<?xml version="1.0" encoding="utf-8" standalone="no"?>
<device schemaVersion="1.1">
  <name>STM32F103x6</name>
  <version>1.0</version>
  <description>STM32F103C4T6,STM32F103C6T6,STM32F103C6U6,STM32F103R4H6,STM32F103R4T6,STM32F103R6H6,STM32F103R6T6,STM32F103T4U6,STM32F103T6U6</description>
  <addressUnitBits>8</addressUnitBits>
  <width>32</width>
  <size>0x20</size>
  <resetValue>0</resetValue>
  <resetMask>0xFFFFFFFF</resetMask>
  <peripherals>
    <peripheral>
      <name>OB</name>
      <baseAddress>0x1ffff800</baseAddress>
      <register>
        <name>RDP</name>
        <addressOffset>0x0</addressOffset>
        <size>0x10</size>
      </register>
      <register>
        <name>USER</name>
        <addressOffset>0x2</addressOffset>
        <size>0x10</size>
      </register>
      <register>
        <name>Data0</name>
        <addressOffset>0x4</addressOffset>
        <size>0x10</size>
      </register>
      <register>
        <name>Data1</name>
        <addressOffset>0x6</addressOffset>
        <size>0x10</size>
      </register>
      <register>
        <name>WRP0</name>
        <addressOffset>0x8</addressOffset>
        <size>0x10</size>
      </register>
      <register>
        <name>WRP1</name>
        <addressOffset>0xa</addressOffset>
        <size>0x10</size>
      </register>
      <register>
        <name>WRP2</name>
        <addressOffset>0xc</addressOffset>
        <size>0x10</size>
      </register>
      <register>
        <name>WRP3</name>
        <addressOffset>0xe</addressOffset>
        <size>0x10</size>
      </register>
    </peripheral>
    <peripheral>
      <name>TIM2</name>
      <baseAddress>0x40000000</baseAddress>
      <register>
        <name>CR1</name>
        <addressOffset>0x0</addressOffset>
        <size>0x20</size>
        <fields>
          <field>
            <name>CEN</name>
            <bitOffset>0</bitOffset>
            <bitWidth>1</bitWidth>
          </field>
          <field>
            <name>UDIS</name>
            <bitOffset>1</bitOffset>
            <bitWidth>1</bitWidth>
          </field>
          <field>
            <name>URS</name>
            <bitOffset>2</bitOffset>
            <bitWidth>1</bitWidth>
          </field>
          <field>
            <name>OPM</name>
            <bitOffset>3</bitOffset>
            <bitWidth>1</bitWidth>
          </field>
          <field>
            <name>DIR</name>
            <bitOffset>4</bitOffset>
            <bitWidth>1</bitWidth>
          </field>
          <field>
            <name>CMS</name>
            <bitOffset>5</bitOffset>
            <bitWidth>2</bitWidth>
          </field>
          <field>
            <name>ARPE</name>
            <bitOffset>7</bitOffset>
            <bitWidth>1</bitWidth>
          </field>
          <field>
            <name>CKD</name>
            <bitOffset>8</bitOffset>
            <bitWidth>2</bitWidth>
          </field>
        </fields>
      </register>
      <register>
        <name>CR2</name>
        <addressOffset>0x4</addressOffset>
        <size>0x20</size>
        <fields>
          <field>
            <name>CCPC</name>
            <bitOffset>0</bitOffset>
            <bitWidth>1</bitWidth>
          </field>
          <field>
            <name>CCUS</name>
            <bitOffset>2</bitOffset>
            <bitWidth>1</bitWidth>
          </field>
          <field>
            <name>CCDS</name>
            <bitOffset>3</bitOffset>
            <bitWidth>1</bitWidth>
          </field>
          <field>
            <name>MMS</name>
            <bitOffset>4</bitOffset>
            <bitWidth>3</bitWidth>
          </field>
          <field>
            <name>TI1S</name>
            <bitOffset>7</bitOffset>
            <bitWidth>1</bitWidth>
          </field>
          <field>
            <name>OIS1</name>
            <bitOffset>8</bitOffset>
            <bitWidth>1</bitWidth>
          </field>
          <field>
            <name>OIS1N</name>
            <bitOffset>9</bitOffset>
            <bitWidth>1</bitWidth>
          </field>
          <field>
            <name>OIS2</name>
            <bitOffset>10</bitOffset>
            <bitWidth>1</bitWidth>
          </field>
          <field>
            <name>OIS2N</name>
            <bitOffset>11</bitOffset>
            <bitWidth>1</bitWidth>
          </field>
          <field>
            <name>OIS3</name>
            <bitOffset>12</bitOffset>
            <bitWidth>1</bitWidth>
          </field>
          <field>
            <name>OIS3N</name>
            <bitOffset>13</bitOffset>
            <bitWidth>1</bitWidth>
          </field>
          <field>
            <name>OIS4</name>
            <bitOffset>14</bitOffset>
            <bitWidth>1</bitWidth>
          </field>
        </fields>
      </register>
      <register>
        <name>SMCR</name>
        <addressOffset>0x8</addressOffset>
        <size>0x20</size>
        <fields>
          <field>
            <name>SMS</name>
            <bitOffset>0</bitOffset>
            <bitWidth>3</bitWidth>
          </field>
          <field>
            <name>TS</name>
            <bitOffset>4</bitOffset>
            <bitWidth>3</bitWidth>
          </field>
          <field>
            <name>MSM</name>
            <bitOffset>7</bitOffset>
            <bitWidth>1</bitWidth>
          </field>
          <field>
            <name>ETF</name>
            <bitOffset>8</bitOffset>
            <bitWidth>4</bitWidth>
          </field>
          <field>
            <name>ETPS</name>
            <bitOffset>12</bitOffset>
            <bitWidth>2</bitWidth>
          </field>
          <field>
            <name>ECE</name>
            <bitOffset>14</bitOffset>
            <bitWidth>1</bitWidth>
          </field>
          <field>
            <name>ETP</name>
            <bitOffset>15</bitOffset>
            <bitWidth>1</bitWidth>
          </field>
        </fields>
      </register>
      <register>
        <name>DIER</name>
        <addressOffset>0xc</addressOffset>
        <size>0x20</size>
        <fields>
          <field>
            <name>UIE</name>
            <bitOffset>0</bitOffset>
            <bitWidth>1</bitWidth>
          </field>
          <field>
            <name>CC1IE</name>
            <bitOffset>1</bitOffset>
            <bitWidth>1</bitWidth>
          </field>
          <field>
            <name>CC2IE</name>
            <bitOffset>2</bitOffset>
            <bitWidth>1</bitWidth>
          </field>
          <field>
            <name>CC3IE</name>
            <bitOffset>3</bitOffset>
            <bitWidth>1</bitWidth>
          </field>
          <field>
            <name>CC4IE</name>
            <bitOffset>4</bitOffset>
            <bitWidth>1</bitWidth>
          </field>
          <field>
            <name>COMIE</name>
            <bitOffset>5</bitOffset>
            <bitWidth>1</bitWidth>
          </field>
          <field>
            <name>TIE</name>
            <bitOffset>6</bitOffset>
            <bitWidth>1</bitWidth>
          </field>
          <field>
            <name>BIE</name>
            <bitOffset>7</bitOffset>
            <bitWidth>1</bitWidth>
          </field>
          <field>
            <name>UDE</name>
            <bitOffset>8</bitOffset>
            <bitWidth>1</bitWidth>
          </field>
          <field>
            <name>CC1DE</name>
            <bitOffset>9</bitOffset>
            <bitWidth>1</bitWidth>
          </field>
          <field>
            <name>CC2DE</name>
            <bitOffset>10</bitOffset>
            <bitWidth>1</bitWidth>
          </field>
          <field>
            <name>CC3DE</name>
            <bitOffset>11</bitOffset>
            <bitWidth>1</bitWidth>
          </field>
          <field>
            <name>CC4DE</name>
            <bitOffset>12</bitOffset>
            <bitWidth>1</bitWidth>
          </field>
          <field>
            <name>COMDE</name>
            <bitOffset>13</bitOffset>
            <bitWidth>1</bitWidth>
          </field>
          <field>
            <name>TDE</name>
            <bitOffset>14</bitOffset>
            <bitWidth>1</bitWidth>
          </field>
        </fields>
      </register>
      <register>
        <name>SR</name>
        <addressOffset>0x10</addressOffset>
        <size>0x20</size>
        <fields>
          <field>
            <name>UIF</name>
            <bitOffset>0</bitOffset>
            <bitWidth>1</bitWidth>
          </field>
          <field>
            <name>CC1IF</name>
            <bitOffset>1</bitOffset>
            <bitWidth>1</bitWidth>
          </field>
          <field>
            <name>CC2IF</name>
            <bitOffset>2</bitOffset>
            <bitWidth>1</bitWidth>
          </field>
          <field>
            <name>CC3IF</name>
            <bitOffset>3</bitOffset>
            <bitWidth>1</bitWidth>
          </field>
          <field>
            <name>CC4IF</name>
            <bitOffset>4</bitOffset>
            <bitWidth>1</bitWidth>
          </field>
          <field>
            <name>COMIF</name>
            <bitOffset>5</bitOffset>
            <bitWidth>1</bitWidth>
          </field>
          <field>
            <name>TIF</name>
            <bitOffset>6</bitOffset>
            <bitWidth>1</bitWidth>
          </field>
          <field>
            <name>BIF</name>
            <bitOffset>7</bitOffset>
            <bitWidth>1</bitWidth>
          </field>
          <field>
            <name>CC1OF</name>
            <bitOffset>9</bitOffset>
            <bitWidth>1</bitWidth>
          </field>
          <field>
            <name>CC2OF</name>
            <bitOffset>10</bitOffset>
            <bitWidth>1</bitWidth>
          </field>
          <field>
            <name>CC3OF</name>
            <bitOffset>11</bitOffset>
            <bitWidth>1</bitWidth>
          </field>
          <field>
            <name>CC4OF</name>
            <bitOffset>12</bitOffset>
            <bitWidth>1</bitWidth>
          </field>
        </fields>
      </register>
      <register>
        <name>EGR</name>
        <addressOffset>0x14</addressOffset>
        <size>0x20</size>
        <fields>
          <field>
            <name>UG</name>
            <bitOffset>0</bitOffset>
            <bitWidth>1</bitWidth>
          </field>
          <field>
            <name>CC1G</name>
            <bitOffset>1</bitOffset>
            <bitWidth>1</bitWidth>
          </field>
          <field>
            <name>CC2G</name>
            <bitOffset>2</bitOffset>
            <bitWidth>1</bitWidth>
          </field>
          <field>
            <name>CC3G</name>
            <bitOffset>3</bitOffset>
            <bitWidth>1</bitWidth>
          </field>
          <field>
            <name>CC4G</name>
            <bitOffset>4</bitOffset>
            <bitWidth>1</bitWidth>
          </field>
          <field>
            <name>COMG</name>
            <bitOffset>5</bitOffset>
            <bitWidth>1</bitWidth>
          </field>
          <field>
            <name>TG</name>
            <bitOffset>6</bitOffset>
            <bitWidth>1</bitWidth>
          </field>
          <field>
            <name>BG</name>
            <bitOffset>7</bitOffset>
            <bitWidth>1</bitWidth>
          </field>
        </fields>
      </register>
      <register>
        <name>CCMR1</name>
        <addressOffset>0x18</addressOffset>
        <size>0x20</size>
        <fields>
          <field>
            <name>CC1S</name>
            <bitOffset>0</bitOffset>
            <bitWidth>2</bitWidth>
          </field>
          <field>
            <name>OC1FE</name>
            <bitOffset>2</bitOffset>
            <bitWidth>1</bitWidth>
          </field>
          <field>
            <name>OC1PE</name>
            <bitOffset>3</bitOffset>
            <bitWidth>1</bitWidth>
          </field>
          <field>
            <name>OC1M</name>
            <bitOffset>4</bitOffset>
            <bitWidth>3</bitWidth>
          </field>
          <field>
            <name>OC1CE</name>
            <bitOffset>7</bitOffset>
            <bitWidth>1</bitWidth>
          </field>
          <field>
            <name>CC2S</name>
            <bitOffset>8</bitOffset>
            <bitWidth>2</bitWidth>
          </field>
          <field>
            <name>OC2FE</name>
            <bitOffset>10</bitOffset>
            <bitWidth>1</bitWidth>
          </field>
          <field>
            <name>OC2PE</name>
            <bitOffset>11</bitOffset>
            <bitWidth>1</bitWidth>
          </field>
          <field>
            <name>OC2M</name>
            <bitOffset>12</bitOffset>
            <bitWidth>3</bitWidth>
          </field>
          <field>
            <name>OC2CE</name>
            <bitOffset>15</bitOffset>
            <bitWidth>1</bitWidth>
          </field>
        </fields>
      </register>
      <register>
        <name>CCMR2</name>
        <addressOffset>0x1c</addressOffset>
        <size>0x20</size>
        <fields>
          <field>
            <name>CC3S</name>
            <bitOffset>0</bitOffset>
            <bitWidth>2</bitWidth>
          </field>
          <field>
            <name>OC3FE</name>
            <bitOffset>2</bitOffset>
            <bitWidth>1</bitWidth>
          </field>
          <field>
            <name>OC3PE</name>
            <bitOffset>3</bitOffset>
            <bitWidth>1</bitWidth>
          </field>
          <field>
            <name>OC3M</name>
            <bitOffset>4</bitOffset>
            <bitWidth>3</bitWidth>
          </field>
          <field>
            <name>OC3CE</name>
            <bitOffset>7</bitOffset>
            <bitWidth>1</bitWidth>
          </field>
          <field>
            <name>CC4S</name>
            <bitOffset>8</bitOffset>
            <bitWidth>2</bitWidth>
          </field>
          <field>
            <name>OC4FE</name>
            <bitOffset>10</bitOffset>
            <bitWidth>1</bitWidth>
          </field>
          <field>
            <name>OC4PE</name>
            <bitOffset>11</bitOffset>
            <bitWidth>1</bitWidth>
          </field>
          <field>
            <name>OC4M</name>
            <bitOffset>12</bitOffset>
            <bitWidth>3</bitWidth>
          </field>
          <field>
            <name>OC4CE</name>
            <bitOffset>15</bitOffset>
            <bitWidth>1</bitWidth>
          </field>
        </fields>
      </register>
      <register>
        <name>CCER</name>
        <addressOffset>0x20</addressOffset>
        <size>0x20</size>
        <fields>
          <field>
            <name>CC1E</name>
            <bitOffset>0</bitOffset>
            <bitWidth>1</bitWidth>
          </field>
          <field>
            <name>CC1P</name>
            <bitOffset>1</bitOffset>
            <bitWidth>1</bitWidth>
          </field>
          <field>
            <name>CC1NE</name>
            <bitOffset>2</bitOffset>
            <bitWidth>1</bitWidth>
          </field>
          <field>
            <name>CC1NP</name>
            <bitOffset>3</bitOffset>
            <bitWidth>1</bitWidth>
          </field>
          <field>
            <name>CC2E</name>
            <bitOffset>4</bitOffset>
            <bitWidth>1</bitWidth>
          </field>
          <field>
            <name>CC2P</name>
            <bitOffset>5</bitOffset>
            <bitWidth>1</bitWidth>
          </field>
          <field>
            <name>CC2NE</name>
            <bitOffset>6</bitOffset>
            <bitWidth>1</bitWidth>
          </field>
          <field>
            <name>CC2NP</name>
            <bitOffset>7</bitOffset>
            <bitWidth>1</bitWidth>
          </field>
          <field>
            <name>CC3E</name>
            <bitOffset>8</bitOffset>
            <bitWidth>1</bitWidth>
          </field>
          <field>
            <name>CC3P</name>
            <bitOffset>9</bitOffset>
            <bitWidth>1</bitWidth>
          </field>
          <field>
            <name>CC3NE</name>
            <bitOffset>10</bitOffset>
            <bitWidth>1</bitWidth>
          </field>
          <field>
            <name>CC3NP</name>
            <bitOffset>11</bitOffset>
            <bitWidth>1</bitWidth>
          </field>
          <field>
            <name>CC4E</name>
            <bitOffset>12</bitOffset>
            <bitWidth>1</bitWidth>
          </field>
          <field>
            <name>CC4P</name>
            <bitOffset>13</bitOffset>
            <bitWidth>1</bitWidth>
          </field>
        </fields>
      </register>
      <register>
        <name>CNT</name>
        <addressOffset>0x24</addressOffset>
        <size>0x20</size>
        <fields>
          <field>
            <name>CNT</name>
            <bitOffset>0</bitOffset>
            <bitWidth>32</bitWidth>
          </field>
        </fields>
      </register>
      <register>
        <name>PSC</name>
        <addressOffset>0x28</addressOffset>
        <size>0x20</size>
        <fields>
          <field>
            <name>PSC</name>
            <bitOffset>0</bitOffset>
            <bitWidth>16</bitWidth>
          </field>
        </fields>
      </register>
      <register>
        <name>ARR</name>
        <addressOffset>0x2c</addressOffset>
        <size>0x20</size>
        <fields>
          <field>
            <name>ARR</name>
            <bitOffset>0</bitOffset>
            <bitWidth>32</bitWidth>
          </field>
        </fields>
      </register>
      <register>
        <name>RCR</name>
        <addressOffset>0x30</addressOffset>
        <size>0x20</size>
        <fields>
          <field>
            <name>REP</name>
            <bitOffset>0</bitOffset>
            <bitWidth>8</bitWidth>
          </field>
        </fields>
      </register>
      <register>
        <name>CCR1</name>
        <addressOffset>0x34</addressOffset>
        <size>0x20</size>
        <fields>
          <field>
            <name>CCR1</name>
            <bitOffset>0</bitOffset>
            <bitWidth>16</bitWidth>
          </field>
        </fields>
      </register>
      <register>
        <name>CCR2</name>
        <addressOffset>0x38</addressOffset>
        <size>0x20</size>
        <fields>
          <field>
            <name>CCR2</name>
            <bitOffset>0</bitOffset>
            <bitWidth>16</bitWidth>
          </field>
        </fields>
      </register>
      <register>
        <name>CCR3</name>
        <addressOffset>0x3c</addressOffset>
        <size>0x20</size>
        <fields>
          <field>
            <name>CCR3</name>
            <bitOffset>0</bitOffset>
            <bitWidth>16</bitWidth>
          </field>
        </fields>
      </register>
      <register>
        <name>CCR4</name>
        <addressOffset>0x40</addressOffset>
        <size>0x20</size>
        <fields>
          <field>
            <name>CCR4</name>
            <bitOffset>0</bitOffset>
            <bitWidth>16</bitWidth>
          </field>
        </fields>
      </register>
      <register>
        <name>BDTR</name>
        <addressOffset>0x44</addressOffset>
        <size>0x20</size>
        <fields>
          <field>
            <name>DTG</name>
            <bitOffset>0</bitOffset>
            <bitWidth>8</bitWidth>
          </field>
          <field>
            <name>LOCK</name>
            <bitOffset>8</bitOffset>
            <bitWidth>2</bitWidth>
          </field>
          <field>
            <name>OSSI</name>
            <bitOffset>10</bitOffset>
            <bitWidth>1</bitWidth>
          </field>
          <field>
            <name>OSSR</name>
            <bitOffset>11</bitOffset>
            <bitWidth>1</bitWidth>
          </field>
          <field>
            <name>BKE</name>
            <bitOffset>12</bitOffset>
            <bitWidth>1</bitWidth>
          </field>
          <field>
            <name>BKP</name>
            <bitOffset>13</bitOffset>
            <bitWidth>1</bitWidth>
          </field>
          <field>
            <name>AOE</name>
            <bitOffset>14</bitOffset>
            <bitWidth>1</bitWidth>
          </field>
          <field>
            <name>MOE</name>
            <bitOffset>15</bitOffset>
            <bitWidth>1</bitWidth>
          </field>
        </fields>
      </register>
      <register>
        <name>DCR</name>
        <addressOffset>0x48</addressOffset>
        <size>0x20</size>
        <fields>
          <field>
            <name>DBA</name>
            <bitOffset>0</bitOffset>
            <bitWidth>5</bitWidth>
          </field>
          <field>
            <name>DBL</name>
            <bitOffset>8</bitOffset>
            <bitWidth>5</bitWidth>
          </field>
        </fields>
      </register>
      <register>
        <name>DMAR</name>
        <addressOffset>0x4c</addressOffset>
        <size>0x20</size>
        <fields>
          <field>
            <name>DMAB</name>
            <bitOffset>0</bitOffset>
            <bitWidth>16</bitWidth>
          </field>
        </fields>
      </register>
      <register>
        <name>OR</name>
        <addressOffset>0x50</addressOffset>
        <size>0x20</size>
      </register>
    </peripheral>
    <peripheral>
      <name>TIM3</name>
      <baseAddress>0x40000400</baseAddress>
      <register>
        <name>CR1</name>
        <addressOffset>0x0</addressOffset>
        <size>0x20</size>
        <fields>
          <field>
            <name>CEN</name>
            <bitOffset>0</bitOffset>
            <bitWidth>1</bitWidth>
          </field>
          <field>
            <name>UDIS</name>
            <bitOffset>1</bitOffset>
            <bitWidth>1</bitWidth>
          </field>
          <field>
            <name>URS</name>
            <bitOffset>2</bitOffset>
            <bitWidth>1</bitWidth>
          </field>
          <field>
            <name>OPM</name>
            <bitOffset>3</bitOffset>
            <bitWidth>1</bitWidth>
          </field>
          <field>
            <name>DIR</name>
            <bitOffset>4</bitOffset>
            <bitWidth>1</bitWidth>
          </field>
          <field>
            <name>CMS</name>
            <bitOffset>5</bitOffset>
            <bitWidth>2</bitWidth>
          </field>
          <field>
            <name>ARPE</name>
            <bitOffset>7</bitOffset>
            <bitWidth>1</bitWidth>
          </field>
          <field>
            <name>CKD</name>
            <bitOffset>8</bitOffset>
            <bitWidth>2</bitWidth>
          </field>
        </fields>
      </register>
      <register>
        <name>CR2</name>
        <addressOffset>0x4</addressOffset>
        <size>0x20</size>
        <fields>
          <field>
            <name>CCPC</name>
            <bitOffset>0</bitOffset>
            <bitWidth>1</bitWidth>
          </field>
          <field>
            <name>CCUS</name>
            <bitOffset>2</bitOffset>
            <bitWidth>1</bitWidth>
          </field>
          <field>
            <name>CCDS</name>
            <bitOffset>3</bitOffset>
            <bitWidth>1</bitWidth>
          </field>
          <field>
            <name>MMS</name>
            <bitOffset>4</bitOffset>
            <bitWidth>3</bitWidth>
          </field>
          <field>
            <name>TI1S</name>
            <bitOffset>7</bitOffset>
            <bitWidth>1</bitWidth>
          </field>
          <field>
            <name>OIS1</name>
            <bitOffset>8</bitOffset>
            <bitWidth>1</bitWidth>
          </field>
          <field>
            <name>OIS1N</name>
            <bitOffset>9</bitOffset>
            <bitWidth>1</bitWidth>
          </field>
          <field>
            <name>OIS2</name>
            <bitOffset>10</bitOffset>
            <bitWidth>1</bitWidth>
          </field>
          <field>
            <name>OIS2N</name>
            <bitOffset>11</bitOffset>
            <bitWidth>1</bitWidth>
          </field>
          <field>
            <name>OIS3</name>
            <bitOffset>12</bitOffset>
            <bitWidth>1</bitWidth>
          </field>
          <field>
            <name>OIS3N</name>
            <bitOffset>13</bitOffset>
            <bitWidth>1</bitWidth>
          </field>
          <field>
            <name>OIS4</name>
            <bitOffset>14</bitOffset>
            <bitWidth>1</bitWidth>
          </field>
        </fields>
      </register>
      <register>
        <name>SMCR</name>
        <addressOffset>0x8</addressOffset>
        <size>0x20</size>
        <fields>
          <field>
            <name>SMS</name>
            <bitOffset>0</bitOffset>
            <bitWidth>3</bitWidth>
          </field>
          <field>
            <name>TS</name>
            <bitOffset>4</bitOffset>
            <bitWidth>3</bitWidth>
          </field>
          <field>
            <name>MSM</name>
            <bitOffset>7</bitOffset>
            <bitWidth>1</bitWidth>
          </field>
          <field>
            <name>ETF</name>
            <bitOffset>8</bitOffset>
            <bitWidth>4</bitWidth>
          </field>
          <field>
            <name>ETPS</name>
            <bitOffset>12</bitOffset>
            <bitWidth>2</bitWidth>
          </field>
          <field>
            <name>ECE</name>
            <bitOffset>14</bitOffset>
            <bitWidth>1</bitWidth>
          </field>
          <field>
            <name>ETP</name>
            <bitOffset>15</bitOffset>
            <bitWidth>1</bitWidth>
          </field>
        </fields>
      </register>
      <register>
        <name>DIER</name>
        <addressOffset>0xc</addressOffset>
        <size>0x20</size>
        <fields>
          <field>
            <name>UIE</name>
            <bitOffset>0</bitOffset>
            <bitWidth>1</bitWidth>
          </field>
          <field>
            <name>CC1IE</name>
            <bitOffset>1</bitOffset>
            <bitWidth>1</bitWidth>
          </field>
          <field>
            <name>CC2IE</name>
            <bitOffset>2</bitOffset>
            <bitWidth>1</bitWidth>
          </field>
          <field>
            <name>CC3IE</name>
            <bitOffset>3</bitOffset>
            <bitWidth>1</bitWidth>
          </field>
          <field>
            <name>CC4IE</name>
            <bitOffset>4</bitOffset>
            <bitWidth>1</bitWidth>
          </field>
          <field>
            <name>COMIE</name>
            <bitOffset>5</bitOffset>
            <bitWidth>1</bitWidth>
          </field>
          <field>
            <name>TIE</name>
            <bitOffset>6</bitOffset>
            <bitWidth>1</bitWidth>
          </field>
          <field>
            <name>BIE</name>
            <bitOffset>7</bitOffset>
            <bitWidth>1</bitWidth>
          </field>
          <field>
            <name>UDE</name>
            <bitOffset>8</bitOffset>
            <bitWidth>1</bitWidth>
          </field>
          <field>
            <name>CC1DE</name>
            <bitOffset>9</bitOffset>
            <bitWidth>1</bitWidth>
          </field>
          <field>
            <name>CC2DE</name>
            <bitOffset>10</bitOffset>
            <bitWidth>1</bitWidth>
          </field>
          <field>
            <name>CC3DE</name>
            <bitOffset>11</bitOffset>
            <bitWidth>1</bitWidth>
          </field>
          <field>
            <name>CC4DE</name>
            <bitOffset>12</bitOffset>
            <bitWidth>1</bitWidth>
          </field>
          <field>
            <name>COMDE</name>
            <bitOffset>13</bitOffset>
            <bitWidth>1</bitWidth>
          </field>
          <field>
            <name>TDE</name>
            <bitOffset>14</bitOffset>
            <bitWidth>1</bitWidth>
          </field>
        </fields>
      </register>
      <register>
        <name>SR</name>
        <addressOffset>0x10</addressOffset>
        <size>0x20</size>
        <fields>
          <field>
            <name>UIF</name>
            <bitOffset>0</bitOffset>
            <bitWidth>1</bitWidth>
          </field>
          <field>
            <name>CC1IF</name>
            <bitOffset>1</bitOffset>
            <bitWidth>1</bitWidth>
          </field>
          <field>
            <name>CC2IF</name>
            <bitOffset>2</bitOffset>
            <bitWidth>1</bitWidth>
          </field>
          <field>
            <name>CC3IF</name>
            <bitOffset>3</bitOffset>
            <bitWidth>1</bitWidth>
          </field>
          <field>
            <name>CC4IF</name>
            <bitOffset>4</bitOffset>
            <bitWidth>1</bitWidth>
          </field>
          <field>
            <name>COMIF</name>
            <bitOffset>5</bitOffset>
            <bitWidth>1</bitWidth>
          </field>
          <field>
            <name>TIF</name>
            <bitOffset>6</bitOffset>
            <bitWidth>1</bitWidth>
          </field>
          <field>
            <name>BIF</name>
            <bitOffset>7</bitOffset>
            <bitWidth>1</bitWidth>
          </field>
          <field>
            <name>CC1OF</name>
            <bitOffset>9</bitOffset>
            <bitWidth>1</bitWidth>
          </field>
          <field>
            <name>CC2OF</name>
            <bitOffset>10</bitOffset>
            <bitWidth>1</bitWidth>
          </field>
          <field>
            <name>CC3OF</name>
            <bitOffset>11</bitOffset>
            <bitWidth>1</bitWidth>
          </field>
          <field>
            <name>CC4OF</name>
            <bitOffset>12</bitOffset>
            <bitWidth>1</bitWidth>
          </field>
        </fields>
      </register>
      <register>
        <name>EGR</name>
        <addressOffset>0x14</addressOffset>
        <size>0x20</size>
        <fields>
          <field>
            <name>UG</name>
            <bitOffset>0</bitOffset>
            <bitWidth>1</bitWidth>
          </field>
          <field>
            <name>CC1G</name>
            <bitOffset>1</bitOffset>
            <bitWidth>1</bitWidth>
          </field>
          <field>
            <name>CC2G</name>
            <bitOffset>2</bitOffset>
            <bitWidth>1</bitWidth>
          </field>
          <field>
            <name>CC3G</name>
            <bitOffset>3</bitOffset>
            <bitWidth>1</bitWidth>
          </field>
          <field>
            <name>CC4G</name>
            <bitOffset>4</bitOffset>
            <bitWidth>1</bitWidth>
          </field>
          <field>
            <name>COMG</name>
            <bitOffset>5</bitOffset>
            <bitWidth>1</bitWidth>
          </field>
          <field>
            <name>TG</name>
            <bitOffset>6</bitOffset>
            <bitWidth>1</bitWidth>
          </field>
          <field>
            <name>BG</name>
            <bitOffset>7</bitOffset>
            <bitWidth>1</bitWidth>
          </field>
        </fields>
      </register>
      <register>
        <name>CCMR1</name>
        <addressOffset>0x18</addressOffset>
        <size>0x20</size>
        <fields>
          <field>
            <name>CC1S</name>
            <bitOffset>0</bitOffset>
            <bitWidth>2</bitWidth>
          </field>
          <field>
            <name>OC1FE</name>
            <bitOffset>2</bitOffset>
            <bitWidth>1</bitWidth>
          </field>
          <field>
            <name>OC1PE</name>
            <bitOffset>3</bitOffset>
            <bitWidth>1</bitWidth>
          </field>
          <field>
            <name>OC1M</name>
            <bitOffset>4</bitOffset>
            <bitWidth>3</bitWidth>
          </field>
          <field>
            <name>OC1CE</name>
            <bitOffset>7</bitOffset>
            <bitWidth>1</bitWidth>
          </field>
          <field>
            <name>CC2S</name>
            <bitOffset>8</bitOffset>
            <bitWidth>2</bitWidth>
          </field>
          <field>
            <name>OC2FE</name>
            <bitOffset>10</bitOffset>
            <bitWidth>1</bitWidth>
          </field>
          <field>
            <name>OC2PE</name>
            <bitOffset>11</bitOffset>
            <bitWidth>1</bitWidth>
          </field>
          <field>
            <name>OC2M</name>
            <bitOffset>12</bitOffset>
            <bitWidth>3</bitWidth>
          </field>
          <field>
            <name>OC2CE</name>
            <bitOffset>15</bitOffset>
            <bitWidth>1</bitWidth>
          </field>
        </fields>
      </register>
      <register>
        <name>CCMR2</name>
        <addressOffset>0x1c</addressOffset>
        <size>0x20</size>
        <fields>
          <field>
            <name>CC3S</name>
            <bitOffset>0</bitOffset>
            <bitWidth>2</bitWidth>
          </field>
          <field>
            <name>OC3FE</name>
            <bitOffset>2</bitOffset>
            <bitWidth>1</bitWidth>
          </field>
          <field>
            <name>OC3PE</name>
            <bitOffset>3</bitOffset>
            <bitWidth>1</bitWidth>
          </field>
          <field>
            <name>OC3M</name>
            <bitOffset>4</bitOffset>
            <bitWidth>3</bitWidth>
          </field>
          <field>
            <name>OC3CE</name>
            <bitOffset>7</bitOffset>
            <bitWidth>1</bitWidth>
          </field>
          <field>
            <name>CC4S</name>
            <bitOffset>8</bitOffset>
            <bitWidth>2</bitWidth>
          </field>
          <field>
            <name>OC4FE</name>
            <bitOffset>10</bitOffset>
            <bitWidth>1</bitWidth>
          </field>
          <field>
            <name>OC4PE</name>
            <bitOffset>11</bitOffset>
            <bitWidth>1</bitWidth>
          </field>
          <field>
            <name>OC4M</name>
            <bitOffset>12</bitOffset>
            <bitWidth>3</bitWidth>
          </field>
          <field>
            <name>OC4CE</name>
            <bitOffset>15</bitOffset>
            <bitWidth>1</bitWidth>
          </field>
        </fields>
      </register>
      <register>
        <name>CCER</name>
        <addressOffset>0x20</addressOffset>
        <size>0x20</size>
        <fields>
          <field>
            <name>CC1E</name>
            <bitOffset>0</bitOffset>
            <bitWidth>1</bitWidth>
          </field>
          <field>
            <name>CC1P</name>
            <bitOffset>1</bitOffset>
            <bitWidth>1</bitWidth>
          </field>
          <field>
            <name>CC1NE</name>
            <bitOffset>2</bitOffset>
            <bitWidth>1</bitWidth>
          </field>
          <field>
            <name>CC1NP</name>
            <bitOffset>3</bitOffset>
            <bitWidth>1</bitWidth>
          </field>
          <field>
            <name>CC2E</name>
            <bitOffset>4</bitOffset>
            <bitWidth>1</bitWidth>
          </field>
          <field>
            <name>CC2P</name>
            <bitOffset>5</bitOffset>
            <bitWidth>1</bitWidth>
          </field>
          <field>
            <name>CC2NE</name>
            <bitOffset>6</bitOffset>
            <bitWidth>1</bitWidth>
          </field>
          <field>
            <name>CC2NP</name>
            <bitOffset>7</bitOffset>
            <bitWidth>1</bitWidth>
          </field>
          <field>
            <name>CC3E</name>
            <bitOffset>8</bitOffset>
            <bitWidth>1</bitWidth>
          </field>
          <field>
            <name>CC3P</name>
            <bitOffset>9</bitOffset>
            <bitWidth>1</bitWidth>
          </field>
          <field>
            <name>CC3NE</name>
            <bitOffset>10</bitOffset>
            <bitWidth>1</bitWidth>
          </field>
          <field>
            <name>CC3NP</name>
            <bitOffset>11</bitOffset>
            <bitWidth>1</bitWidth>
          </field>
          <field>
            <name>CC4E</name>
            <bitOffset>12</bitOffset>
            <bitWidth>1</bitWidth>
          </field>
          <field>
            <name>CC4P</name>
            <bitOffset>13</bitOffset>
            <bitWidth>1</bitWidth>
          </field>
        </fields>
      </register>
      <register>
        <name>CNT</name>
        <addressOffset>0x24</addressOffset>
        <size>0x20</size>
        <fields>
          <field>
            <name>CNT</name>
            <bitOffset>0</bitOffset>
            <bitWidth>32</bitWidth>
          </field>
        </fields>
      </register>
      <register>
        <name>PSC</name>
        <addressOffset>0x28</addressOffset>
        <size>0x20</size>
        <fields>
          <field>
            <name>PSC</name>
            <bitOffset>0</bitOffset>
            <bitWidth>16</bitWidth>
          </field>
        </fields>
      </register>
      <register>
        <name>ARR</name>
        <addressOffset>0x2c</addressOffset>
        <size>0x20</size>
        <fields>
          <field>
            <name>ARR</name>
            <bitOffset>0</bitOffset>
            <bitWidth>32</bitWidth>
          </field>
        </fields>
      </register>
      <register>
        <name>RCR</name>
        <addressOffset>0x30</addressOffset>
        <size>0x20</size>
        <fields>
          <field>
            <name>REP</name>
            <bitOffset>0</bitOffset>
            <bitWidth>8</bitWidth>
          </field>
        </fields>
      </register>
      <register>
        <name>CCR1</name>
        <addressOffset>0x34</addressOffset>
        <size>0x20</size>
        <fields>
          <field>
            <name>CCR1</name>
            <bitOffset>0</bitOffset>
            <bitWidth>16</bitWidth>
          </field>
        </fields>
      </register>
      <register>
        <name>CCR2</name>
        <addressOffset>0x38</addressOffset>
        <size>0x20</size>
        <fields>
          <field>
            <name>CCR2</name>
            <bitOffset>0</bitOffset>
            <bitWidth>16</bitWidth>
          </field>
        </fields>
      </register>
      <register>
        <name>CCR3</name>
        <addressOffset>0x3c</addressOffset>
        <size>0x20</size>
        <fields>
          <field>
            <name>CCR3</name>
            <bitOffset>0</bitOffset>
            <bitWidth>16</bitWidth>
          </field>
        </fields>
      </register>
      <register>
        <name>CCR4</name>
        <addressOffset>0x40</addressOffset>
        <size>0x20</size>
        <fields>
          <field>
            <name>CCR4</name>
            <bitOffset>0</bitOffset>
            <bitWidth>16</bitWidth>
          </field>
        </fields>
      </register>
      <register>
        <name>BDTR</name>
        <addressOffset>0x44</addressOffset>
        <size>0x20</size>
        <fields>
          <field>
            <name>DTG</name>
            <bitOffset>0</bitOffset>
            <bitWidth>8</bitWidth>
          </field>
          <field>
            <name>LOCK</name>
            <bitOffset>8</bitOffset>
            <bitWidth>2</bitWidth>
          </field>
          <field>
            <name>OSSI</name>
            <bitOffset>10</bitOffset>
            <bitWidth>1</bitWidth>
          </field>
          <field>
            <name>OSSR</name>
            <bitOffset>11</bitOffset>
            <bitWidth>1</bitWidth>
          </field>
          <field>
            <name>BKE</name>
            <bitOffset>12</bitOffset>
            <bitWidth>1</bitWidth>
          </field>
          <field>
            <name>BKP</name>
            <bitOffset>13</bitOffset>
            <bitWidth>1</bitWidth>
          </field>
          <field>
            <name>AOE</name>
            <bitOffset>14</bitOffset>
            <bitWidth>1</bitWidth>
          </field>
          <field>
            <name>MOE</name>
            <bitOffset>15</bitOffset>
            <bitWidth>1</bitWidth>
          </field>
        </fields>
      </register>
      <register>
        <name>DCR</name>
        <addressOffset>0x48</addressOffset>
        <size>0x20</size>
        <fields>
          <field>
            <name>DBA</name>
            <bitOffset>0</bitOffset>
            <bitWidth>5</bitWidth>
          </field>
          <field>
            <name>DBL</name>
            <bitOffset>8</bitOffset>
            <bitWidth>5</bitWidth>
          </field>
        </fields>
      </register>
      <register>
        <name>DMAR</name>
        <addressOffset>0x4c</addressOffset>
        <size>0x20</size>
        <fields>
          <field>
            <name>DMAB</name>
            <bitOffset>0</bitOffset>
            <bitWidth>16</bitWidth>
          </field>
        </fields>
      </register>
      <register>
        <name>OR</name>
        <addressOffset>0x50</addressOffset>
        <size>0x20</size>
      </register>
    </peripheral>
    <peripheral>
      <name>RTC</name>
      <baseAddress>0x40002800</baseAddress>
      <register>
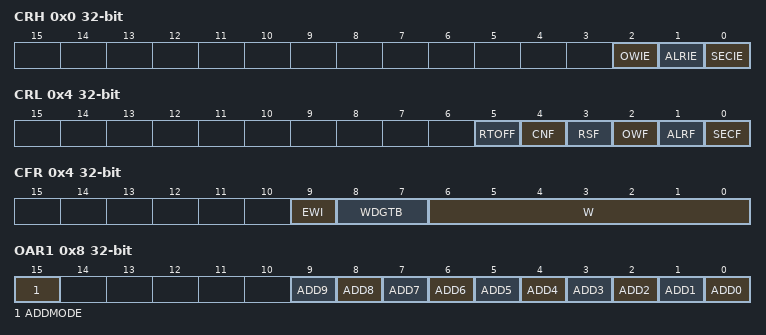
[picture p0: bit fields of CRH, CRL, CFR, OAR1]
        <name>CRH</name>
        <addressOffset>0x0</addressOffset>
        <size>0x20</size>
        <fields>
          <field>
            <name>SECIE</name>
            <bitOffset>0</bitOffset>
            <bitWidth>1</bitWidth>
          </field>
          <field>
            <name>ALRIE</name>
            <bitOffset>1</bitOffset>
            <bitWidth>1</bitWidth>
          </field>
          <field>
            <name>OWIE</name>
            <bitOffset>2</bitOffset>
            <bitWidth>1</bitWidth>
          </field>
        </fields>
      </register>
      <register>
        <name>CRL</name>
        <addressOffset>0x4</addressOffset>
        <size>0x20</size>
        <fields>
          <field>
            <name>SECF</name>
            <bitOffset>0</bitOffset>
            <bitWidth>1</bitWidth>
          </field>
          <field>
            <name>ALRF</name>
            <bitOffset>1</bitOffset>
            <bitWidth>1</bitWidth>
          </field>
          <field>
            <name>OWF</name>
            <bitOffset>2</bitOffset>
            <bitWidth>1</bitWidth>
          </field>
          <field>
            <name>RSF</name>
            <bitOffset>3</bitOffset>
            <bitWidth>1</bitWidth>
          </field>
          <field>
            <name>CNF</name>
            <bitOffset>4</bitOffset>
            <bitWidth>1</bitWidth>
          </field>
          <field>
            <name>RTOFF</name>
            <bitOffset>5</bitOffset>
            <bitWidth>1</bitWidth>
          </field>
        </fields>
      </register>
      <register>
        <name>PRLH</name>
        <addressOffset>0x8</addressOffset>
        <size>0x20</size>
        <fields>
          <field>
            <name>PRL</name>
            <bitOffset>0</bitOffset>
            <bitWidth>4</bitWidth>
          </field>
        </fields>
      </register>
      <register>
        <name>PRLL</name>
        <addressOffset>0xc</addressOffset>
        <size>0x20</size>
        <fields>
          <field>
            <name>PRL</name>
            <bitOffset>0</bitOffset>
            <bitWidth>16</bitWidth>
          </field>
        </fields>
      </register>
      <register>
        <name>DIVH</name>
        <addressOffset>0x10</addressOffset>
        <size>0x20</size>
        <fields>
          <field>
            <name>RTC_DIV</name>
            <bitOffset>0</bitOffset>
            <bitWidth>4</bitWidth>
          </field>
        </fields>
      </register>
      <register>
        <name>DIVL</name>
        <addressOffset>0x14</addressOffset>
        <size>0x20</size>
        <fields>
          <field>
            <name>RTC_DIV</name>
            <bitOffset>0</bitOffset>
            <bitWidth>16</bitWidth>
          </field>
        </fields>
      </register>
      <register>
        <name>CNTH</name>
        <addressOffset>0x18</addressOffset>
        <size>0x20</size>
        <fields>
          <field>
            <name>RTC_CNT</name>
            <bitOffset>0</bitOffset>
            <bitWidth>16</bitWidth>
          </field>
        </fields>
      </register>
      <register>
        <name>CNTL</name>
        <addressOffset>0x1c</addressOffset>
        <size>0x20</size>
        <fields>
          <field>
            <name>RTC_CNT</name>
            <bitOffset>0</bitOffset>
            <bitWidth>16</bitWidth>
          </field>
        </fields>
      </register>
      <register>
        <name>ALRH</name>
        <addressOffset>0x20</addressOffset>
        <size>0x20</size>
        <fields>
          <field>
            <name>RTC_ALR</name>
            <bitOffset>0</bitOffset>
            <bitWidth>16</bitWidth>
          </field>
        </fields>
      </register>
      <register>
        <name>ALRL</name>
        <addressOffset>0x24</addressOffset>
        <size>0x20</size>
        <fields>
          <field>
            <name>RTC_ALR</name>
            <bitOffset>0</bitOffset>
            <bitWidth>16</bitWidth>
          </field>
        </fields>
      </register>
    </peripheral>
    <peripheral>
      <name>WWDG</name>
      <baseAddress>0x40002c00</baseAddress>
      <register>
        <name>CR</name>
        <addressOffset>0x0</addressOffset>
        <size>0x20</size>
        <fields>
          <field>
            <name>T</name>
            <bitOffset>0</bitOffset>
            <bitWidth>7</bitWidth>
          </field>
          <field>
            <name>WDGA</name>
            <bitOffset>7</bitOffset>
            <bitWidth>1</bitWidth>
          </field>
        </fields>
      </register>
      <register>
        <name>CFR</name>
        <addressOffset>0x4</addressOffset>
        <size>0x20</size>
        <fields>
          <field>
            <name>W</name>
            <bitOffset>0</bitOffset>
            <bitWidth>7</bitWidth>
          </field>
          <field>
            <name>WDGTB</name>
            <bitOffset>7</bitOffset>
            <bitWidth>2</bitWidth>
          </field>
          <field>
            <name>EWI</name>
            <bitOffset>9</bitOffset>
            <bitWidth>1</bitWidth>
          </field>
        </fields>
      </register>
      <register>
        <name>SR</name>
        <addressOffset>0x8</addressOffset>
        <size>0x20</size>
        <fields>
          <field>
            <name>EWIF</name>
            <bitOffset>0</bitOffset>
            <bitWidth>1</bitWidth>
          </field>
        </fields>
      </register>
    </peripheral>
    <peripheral>
      <name>IWDG</name>
      <baseAddress>0x40003000</baseAddress>
      <register>
        <name>KR</name>
        <addressOffset>0x0</addressOffset>
        <size>0x20</size>
        <fields>
          <field>
            <name>KEY</name>
            <bitOffset>0</bitOffset>
            <bitWidth>16</bitWidth>
          </field>
        </fields>
      </register>
      <register>
        <name>PR</name>
        <addressOffset>0x4</addressOffset>
        <size>0x20</size>
        <fields>
          <field>
            <name>PR</name>
            <bitOffset>0</bitOffset>
            <bitWidth>3</bitWidth>
          </field>
        </fields>
      </register>
      <register>
        <name>RLR</name>
        <addressOffset>0x8</addressOffset>
        <size>0x20</size>
        <fields>
          <field>
            <name>RL</name>
            <bitOffset>0</bitOffset>
            <bitWidth>12</bitWidth>
          </field>
        </fields>
      </register>
      <register>
        <name>SR</name>
        <addressOffset>0xc</addressOffset>
        <size>0x20</size>
        <fields>
          <field>
            <name>PVU</name>
            <bitOffset>0</bitOffset>
            <bitWidth>1</bitWidth>
          </field>
          <field>
            <name>RVU</name>
            <bitOffset>1</bitOffset>
            <bitWidth>1</bitWidth>
          </field>
        </fields>
      </register>
    </peripheral>
    <peripheral>
      <name>USART2</name>
      <baseAddress>0x40004400</baseAddress>
      <register>
        <name>SR</name>
        <addressOffset>0x0</addressOffset>
        <size>0x20</size>
        <fields>
          <field>
            <name>PE</name>
            <bitOffset>0</bitOffset>
            <bitWidth>1</bitWidth>
          </field>
          <field>
            <name>FE</name>
            <bitOffset>1</bitOffset>
            <bitWidth>1</bitWidth>
          </field>
          <field>
            <name>NE</name>
            <bitOffset>2</bitOffset>
            <bitWidth>1</bitWidth>
          </field>
          <field>
            <name>ORE</name>
            <bitOffset>3</bitOffset>
            <bitWidth>1</bitWidth>
          </field>
          <field>
            <name>IDLE</name>
            <bitOffset>4</bitOffset>
            <bitWidth>1</bitWidth>
          </field>
          <field>
            <name>RXNE</name>
            <bitOffset>5</bitOffset>
            <bitWidth>1</bitWidth>
          </field>
          <field>
            <name>TC</name>
            <bitOffset>6</bitOffset>
            <bitWidth>1</bitWidth>
          </field>
          <field>
            <name>TXE</name>
            <bitOffset>7</bitOffset>
            <bitWidth>1</bitWidth>
          </field>
          <field>
            <name>LBD</name>
            <bitOffset>8</bitOffset>
            <bitWidth>1</bitWidth>
          </field>
          <field>
            <name>CTS</name>
            <bitOffset>9</bitOffset>
            <bitWidth>1</bitWidth>
          </field>
        </fields>
      </register>
      <register>
        <name>DR</name>
        <addressOffset>0x4</addressOffset>
        <size>0x20</size>
        <fields>
          <field>
            <name>DR</name>
            <bitOffset>0</bitOffset>
            <bitWidth>9</bitWidth>
          </field>
        </fields>
      </register>
      <register>
        <name>BRR</name>
        <addressOffset>0x8</addressOffset>
        <size>0x20</size>
        <fields>
          <field>
            <name>DIV_Fraction</name>
            <bitOffset>0</bitOffset>
            <bitWidth>4</bitWidth>
          </field>
          <field>
            <name>DIV_Mantissa</name>
            <bitOffset>4</bitOffset>
            <bitWidth>12</bitWidth>
          </field>
        </fields>
      </register>
      <register>
        <name>CR1</name>
        <addressOffset>0xc</addressOffset>
        <size>0x20</size>
        <fields>
          <field>
            <name>SBK</name>
            <bitOffset>0</bitOffset>
            <bitWidth>1</bitWidth>
          </field>
          <field>
            <name>RWU</name>
            <bitOffset>1</bitOffset>
            <bitWidth>1</bitWidth>
          </field>
          <field>
            <name>RE</name>
            <bitOffset>2</bitOffset>
            <bitWidth>1</bitWidth>
          </field>
          <field>
            <name>TE</name>
            <bitOffset>3</bitOffset>
            <bitWidth>1</bitWidth>
          </field>
          <field>
            <name>IDLEIE</name>
            <bitOffset>4</bitOffset>
            <bitWidth>1</bitWidth>
          </field>
          <field>
            <name>RXNEIE</name>
            <bitOffset>5</bitOffset>
            <bitWidth>1</bitWidth>
          </field>
          <field>
            <name>TCIE</name>
            <bitOffset>6</bitOffset>
            <bitWidth>1</bitWidth>
          </field>
          <field>
            <name>TXEIE</name>
            <bitOffset>7</bitOffset>
            <bitWidth>1</bitWidth>
          </field>
          <field>
            <name>PEIE</name>
            <bitOffset>8</bitOffset>
            <bitWidth>1</bitWidth>
          </field>
          <field>
            <name>PS</name>
            <bitOffset>9</bitOffset>
            <bitWidth>1</bitWidth>
          </field>
          <field>
            <name>PCE</name>
            <bitOffset>10</bitOffset>
            <bitWidth>1</bitWidth>
          </field>
          <field>
            <name>WAKE</name>
            <bitOffset>11</bitOffset>
            <bitWidth>1</bitWidth>
          </field>
          <field>
            <name>M</name>
            <bitOffset>12</bitOffset>
            <bitWidth>1</bitWidth>
          </field>
          <field>
            <name>UE</name>
            <bitOffset>13</bitOffset>
            <bitWidth>1</bitWidth>
          </field>
        </fields>
      </register>
      <register>
        <name>CR2</name>
        <addressOffset>0x10</addressOffset>
        <size>0x20</size>
        <fields>
          <field>
            <name>ADD</name>
            <bitOffset>0</bitOffset>
            <bitWidth>4</bitWidth>
          </field>
          <field>
            <name>LBDL</name>
            <bitOffset>5</bitOffset>
            <bitWidth>1</bitWidth>
          </field>
          <field>
            <name>LBDIE</name>
            <bitOffset>6</bitOffset>
            <bitWidth>1</bitWidth>
          </field>
          <field>
            <name>LBCL</name>
            <bitOffset>8</bitOffset>
            <bitWidth>1</bitWidth>
          </field>
          <field>
            <name>CPHA</name>
            <bitOffset>9</bitOffset>
            <bitWidth>1</bitWidth>
          </field>
          <field>
            <name>CPOL</name>
            <bitOffset>10</bitOffset>
            <bitWidth>1</bitWidth>
          </field>
          <field>
            <name>CLKEN</name>
            <bitOffset>11</bitOffset>
            <bitWidth>1</bitWidth>
          </field>
          <field>
            <name>STOP</name>
            <bitOffset>12</bitOffset>
            <bitWidth>2</bitWidth>
          </field>
          <field>
            <name>LINEN</name>
            <bitOffset>14</bitOffset>
            <bitWidth>1</bitWidth>
          </field>
        </fields>
      </register>
      <register>
        <name>CR3</name>
        <addressOffset>0x14</addressOffset>
        <size>0x20</size>
        <fields>
          <field>
            <name>EIE</name>
            <bitOffset>0</bitOffset>
            <bitWidth>1</bitWidth>
          </field>
          <field>
            <name>IREN</name>
            <bitOffset>1</bitOffset>
            <bitWidth>1</bitWidth>
          </field>
          <field>
            <name>IRLP</name>
            <bitOffset>2</bitOffset>
            <bitWidth>1</bitWidth>
          </field>
          <field>
            <name>HDSEL</name>
            <bitOffset>3</bitOffset>
            <bitWidth>1</bitWidth>
          </field>
          <field>
            <name>NACK</name>
            <bitOffset>4</bitOffset>
            <bitWidth>1</bitWidth>
          </field>
          <field>
            <name>SCEN</name>
            <bitOffset>5</bitOffset>
            <bitWidth>1</bitWidth>
          </field>
          <field>
            <name>DMAR</name>
            <bitOffset>6</bitOffset>
            <bitWidth>1</bitWidth>
          </field>
          <field>
            <name>DMAT</name>
            <bitOffset>7</bitOffset>
            <bitWidth>1</bitWidth>
          </field>
          <field>
            <name>RTSE</name>
            <bitOffset>8</bitOffset>
            <bitWidth>1</bitWidth>
          </field>
          <field>
            <name>CTSE</name>
            <bitOffset>9</bitOffset>
            <bitWidth>1</bitWidth>
          </field>
          <field>
            <name>CTSIE</name>
            <bitOffset>10</bitOffset>
            <bitWidth>1</bitWidth>
          </field>
        </fields>
      </register>
      <register>
        <name>GTPR</name>
        <addressOffset>0x18</addressOffset>
        <size>0x20</size>
        <fields>
          <field>
            <name>PSC</name>
            <bitOffset>0</bitOffset>
            <bitWidth>8</bitWidth>
          </field>
          <field>
            <name>GT</name>
            <bitOffset>8</bitOffset>
            <bitWidth>8</bitWidth>
          </field>
        </fields>
      </register>
    </peripheral>
    <peripheral>
      <name>I2C1</name>
      <baseAddress>0x40005400</baseAddress>
      <register>
        <name>CR1</name>
        <addressOffset>0x0</addressOffset>
        <size>0x20</size>
        <fields>
          <field>
            <name>PE</name>
            <bitOffset>0</bitOffset>
            <bitWidth>1</bitWidth>
          </field>
          <field>
            <name>SMBUS</name>
            <bitOffset>1</bitOffset>
            <bitWidth>1</bitWidth>
          </field>
          <field>
            <name>SMBTYPE</name>
            <bitOffset>3</bitOffset>
            <bitWidth>1</bitWidth>
          </field>
          <field>
            <name>ENARP</name>
            <bitOffset>4</bitOffset>
            <bitWidth>1</bitWidth>
          </field>
          <field>
            <name>ENPEC</name>
            <bitOffset>5</bitOffset>
            <bitWidth>1</bitWidth>
          </field>
          <field>
            <name>ENGC</name>
            <bitOffset>6</bitOffset>
            <bitWidth>1</bitWidth>
          </field>
          <field>
            <name>NOSTRETCH</name>
            <bitOffset>7</bitOffset>
            <bitWidth>1</bitWidth>
          </field>
          <field>
            <name>START</name>
            <bitOffset>8</bitOffset>
            <bitWidth>1</bitWidth>
          </field>
          <field>
            <name>STOP</name>
            <bitOffset>9</bitOffset>
            <bitWidth>1</bitWidth>
          </field>
          <field>
            <name>ACK</name>
            <bitOffset>10</bitOffset>
            <bitWidth>1</bitWidth>
          </field>
          <field>
            <name>POS</name>
            <bitOffset>11</bitOffset>
            <bitWidth>1</bitWidth>
          </field>
          <field>
            <name>PEC</name>
            <bitOffset>12</bitOffset>
            <bitWidth>1</bitWidth>
          </field>
          <field>
            <name>ALERT</name>
            <bitOffset>13</bitOffset>
            <bitWidth>1</bitWidth>
          </field>
          <field>
            <name>SWRST</name>
            <bitOffset>15</bitOffset>
            <bitWidth>1</bitWidth>
          </field>
        </fields>
      </register>
      <register>
        <name>CR2</name>
        <addressOffset>0x4</addressOffset>
        <size>0x20</size>
        <fields>
          <field>
            <name>FREQ</name>
            <bitOffset>0</bitOffset>
            <bitWidth>6</bitWidth>
          </field>
          <field>
            <name>ITERREN</name>
            <bitOffset>8</bitOffset>
            <bitWidth>1</bitWidth>
          </field>
          <field>
            <name>ITEVTEN</name>
            <bitOffset>9</bitOffset>
            <bitWidth>1</bitWidth>
          </field>
          <field>
            <name>ITBUFEN</name>
            <bitOffset>10</bitOffset>
            <bitWidth>1</bitWidth>
          </field>
          <field>
            <name>DMAEN</name>
            <bitOffset>11</bitOffset>
            <bitWidth>1</bitWidth>
          </field>
          <field>
            <name>LAST</name>
            <bitOffset>12</bitOffset>
            <bitWidth>1</bitWidth>
          </field>
        </fields>
      </register>
      <register>
        <name>OAR1</name>
        <addressOffset>0x8</addressOffset>
        <size>0x20</size>
        <fields>
          <field>
            <name>ADD0</name>
            <bitOffset>0</bitOffset>
            <bitWidth>1</bitWidth>
          </field>
          <field>
            <name>ADD1</name>
            <bitOffset>1</bitOffset>
            <bitWidth>1</bitWidth>
          </field>
          <field>
            <name>ADD2</name>
            <bitOffset>2</bitOffset>
            <bitWidth>1</bitWidth>
          </field>
          <field>
            <name>ADD3</name>
            <bitOffset>3</bitOffset>
            <bitWidth>1</bitWidth>
          </field>
          <field>
            <name>ADD4</name>
            <bitOffset>4</bitOffset>
            <bitWidth>1</bitWidth>
          </field>
          <field>
            <name>ADD5</name>
            <bitOffset>5</bitOffset>
            <bitWidth>1</bitWidth>
          </field>
          <field>
            <name>ADD6</name>
            <bitOffset>6</bitOffset>
            <bitWidth>1</bitWidth>
          </field>
          <field>
            <name>ADD7</name>
            <bitOffset>7</bitOffset>
            <bitWidth>1</bitWidth>
          </field>
          <field>
            <name>ADD8</name>
            <bitOffset>8</bitOffset>
            <bitWidth>1</bitWidth>
          </field>
          <field>
            <name>ADD9</name>
            <bitOffset>9</bitOffset>
            <bitWidth>1</bitWidth>
          </field>
          <field>
            <name>ADDMODE</name>
            <bitOffset>15</bitOffset>
            <bitWidth>1</bitWidth>
          </field>
        </fields>
      </register>
      <register>
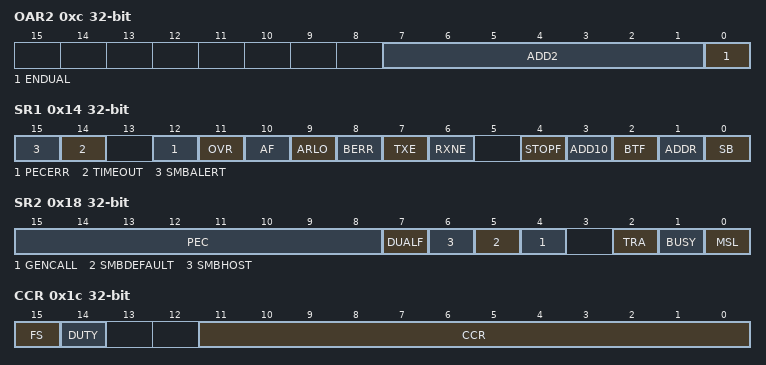
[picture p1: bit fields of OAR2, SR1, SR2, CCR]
        <name>OAR2</name>
        <addressOffset>0xc</addressOffset>
        <size>0x20</size>
        <fields>
          <field>
            <name>ENDUAL</name>
            <bitOffset>0</bitOffset>
            <bitWidth>1</bitWidth>
          </field>
          <field>
            <name>ADD2</name>
            <bitOffset>1</bitOffset>
            <bitWidth>7</bitWidth>
          </field>
        </fields>
      </register>
      <register>
        <name>DR</name>
        <addressOffset>0x10</addressOffset>
        <size>0x20</size>
        <fields>
          <field>
            <name>DR</name>
            <bitOffset>0</bitOffset>
            <bitWidth>8</bitWidth>
          </field>
        </fields>
      </register>
      <register>
        <name>SR1</name>
        <addressOffset>0x14</addressOffset>
        <size>0x20</size>
        <fields>
          <field>
            <name>SB</name>
            <bitOffset>0</bitOffset>
            <bitWidth>1</bitWidth>
          </field>
          <field>
            <name>ADDR</name>
            <bitOffset>1</bitOffset>
            <bitWidth>1</bitWidth>
          </field>
          <field>
            <name>BTF</name>
            <bitOffset>2</bitOffset>
            <bitWidth>1</bitWidth>
          </field>
          <field>
            <name>ADD10</name>
            <bitOffset>3</bitOffset>
            <bitWidth>1</bitWidth>
          </field>
          <field>
            <name>STOPF</name>
            <bitOffset>4</bitOffset>
            <bitWidth>1</bitWidth>
          </field>
          <field>
            <name>RXNE</name>
            <bitOffset>6</bitOffset>
            <bitWidth>1</bitWidth>
          </field>
          <field>
            <name>TXE</name>
            <bitOffset>7</bitOffset>
            <bitWidth>1</bitWidth>
          </field>
          <field>
            <name>BERR</name>
            <bitOffset>8</bitOffset>
            <bitWidth>1</bitWidth>
          </field>
          <field>
            <name>ARLO</name>
            <bitOffset>9</bitOffset>
            <bitWidth>1</bitWidth>
          </field>
          <field>
            <name>AF</name>
            <bitOffset>10</bitOffset>
            <bitWidth>1</bitWidth>
          </field>
          <field>
            <name>OVR</name>
            <bitOffset>11</bitOffset>
            <bitWidth>1</bitWidth>
          </field>
          <field>
            <name>PECERR</name>
            <bitOffset>12</bitOffset>
            <bitWidth>1</bitWidth>
          </field>
          <field>
            <name>TIMEOUT</name>
            <bitOffset>14</bitOffset>
            <bitWidth>1</bitWidth>
          </field>
          <field>
            <name>SMBALERT</name>
            <bitOffset>15</bitOffset>
            <bitWidth>1</bitWidth>
          </field>
        </fields>
      </register>
      <register>
        <name>SR2</name>
        <addressOffset>0x18</addressOffset>
        <size>0x20</size>
        <fields>
          <field>
            <name>MSL</name>
            <bitOffset>0</bitOffset>
            <bitWidth>1</bitWidth>
          </field>
          <field>
            <name>BUSY</name>
            <bitOffset>1</bitOffset>
            <bitWidth>1</bitWidth>
          </field>
          <field>
            <name>TRA</name>
            <bitOffset>2</bitOffset>
            <bitWidth>1</bitWidth>
          </field>
          <field>
            <name>GENCALL</name>
            <bitOffset>4</bitOffset>
            <bitWidth>1</bitWidth>
          </field>
          <field>
            <name>SMBDEFAULT</name>
            <bitOffset>5</bitOffset>
            <bitWidth>1</bitWidth>
          </field>
          <field>
            <name>SMBHOST</name>
            <bitOffset>6</bitOffset>
            <bitWidth>1</bitWidth>
          </field>
          <field>
            <name>DUALF</name>
            <bitOffset>7</bitOffset>
            <bitWidth>1</bitWidth>
          </field>
          <field>
            <name>PEC</name>
            <bitOffset>8</bitOffset>
            <bitWidth>8</bitWidth>
          </field>
        </fields>
      </register>
      <register>
        <name>CCR</name>
        <addressOffset>0x1c</addressOffset>
        <size>0x20</size>
        <fields>
          <field>
            <name>CCR</name>
            <bitOffset>0</bitOffset>
            <bitWidth>12</bitWidth>
          </field>
          <field>
            <name>DUTY</name>
            <bitOffset>14</bitOffset>
            <bitWidth>1</bitWidth>
          </field>
          <field>
            <name>FS</name>
            <bitOffset>15</bitOffset>
            <bitWidth>1</bitWidth>
          </field>
        </fields>
      </register>
      <register>
        <name>TRISE</name>
        <addressOffset>0x20</addressOffset>
        <size>0x20</size>
        <fields>
          <field>
            <name>TRISE</name>
            <bitOffset>0</bitOffset>
            <bitWidth>6</bitWidth>
          </field>
        </fields>
      </register>
    </peripheral>
    <peripheral>
      <name>USB</name>
      <baseAddress>0x40005c00</baseAddress>
      <register>
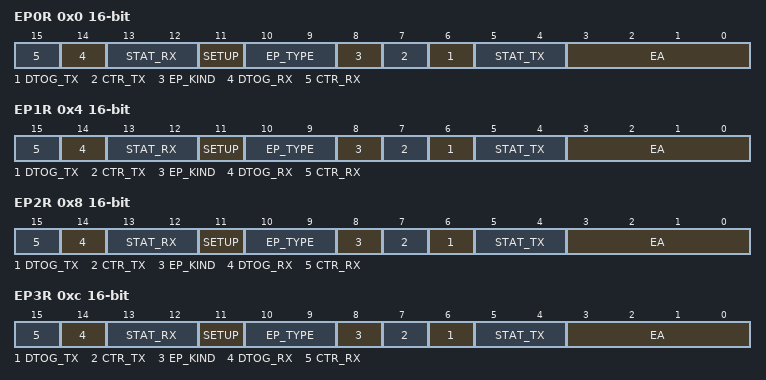
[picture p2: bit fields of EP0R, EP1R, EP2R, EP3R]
        <name>EP0R</name>
        <addressOffset>0x0</addressOffset>
        <size>0x10</size>
        <fields>
          <field>
            <name>EA</name>
            <bitOffset>0</bitOffset>
            <bitWidth>4</bitWidth>
          </field>
          <field>
            <name>STAT_TX</name>
            <bitOffset>4</bitOffset>
            <bitWidth>2</bitWidth>
          </field>
          <field>
            <name>DTOG_TX</name>
            <bitOffset>6</bitOffset>
            <bitWidth>1</bitWidth>
          </field>
          <field>
            <name>CTR_TX</name>
            <bitOffset>7</bitOffset>
            <bitWidth>1</bitWidth>
          </field>
          <field>
            <name>EP_KIND</name>
            <bitOffset>8</bitOffset>
            <bitWidth>1</bitWidth>
          </field>
          <field>
            <name>EP_TYPE</name>
            <bitOffset>9</bitOffset>
            <bitWidth>2</bitWidth>
          </field>
          <field>
            <name>SETUP</name>
            <bitOffset>11</bitOffset>
            <bitWidth>1</bitWidth>
          </field>
          <field>
            <name>STAT_RX</name>
            <bitOffset>12</bitOffset>
            <bitWidth>2</bitWidth>
          </field>
          <field>
            <name>DTOG_RX</name>
            <bitOffset>14</bitOffset>
            <bitWidth>1</bitWidth>
          </field>
          <field>
            <name>CTR_RX</name>
            <bitOffset>15</bitOffset>
            <bitWidth>1</bitWidth>
          </field>
        </fields>
      </register>
      <register>
        <name>EP1R</name>
        <addressOffset>0x4</addressOffset>
        <size>0x10</size>
        <fields>
          <field>
            <name>EA</name>
            <bitOffset>0</bitOffset>
            <bitWidth>4</bitWidth>
          </field>
          <field>
            <name>STAT_TX</name>
            <bitOffset>4</bitOffset>
            <bitWidth>2</bitWidth>
          </field>
          <field>
            <name>DTOG_TX</name>
            <bitOffset>6</bitOffset>
            <bitWidth>1</bitWidth>
          </field>
          <field>
            <name>CTR_TX</name>
            <bitOffset>7</bitOffset>
            <bitWidth>1</bitWidth>
          </field>
          <field>
            <name>EP_KIND</name>
            <bitOffset>8</bitOffset>
            <bitWidth>1</bitWidth>
          </field>
          <field>
            <name>EP_TYPE</name>
            <bitOffset>9</bitOffset>
            <bitWidth>2</bitWidth>
          </field>
          <field>
            <name>SETUP</name>
            <bitOffset>11</bitOffset>
            <bitWidth>1</bitWidth>
          </field>
          <field>
            <name>STAT_RX</name>
            <bitOffset>12</bitOffset>
            <bitWidth>2</bitWidth>
          </field>
          <field>
            <name>DTOG_RX</name>
            <bitOffset>14</bitOffset>
            <bitWidth>1</bitWidth>
          </field>
          <field>
            <name>CTR_RX</name>
            <bitOffset>15</bitOffset>
            <bitWidth>1</bitWidth>
          </field>
        </fields>
      </register>
      <register>
        <name>EP2R</name>
        <addressOffset>0x8</addressOffset>
        <size>0x10</size>
        <fields>
          <field>
            <name>EA</name>
            <bitOffset>0</bitOffset>
            <bitWidth>4</bitWidth>
          </field>
          <field>
            <name>STAT_TX</name>
            <bitOffset>4</bitOffset>
            <bitWidth>2</bitWidth>
          </field>
          <field>
            <name>DTOG_TX</name>
            <bitOffset>6</bitOffset>
            <bitWidth>1</bitWidth>
          </field>
          <field>
            <name>CTR_TX</name>
            <bitOffset>7</bitOffset>
            <bitWidth>1</bitWidth>
          </field>
          <field>
            <name>EP_KIND</name>
            <bitOffset>8</bitOffset>
            <bitWidth>1</bitWidth>
          </field>
          <field>
            <name>EP_TYPE</name>
            <bitOffset>9</bitOffset>
            <bitWidth>2</bitWidth>
          </field>
          <field>
            <name>SETUP</name>
            <bitOffset>11</bitOffset>
            <bitWidth>1</bitWidth>
          </field>
          <field>
            <name>STAT_RX</name>
            <bitOffset>12</bitOffset>
            <bitWidth>2</bitWidth>
          </field>
          <field>
            <name>DTOG_RX</name>
            <bitOffset>14</bitOffset>
            <bitWidth>1</bitWidth>
          </field>
          <field>
            <name>CTR_RX</name>
            <bitOffset>15</bitOffset>
            <bitWidth>1</bitWidth>
          </field>
        </fields>
      </register>
      <register>
        <name>EP3R</name>
        <addressOffset>0xc</addressOffset>
        <size>0x10</size>
        <fields>
          <field>
            <name>EA</name>
            <bitOffset>0</bitOffset>
            <bitWidth>4</bitWidth>
          </field>
          <field>
            <name>STAT_TX</name>
            <bitOffset>4</bitOffset>
            <bitWidth>2</bitWidth>
          </field>
          <field>
            <name>DTOG_TX</name>
            <bitOffset>6</bitOffset>
            <bitWidth>1</bitWidth>
          </field>
          <field>
            <name>CTR_TX</name>
            <bitOffset>7</bitOffset>
            <bitWidth>1</bitWidth>
          </field>
          <field>
            <name>EP_KIND</name>
            <bitOffset>8</bitOffset>
            <bitWidth>1</bitWidth>
          </field>
          <field>
            <name>EP_TYPE</name>
            <bitOffset>9</bitOffset>
            <bitWidth>2</bitWidth>
          </field>
          <field>
            <name>SETUP</name>
            <bitOffset>11</bitOffset>
            <bitWidth>1</bitWidth>
          </field>
          <field>
            <name>STAT_RX</name>
            <bitOffset>12</bitOffset>
            <bitWidth>2</bitWidth>
          </field>
          <field>
            <name>DTOG_RX</name>
            <bitOffset>14</bitOffset>
            <bitWidth>1</bitWidth>
          </field>
          <field>
            <name>CTR_RX</name>
            <bitOffset>15</bitOffset>
            <bitWidth>1</bitWidth>
          </field>
        </fields>
      </register>
      <register>
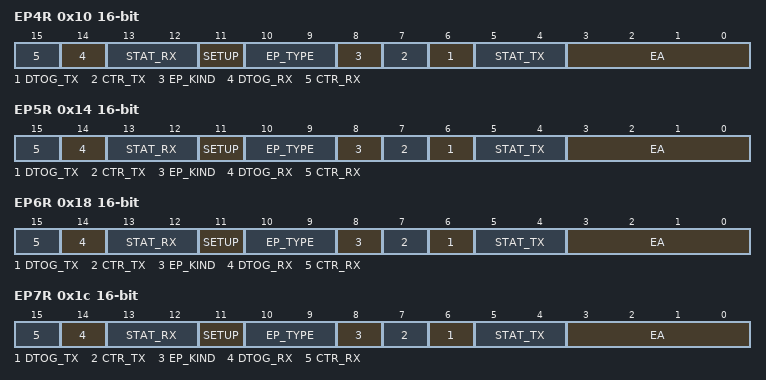
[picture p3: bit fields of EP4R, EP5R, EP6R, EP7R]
        <name>EP4R</name>
        <addressOffset>0x10</addressOffset>
        <size>0x10</size>
        <fields>
          <field>
            <name>EA</name>
            <bitOffset>0</bitOffset>
            <bitWidth>4</bitWidth>
          </field>
          <field>
            <name>STAT_TX</name>
            <bitOffset>4</bitOffset>
            <bitWidth>2</bitWidth>
          </field>
          <field>
            <name>DTOG_TX</name>
            <bitOffset>6</bitOffset>
            <bitWidth>1</bitWidth>
          </field>
          <field>
            <name>CTR_TX</name>
            <bitOffset>7</bitOffset>
            <bitWidth>1</bitWidth>
          </field>
          <field>
            <name>EP_KIND</name>
            <bitOffset>8</bitOffset>
            <bitWidth>1</bitWidth>
          </field>
          <field>
            <name>EP_TYPE</name>
            <bitOffset>9</bitOffset>
            <bitWidth>2</bitWidth>
          </field>
          <field>
            <name>SETUP</name>
            <bitOffset>11</bitOffset>
            <bitWidth>1</bitWidth>
          </field>
          <field>
            <name>STAT_RX</name>
            <bitOffset>12</bitOffset>
            <bitWidth>2</bitWidth>
          </field>
          <field>
            <name>DTOG_RX</name>
            <bitOffset>14</bitOffset>
            <bitWidth>1</bitWidth>
          </field>
          <field>
            <name>CTR_RX</name>
            <bitOffset>15</bitOffset>
            <bitWidth>1</bitWidth>
          </field>
        </fields>
      </register>
      <register>
        <name>EP5R</name>
        <addressOffset>0x14</addressOffset>
        <size>0x10</size>
        <fields>
          <field>
            <name>EA</name>
            <bitOffset>0</bitOffset>
            <bitWidth>4</bitWidth>
          </field>
          <field>
            <name>STAT_TX</name>
            <bitOffset>4</bitOffset>
            <bitWidth>2</bitWidth>
          </field>
          <field>
            <name>DTOG_TX</name>
            <bitOffset>6</bitOffset>
            <bitWidth>1</bitWidth>
          </field>
          <field>
            <name>CTR_TX</name>
            <bitOffset>7</bitOffset>
            <bitWidth>1</bitWidth>
          </field>
          <field>
            <name>EP_KIND</name>
            <bitOffset>8</bitOffset>
            <bitWidth>1</bitWidth>
          </field>
          <field>
            <name>EP_TYPE</name>
            <bitOffset>9</bitOffset>
            <bitWidth>2</bitWidth>
          </field>
          <field>
            <name>SETUP</name>
            <bitOffset>11</bitOffset>
            <bitWidth>1</bitWidth>
          </field>
          <field>
            <name>STAT_RX</name>
            <bitOffset>12</bitOffset>
            <bitWidth>2</bitWidth>
          </field>
          <field>
            <name>DTOG_RX</name>
            <bitOffset>14</bitOffset>
            <bitWidth>1</bitWidth>
          </field>
          <field>
            <name>CTR_RX</name>
            <bitOffset>15</bitOffset>
            <bitWidth>1</bitWidth>
          </field>
        </fields>
      </register>
      <register>
        <name>EP6R</name>
        <addressOffset>0x18</addressOffset>
        <size>0x10</size>
        <fields>
          <field>
            <name>EA</name>
            <bitOffset>0</bitOffset>
            <bitWidth>4</bitWidth>
          </field>
          <field>
            <name>STAT_TX</name>
            <bitOffset>4</bitOffset>
            <bitWidth>2</bitWidth>
          </field>
          <field>
            <name>DTOG_TX</name>
            <bitOffset>6</bitOffset>
            <bitWidth>1</bitWidth>
          </field>
          <field>
            <name>CTR_TX</name>
            <bitOffset>7</bitOffset>
            <bitWidth>1</bitWidth>
          </field>
          <field>
            <name>EP_KIND</name>
            <bitOffset>8</bitOffset>
            <bitWidth>1</bitWidth>
          </field>
          <field>
            <name>EP_TYPE</name>
            <bitOffset>9</bitOffset>
            <bitWidth>2</bitWidth>
          </field>
          <field>
            <name>SETUP</name>
            <bitOffset>11</bitOffset>
            <bitWidth>1</bitWidth>
          </field>
          <field>
            <name>STAT_RX</name>
            <bitOffset>12</bitOffset>
            <bitWidth>2</bitWidth>
          </field>
          <field>
            <name>DTOG_RX</name>
            <bitOffset>14</bitOffset>
            <bitWidth>1</bitWidth>
          </field>
          <field>
            <name>CTR_RX</name>
            <bitOffset>15</bitOffset>
            <bitWidth>1</bitWidth>
          </field>
        </fields>
      </register>
      <register>
        <name>EP7R</name>
        <addressOffset>0x1c</addressOffset>
        <size>0x10</size>
        <fields>
          <field>
            <name>EA</name>
            <bitOffset>0</bitOffset>
            <bitWidth>4</bitWidth>
          </field>
          <field>
            <name>STAT_TX</name>
            <bitOffset>4</bitOffset>
            <bitWidth>2</bitWidth>
          </field>
          <field>
            <name>DTOG_TX</name>
            <bitOffset>6</bitOffset>
            <bitWidth>1</bitWidth>
          </field>
          <field>
            <name>CTR_TX</name>
            <bitOffset>7</bitOffset>
            <bitWidth>1</bitWidth>
          </field>
          <field>
            <name>EP_KIND</name>
            <bitOffset>8</bitOffset>
            <bitWidth>1</bitWidth>
          </field>
          <field>
            <name>EP_TYPE</name>
            <bitOffset>9</bitOffset>
            <bitWidth>2</bitWidth>
          </field>
          <field>
            <name>SETUP</name>
            <bitOffset>11</bitOffset>
            <bitWidth>1</bitWidth>
          </field>
          <field>
            <name>STAT_RX</name>
            <bitOffset>12</bitOffset>
            <bitWidth>2</bitWidth>
          </field>
          <field>
            <name>DTOG_RX</name>
            <bitOffset>14</bitOffset>
            <bitWidth>1</bitWidth>
          </field>
          <field>
            <name>CTR_RX</name>
            <bitOffset>15</bitOffset>
            <bitWidth>1</bitWidth>
          </field>
        </fields>
      </register>
      <register>
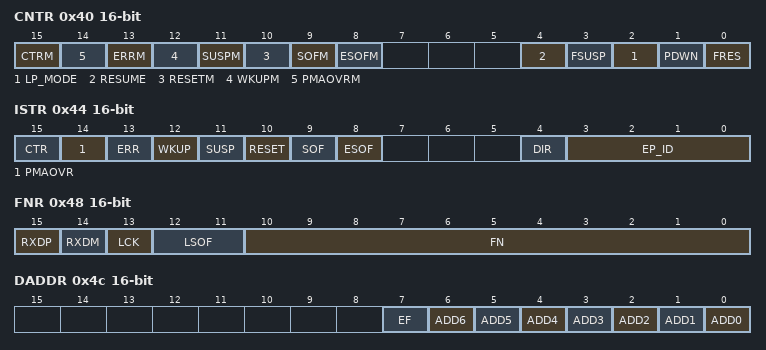
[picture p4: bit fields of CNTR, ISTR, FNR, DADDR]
        <name>CNTR</name>
        <addressOffset>0x40</addressOffset>
        <size>0x10</size>
        <fields>
          <field>
            <name>FRES</name>
            <bitOffset>0</bitOffset>
            <bitWidth>1</bitWidth>
          </field>
          <field>
            <name>PDWN</name>
            <bitOffset>1</bitOffset>
            <bitWidth>1</bitWidth>
          </field>
          <field>
            <name>LP_MODE</name>
            <bitOffset>2</bitOffset>
            <bitWidth>1</bitWidth>
          </field>
          <field>
            <name>FSUSP</name>
            <bitOffset>3</bitOffset>
            <bitWidth>1</bitWidth>
          </field>
          <field>
            <name>RESUME</name>
            <bitOffset>4</bitOffset>
            <bitWidth>1</bitWidth>
          </field>
          <field>
            <name>ESOFM</name>
            <bitOffset>8</bitOffset>
            <bitWidth>1</bitWidth>
          </field>
          <field>
            <name>SOFM</name>
            <bitOffset>9</bitOffset>
            <bitWidth>1</bitWidth>
          </field>
          <field>
            <name>RESETM</name>
            <bitOffset>10</bitOffset>
            <bitWidth>1</bitWidth>
          </field>
          <field>
            <name>SUSPM</name>
            <bitOffset>11</bitOffset>
            <bitWidth>1</bitWidth>
          </field>
          <field>
            <name>WKUPM</name>
            <bitOffset>12</bitOffset>
            <bitWidth>1</bitWidth>
          </field>
          <field>
            <name>ERRM</name>
            <bitOffset>13</bitOffset>
            <bitWidth>1</bitWidth>
          </field>
          <field>
            <name>PMAOVRM</name>
            <bitOffset>14</bitOffset>
            <bitWidth>1</bitWidth>
          </field>
          <field>
            <name>CTRM</name>
            <bitOffset>15</bitOffset>
            <bitWidth>1</bitWidth>
          </field>
        </fields>
      </register>
      <register>
        <name>ISTR</name>
        <addressOffset>0x44</addressOffset>
        <size>0x10</size>
        <fields>
          <field>
            <name>EP_ID</name>
            <bitOffset>0</bitOffset>
            <bitWidth>4</bitWidth>
          </field>
          <field>
            <name>DIR</name>
            <bitOffset>4</bitOffset>
            <bitWidth>1</bitWidth>
          </field>
          <field>
            <name>ESOF</name>
            <bitOffset>8</bitOffset>
            <bitWidth>1</bitWidth>
          </field>
          <field>
            <name>SOF</name>
            <bitOffset>9</bitOffset>
            <bitWidth>1</bitWidth>
          </field>
          <field>
            <name>RESET</name>
            <bitOffset>10</bitOffset>
            <bitWidth>1</bitWidth>
          </field>
          <field>
            <name>SUSP</name>
            <bitOffset>11</bitOffset>
            <bitWidth>1</bitWidth>
          </field>
          <field>
            <name>WKUP</name>
            <bitOffset>12</bitOffset>
            <bitWidth>1</bitWidth>
          </field>
          <field>
            <name>ERR</name>
            <bitOffset>13</bitOffset>
            <bitWidth>1</bitWidth>
          </field>
          <field>
            <name>PMAOVR</name>
            <bitOffset>14</bitOffset>
            <bitWidth>1</bitWidth>
          </field>
          <field>
            <name>CTR</name>
            <bitOffset>15</bitOffset>
            <bitWidth>1</bitWidth>
          </field>
        </fields>
      </register>
      <register>
        <name>FNR</name>
        <addressOffset>0x48</addressOffset>
        <size>0x10</size>
        <fields>
          <field>
            <name>FN</name>
            <bitOffset>0</bitOffset>
            <bitWidth>11</bitWidth>
          </field>
          <field>
            <name>LSOF</name>
            <bitOffset>11</bitOffset>
            <bitWidth>2</bitWidth>
          </field>
          <field>
            <name>LCK</name>
            <bitOffset>13</bitOffset>
            <bitWidth>1</bitWidth>
          </field>
          <field>
            <name>RXDM</name>
            <bitOffset>14</bitOffset>
            <bitWidth>1</bitWidth>
          </field>
          <field>
            <name>RXDP</name>
            <bitOffset>15</bitOffset>
            <bitWidth>1</bitWidth>
          </field>
        </fields>
      </register>
      <register>
        <name>DADDR</name>
        <addressOffset>0x4c</addressOffset>
        <size>0x10</size>
        <fields>
          <field>
            <name>ADD0</name>
            <bitOffset>0</bitOffset>
            <bitWidth>1</bitWidth>
          </field>
          <field>
            <name>ADD1</name>
            <bitOffset>1</bitOffset>
            <bitWidth>1</bitWidth>
          </field>
          <field>
            <name>ADD2</name>
            <bitOffset>2</bitOffset>
            <bitWidth>1</bitWidth>
          </field>
          <field>
            <name>ADD3</name>
            <bitOffset>3</bitOffset>
            <bitWidth>1</bitWidth>
          </field>
          <field>
            <name>ADD4</name>
            <bitOffset>4</bitOffset>
            <bitWidth>1</bitWidth>
          </field>
          <field>
            <name>ADD5</name>
            <bitOffset>5</bitOffset>
            <bitWidth>1</bitWidth>
          </field>
          <field>
            <name>ADD6</name>
            <bitOffset>6</bitOffset>
            <bitWidth>1</bitWidth>
          </field>
          <field>
            <name>EF</name>
            <bitOffset>7</bitOffset>
            <bitWidth>1</bitWidth>
          </field>
        </fields>
      </register>
      <register>
        <name>BTABLE</name>
        <addressOffset>0x50</addressOffset>
        <size>0x10</size>
        <fields>
          <field>
            <name>BTABLE</name>
            <bitOffset>3</bitOffset>
            <bitWidth>13</bitWidth>
          </field>
        </fields>
      </register>
    </peripheral>
    <peripheral>
      <name>CAN1</name>
      <baseAddress>0x40006400</baseAddress>
      <register>
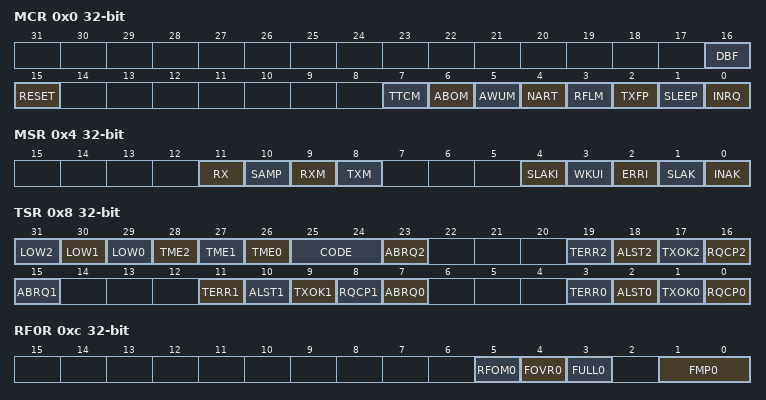
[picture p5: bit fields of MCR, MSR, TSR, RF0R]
        <name>MCR</name>
        <addressOffset>0x0</addressOffset>
        <size>0x20</size>
        <fields>
          <field>
            <name>INRQ</name>
            <bitOffset>0</bitOffset>
            <bitWidth>1</bitWidth>
          </field>
          <field>
            <name>SLEEP</name>
            <bitOffset>1</bitOffset>
            <bitWidth>1</bitWidth>
          </field>
          <field>
            <name>TXFP</name>
            <bitOffset>2</bitOffset>
            <bitWidth>1</bitWidth>
          </field>
          <field>
            <name>RFLM</name>
            <bitOffset>3</bitOffset>
            <bitWidth>1</bitWidth>
          </field>
          <field>
            <name>NART</name>
            <bitOffset>4</bitOffset>
            <bitWidth>1</bitWidth>
          </field>
          <field>
            <name>AWUM</name>
            <bitOffset>5</bitOffset>
            <bitWidth>1</bitWidth>
          </field>
          <field>
            <name>ABOM</name>
            <bitOffset>6</bitOffset>
            <bitWidth>1</bitWidth>
          </field>
          <field>
            <name>TTCM</name>
            <bitOffset>7</bitOffset>
            <bitWidth>1</bitWidth>
          </field>
          <field>
            <name>RESET</name>
            <bitOffset>15</bitOffset>
            <bitWidth>1</bitWidth>
          </field>
          <field>
            <name>DBF</name>
            <bitOffset>16</bitOffset>
            <bitWidth>1</bitWidth>
          </field>
        </fields>
      </register>
      <register>
        <name>MSR</name>
        <addressOffset>0x4</addressOffset>
        <size>0x20</size>
        <fields>
          <field>
            <name>INAK</name>
            <bitOffset>0</bitOffset>
            <bitWidth>1</bitWidth>
          </field>
          <field>
            <name>SLAK</name>
            <bitOffset>1</bitOffset>
            <bitWidth>1</bitWidth>
          </field>
          <field>
            <name>ERRI</name>
            <bitOffset>2</bitOffset>
            <bitWidth>1</bitWidth>
          </field>
          <field>
            <name>WKUI</name>
            <bitOffset>3</bitOffset>
            <bitWidth>1</bitWidth>
          </field>
          <field>
            <name>SLAKI</name>
            <bitOffset>4</bitOffset>
            <bitWidth>1</bitWidth>
          </field>
          <field>
            <name>TXM</name>
            <bitOffset>8</bitOffset>
            <bitWidth>1</bitWidth>
          </field>
          <field>
            <name>RXM</name>
            <bitOffset>9</bitOffset>
            <bitWidth>1</bitWidth>
          </field>
          <field>
            <name>SAMP</name>
            <bitOffset>10</bitOffset>
            <bitWidth>1</bitWidth>
          </field>
          <field>
            <name>RX</name>
            <bitOffset>11</bitOffset>
            <bitWidth>1</bitWidth>
          </field>
        </fields>
      </register>
      <register>
        <name>TSR</name>
        <addressOffset>0x8</addressOffset>
        <size>0x20</size>
        <fields>
          <field>
            <name>RQCP0</name>
            <bitOffset>0</bitOffset>
            <bitWidth>1</bitWidth>
          </field>
          <field>
            <name>TXOK0</name>
            <bitOffset>1</bitOffset>
            <bitWidth>1</bitWidth>
          </field>
          <field>
            <name>ALST0</name>
            <bitOffset>2</bitOffset>
            <bitWidth>1</bitWidth>
          </field>
          <field>
            <name>TERR0</name>
            <bitOffset>3</bitOffset>
            <bitWidth>1</bitWidth>
          </field>
          <field>
            <name>ABRQ0</name>
            <bitOffset>7</bitOffset>
            <bitWidth>1</bitWidth>
          </field>
          <field>
            <name>RQCP1</name>
            <bitOffset>8</bitOffset>
            <bitWidth>1</bitWidth>
          </field>
          <field>
            <name>TXOK1</name>
            <bitOffset>9</bitOffset>
            <bitWidth>1</bitWidth>
          </field>
          <field>
            <name>ALST1</name>
            <bitOffset>10</bitOffset>
            <bitWidth>1</bitWidth>
          </field>
          <field>
            <name>TERR1</name>
            <bitOffset>11</bitOffset>
            <bitWidth>1</bitWidth>
          </field>
          <field>
            <name>ABRQ1</name>
            <bitOffset>15</bitOffset>
            <bitWidth>1</bitWidth>
          </field>
          <field>
            <name>RQCP2</name>
            <bitOffset>16</bitOffset>
            <bitWidth>1</bitWidth>
          </field>
          <field>
            <name>TXOK2</name>
            <bitOffset>17</bitOffset>
            <bitWidth>1</bitWidth>
          </field>
          <field>
            <name>ALST2</name>
            <bitOffset>18</bitOffset>
            <bitWidth>1</bitWidth>
          </field>
          <field>
            <name>TERR2</name>
            <bitOffset>19</bitOffset>
            <bitWidth>1</bitWidth>
          </field>
          <field>
            <name>ABRQ2</name>
            <bitOffset>23</bitOffset>
            <bitWidth>1</bitWidth>
          </field>
          <field>
            <name>CODE</name>
            <bitOffset>24</bitOffset>
            <bitWidth>2</bitWidth>
          </field>
          <field>
            <name>TME0</name>
            <bitOffset>26</bitOffset>
            <bitWidth>1</bitWidth>
          </field>
          <field>
            <name>TME1</name>
            <bitOffset>27</bitOffset>
            <bitWidth>1</bitWidth>
          </field>
          <field>
            <name>TME2</name>
            <bitOffset>28</bitOffset>
            <bitWidth>1</bitWidth>
          </field>
          <field>
            <name>LOW0</name>
            <bitOffset>29</bitOffset>
            <bitWidth>1</bitWidth>
          </field>
          <field>
            <name>LOW1</name>
            <bitOffset>30</bitOffset>
            <bitWidth>1</bitWidth>
          </field>
          <field>
            <name>LOW2</name>
            <bitOffset>31</bitOffset>
            <bitWidth>1</bitWidth>
          </field>
        </fields>
      </register>
      <register>
        <name>RF0R</name>
        <addressOffset>0xc</addressOffset>
        <size>0x20</size>
        <fields>
          <field>
            <name>FMP0</name>
            <bitOffset>0</bitOffset>
            <bitWidth>2</bitWidth>
          </field>
          <field>
            <name>FULL0</name>
            <bitOffset>3</bitOffset>
            <bitWidth>1</bitWidth>
          </field>
          <field>
            <name>FOVR0</name>
            <bitOffset>4</bitOffset>
            <bitWidth>1</bitWidth>
          </field>
          <field>
            <name>RFOM0</name>
            <bitOffset>5</bitOffset>
            <bitWidth>1</bitWidth>
          </field>
        </fields>
      </register>
      <register>
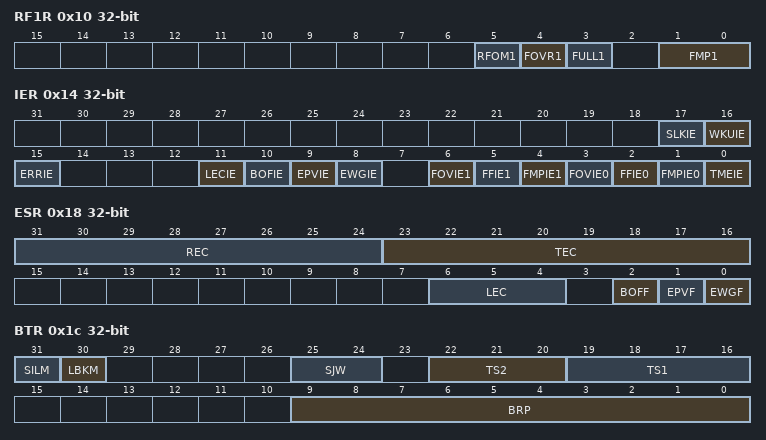
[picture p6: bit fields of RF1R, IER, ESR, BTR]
        <name>RF1R</name>
        <addressOffset>0x10</addressOffset>
        <size>0x20</size>
        <fields>
          <field>
            <name>FMP1</name>
            <bitOffset>0</bitOffset>
            <bitWidth>2</bitWidth>
          </field>
          <field>
            <name>FULL1</name>
            <bitOffset>3</bitOffset>
            <bitWidth>1</bitWidth>
          </field>
          <field>
            <name>FOVR1</name>
            <bitOffset>4</bitOffset>
            <bitWidth>1</bitWidth>
          </field>
          <field>
            <name>RFOM1</name>
            <bitOffset>5</bitOffset>
            <bitWidth>1</bitWidth>
          </field>
        </fields>
      </register>
      <register>
        <name>IER</name>
        <addressOffset>0x14</addressOffset>
        <size>0x20</size>
        <fields>
          <field>
            <name>TMEIE</name>
            <bitOffset>0</bitOffset>
            <bitWidth>1</bitWidth>
          </field>
          <field>
            <name>FMPIE0</name>
            <bitOffset>1</bitOffset>
            <bitWidth>1</bitWidth>
          </field>
          <field>
            <name>FFIE0</name>
            <bitOffset>2</bitOffset>
            <bitWidth>1</bitWidth>
          </field>
          <field>
            <name>FOVIE0</name>
            <bitOffset>3</bitOffset>
            <bitWidth>1</bitWidth>
          </field>
          <field>
            <name>FMPIE1</name>
            <bitOffset>4</bitOffset>
            <bitWidth>1</bitWidth>
          </field>
          <field>
            <name>FFIE1</name>
            <bitOffset>5</bitOffset>
            <bitWidth>1</bitWidth>
          </field>
          <field>
            <name>FOVIE1</name>
            <bitOffset>6</bitOffset>
            <bitWidth>1</bitWidth>
          </field>
          <field>
            <name>EWGIE</name>
            <bitOffset>8</bitOffset>
            <bitWidth>1</bitWidth>
          </field>
          <field>
            <name>EPVIE</name>
            <bitOffset>9</bitOffset>
            <bitWidth>1</bitWidth>
          </field>
          <field>
            <name>BOFIE</name>
            <bitOffset>10</bitOffset>
            <bitWidth>1</bitWidth>
          </field>
          <field>
            <name>LECIE</name>
            <bitOffset>11</bitOffset>
            <bitWidth>1</bitWidth>
          </field>
          <field>
            <name>ERRIE</name>
            <bitOffset>15</bitOffset>
            <bitWidth>1</bitWidth>
          </field>
          <field>
            <name>WKUIE</name>
            <bitOffset>16</bitOffset>
            <bitWidth>1</bitWidth>
          </field>
          <field>
            <name>SLKIE</name>
            <bitOffset>17</bitOffset>
            <bitWidth>1</bitWidth>
          </field>
        </fields>
      </register>
      <register>
        <name>ESR</name>
        <addressOffset>0x18</addressOffset>
        <size>0x20</size>
        <fields>
          <field>
            <name>EWGF</name>
            <bitOffset>0</bitOffset>
            <bitWidth>1</bitWidth>
          </field>
          <field>
            <name>EPVF</name>
            <bitOffset>1</bitOffset>
            <bitWidth>1</bitWidth>
          </field>
          <field>
            <name>BOFF</name>
            <bitOffset>2</bitOffset>
            <bitWidth>1</bitWidth>
          </field>
          <field>
            <name>LEC</name>
            <bitOffset>4</bitOffset>
            <bitWidth>3</bitWidth>
          </field>
          <field>
            <name>TEC</name>
            <bitOffset>16</bitOffset>
            <bitWidth>8</bitWidth>
          </field>
          <field>
            <name>REC</name>
            <bitOffset>24</bitOffset>
            <bitWidth>8</bitWidth>
          </field>
        </fields>
      </register>
      <register>
        <name>BTR</name>
        <addressOffset>0x1c</addressOffset>
        <size>0x20</size>
        <fields>
          <field>
            <name>BRP</name>
            <bitOffset>0</bitOffset>
            <bitWidth>10</bitWidth>
          </field>
          <field>
            <name>TS1</name>
            <bitOffset>16</bitOffset>
            <bitWidth>4</bitWidth>
          </field>
          <field>
            <name>TS2</name>
            <bitOffset>20</bitOffset>
            <bitWidth>3</bitWidth>
          </field>
          <field>
            <name>SJW</name>
            <bitOffset>24</bitOffset>
            <bitWidth>2</bitWidth>
          </field>
          <field>
            <name>LBKM</name>
            <bitOffset>30</bitOffset>
            <bitWidth>1</bitWidth>
          </field>
          <field>
            <name>SILM</name>
            <bitOffset>31</bitOffset>
            <bitWidth>1</bitWidth>
          </field>
        </fields>
      </register>
      <register>
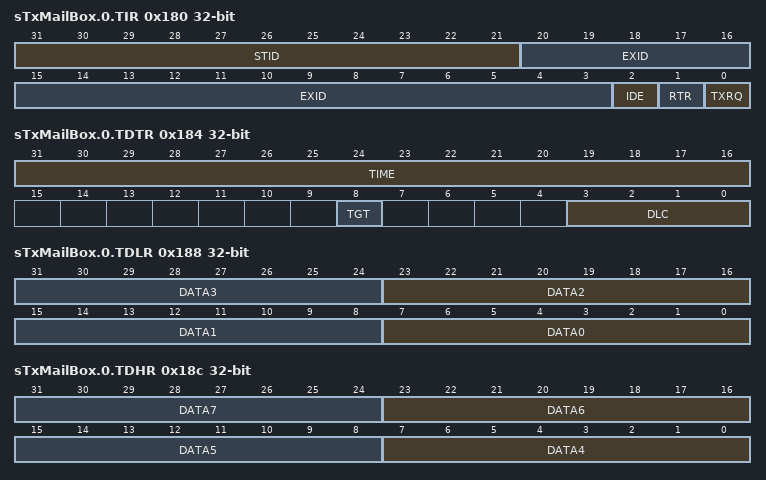
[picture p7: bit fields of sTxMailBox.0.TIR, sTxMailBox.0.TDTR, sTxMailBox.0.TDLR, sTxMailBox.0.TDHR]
        <name>sTxMailBox.0.TIR</name>
        <addressOffset>0x180</addressOffset>
        <size>0x20</size>
        <fields>
          <field>
            <name>TXRQ</name>
            <bitOffset>0</bitOffset>
            <bitWidth>1</bitWidth>
          </field>
          <field>
            <name>RTR</name>
            <bitOffset>1</bitOffset>
            <bitWidth>1</bitWidth>
          </field>
          <field>
            <name>IDE</name>
            <bitOffset>2</bitOffset>
            <bitWidth>1</bitWidth>
          </field>
          <field>
            <name>EXID</name>
            <bitOffset>3</bitOffset>
            <bitWidth>18</bitWidth>
          </field>
          <field>
            <name>STID</name>
            <bitOffset>21</bitOffset>
            <bitWidth>11</bitWidth>
          </field>
        </fields>
      </register>
      <register>
        <name>sTxMailBox.0.TDTR</name>
        <addressOffset>0x184</addressOffset>
        <size>0x20</size>
        <fields>
          <field>
            <name>DLC</name>
            <bitOffset>0</bitOffset>
            <bitWidth>4</bitWidth>
          </field>
          <field>
            <name>TGT</name>
            <bitOffset>8</bitOffset>
            <bitWidth>1</bitWidth>
          </field>
          <field>
            <name>TIME</name>
            <bitOffset>16</bitOffset>
            <bitWidth>16</bitWidth>
          </field>
        </fields>
      </register>
      <register>
        <name>sTxMailBox.0.TDLR</name>
        <addressOffset>0x188</addressOffset>
        <size>0x20</size>
        <fields>
          <field>
            <name>DATA0</name>
            <bitOffset>0</bitOffset>
            <bitWidth>8</bitWidth>
          </field>
          <field>
            <name>DATA1</name>
            <bitOffset>8</bitOffset>
            <bitWidth>8</bitWidth>
          </field>
          <field>
            <name>DATA2</name>
            <bitOffset>16</bitOffset>
            <bitWidth>8</bitWidth>
          </field>
          <field>
            <name>DATA3</name>
            <bitOffset>24</bitOffset>
            <bitWidth>8</bitWidth>
          </field>
        </fields>
      </register>
      <register>
        <name>sTxMailBox.0.TDHR</name>
        <addressOffset>0x18c</addressOffset>
        <size>0x20</size>
        <fields>
          <field>
            <name>DATA4</name>
            <bitOffset>0</bitOffset>
            <bitWidth>8</bitWidth>
          </field>
          <field>
            <name>DATA5</name>
            <bitOffset>8</bitOffset>
            <bitWidth>8</bitWidth>
          </field>
          <field>
            <name>DATA6</name>
            <bitOffset>16</bitOffset>
            <bitWidth>8</bitWidth>
          </field>
          <field>
            <name>DATA7</name>
            <bitOffset>24</bitOffset>
            <bitWidth>8</bitWidth>
          </field>
        </fields>
      </register>
      <register>
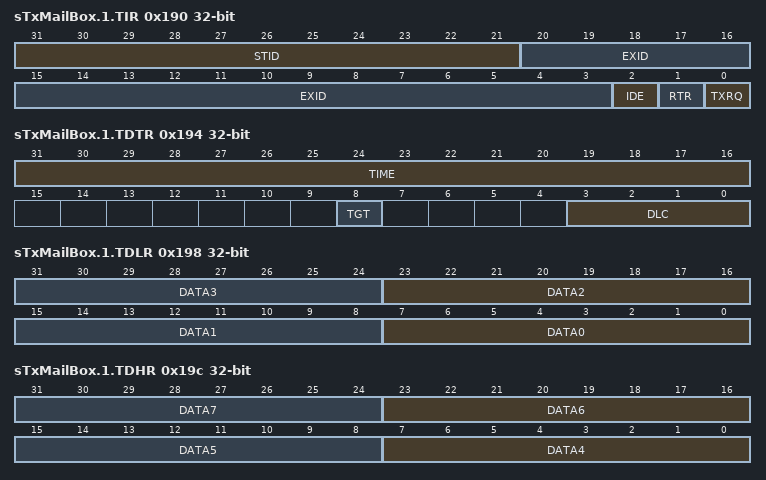
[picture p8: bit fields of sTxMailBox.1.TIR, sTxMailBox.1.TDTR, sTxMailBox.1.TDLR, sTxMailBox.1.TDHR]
        <name>sTxMailBox.1.TIR</name>
        <addressOffset>0x190</addressOffset>
        <size>0x20</size>
        <fields>
          <field>
            <name>TXRQ</name>
            <bitOffset>0</bitOffset>
            <bitWidth>1</bitWidth>
          </field>
          <field>
            <name>RTR</name>
            <bitOffset>1</bitOffset>
            <bitWidth>1</bitWidth>
          </field>
          <field>
            <name>IDE</name>
            <bitOffset>2</bitOffset>
            <bitWidth>1</bitWidth>
          </field>
          <field>
            <name>EXID</name>
            <bitOffset>3</bitOffset>
            <bitWidth>18</bitWidth>
          </field>
          <field>
            <name>STID</name>
            <bitOffset>21</bitOffset>
            <bitWidth>11</bitWidth>
          </field>
        </fields>
      </register>
      <register>
        <name>sTxMailBox.1.TDTR</name>
        <addressOffset>0x194</addressOffset>
        <size>0x20</size>
        <fields>
          <field>
            <name>DLC</name>
            <bitOffset>0</bitOffset>
            <bitWidth>4</bitWidth>
          </field>
          <field>
            <name>TGT</name>
            <bitOffset>8</bitOffset>
            <bitWidth>1</bitWidth>
          </field>
          <field>
            <name>TIME</name>
            <bitOffset>16</bitOffset>
            <bitWidth>16</bitWidth>
          </field>
        </fields>
      </register>
      <register>
        <name>sTxMailBox.1.TDLR</name>
        <addressOffset>0x198</addressOffset>
        <size>0x20</size>
        <fields>
          <field>
            <name>DATA0</name>
            <bitOffset>0</bitOffset>
            <bitWidth>8</bitWidth>
          </field>
          <field>
            <name>DATA1</name>
            <bitOffset>8</bitOffset>
            <bitWidth>8</bitWidth>
          </field>
          <field>
            <name>DATA2</name>
            <bitOffset>16</bitOffset>
            <bitWidth>8</bitWidth>
          </field>
          <field>
            <name>DATA3</name>
            <bitOffset>24</bitOffset>
            <bitWidth>8</bitWidth>
          </field>
        </fields>
      </register>
      <register>
        <name>sTxMailBox.1.TDHR</name>
        <addressOffset>0x19c</addressOffset>
        <size>0x20</size>
        <fields>
          <field>
            <name>DATA4</name>
            <bitOffset>0</bitOffset>
            <bitWidth>8</bitWidth>
          </field>
          <field>
            <name>DATA5</name>
            <bitOffset>8</bitOffset>
            <bitWidth>8</bitWidth>
          </field>
          <field>
            <name>DATA6</name>
            <bitOffset>16</bitOffset>
            <bitWidth>8</bitWidth>
          </field>
          <field>
            <name>DATA7</name>
            <bitOffset>24</bitOffset>
            <bitWidth>8</bitWidth>
          </field>
        </fields>
      </register>
      <register>
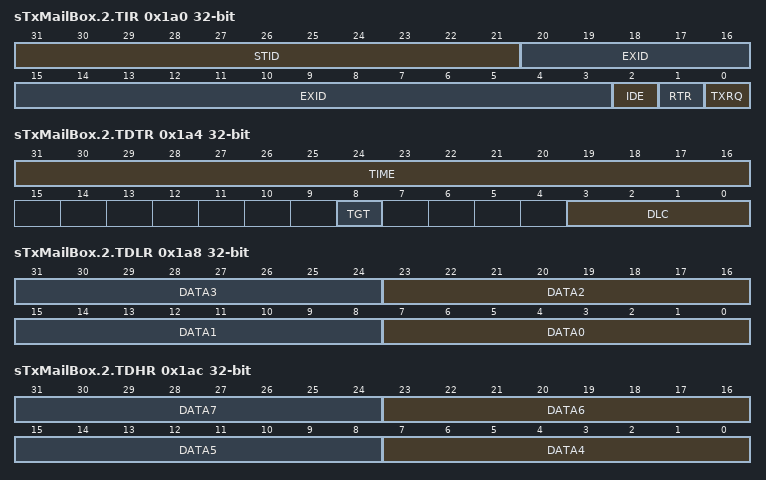
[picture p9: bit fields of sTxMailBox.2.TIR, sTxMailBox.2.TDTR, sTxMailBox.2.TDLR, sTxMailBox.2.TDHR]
        <name>sTxMailBox.2.TIR</name>
        <addressOffset>0x1a0</addressOffset>
        <size>0x20</size>
        <fields>
          <field>
            <name>TXRQ</name>
            <bitOffset>0</bitOffset>
            <bitWidth>1</bitWidth>
          </field>
          <field>
            <name>RTR</name>
            <bitOffset>1</bitOffset>
            <bitWidth>1</bitWidth>
          </field>
          <field>
            <name>IDE</name>
            <bitOffset>2</bitOffset>
            <bitWidth>1</bitWidth>
          </field>
          <field>
            <name>EXID</name>
            <bitOffset>3</bitOffset>
            <bitWidth>18</bitWidth>
          </field>
          <field>
            <name>STID</name>
            <bitOffset>21</bitOffset>
            <bitWidth>11</bitWidth>
          </field>
        </fields>
      </register>
      <register>
        <name>sTxMailBox.2.TDTR</name>
        <addressOffset>0x1a4</addressOffset>
        <size>0x20</size>
        <fields>
          <field>
            <name>DLC</name>
            <bitOffset>0</bitOffset>
            <bitWidth>4</bitWidth>
          </field>
          <field>
            <name>TGT</name>
            <bitOffset>8</bitOffset>
            <bitWidth>1</bitWidth>
          </field>
          <field>
            <name>TIME</name>
            <bitOffset>16</bitOffset>
            <bitWidth>16</bitWidth>
          </field>
        </fields>
      </register>
      <register>
        <name>sTxMailBox.2.TDLR</name>
        <addressOffset>0x1a8</addressOffset>
        <size>0x20</size>
        <fields>
          <field>
            <name>DATA0</name>
            <bitOffset>0</bitOffset>
            <bitWidth>8</bitWidth>
          </field>
          <field>
            <name>DATA1</name>
            <bitOffset>8</bitOffset>
            <bitWidth>8</bitWidth>
          </field>
          <field>
            <name>DATA2</name>
            <bitOffset>16</bitOffset>
            <bitWidth>8</bitWidth>
          </field>
          <field>
            <name>DATA3</name>
            <bitOffset>24</bitOffset>
            <bitWidth>8</bitWidth>
          </field>
        </fields>
      </register>
      <register>
        <name>sTxMailBox.2.TDHR</name>
        <addressOffset>0x1ac</addressOffset>
        <size>0x20</size>
        <fields>
          <field>
            <name>DATA4</name>
            <bitOffset>0</bitOffset>
            <bitWidth>8</bitWidth>
          </field>
          <field>
            <name>DATA5</name>
            <bitOffset>8</bitOffset>
            <bitWidth>8</bitWidth>
          </field>
          <field>
            <name>DATA6</name>
            <bitOffset>16</bitOffset>
            <bitWidth>8</bitWidth>
          </field>
          <field>
            <name>DATA7</name>
            <bitOffset>24</bitOffset>
            <bitWidth>8</bitWidth>
          </field>
        </fields>
      </register>
      <register>
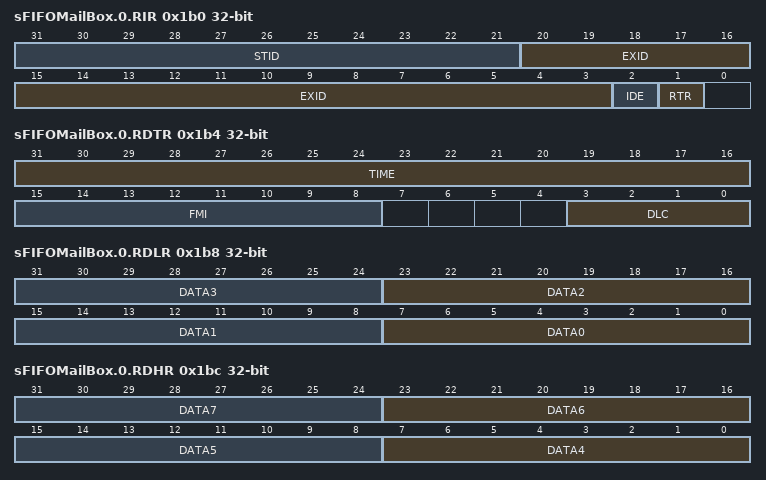
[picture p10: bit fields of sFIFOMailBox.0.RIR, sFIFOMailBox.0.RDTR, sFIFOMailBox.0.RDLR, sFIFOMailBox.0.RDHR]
        <name>sFIFOMailBox.0.RIR</name>
        <addressOffset>0x1b0</addressOffset>
        <size>0x20</size>
        <fields>
          <field>
            <name>RTR</name>
            <bitOffset>1</bitOffset>
            <bitWidth>1</bitWidth>
          </field>
          <field>
            <name>IDE</name>
            <bitOffset>2</bitOffset>
            <bitWidth>1</bitWidth>
          </field>
          <field>
            <name>EXID</name>
            <bitOffset>3</bitOffset>
            <bitWidth>18</bitWidth>
          </field>
          <field>
            <name>STID</name>
            <bitOffset>21</bitOffset>
            <bitWidth>11</bitWidth>
          </field>
        </fields>
      </register>
      <register>
        <name>sFIFOMailBox.0.RDTR</name>
        <addressOffset>0x1b4</addressOffset>
        <size>0x20</size>
        <fields>
          <field>
            <name>DLC</name>
            <bitOffset>0</bitOffset>
            <bitWidth>4</bitWidth>
          </field>
          <field>
            <name>FMI</name>
            <bitOffset>8</bitOffset>
            <bitWidth>8</bitWidth>
          </field>
          <field>
            <name>TIME</name>
            <bitOffset>16</bitOffset>
            <bitWidth>16</bitWidth>
          </field>
        </fields>
      </register>
      <register>
        <name>sFIFOMailBox.0.RDLR</name>
        <addressOffset>0x1b8</addressOffset>
        <size>0x20</size>
        <fields>
          <field>
            <name>DATA0</name>
            <bitOffset>0</bitOffset>
            <bitWidth>8</bitWidth>
          </field>
          <field>
            <name>DATA1</name>
            <bitOffset>8</bitOffset>
            <bitWidth>8</bitWidth>
          </field>
          <field>
            <name>DATA2</name>
            <bitOffset>16</bitOffset>
            <bitWidth>8</bitWidth>
          </field>
          <field>
            <name>DATA3</name>
            <bitOffset>24</bitOffset>
            <bitWidth>8</bitWidth>
          </field>
        </fields>
      </register>
      <register>
        <name>sFIFOMailBox.0.RDHR</name>
        <addressOffset>0x1bc</addressOffset>
        <size>0x20</size>
        <fields>
          <field>
            <name>DATA4</name>
            <bitOffset>0</bitOffset>
            <bitWidth>8</bitWidth>
          </field>
          <field>
            <name>DATA5</name>
            <bitOffset>8</bitOffset>
            <bitWidth>8</bitWidth>
          </field>
          <field>
            <name>DATA6</name>
            <bitOffset>16</bitOffset>
            <bitWidth>8</bitWidth>
          </field>
          <field>
            <name>DATA7</name>
            <bitOffset>24</bitOffset>
            <bitWidth>8</bitWidth>
          </field>
        </fields>
      </register>
      <register>
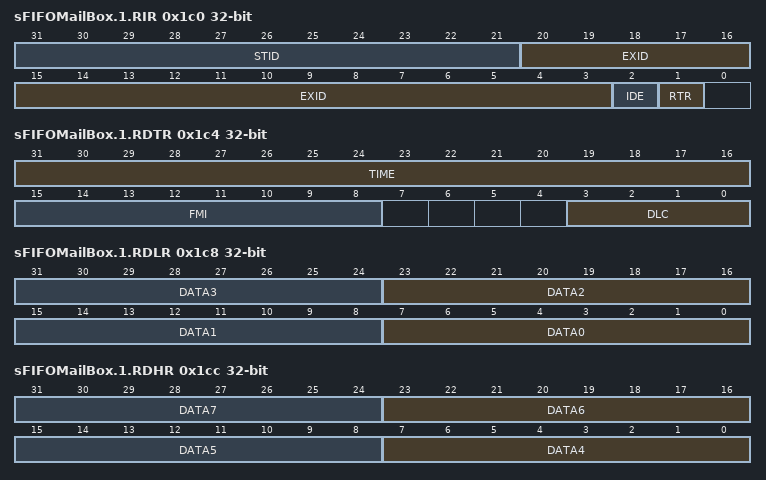
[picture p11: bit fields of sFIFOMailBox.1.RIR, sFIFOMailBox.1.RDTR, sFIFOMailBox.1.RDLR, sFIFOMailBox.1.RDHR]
        <name>sFIFOMailBox.1.RIR</name>
        <addressOffset>0x1c0</addressOffset>
        <size>0x20</size>
        <fields>
          <field>
            <name>RTR</name>
            <bitOffset>1</bitOffset>
            <bitWidth>1</bitWidth>
          </field>
          <field>
            <name>IDE</name>
            <bitOffset>2</bitOffset>
            <bitWidth>1</bitWidth>
          </field>
          <field>
            <name>EXID</name>
            <bitOffset>3</bitOffset>
            <bitWidth>18</bitWidth>
          </field>
          <field>
            <name>STID</name>
            <bitOffset>21</bitOffset>
            <bitWidth>11</bitWidth>
          </field>
        </fields>
      </register>
      <register>
        <name>sFIFOMailBox.1.RDTR</name>
        <addressOffset>0x1c4</addressOffset>
        <size>0x20</size>
        <fields>
          <field>
            <name>DLC</name>
            <bitOffset>0</bitOffset>
            <bitWidth>4</bitWidth>
          </field>
          <field>
            <name>FMI</name>
            <bitOffset>8</bitOffset>
            <bitWidth>8</bitWidth>
          </field>
          <field>
            <name>TIME</name>
            <bitOffset>16</bitOffset>
            <bitWidth>16</bitWidth>
          </field>
        </fields>
      </register>
      <register>
        <name>sFIFOMailBox.1.RDLR</name>
        <addressOffset>0x1c8</addressOffset>
        <size>0x20</size>
        <fields>
          <field>
            <name>DATA0</name>
            <bitOffset>0</bitOffset>
            <bitWidth>8</bitWidth>
          </field>
          <field>
            <name>DATA1</name>
            <bitOffset>8</bitOffset>
            <bitWidth>8</bitWidth>
          </field>
          <field>
            <name>DATA2</name>
            <bitOffset>16</bitOffset>
            <bitWidth>8</bitWidth>
          </field>
          <field>
            <name>DATA3</name>
            <bitOffset>24</bitOffset>
            <bitWidth>8</bitWidth>
          </field>
        </fields>
      </register>
      <register>
        <name>sFIFOMailBox.1.RDHR</name>
        <addressOffset>0x1cc</addressOffset>
        <size>0x20</size>
        <fields>
          <field>
            <name>DATA4</name>
            <bitOffset>0</bitOffset>
            <bitWidth>8</bitWidth>
          </field>
          <field>
            <name>DATA5</name>
            <bitOffset>8</bitOffset>
            <bitWidth>8</bitWidth>
          </field>
          <field>
            <name>DATA6</name>
            <bitOffset>16</bitOffset>
            <bitWidth>8</bitWidth>
          </field>
          <field>
            <name>DATA7</name>
            <bitOffset>24</bitOffset>
            <bitWidth>8</bitWidth>
          </field>
        </fields>
      </register>
      <register>
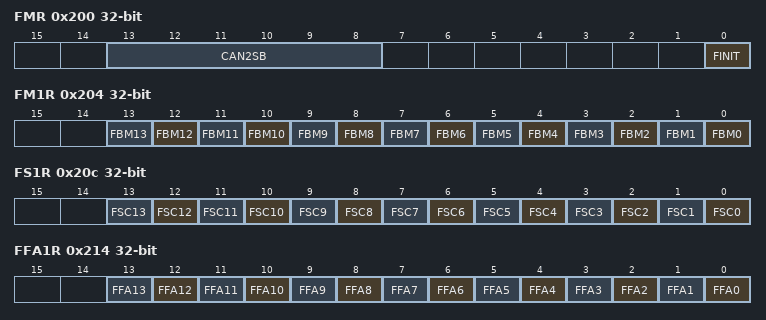
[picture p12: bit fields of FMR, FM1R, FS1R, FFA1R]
        <name>FMR</name>
        <addressOffset>0x200</addressOffset>
        <size>0x20</size>
        <fields>
          <field>
            <name>FINIT</name>
            <bitOffset>0</bitOffset>
            <bitWidth>1</bitWidth>
          </field>
          <field>
            <name>CAN2SB</name>
            <bitOffset>8</bitOffset>
            <bitWidth>6</bitWidth>
          </field>
        </fields>
      </register>
      <register>
        <name>FM1R</name>
        <addressOffset>0x204</addressOffset>
        <size>0x20</size>
        <fields>
          <field>
            <name>FBM0</name>
            <bitOffset>0</bitOffset>
            <bitWidth>1</bitWidth>
          </field>
          <field>
            <name>FBM1</name>
            <bitOffset>1</bitOffset>
            <bitWidth>1</bitWidth>
          </field>
          <field>
            <name>FBM2</name>
            <bitOffset>2</bitOffset>
            <bitWidth>1</bitWidth>
          </field>
          <field>
            <name>FBM3</name>
            <bitOffset>3</bitOffset>
            <bitWidth>1</bitWidth>
          </field>
          <field>
            <name>FBM4</name>
            <bitOffset>4</bitOffset>
            <bitWidth>1</bitWidth>
          </field>
          <field>
            <name>FBM5</name>
            <bitOffset>5</bitOffset>
            <bitWidth>1</bitWidth>
          </field>
          <field>
            <name>FBM6</name>
            <bitOffset>6</bitOffset>
            <bitWidth>1</bitWidth>
          </field>
          <field>
            <name>FBM7</name>
            <bitOffset>7</bitOffset>
            <bitWidth>1</bitWidth>
          </field>
          <field>
            <name>FBM8</name>
            <bitOffset>8</bitOffset>
            <bitWidth>1</bitWidth>
          </field>
          <field>
            <name>FBM9</name>
            <bitOffset>9</bitOffset>
            <bitWidth>1</bitWidth>
          </field>
          <field>
            <name>FBM10</name>
            <bitOffset>10</bitOffset>
            <bitWidth>1</bitWidth>
          </field>
          <field>
            <name>FBM11</name>
            <bitOffset>11</bitOffset>
            <bitWidth>1</bitWidth>
          </field>
          <field>
            <name>FBM12</name>
            <bitOffset>12</bitOffset>
            <bitWidth>1</bitWidth>
          </field>
          <field>
            <name>FBM13</name>
            <bitOffset>13</bitOffset>
            <bitWidth>1</bitWidth>
          </field>
        </fields>
      </register>
      <register>
        <name>FS1R</name>
        <addressOffset>0x20c</addressOffset>
        <size>0x20</size>
        <fields>
          <field>
            <name>FSC0</name>
            <bitOffset>0</bitOffset>
            <bitWidth>1</bitWidth>
          </field>
          <field>
            <name>FSC1</name>
            <bitOffset>1</bitOffset>
            <bitWidth>1</bitWidth>
          </field>
          <field>
            <name>FSC2</name>
            <bitOffset>2</bitOffset>
            <bitWidth>1</bitWidth>
          </field>
          <field>
            <name>FSC3</name>
            <bitOffset>3</bitOffset>
            <bitWidth>1</bitWidth>
          </field>
          <field>
            <name>FSC4</name>
            <bitOffset>4</bitOffset>
            <bitWidth>1</bitWidth>
          </field>
          <field>
            <name>FSC5</name>
            <bitOffset>5</bitOffset>
            <bitWidth>1</bitWidth>
          </field>
          <field>
            <name>FSC6</name>
            <bitOffset>6</bitOffset>
            <bitWidth>1</bitWidth>
          </field>
          <field>
            <name>FSC7</name>
            <bitOffset>7</bitOffset>
            <bitWidth>1</bitWidth>
          </field>
          <field>
            <name>FSC8</name>
            <bitOffset>8</bitOffset>
            <bitWidth>1</bitWidth>
          </field>
          <field>
            <name>FSC9</name>
            <bitOffset>9</bitOffset>
            <bitWidth>1</bitWidth>
          </field>
          <field>
            <name>FSC10</name>
            <bitOffset>10</bitOffset>
            <bitWidth>1</bitWidth>
          </field>
          <field>
            <name>FSC11</name>
            <bitOffset>11</bitOffset>
            <bitWidth>1</bitWidth>
          </field>
          <field>
            <name>FSC12</name>
            <bitOffset>12</bitOffset>
            <bitWidth>1</bitWidth>
          </field>
          <field>
            <name>FSC13</name>
            <bitOffset>13</bitOffset>
            <bitWidth>1</bitWidth>
          </field>
        </fields>
      </register>
      <register>
        <name>FFA1R</name>
        <addressOffset>0x214</addressOffset>
        <size>0x20</size>
        <fields>
          <field>
            <name>FFA0</name>
            <bitOffset>0</bitOffset>
            <bitWidth>1</bitWidth>
          </field>
          <field>
            <name>FFA1</name>
            <bitOffset>1</bitOffset>
            <bitWidth>1</bitWidth>
          </field>
          <field>
            <name>FFA2</name>
            <bitOffset>2</bitOffset>
            <bitWidth>1</bitWidth>
          </field>
          <field>
            <name>FFA3</name>
            <bitOffset>3</bitOffset>
            <bitWidth>1</bitWidth>
          </field>
          <field>
            <name>FFA4</name>
            <bitOffset>4</bitOffset>
            <bitWidth>1</bitWidth>
          </field>
          <field>
            <name>FFA5</name>
            <bitOffset>5</bitOffset>
            <bitWidth>1</bitWidth>
          </field>
          <field>
            <name>FFA6</name>
            <bitOffset>6</bitOffset>
            <bitWidth>1</bitWidth>
          </field>
          <field>
            <name>FFA7</name>
            <bitOffset>7</bitOffset>
            <bitWidth>1</bitWidth>
          </field>
          <field>
            <name>FFA8</name>
            <bitOffset>8</bitOffset>
            <bitWidth>1</bitWidth>
          </field>
          <field>
            <name>FFA9</name>
            <bitOffset>9</bitOffset>
            <bitWidth>1</bitWidth>
          </field>
          <field>
            <name>FFA10</name>
            <bitOffset>10</bitOffset>
            <bitWidth>1</bitWidth>
          </field>
          <field>
            <name>FFA11</name>
            <bitOffset>11</bitOffset>
            <bitWidth>1</bitWidth>
          </field>
          <field>
            <name>FFA12</name>
            <bitOffset>12</bitOffset>
            <bitWidth>1</bitWidth>
          </field>
          <field>
            <name>FFA13</name>
            <bitOffset>13</bitOffset>
            <bitWidth>1</bitWidth>
          </field>
        </fields>
      </register>
      <register>
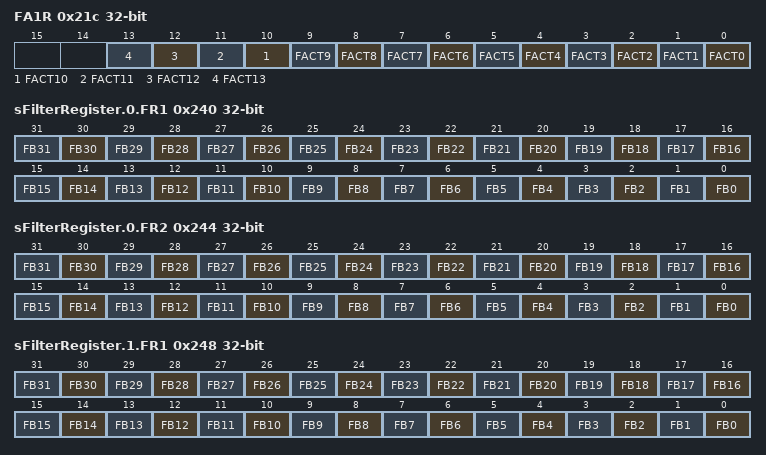
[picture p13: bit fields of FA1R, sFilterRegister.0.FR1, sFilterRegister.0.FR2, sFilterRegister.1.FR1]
        <name>FA1R</name>
        <addressOffset>0x21c</addressOffset>
        <size>0x20</size>
        <fields>
          <field>
            <name>FACT0</name>
            <bitOffset>0</bitOffset>
            <bitWidth>1</bitWidth>
          </field>
          <field>
            <name>FACT1</name>
            <bitOffset>1</bitOffset>
            <bitWidth>1</bitWidth>
          </field>
          <field>
            <name>FACT2</name>
            <bitOffset>2</bitOffset>
            <bitWidth>1</bitWidth>
          </field>
          <field>
            <name>FACT3</name>
            <bitOffset>3</bitOffset>
            <bitWidth>1</bitWidth>
          </field>
          <field>
            <name>FACT4</name>
            <bitOffset>4</bitOffset>
            <bitWidth>1</bitWidth>
          </field>
          <field>
            <name>FACT5</name>
            <bitOffset>5</bitOffset>
            <bitWidth>1</bitWidth>
          </field>
          <field>
            <name>FACT6</name>
            <bitOffset>6</bitOffset>
            <bitWidth>1</bitWidth>
          </field>
          <field>
            <name>FACT7</name>
            <bitOffset>7</bitOffset>
            <bitWidth>1</bitWidth>
          </field>
          <field>
            <name>FACT8</name>
            <bitOffset>8</bitOffset>
            <bitWidth>1</bitWidth>
          </field>
          <field>
            <name>FACT9</name>
            <bitOffset>9</bitOffset>
            <bitWidth>1</bitWidth>
          </field>
          <field>
            <name>FACT10</name>
            <bitOffset>10</bitOffset>
            <bitWidth>1</bitWidth>
          </field>
          <field>
            <name>FACT11</name>
            <bitOffset>11</bitOffset>
            <bitWidth>1</bitWidth>
          </field>
          <field>
            <name>FACT12</name>
            <bitOffset>12</bitOffset>
            <bitWidth>1</bitWidth>
          </field>
          <field>
            <name>FACT13</name>
            <bitOffset>13</bitOffset>
            <bitWidth>1</bitWidth>
          </field>
        </fields>
      </register>
      <register>
        <name>sFilterRegister.0.FR1</name>
        <addressOffset>0x240</addressOffset>
        <size>0x20</size>
        <fields>
          <field>
            <name>FB0</name>
            <bitOffset>0</bitOffset>
            <bitWidth>1</bitWidth>
          </field>
          <field>
            <name>FB1</name>
            <bitOffset>1</bitOffset>
            <bitWidth>1</bitWidth>
          </field>
          <field>
            <name>FB2</name>
            <bitOffset>2</bitOffset>
            <bitWidth>1</bitWidth>
          </field>
          <field>
            <name>FB3</name>
            <bitOffset>3</bitOffset>
            <bitWidth>1</bitWidth>
          </field>
          <field>
            <name>FB4</name>
            <bitOffset>4</bitOffset>
            <bitWidth>1</bitWidth>
          </field>
          <field>
            <name>FB5</name>
            <bitOffset>5</bitOffset>
            <bitWidth>1</bitWidth>
          </field>
          <field>
            <name>FB6</name>
            <bitOffset>6</bitOffset>
            <bitWidth>1</bitWidth>
          </field>
          <field>
            <name>FB7</name>
            <bitOffset>7</bitOffset>
            <bitWidth>1</bitWidth>
          </field>
          <field>
            <name>FB8</name>
            <bitOffset>8</bitOffset>
            <bitWidth>1</bitWidth>
          </field>
          <field>
            <name>FB9</name>
            <bitOffset>9</bitOffset>
            <bitWidth>1</bitWidth>
          </field>
          <field>
            <name>FB10</name>
            <bitOffset>10</bitOffset>
            <bitWidth>1</bitWidth>
          </field>
          <field>
            <name>FB11</name>
            <bitOffset>11</bitOffset>
            <bitWidth>1</bitWidth>
          </field>
          <field>
            <name>FB12</name>
            <bitOffset>12</bitOffset>
            <bitWidth>1</bitWidth>
          </field>
          <field>
            <name>FB13</name>
            <bitOffset>13</bitOffset>
            <bitWidth>1</bitWidth>
          </field>
          <field>
            <name>FB14</name>
            <bitOffset>14</bitOffset>
            <bitWidth>1</bitWidth>
          </field>
          <field>
            <name>FB15</name>
            <bitOffset>15</bitOffset>
            <bitWidth>1</bitWidth>
          </field>
          <field>
            <name>FB16</name>
            <bitOffset>16</bitOffset>
            <bitWidth>1</bitWidth>
          </field>
          <field>
            <name>FB17</name>
            <bitOffset>17</bitOffset>
            <bitWidth>1</bitWidth>
          </field>
          <field>
            <name>FB18</name>
            <bitOffset>18</bitOffset>
            <bitWidth>1</bitWidth>
          </field>
          <field>
            <name>FB19</name>
            <bitOffset>19</bitOffset>
            <bitWidth>1</bitWidth>
          </field>
          <field>
            <name>FB20</name>
            <bitOffset>20</bitOffset>
            <bitWidth>1</bitWidth>
          </field>
          <field>
            <name>FB21</name>
            <bitOffset>21</bitOffset>
            <bitWidth>1</bitWidth>
          </field>
          <field>
            <name>FB22</name>
            <bitOffset>22</bitOffset>
            <bitWidth>1</bitWidth>
          </field>
          <field>
            <name>FB23</name>
            <bitOffset>23</bitOffset>
            <bitWidth>1</bitWidth>
          </field>
          <field>
            <name>FB24</name>
            <bitOffset>24</bitOffset>
            <bitWidth>1</bitWidth>
          </field>
          <field>
            <name>FB25</name>
            <bitOffset>25</bitOffset>
            <bitWidth>1</bitWidth>
          </field>
          <field>
            <name>FB26</name>
            <bitOffset>26</bitOffset>
            <bitWidth>1</bitWidth>
          </field>
          <field>
            <name>FB27</name>
            <bitOffset>27</bitOffset>
            <bitWidth>1</bitWidth>
          </field>
          <field>
            <name>FB28</name>
            <bitOffset>28</bitOffset>
            <bitWidth>1</bitWidth>
          </field>
          <field>
            <name>FB29</name>
            <bitOffset>29</bitOffset>
            <bitWidth>1</bitWidth>
          </field>
          <field>
            <name>FB30</name>
            <bitOffset>30</bitOffset>
            <bitWidth>1</bitWidth>
          </field>
          <field>
            <name>FB31</name>
            <bitOffset>31</bitOffset>
            <bitWidth>1</bitWidth>
          </field>
        </fields>
      </register>
      <register>
        <name>sFilterRegister.0.FR2</name>
        <addressOffset>0x244</addressOffset>
        <size>0x20</size>
        <fields>
          <field>
            <name>FB0</name>
            <bitOffset>0</bitOffset>
            <bitWidth>1</bitWidth>
          </field>
          <field>
            <name>FB1</name>
            <bitOffset>1</bitOffset>
            <bitWidth>1</bitWidth>
          </field>
          <field>
            <name>FB2</name>
            <bitOffset>2</bitOffset>
            <bitWidth>1</bitWidth>
          </field>
          <field>
            <name>FB3</name>
            <bitOffset>3</bitOffset>
            <bitWidth>1</bitWidth>
          </field>
          <field>
            <name>FB4</name>
            <bitOffset>4</bitOffset>
            <bitWidth>1</bitWidth>
          </field>
          <field>
            <name>FB5</name>
            <bitOffset>5</bitOffset>
            <bitWidth>1</bitWidth>
          </field>
          <field>
            <name>FB6</name>
            <bitOffset>6</bitOffset>
            <bitWidth>1</bitWidth>
          </field>
          <field>
            <name>FB7</name>
            <bitOffset>7</bitOffset>
            <bitWidth>1</bitWidth>
          </field>
          <field>
            <name>FB8</name>
            <bitOffset>8</bitOffset>
            <bitWidth>1</bitWidth>
          </field>
          <field>
            <name>FB9</name>
            <bitOffset>9</bitOffset>
            <bitWidth>1</bitWidth>
          </field>
          <field>
            <name>FB10</name>
            <bitOffset>10</bitOffset>
            <bitWidth>1</bitWidth>
          </field>
          <field>
            <name>FB11</name>
            <bitOffset>11</bitOffset>
            <bitWidth>1</bitWidth>
          </field>
          <field>
            <name>FB12</name>
            <bitOffset>12</bitOffset>
            <bitWidth>1</bitWidth>
          </field>
          <field>
            <name>FB13</name>
            <bitOffset>13</bitOffset>
            <bitWidth>1</bitWidth>
          </field>
          <field>
            <name>FB14</name>
            <bitOffset>14</bitOffset>
            <bitWidth>1</bitWidth>
          </field>
          <field>
            <name>FB15</name>
            <bitOffset>15</bitOffset>
            <bitWidth>1</bitWidth>
          </field>
          <field>
            <name>FB16</name>
            <bitOffset>16</bitOffset>
            <bitWidth>1</bitWidth>
          </field>
          <field>
            <name>FB17</name>
            <bitOffset>17</bitOffset>
            <bitWidth>1</bitWidth>
          </field>
          <field>
            <name>FB18</name>
            <bitOffset>18</bitOffset>
            <bitWidth>1</bitWidth>
          </field>
          <field>
            <name>FB19</name>
            <bitOffset>19</bitOffset>
            <bitWidth>1</bitWidth>
          </field>
          <field>
            <name>FB20</name>
            <bitOffset>20</bitOffset>
            <bitWidth>1</bitWidth>
          </field>
          <field>
            <name>FB21</name>
            <bitOffset>21</bitOffset>
            <bitWidth>1</bitWidth>
          </field>
          <field>
            <name>FB22</name>
            <bitOffset>22</bitOffset>
            <bitWidth>1</bitWidth>
          </field>
          <field>
            <name>FB23</name>
            <bitOffset>23</bitOffset>
            <bitWidth>1</bitWidth>
          </field>
          <field>
            <name>FB24</name>
            <bitOffset>24</bitOffset>
            <bitWidth>1</bitWidth>
          </field>
          <field>
            <name>FB25</name>
            <bitOffset>25</bitOffset>
            <bitWidth>1</bitWidth>
          </field>
          <field>
            <name>FB26</name>
            <bitOffset>26</bitOffset>
            <bitWidth>1</bitWidth>
          </field>
          <field>
            <name>FB27</name>
            <bitOffset>27</bitOffset>
            <bitWidth>1</bitWidth>
          </field>
          <field>
            <name>FB28</name>
            <bitOffset>28</bitOffset>
            <bitWidth>1</bitWidth>
          </field>
          <field>
            <name>FB29</name>
            <bitOffset>29</bitOffset>
            <bitWidth>1</bitWidth>
          </field>
          <field>
            <name>FB30</name>
            <bitOffset>30</bitOffset>
            <bitWidth>1</bitWidth>
          </field>
          <field>
            <name>FB31</name>
            <bitOffset>31</bitOffset>
            <bitWidth>1</bitWidth>
          </field>
        </fields>
      </register>
      <register>
        <name>sFilterRegister.1.FR1</name>
        <addressOffset>0x248</addressOffset>
        <size>0x20</size>
        <fields>
          <field>
            <name>FB0</name>
            <bitOffset>0</bitOffset>
            <bitWidth>1</bitWidth>
          </field>
          <field>
            <name>FB1</name>
            <bitOffset>1</bitOffset>
            <bitWidth>1</bitWidth>
          </field>
          <field>
            <name>FB2</name>
            <bitOffset>2</bitOffset>
            <bitWidth>1</bitWidth>
          </field>
          <field>
            <name>FB3</name>
            <bitOffset>3</bitOffset>
            <bitWidth>1</bitWidth>
          </field>
          <field>
            <name>FB4</name>
            <bitOffset>4</bitOffset>
            <bitWidth>1</bitWidth>
          </field>
          <field>
            <name>FB5</name>
            <bitOffset>5</bitOffset>
            <bitWidth>1</bitWidth>
          </field>
          <field>
            <name>FB6</name>
            <bitOffset>6</bitOffset>
            <bitWidth>1</bitWidth>
          </field>
          <field>
            <name>FB7</name>
            <bitOffset>7</bitOffset>
            <bitWidth>1</bitWidth>
          </field>
          <field>
            <name>FB8</name>
            <bitOffset>8</bitOffset>
            <bitWidth>1</bitWidth>
          </field>
          <field>
            <name>FB9</name>
            <bitOffset>9</bitOffset>
            <bitWidth>1</bitWidth>
          </field>
          <field>
            <name>FB10</name>
            <bitOffset>10</bitOffset>
            <bitWidth>1</bitWidth>
          </field>
          <field>
            <name>FB11</name>
            <bitOffset>11</bitOffset>
            <bitWidth>1</bitWidth>
          </field>
          <field>
            <name>FB12</name>
            <bitOffset>12</bitOffset>
            <bitWidth>1</bitWidth>
          </field>
          <field>
            <name>FB13</name>
            <bitOffset>13</bitOffset>
            <bitWidth>1</bitWidth>
          </field>
          <field>
            <name>FB14</name>
            <bitOffset>14</bitOffset>
            <bitWidth>1</bitWidth>
          </field>
          <field>
            <name>FB15</name>
            <bitOffset>15</bitOffset>
            <bitWidth>1</bitWidth>
          </field>
          <field>
            <name>FB16</name>
            <bitOffset>16</bitOffset>
            <bitWidth>1</bitWidth>
          </field>
          <field>
            <name>FB17</name>
            <bitOffset>17</bitOffset>
            <bitWidth>1</bitWidth>
          </field>
          <field>
            <name>FB18</name>
            <bitOffset>18</bitOffset>
            <bitWidth>1</bitWidth>
          </field>
          <field>
            <name>FB19</name>
            <bitOffset>19</bitOffset>
            <bitWidth>1</bitWidth>
          </field>
          <field>
            <name>FB20</name>
            <bitOffset>20</bitOffset>
            <bitWidth>1</bitWidth>
          </field>
          <field>
            <name>FB21</name>
            <bitOffset>21</bitOffset>
            <bitWidth>1</bitWidth>
          </field>
          <field>
            <name>FB22</name>
            <bitOffset>22</bitOffset>
            <bitWidth>1</bitWidth>
          </field>
          <field>
            <name>FB23</name>
            <bitOffset>23</bitOffset>
            <bitWidth>1</bitWidth>
          </field>
          <field>
            <name>FB24</name>
            <bitOffset>24</bitOffset>
            <bitWidth>1</bitWidth>
          </field>
          <field>
            <name>FB25</name>
            <bitOffset>25</bitOffset>
            <bitWidth>1</bitWidth>
          </field>
          <field>
            <name>FB26</name>
            <bitOffset>26</bitOffset>
            <bitWidth>1</bitWidth>
          </field>
          <field>
            <name>FB27</name>
            <bitOffset>27</bitOffset>
            <bitWidth>1</bitWidth>
          </field>
          <field>
            <name>FB28</name>
            <bitOffset>28</bitOffset>
            <bitWidth>1</bitWidth>
          </field>
          <field>
            <name>FB29</name>
            <bitOffset>29</bitOffset>
            <bitWidth>1</bitWidth>
          </field>
          <field>
            <name>FB30</name>
            <bitOffset>30</bitOffset>
            <bitWidth>1</bitWidth>
          </field>
          <field>
            <name>FB31</name>
            <bitOffset>31</bitOffset>
            <bitWidth>1</bitWidth>
          </field>
        </fields>
      </register>
      <register>
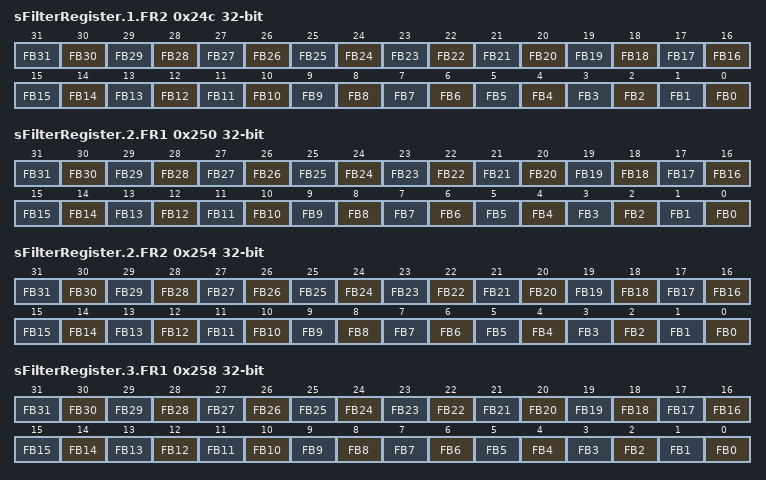
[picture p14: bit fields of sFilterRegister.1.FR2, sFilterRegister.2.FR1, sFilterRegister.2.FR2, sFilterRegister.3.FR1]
        <name>sFilterRegister.1.FR2</name>
        <addressOffset>0x24c</addressOffset>
        <size>0x20</size>
        <fields>
          <field>
            <name>FB0</name>
            <bitOffset>0</bitOffset>
            <bitWidth>1</bitWidth>
          </field>
          <field>
            <name>FB1</name>
            <bitOffset>1</bitOffset>
            <bitWidth>1</bitWidth>
          </field>
          <field>
            <name>FB2</name>
            <bitOffset>2</bitOffset>
            <bitWidth>1</bitWidth>
          </field>
          <field>
            <name>FB3</name>
            <bitOffset>3</bitOffset>
            <bitWidth>1</bitWidth>
          </field>
          <field>
            <name>FB4</name>
            <bitOffset>4</bitOffset>
            <bitWidth>1</bitWidth>
          </field>
          <field>
            <name>FB5</name>
            <bitOffset>5</bitOffset>
            <bitWidth>1</bitWidth>
          </field>
          <field>
            <name>FB6</name>
            <bitOffset>6</bitOffset>
            <bitWidth>1</bitWidth>
          </field>
          <field>
            <name>FB7</name>
            <bitOffset>7</bitOffset>
            <bitWidth>1</bitWidth>
          </field>
          <field>
            <name>FB8</name>
            <bitOffset>8</bitOffset>
            <bitWidth>1</bitWidth>
          </field>
          <field>
            <name>FB9</name>
            <bitOffset>9</bitOffset>
            <bitWidth>1</bitWidth>
          </field>
          <field>
            <name>FB10</name>
            <bitOffset>10</bitOffset>
            <bitWidth>1</bitWidth>
          </field>
          <field>
            <name>FB11</name>
            <bitOffset>11</bitOffset>
            <bitWidth>1</bitWidth>
          </field>
          <field>
            <name>FB12</name>
            <bitOffset>12</bitOffset>
            <bitWidth>1</bitWidth>
          </field>
          <field>
            <name>FB13</name>
            <bitOffset>13</bitOffset>
            <bitWidth>1</bitWidth>
          </field>
          <field>
            <name>FB14</name>
            <bitOffset>14</bitOffset>
            <bitWidth>1</bitWidth>
          </field>
          <field>
            <name>FB15</name>
            <bitOffset>15</bitOffset>
            <bitWidth>1</bitWidth>
          </field>
          <field>
            <name>FB16</name>
            <bitOffset>16</bitOffset>
            <bitWidth>1</bitWidth>
          </field>
          <field>
            <name>FB17</name>
            <bitOffset>17</bitOffset>
            <bitWidth>1</bitWidth>
          </field>
          <field>
            <name>FB18</name>
            <bitOffset>18</bitOffset>
            <bitWidth>1</bitWidth>
          </field>
          <field>
            <name>FB19</name>
            <bitOffset>19</bitOffset>
            <bitWidth>1</bitWidth>
          </field>
          <field>
            <name>FB20</name>
            <bitOffset>20</bitOffset>
            <bitWidth>1</bitWidth>
          </field>
          <field>
            <name>FB21</name>
            <bitOffset>21</bitOffset>
            <bitWidth>1</bitWidth>
          </field>
          <field>
            <name>FB22</name>
            <bitOffset>22</bitOffset>
            <bitWidth>1</bitWidth>
          </field>
          <field>
            <name>FB23</name>
            <bitOffset>23</bitOffset>
            <bitWidth>1</bitWidth>
          </field>
          <field>
            <name>FB24</name>
            <bitOffset>24</bitOffset>
            <bitWidth>1</bitWidth>
          </field>
          <field>
            <name>FB25</name>
            <bitOffset>25</bitOffset>
            <bitWidth>1</bitWidth>
          </field>
          <field>
            <name>FB26</name>
            <bitOffset>26</bitOffset>
            <bitWidth>1</bitWidth>
          </field>
          <field>
            <name>FB27</name>
            <bitOffset>27</bitOffset>
            <bitWidth>1</bitWidth>
          </field>
          <field>
            <name>FB28</name>
            <bitOffset>28</bitOffset>
            <bitWidth>1</bitWidth>
          </field>
          <field>
            <name>FB29</name>
            <bitOffset>29</bitOffset>
            <bitWidth>1</bitWidth>
          </field>
          <field>
            <name>FB30</name>
            <bitOffset>30</bitOffset>
            <bitWidth>1</bitWidth>
          </field>
          <field>
            <name>FB31</name>
            <bitOffset>31</bitOffset>
            <bitWidth>1</bitWidth>
          </field>
        </fields>
      </register>
      <register>
        <name>sFilterRegister.2.FR1</name>
        <addressOffset>0x250</addressOffset>
        <size>0x20</size>
        <fields>
          <field>
            <name>FB0</name>
            <bitOffset>0</bitOffset>
            <bitWidth>1</bitWidth>
          </field>
          <field>
            <name>FB1</name>
            <bitOffset>1</bitOffset>
            <bitWidth>1</bitWidth>
          </field>
          <field>
            <name>FB2</name>
            <bitOffset>2</bitOffset>
            <bitWidth>1</bitWidth>
          </field>
          <field>
            <name>FB3</name>
            <bitOffset>3</bitOffset>
            <bitWidth>1</bitWidth>
          </field>
          <field>
            <name>FB4</name>
            <bitOffset>4</bitOffset>
            <bitWidth>1</bitWidth>
          </field>
          <field>
            <name>FB5</name>
            <bitOffset>5</bitOffset>
            <bitWidth>1</bitWidth>
          </field>
          <field>
            <name>FB6</name>
            <bitOffset>6</bitOffset>
            <bitWidth>1</bitWidth>
          </field>
          <field>
            <name>FB7</name>
            <bitOffset>7</bitOffset>
            <bitWidth>1</bitWidth>
          </field>
          <field>
            <name>FB8</name>
            <bitOffset>8</bitOffset>
            <bitWidth>1</bitWidth>
          </field>
          <field>
            <name>FB9</name>
            <bitOffset>9</bitOffset>
            <bitWidth>1</bitWidth>
          </field>
          <field>
            <name>FB10</name>
            <bitOffset>10</bitOffset>
            <bitWidth>1</bitWidth>
          </field>
          <field>
            <name>FB11</name>
            <bitOffset>11</bitOffset>
            <bitWidth>1</bitWidth>
          </field>
          <field>
            <name>FB12</name>
            <bitOffset>12</bitOffset>
            <bitWidth>1</bitWidth>
          </field>
          <field>
            <name>FB13</name>
            <bitOffset>13</bitOffset>
            <bitWidth>1</bitWidth>
          </field>
          <field>
            <name>FB14</name>
            <bitOffset>14</bitOffset>
            <bitWidth>1</bitWidth>
          </field>
          <field>
            <name>FB15</name>
            <bitOffset>15</bitOffset>
            <bitWidth>1</bitWidth>
          </field>
          <field>
            <name>FB16</name>
            <bitOffset>16</bitOffset>
            <bitWidth>1</bitWidth>
          </field>
          <field>
            <name>FB17</name>
            <bitOffset>17</bitOffset>
            <bitWidth>1</bitWidth>
          </field>
          <field>
            <name>FB18</name>
            <bitOffset>18</bitOffset>
            <bitWidth>1</bitWidth>
          </field>
          <field>
            <name>FB19</name>
            <bitOffset>19</bitOffset>
            <bitWidth>1</bitWidth>
          </field>
          <field>
            <name>FB20</name>
            <bitOffset>20</bitOffset>
            <bitWidth>1</bitWidth>
          </field>
          <field>
            <name>FB21</name>
            <bitOffset>21</bitOffset>
            <bitWidth>1</bitWidth>
          </field>
          <field>
            <name>FB22</name>
            <bitOffset>22</bitOffset>
            <bitWidth>1</bitWidth>
          </field>
          <field>
            <name>FB23</name>
            <bitOffset>23</bitOffset>
            <bitWidth>1</bitWidth>
          </field>
          <field>
            <name>FB24</name>
            <bitOffset>24</bitOffset>
            <bitWidth>1</bitWidth>
          </field>
          <field>
            <name>FB25</name>
            <bitOffset>25</bitOffset>
            <bitWidth>1</bitWidth>
          </field>
          <field>
            <name>FB26</name>
            <bitOffset>26</bitOffset>
            <bitWidth>1</bitWidth>
          </field>
          <field>
            <name>FB27</name>
            <bitOffset>27</bitOffset>
            <bitWidth>1</bitWidth>
          </field>
          <field>
            <name>FB28</name>
            <bitOffset>28</bitOffset>
            <bitWidth>1</bitWidth>
          </field>
          <field>
            <name>FB29</name>
            <bitOffset>29</bitOffset>
            <bitWidth>1</bitWidth>
          </field>
          <field>
            <name>FB30</name>
            <bitOffset>30</bitOffset>
            <bitWidth>1</bitWidth>
          </field>
          <field>
            <name>FB31</name>
            <bitOffset>31</bitOffset>
            <bitWidth>1</bitWidth>
          </field>
        </fields>
      </register>
      <register>
        <name>sFilterRegister.2.FR2</name>
        <addressOffset>0x254</addressOffset>
        <size>0x20</size>
        <fields>
          <field>
            <name>FB0</name>
            <bitOffset>0</bitOffset>
            <bitWidth>1</bitWidth>
          </field>
          <field>
            <name>FB1</name>
            <bitOffset>1</bitOffset>
            <bitWidth>1</bitWidth>
          </field>
          <field>
            <name>FB2</name>
            <bitOffset>2</bitOffset>
            <bitWidth>1</bitWidth>
          </field>
          <field>
            <name>FB3</name>
            <bitOffset>3</bitOffset>
            <bitWidth>1</bitWidth>
          </field>
          <field>
            <name>FB4</name>
            <bitOffset>4</bitOffset>
            <bitWidth>1</bitWidth>
          </field>
          <field>
            <name>FB5</name>
            <bitOffset>5</bitOffset>
            <bitWidth>1</bitWidth>
          </field>
          <field>
            <name>FB6</name>
            <bitOffset>6</bitOffset>
            <bitWidth>1</bitWidth>
          </field>
          <field>
            <name>FB7</name>
            <bitOffset>7</bitOffset>
            <bitWidth>1</bitWidth>
          </field>
          <field>
            <name>FB8</name>
            <bitOffset>8</bitOffset>
            <bitWidth>1</bitWidth>
          </field>
          <field>
            <name>FB9</name>
            <bitOffset>9</bitOffset>
            <bitWidth>1</bitWidth>
          </field>
          <field>
            <name>FB10</name>
            <bitOffset>10</bitOffset>
            <bitWidth>1</bitWidth>
          </field>
          <field>
            <name>FB11</name>
            <bitOffset>11</bitOffset>
            <bitWidth>1</bitWidth>
          </field>
          <field>
            <name>FB12</name>
            <bitOffset>12</bitOffset>
            <bitWidth>1</bitWidth>
          </field>
          <field>
            <name>FB13</name>
            <bitOffset>13</bitOffset>
            <bitWidth>1</bitWidth>
          </field>
          <field>
            <name>FB14</name>
            <bitOffset>14</bitOffset>
            <bitWidth>1</bitWidth>
          </field>
          <field>
            <name>FB15</name>
            <bitOffset>15</bitOffset>
            <bitWidth>1</bitWidth>
          </field>
          <field>
            <name>FB16</name>
            <bitOffset>16</bitOffset>
            <bitWidth>1</bitWidth>
          </field>
          <field>
            <name>FB17</name>
            <bitOffset>17</bitOffset>
            <bitWidth>1</bitWidth>
          </field>
          <field>
            <name>FB18</name>
            <bitOffset>18</bitOffset>
            <bitWidth>1</bitWidth>
          </field>
          <field>
            <name>FB19</name>
            <bitOffset>19</bitOffset>
            <bitWidth>1</bitWidth>
          </field>
          <field>
            <name>FB20</name>
            <bitOffset>20</bitOffset>
            <bitWidth>1</bitWidth>
          </field>
          <field>
            <name>FB21</name>
            <bitOffset>21</bitOffset>
            <bitWidth>1</bitWidth>
          </field>
          <field>
            <name>FB22</name>
            <bitOffset>22</bitOffset>
            <bitWidth>1</bitWidth>
          </field>
          <field>
            <name>FB23</name>
            <bitOffset>23</bitOffset>
            <bitWidth>1</bitWidth>
          </field>
          <field>
            <name>FB24</name>
            <bitOffset>24</bitOffset>
            <bitWidth>1</bitWidth>
          </field>
          <field>
            <name>FB25</name>
            <bitOffset>25</bitOffset>
            <bitWidth>1</bitWidth>
          </field>
          <field>
            <name>FB26</name>
            <bitOffset>26</bitOffset>
            <bitWidth>1</bitWidth>
          </field>
          <field>
            <name>FB27</name>
            <bitOffset>27</bitOffset>
            <bitWidth>1</bitWidth>
          </field>
          <field>
            <name>FB28</name>
            <bitOffset>28</bitOffset>
            <bitWidth>1</bitWidth>
          </field>
          <field>
            <name>FB29</name>
            <bitOffset>29</bitOffset>
            <bitWidth>1</bitWidth>
          </field>
          <field>
            <name>FB30</name>
            <bitOffset>30</bitOffset>
            <bitWidth>1</bitWidth>
          </field>
          <field>
            <name>FB31</name>
            <bitOffset>31</bitOffset>
            <bitWidth>1</bitWidth>
          </field>
        </fields>
      </register>
      <register>
        <name>sFilterRegister.3.FR1</name>
        <addressOffset>0x258</addressOffset>
        <size>0x20</size>
        <fields>
          <field>
            <name>FB0</name>
            <bitOffset>0</bitOffset>
            <bitWidth>1</bitWidth>
          </field>
          <field>
            <name>FB1</name>
            <bitOffset>1</bitOffset>
            <bitWidth>1</bitWidth>
          </field>
          <field>
            <name>FB2</name>
            <bitOffset>2</bitOffset>
            <bitWidth>1</bitWidth>
          </field>
          <field>
            <name>FB3</name>
            <bitOffset>3</bitOffset>
            <bitWidth>1</bitWidth>
          </field>
          <field>
            <name>FB4</name>
            <bitOffset>4</bitOffset>
            <bitWidth>1</bitWidth>
          </field>
          <field>
            <name>FB5</name>
            <bitOffset>5</bitOffset>
            <bitWidth>1</bitWidth>
          </field>
          <field>
            <name>FB6</name>
            <bitOffset>6</bitOffset>
            <bitWidth>1</bitWidth>
          </field>
          <field>
            <name>FB7</name>
            <bitOffset>7</bitOffset>
            <bitWidth>1</bitWidth>
          </field>
          <field>
            <name>FB8</name>
            <bitOffset>8</bitOffset>
            <bitWidth>1</bitWidth>
          </field>
          <field>
            <name>FB9</name>
            <bitOffset>9</bitOffset>
            <bitWidth>1</bitWidth>
          </field>
          <field>
            <name>FB10</name>
            <bitOffset>10</bitOffset>
            <bitWidth>1</bitWidth>
          </field>
          <field>
            <name>FB11</name>
            <bitOffset>11</bitOffset>
            <bitWidth>1</bitWidth>
          </field>
          <field>
            <name>FB12</name>
            <bitOffset>12</bitOffset>
            <bitWidth>1</bitWidth>
          </field>
          <field>
            <name>FB13</name>
            <bitOffset>13</bitOffset>
            <bitWidth>1</bitWidth>
          </field>
          <field>
            <name>FB14</name>
            <bitOffset>14</bitOffset>
            <bitWidth>1</bitWidth>
          </field>
          <field>
            <name>FB15</name>
            <bitOffset>15</bitOffset>
            <bitWidth>1</bitWidth>
          </field>
          <field>
            <name>FB16</name>
            <bitOffset>16</bitOffset>
            <bitWidth>1</bitWidth>
          </field>
          <field>
            <name>FB17</name>
            <bitOffset>17</bitOffset>
            <bitWidth>1</bitWidth>
          </field>
          <field>
            <name>FB18</name>
            <bitOffset>18</bitOffset>
            <bitWidth>1</bitWidth>
          </field>
          <field>
            <name>FB19</name>
            <bitOffset>19</bitOffset>
            <bitWidth>1</bitWidth>
          </field>
          <field>
            <name>FB20</name>
            <bitOffset>20</bitOffset>
            <bitWidth>1</bitWidth>
          </field>
          <field>
            <name>FB21</name>
            <bitOffset>21</bitOffset>
            <bitWidth>1</bitWidth>
          </field>
          <field>
            <name>FB22</name>
            <bitOffset>22</bitOffset>
            <bitWidth>1</bitWidth>
          </field>
          <field>
            <name>FB23</name>
            <bitOffset>23</bitOffset>
            <bitWidth>1</bitWidth>
          </field>
          <field>
            <name>FB24</name>
            <bitOffset>24</bitOffset>
            <bitWidth>1</bitWidth>
          </field>
          <field>
            <name>FB25</name>
            <bitOffset>25</bitOffset>
            <bitWidth>1</bitWidth>
          </field>
          <field>
            <name>FB26</name>
            <bitOffset>26</bitOffset>
            <bitWidth>1</bitWidth>
          </field>
          <field>
            <name>FB27</name>
            <bitOffset>27</bitOffset>
            <bitWidth>1</bitWidth>
          </field>
          <field>
            <name>FB28</name>
            <bitOffset>28</bitOffset>
            <bitWidth>1</bitWidth>
          </field>
          <field>
            <name>FB29</name>
            <bitOffset>29</bitOffset>
            <bitWidth>1</bitWidth>
          </field>
          <field>
            <name>FB30</name>
            <bitOffset>30</bitOffset>
            <bitWidth>1</bitWidth>
          </field>
          <field>
            <name>FB31</name>
            <bitOffset>31</bitOffset>
            <bitWidth>1</bitWidth>
          </field>
        </fields>
      </register>
      <register>
        <name>sFilterRegister.3.FR2</name>
        <addressOffset>0x25c</addressOffset>
        <size>0x20</size>
        <fields>
          <field>
            <name>FB0</name>
            <bitOffset>0</bitOffset>
            <bitWidth>1</bitWidth>
          </field>
          <field>
            <name>FB1</name>
            <bitOffset>1</bitOffset>
            <bitWidth>1</bitWidth>
          </field>
          <field>
            <name>FB2</name>
            <bitOffset>2</bitOffset>
            <bitWidth>1</bitWidth>
          </field>
          <field>
            <name>FB3</name>
            <bitOffset>3</bitOffset>
            <bitWidth>1</bitWidth>
          </field>
          <field>
            <name>FB4</name>
            <bitOffset>4</bitOffset>
            <bitWidth>1</bitWidth>
          </field>
          <field>
            <name>FB5</name>
            <bitOffset>5</bitOffset>
            <bitWidth>1</bitWidth>
          </field>
          <field>
            <name>FB6</name>
            <bitOffset>6</bitOffset>
            <bitWidth>1</bitWidth>
          </field>
          <field>
            <name>FB7</name>
            <bitOffset>7</bitOffset>
            <bitWidth>1</bitWidth>
          </field>
          <field>
            <name>FB8</name>
            <bitOffset>8</bitOffset>
            <bitWidth>1</bitWidth>
          </field>
          <field>
            <name>FB9</name>
            <bitOffset>9</bitOffset>
            <bitWidth>1</bitWidth>
          </field>
          <field>
            <name>FB10</name>
            <bitOffset>10</bitOffset>
            <bitWidth>1</bitWidth>
          </field>
          <field>
            <name>FB11</name>
            <bitOffset>11</bitOffset>
            <bitWidth>1</bitWidth>
          </field>
          <field>
            <name>FB12</name>
            <bitOffset>12</bitOffset>
            <bitWidth>1</bitWidth>
          </field>
          <field>
            <name>FB13</name>
            <bitOffset>13</bitOffset>
            <bitWidth>1</bitWidth>
          </field>
          <field>
            <name>FB14</name>
            <bitOffset>14</bitOffset>
            <bitWidth>1</bitWidth>
          </field>
          <field>
            <name>FB15</name>
            <bitOffset>15</bitOffset>
            <bitWidth>1</bitWidth>
          </field>
          <field>
            <name>FB16</name>
            <bitOffset>16</bitOffset>
            <bitWidth>1</bitWidth>
          </field>
          <field>
            <name>FB17</name>
            <bitOffset>17</bitOffset>
            <bitWidth>1</bitWidth>
          </field>
          <field>
            <name>FB18</name>
            <bitOffset>18</bitOffset>
            <bitWidth>1</bitWidth>
          </field>
          <field>
            <name>FB19</name>
            <bitOffset>19</bitOffset>
            <bitWidth>1</bitWidth>
          </field>
          <field>
            <name>FB20</name>
            <bitOffset>20</bitOffset>
            <bitWidth>1</bitWidth>
          </field>
          <field>
            <name>FB21</name>
            <bitOffset>21</bitOffset>
            <bitWidth>1</bitWidth>
          </field>
          <field>
            <name>FB22</name>
            <bitOffset>22</bitOffset>
            <bitWidth>1</bitWidth>
          </field>
          <field>
            <name>FB23</name>
            <bitOffset>23</bitOffset>
            <bitWidth>1</bitWidth>
          </field>
          <field>
            <name>FB24</name>
            <bitOffset>24</bitOffset>
            <bitWidth>1</bitWidth>
          </field>
          <field>
            <name>FB25</name>
            <bitOffset>25</bitOffset>
            <bitWidth>1</bitWidth>
          </field>
          <field>
            <name>FB26</name>
            <bitOffset>26</bitOffset>
            <bitWidth>1</bitWidth>
          </field>
          <field>
            <name>FB27</name>
            <bitOffset>27</bitOffset>
            <bitWidth>1</bitWidth>
          </field>
          <field>
            <name>FB28</name>
            <bitOffset>28</bitOffset>
            <bitWidth>1</bitWidth>
          </field>
          <field>
            <name>FB29</name>
            <bitOffset>29</bitOffset>
            <bitWidth>1</bitWidth>
          </field>
          <field>
            <name>FB30</name>
            <bitOffset>30</bitOffset>
            <bitWidth>1</bitWidth>
          </field>
          <field>
            <name>FB31</name>
            <bitOffset>31</bitOffset>
            <bitWidth>1</bitWidth>
          </field>
        </fields>
      </register>
      <register>
        <name>sFilterRegister.4.FR1</name>
        <addressOffset>0x260</addressOffset>
        <size>0x20</size>
        <fields>
          <field>
            <name>FB0</name>
            <bitOffset>0</bitOffset>
            <bitWidth>1</bitWidth>
          </field>
          <field>
            <name>FB1</name>
            <bitOffset>1</bitOffset>
            <bitWidth>1</bitWidth>
          </field>
          <field>
            <name>FB2</name>
            <bitOffset>2</bitOffset>
            <bitWidth>1</bitWidth>
          </field>
          <field>
            <name>FB3</name>
            <bitOffset>3</bitOffset>
            <bitWidth>1</bitWidth>
          </field>
          <field>
            <name>FB4</name>
            <bitOffset>4</bitOffset>
            <bitWidth>1</bitWidth>
          </field>
          <field>
            <name>FB5</name>
            <bitOffset>5</bitOffset>
            <bitWidth>1</bitWidth>
          </field>
          <field>
            <name>FB6</name>
            <bitOffset>6</bitOffset>
            <bitWidth>1</bitWidth>
          </field>
          <field>
            <name>FB7</name>
            <bitOffset>7</bitOffset>
            <bitWidth>1</bitWidth>
          </field>
          <field>
            <name>FB8</name>
            <bitOffset>8</bitOffset>
            <bitWidth>1</bitWidth>
          </field>
          <field>
            <name>FB9</name>
            <bitOffset>9</bitOffset>
            <bitWidth>1</bitWidth>
          </field>
          <field>
            <name>FB10</name>
            <bitOffset>10</bitOffset>
            <bitWidth>1</bitWidth>
          </field>
          <field>
            <name>FB11</name>
            <bitOffset>11</bitOffset>
            <bitWidth>1</bitWidth>
          </field>
          <field>
            <name>FB12</name>
            <bitOffset>12</bitOffset>
            <bitWidth>1</bitWidth>
          </field>
          <field>
            <name>FB13</name>
            <bitOffset>13</bitOffset>
            <bitWidth>1</bitWidth>
          </field>
          <field>
            <name>FB14</name>
            <bitOffset>14</bitOffset>
            <bitWidth>1</bitWidth>
          </field>
          <field>
            <name>FB15</name>
            <bitOffset>15</bitOffset>
            <bitWidth>1</bitWidth>
          </field>
          <field>
            <name>FB16</name>
            <bitOffset>16</bitOffset>
            <bitWidth>1</bitWidth>
          </field>
          <field>
            <name>FB17</name>
            <bitOffset>17</bitOffset>
            <bitWidth>1</bitWidth>
          </field>
          <field>
            <name>FB18</name>
            <bitOffset>18</bitOffset>
            <bitWidth>1</bitWidth>
          </field>
          <field>
            <name>FB19</name>
            <bitOffset>19</bitOffset>
            <bitWidth>1</bitWidth>
          </field>
          <field>
            <name>FB20</name>
            <bitOffset>20</bitOffset>
            <bitWidth>1</bitWidth>
          </field>
          <field>
            <name>FB21</name>
            <bitOffset>21</bitOffset>
            <bitWidth>1</bitWidth>
          </field>
          <field>
            <name>FB22</name>
            <bitOffset>22</bitOffset>
            <bitWidth>1</bitWidth>
          </field>
          <field>
            <name>FB23</name>
            <bitOffset>23</bitOffset>
            <bitWidth>1</bitWidth>
          </field>
          <field>
            <name>FB24</name>
            <bitOffset>24</bitOffset>
            <bitWidth>1</bitWidth>
          </field>
          <field>
            <name>FB25</name>
            <bitOffset>25</bitOffset>
            <bitWidth>1</bitWidth>
          </field>
          <field>
            <name>FB26</name>
            <bitOffset>26</bitOffset>
            <bitWidth>1</bitWidth>
          </field>
          <field>
            <name>FB27</name>
            <bitOffset>27</bitOffset>
            <bitWidth>1</bitWidth>
          </field>
          <field>
            <name>FB28</name>
            <bitOffset>28</bitOffset>
            <bitWidth>1</bitWidth>
          </field>
          <field>
            <name>FB29</name>
            <bitOffset>29</bitOffset>
            <bitWidth>1</bitWidth>
          </field>
          <field>
            <name>FB30</name>
            <bitOffset>30</bitOffset>
            <bitWidth>1</bitWidth>
          </field>
          <field>
            <name>FB31</name>
            <bitOffset>31</bitOffset>
            <bitWidth>1</bitWidth>
          </field>
        </fields>
      </register>
      <register>
        <name>sFilterRegister.4.FR2</name>
        <addressOffset>0x264</addressOffset>
        <size>0x20</size>
        <fields>
          <field>
            <name>FB0</name>
            <bitOffset>0</bitOffset>
            <bitWidth>1</bitWidth>
          </field>
          <field>
            <name>FB1</name>
            <bitOffset>1</bitOffset>
            <bitWidth>1</bitWidth>
          </field>
          <field>
            <name>FB2</name>
            <bitOffset>2</bitOffset>
            <bitWidth>1</bitWidth>
          </field>
          <field>
            <name>FB3</name>
            <bitOffset>3</bitOffset>
            <bitWidth>1</bitWidth>
          </field>
          <field>
            <name>FB4</name>
            <bitOffset>4</bitOffset>
            <bitWidth>1</bitWidth>
          </field>
          <field>
            <name>FB5</name>
            <bitOffset>5</bitOffset>
            <bitWidth>1</bitWidth>
          </field>
          <field>
            <name>FB6</name>
            <bitOffset>6</bitOffset>
            <bitWidth>1</bitWidth>
          </field>
          <field>
            <name>FB7</name>
            <bitOffset>7</bitOffset>
            <bitWidth>1</bitWidth>
          </field>
          <field>
            <name>FB8</name>
            <bitOffset>8</bitOffset>
            <bitWidth>1</bitWidth>
          </field>
          <field>
            <name>FB9</name>
            <bitOffset>9</bitOffset>
            <bitWidth>1</bitWidth>
          </field>
          <field>
            <name>FB10</name>
            <bitOffset>10</bitOffset>
            <bitWidth>1</bitWidth>
          </field>
          <field>
            <name>FB11</name>
            <bitOffset>11</bitOffset>
            <bitWidth>1</bitWidth>
          </field>
          <field>
            <name>FB12</name>
            <bitOffset>12</bitOffset>
            <bitWidth>1</bitWidth>
          </field>
          <field>
            <name>FB13</name>
            <bitOffset>13</bitOffset>
            <bitWidth>1</bitWidth>
          </field>
          <field>
            <name>FB14</name>
            <bitOffset>14</bitOffset>
            <bitWidth>1</bitWidth>
          </field>
          <field>
            <name>FB15</name>
            <bitOffset>15</bitOffset>
            <bitWidth>1</bitWidth>
          </field>
          <field>
            <name>FB16</name>
            <bitOffset>16</bitOffset>
            <bitWidth>1</bitWidth>
          </field>
          <field>
            <name>FB17</name>
            <bitOffset>17</bitOffset>
            <bitWidth>1</bitWidth>
          </field>
          <field>
            <name>FB18</name>
            <bitOffset>18</bitOffset>
            <bitWidth>1</bitWidth>
          </field>
          <field>
            <name>FB19</name>
            <bitOffset>19</bitOffset>
            <bitWidth>1</bitWidth>
          </field>
          <field>
            <name>FB20</name>
            <bitOffset>20</bitOffset>
            <bitWidth>1</bitWidth>
          </field>
          <field>
            <name>FB21</name>
            <bitOffset>21</bitOffset>
            <bitWidth>1</bitWidth>
          </field>
          <field>
            <name>FB22</name>
            <bitOffset>22</bitOffset>
            <bitWidth>1</bitWidth>
          </field>
          <field>
            <name>FB23</name>
            <bitOffset>23</bitOffset>
            <bitWidth>1</bitWidth>
          </field>
          <field>
            <name>FB24</name>
            <bitOffset>24</bitOffset>
            <bitWidth>1</bitWidth>
          </field>
          <field>
            <name>FB25</name>
            <bitOffset>25</bitOffset>
            <bitWidth>1</bitWidth>
          </field>
          <field>
            <name>FB26</name>
            <bitOffset>26</bitOffset>
            <bitWidth>1</bitWidth>
          </field>
          <field>
            <name>FB27</name>
            <bitOffset>27</bitOffset>
            <bitWidth>1</bitWidth>
          </field>
          <field>
            <name>FB28</name>
            <bitOffset>28</bitOffset>
            <bitWidth>1</bitWidth>
          </field>
          <field>
            <name>FB29</name>
            <bitOffset>29</bitOffset>
            <bitWidth>1</bitWidth>
          </field>
          <field>
            <name>FB30</name>
            <bitOffset>30</bitOffset>
            <bitWidth>1</bitWidth>
          </field>
          <field>
            <name>FB31</name>
            <bitOffset>31</bitOffset>
            <bitWidth>1</bitWidth>
          </field>
        </fields>
      </register>
      <register>
        <name>sFilterRegister.5.FR1</name>
        <addressOffset>0x268</addressOffset>
        <size>0x20</size>
        <fields>
          <field>
            <name>FB0</name>
            <bitOffset>0</bitOffset>
            <bitWidth>1</bitWidth>
          </field>
          <field>
            <name>FB1</name>
            <bitOffset>1</bitOffset>
            <bitWidth>1</bitWidth>
          </field>
          <field>
            <name>FB2</name>
            <bitOffset>2</bitOffset>
            <bitWidth>1</bitWidth>
          </field>
          <field>
            <name>FB3</name>
            <bitOffset>3</bitOffset>
            <bitWidth>1</bitWidth>
          </field>
          <field>
            <name>FB4</name>
            <bitOffset>4</bitOffset>
            <bitWidth>1</bitWidth>
          </field>
          <field>
            <name>FB5</name>
            <bitOffset>5</bitOffset>
            <bitWidth>1</bitWidth>
          </field>
          <field>
            <name>FB6</name>
            <bitOffset>6</bitOffset>
            <bitWidth>1</bitWidth>
          </field>
          <field>
            <name>FB7</name>
            <bitOffset>7</bitOffset>
            <bitWidth>1</bitWidth>
          </field>
          <field>
            <name>FB8</name>
            <bitOffset>8</bitOffset>
            <bitWidth>1</bitWidth>
          </field>
          <field>
            <name>FB9</name>
            <bitOffset>9</bitOffset>
            <bitWidth>1</bitWidth>
          </field>
          <field>
            <name>FB10</name>
            <bitOffset>10</bitOffset>
            <bitWidth>1</bitWidth>
          </field>
          <field>
            <name>FB11</name>
            <bitOffset>11</bitOffset>
            <bitWidth>1</bitWidth>
          </field>
          <field>
            <name>FB12</name>
            <bitOffset>12</bitOffset>
            <bitWidth>1</bitWidth>
          </field>
          <field>
            <name>FB13</name>
            <bitOffset>13</bitOffset>
            <bitWidth>1</bitWidth>
          </field>
          <field>
            <name>FB14</name>
            <bitOffset>14</bitOffset>
            <bitWidth>1</bitWidth>
          </field>
          <field>
            <name>FB15</name>
            <bitOffset>15</bitOffset>
            <bitWidth>1</bitWidth>
          </field>
          <field>
            <name>FB16</name>
            <bitOffset>16</bitOffset>
            <bitWidth>1</bitWidth>
          </field>
          <field>
            <name>FB17</name>
            <bitOffset>17</bitOffset>
            <bitWidth>1</bitWidth>
          </field>
          <field>
            <name>FB18</name>
            <bitOffset>18</bitOffset>
            <bitWidth>1</bitWidth>
          </field>
          <field>
            <name>FB19</name>
            <bitOffset>19</bitOffset>
            <bitWidth>1</bitWidth>
          </field>
          <field>
            <name>FB20</name>
            <bitOffset>20</bitOffset>
            <bitWidth>1</bitWidth>
          </field>
          <field>
            <name>FB21</name>
            <bitOffset>21</bitOffset>
            <bitWidth>1</bitWidth>
          </field>
          <field>
            <name>FB22</name>
            <bitOffset>22</bitOffset>
            <bitWidth>1</bitWidth>
          </field>
          <field>
            <name>FB23</name>
            <bitOffset>23</bitOffset>
            <bitWidth>1</bitWidth>
          </field>
          <field>
            <name>FB24</name>
            <bitOffset>24</bitOffset>
            <bitWidth>1</bitWidth>
          </field>
          <field>
            <name>FB25</name>
            <bitOffset>25</bitOffset>
            <bitWidth>1</bitWidth>
          </field>
          <field>
            <name>FB26</name>
            <bitOffset>26</bitOffset>
            <bitWidth>1</bitWidth>
          </field>
          <field>
            <name>FB27</name>
            <bitOffset>27</bitOffset>
            <bitWidth>1</bitWidth>
          </field>
          <field>
            <name>FB28</name>
            <bitOffset>28</bitOffset>
            <bitWidth>1</bitWidth>
          </field>
          <field>
            <name>FB29</name>
            <bitOffset>29</bitOffset>
            <bitWidth>1</bitWidth>
          </field>
          <field>
            <name>FB30</name>
            <bitOffset>30</bitOffset>
            <bitWidth>1</bitWidth>
          </field>
          <field>
            <name>FB31</name>
            <bitOffset>31</bitOffset>
            <bitWidth>1</bitWidth>
          </field>
        </fields>
      </register>
      <register>
        <name>sFilterRegister.5.FR2</name>
        <addressOffset>0x26c</addressOffset>
        <size>0x20</size>
        <fields>
          <field>
            <name>FB0</name>
            <bitOffset>0</bitOffset>
            <bitWidth>1</bitWidth>
          </field>
          <field>
            <name>FB1</name>
            <bitOffset>1</bitOffset>
            <bitWidth>1</bitWidth>
          </field>
          <field>
            <name>FB2</name>
            <bitOffset>2</bitOffset>
            <bitWidth>1</bitWidth>
          </field>
          <field>
            <name>FB3</name>
            <bitOffset>3</bitOffset>
            <bitWidth>1</bitWidth>
          </field>
          <field>
            <name>FB4</name>
            <bitOffset>4</bitOffset>
            <bitWidth>1</bitWidth>
          </field>
          <field>
            <name>FB5</name>
            <bitOffset>5</bitOffset>
            <bitWidth>1</bitWidth>
          </field>
          <field>
            <name>FB6</name>
            <bitOffset>6</bitOffset>
            <bitWidth>1</bitWidth>
          </field>
          <field>
            <name>FB7</name>
            <bitOffset>7</bitOffset>
            <bitWidth>1</bitWidth>
          </field>
          <field>
            <name>FB8</name>
            <bitOffset>8</bitOffset>
            <bitWidth>1</bitWidth>
          </field>
          <field>
            <name>FB9</name>
            <bitOffset>9</bitOffset>
            <bitWidth>1</bitWidth>
          </field>
          <field>
            <name>FB10</name>
            <bitOffset>10</bitOffset>
            <bitWidth>1</bitWidth>
          </field>
          <field>
            <name>FB11</name>
            <bitOffset>11</bitOffset>
            <bitWidth>1</bitWidth>
          </field>
          <field>
            <name>FB12</name>
            <bitOffset>12</bitOffset>
            <bitWidth>1</bitWidth>
          </field>
          <field>
            <name>FB13</name>
            <bitOffset>13</bitOffset>
            <bitWidth>1</bitWidth>
          </field>
          <field>
            <name>FB14</name>
            <bitOffset>14</bitOffset>
            <bitWidth>1</bitWidth>
          </field>
          <field>
            <name>FB15</name>
            <bitOffset>15</bitOffset>
            <bitWidth>1</bitWidth>
          </field>
          <field>
            <name>FB16</name>
            <bitOffset>16</bitOffset>
            <bitWidth>1</bitWidth>
          </field>
          <field>
            <name>FB17</name>
            <bitOffset>17</bitOffset>
            <bitWidth>1</bitWidth>
          </field>
          <field>
            <name>FB18</name>
            <bitOffset>18</bitOffset>
            <bitWidth>1</bitWidth>
          </field>
          <field>
            <name>FB19</name>
            <bitOffset>19</bitOffset>
            <bitWidth>1</bitWidth>
          </field>
          <field>
            <name>FB20</name>
            <bitOffset>20</bitOffset>
            <bitWidth>1</bitWidth>
          </field>
          <field>
            <name>FB21</name>
            <bitOffset>21</bitOffset>
            <bitWidth>1</bitWidth>
          </field>
          <field>
            <name>FB22</name>
            <bitOffset>22</bitOffset>
            <bitWidth>1</bitWidth>
          </field>
          <field>
            <name>FB23</name>
            <bitOffset>23</bitOffset>
            <bitWidth>1</bitWidth>
          </field>
          <field>
            <name>FB24</name>
            <bitOffset>24</bitOffset>
            <bitWidth>1</bitWidth>
          </field>
          <field>
            <name>FB25</name>
            <bitOffset>25</bitOffset>
            <bitWidth>1</bitWidth>
          </field>
          <field>
            <name>FB26</name>
            <bitOffset>26</bitOffset>
            <bitWidth>1</bitWidth>
          </field>
          <field>
            <name>FB27</name>
            <bitOffset>27</bitOffset>
            <bitWidth>1</bitWidth>
          </field>
          <field>
            <name>FB28</name>
            <bitOffset>28</bitOffset>
            <bitWidth>1</bitWidth>
          </field>
          <field>
            <name>FB29</name>
            <bitOffset>29</bitOffset>
            <bitWidth>1</bitWidth>
          </field>
          <field>
            <name>FB30</name>
            <bitOffset>30</bitOffset>
            <bitWidth>1</bitWidth>
          </field>
          <field>
            <name>FB31</name>
            <bitOffset>31</bitOffset>
            <bitWidth>1</bitWidth>
          </field>
        </fields>
      </register>
      <register>
        <name>sFilterRegister.6.FR1</name>
        <addressOffset>0x270</addressOffset>
        <size>0x20</size>
        <fields>
          <field>
            <name>FB0</name>
            <bitOffset>0</bitOffset>
            <bitWidth>1</bitWidth>
          </field>
          <field>
            <name>FB1</name>
            <bitOffset>1</bitOffset>
            <bitWidth>1</bitWidth>
          </field>
          <field>
            <name>FB2</name>
            <bitOffset>2</bitOffset>
            <bitWidth>1</bitWidth>
          </field>
          <field>
            <name>FB3</name>
            <bitOffset>3</bitOffset>
            <bitWidth>1</bitWidth>
          </field>
          <field>
            <name>FB4</name>
            <bitOffset>4</bitOffset>
            <bitWidth>1</bitWidth>
          </field>
          <field>
            <name>FB5</name>
            <bitOffset>5</bitOffset>
            <bitWidth>1</bitWidth>
          </field>
          <field>
            <name>FB6</name>
            <bitOffset>6</bitOffset>
            <bitWidth>1</bitWidth>
          </field>
          <field>
            <name>FB7</name>
            <bitOffset>7</bitOffset>
            <bitWidth>1</bitWidth>
          </field>
          <field>
            <name>FB8</name>
            <bitOffset>8</bitOffset>
            <bitWidth>1</bitWidth>
          </field>
          <field>
            <name>FB9</name>
            <bitOffset>9</bitOffset>
            <bitWidth>1</bitWidth>
          </field>
          <field>
            <name>FB10</name>
            <bitOffset>10</bitOffset>
            <bitWidth>1</bitWidth>
          </field>
          <field>
            <name>FB11</name>
            <bitOffset>11</bitOffset>
            <bitWidth>1</bitWidth>
          </field>
          <field>
            <name>FB12</name>
            <bitOffset>12</bitOffset>
            <bitWidth>1</bitWidth>
          </field>
          <field>
            <name>FB13</name>
            <bitOffset>13</bitOffset>
            <bitWidth>1</bitWidth>
          </field>
          <field>
            <name>FB14</name>
            <bitOffset>14</bitOffset>
            <bitWidth>1</bitWidth>
          </field>
          <field>
            <name>FB15</name>
            <bitOffset>15</bitOffset>
            <bitWidth>1</bitWidth>
          </field>
          <field>
            <name>FB16</name>
            <bitOffset>16</bitOffset>
            <bitWidth>1</bitWidth>
          </field>
          <field>
            <name>FB17</name>
            <bitOffset>17</bitOffset>
            <bitWidth>1</bitWidth>
          </field>
          <field>
            <name>FB18</name>
            <bitOffset>18</bitOffset>
            <bitWidth>1</bitWidth>
          </field>
          <field>
            <name>FB19</name>
            <bitOffset>19</bitOffset>
            <bitWidth>1</bitWidth>
          </field>
          <field>
            <name>FB20</name>
            <bitOffset>20</bitOffset>
            <bitWidth>1</bitWidth>
          </field>
          <field>
            <name>FB21</name>
            <bitOffset>21</bitOffset>
            <bitWidth>1</bitWidth>
          </field>
          <field>
            <name>FB22</name>
            <bitOffset>22</bitOffset>
            <bitWidth>1</bitWidth>
          </field>
          <field>
            <name>FB23</name>
            <bitOffset>23</bitOffset>
            <bitWidth>1</bitWidth>
          </field>
          <field>
            <name>FB24</name>
            <bitOffset>24</bitOffset>
            <bitWidth>1</bitWidth>
          </field>
          <field>
            <name>FB25</name>
            <bitOffset>25</bitOffset>
            <bitWidth>1</bitWidth>
          </field>
          <field>
            <name>FB26</name>
            <bitOffset>26</bitOffset>
            <bitWidth>1</bitWidth>
          </field>
          <field>
            <name>FB27</name>
            <bitOffset>27</bitOffset>
            <bitWidth>1</bitWidth>
          </field>
          <field>
            <name>FB28</name>
            <bitOffset>28</bitOffset>
            <bitWidth>1</bitWidth>
          </field>
          <field>
            <name>FB29</name>
            <bitOffset>29</bitOffset>
            <bitWidth>1</bitWidth>
          </field>
          <field>
            <name>FB30</name>
            <bitOffset>30</bitOffset>
            <bitWidth>1</bitWidth>
          </field>
          <field>
            <name>FB31</name>
            <bitOffset>31</bitOffset>
            <bitWidth>1</bitWidth>
          </field>
        </fields>
      </register>
      <register>
        <name>sFilterRegister.6.FR2</name>
        <addressOffset>0x274</addressOffset>
        <size>0x20</size>
        <fields>
          <field>
            <name>FB0</name>
            <bitOffset>0</bitOffset>
            <bitWidth>1</bitWidth>
          </field>
          <field>
            <name>FB1</name>
            <bitOffset>1</bitOffset>
            <bitWidth>1</bitWidth>
          </field>
          <field>
            <name>FB2</name>
            <bitOffset>2</bitOffset>
            <bitWidth>1</bitWidth>
          </field>
          <field>
            <name>FB3</name>
            <bitOffset>3</bitOffset>
            <bitWidth>1</bitWidth>
          </field>
          <field>
            <name>FB4</name>
            <bitOffset>4</bitOffset>
            <bitWidth>1</bitWidth>
          </field>
          <field>
            <name>FB5</name>
            <bitOffset>5</bitOffset>
            <bitWidth>1</bitWidth>
          </field>
          <field>
            <name>FB6</name>
            <bitOffset>6</bitOffset>
            <bitWidth>1</bitWidth>
          </field>
          <field>
            <name>FB7</name>
            <bitOffset>7</bitOffset>
            <bitWidth>1</bitWidth>
          </field>
          <field>
            <name>FB8</name>
            <bitOffset>8</bitOffset>
            <bitWidth>1</bitWidth>
          </field>
          <field>
            <name>FB9</name>
            <bitOffset>9</bitOffset>
            <bitWidth>1</bitWidth>
          </field>
          <field>
            <name>FB10</name>
            <bitOffset>10</bitOffset>
            <bitWidth>1</bitWidth>
          </field>
          <field>
            <name>FB11</name>
            <bitOffset>11</bitOffset>
            <bitWidth>1</bitWidth>
          </field>
          <field>
            <name>FB12</name>
            <bitOffset>12</bitOffset>
            <bitWidth>1</bitWidth>
          </field>
          <field>
            <name>FB13</name>
            <bitOffset>13</bitOffset>
            <bitWidth>1</bitWidth>
          </field>
          <field>
            <name>FB14</name>
            <bitOffset>14</bitOffset>
            <bitWidth>1</bitWidth>
          </field>
          <field>
            <name>FB15</name>
            <bitOffset>15</bitOffset>
            <bitWidth>1</bitWidth>
          </field>
          <field>
            <name>FB16</name>
            <bitOffset>16</bitOffset>
            <bitWidth>1</bitWidth>
          </field>
          <field>
            <name>FB17</name>
            <bitOffset>17</bitOffset>
            <bitWidth>1</bitWidth>
          </field>
          <field>
            <name>FB18</name>
            <bitOffset>18</bitOffset>
            <bitWidth>1</bitWidth>
          </field>
          <field>
            <name>FB19</name>
            <bitOffset>19</bitOffset>
            <bitWidth>1</bitWidth>
          </field>
          <field>
            <name>FB20</name>
            <bitOffset>20</bitOffset>
            <bitWidth>1</bitWidth>
          </field>
          <field>
            <name>FB21</name>
            <bitOffset>21</bitOffset>
            <bitWidth>1</bitWidth>
          </field>
          <field>
            <name>FB22</name>
            <bitOffset>22</bitOffset>
            <bitWidth>1</bitWidth>
          </field>
          <field>
            <name>FB23</name>
            <bitOffset>23</bitOffset>
            <bitWidth>1</bitWidth>
          </field>
          <field>
            <name>FB24</name>
            <bitOffset>24</bitOffset>
            <bitWidth>1</bitWidth>
          </field>
          <field>
            <name>FB25</name>
            <bitOffset>25</bitOffset>
            <bitWidth>1</bitWidth>
          </field>
          <field>
            <name>FB26</name>
            <bitOffset>26</bitOffset>
            <bitWidth>1</bitWidth>
          </field>
          <field>
            <name>FB27</name>
            <bitOffset>27</bitOffset>
            <bitWidth>1</bitWidth>
          </field>
          <field>
            <name>FB28</name>
            <bitOffset>28</bitOffset>
            <bitWidth>1</bitWidth>
          </field>
          <field>
            <name>FB29</name>
            <bitOffset>29</bitOffset>
            <bitWidth>1</bitWidth>
          </field>
          <field>
            <name>FB30</name>
            <bitOffset>30</bitOffset>
            <bitWidth>1</bitWidth>
          </field>
          <field>
            <name>FB31</name>
            <bitOffset>31</bitOffset>
            <bitWidth>1</bitWidth>
          </field>
        </fields>
      </register>
      <register>
        <name>sFilterRegister.7.FR1</name>
        <addressOffset>0x278</addressOffset>
        <size>0x20</size>
        <fields>
          <field>
            <name>FB0</name>
            <bitOffset>0</bitOffset>
            <bitWidth>1</bitWidth>
          </field>
          <field>
            <name>FB1</name>
            <bitOffset>1</bitOffset>
            <bitWidth>1</bitWidth>
          </field>
          <field>
            <name>FB2</name>
            <bitOffset>2</bitOffset>
            <bitWidth>1</bitWidth>
          </field>
          <field>
            <name>FB3</name>
            <bitOffset>3</bitOffset>
            <bitWidth>1</bitWidth>
          </field>
          <field>
            <name>FB4</name>
            <bitOffset>4</bitOffset>
            <bitWidth>1</bitWidth>
          </field>
          <field>
            <name>FB5</name>
            <bitOffset>5</bitOffset>
            <bitWidth>1</bitWidth>
          </field>
          <field>
            <name>FB6</name>
            <bitOffset>6</bitOffset>
            <bitWidth>1</bitWidth>
          </field>
          <field>
            <name>FB7</name>
            <bitOffset>7</bitOffset>
            <bitWidth>1</bitWidth>
          </field>
          <field>
            <name>FB8</name>
            <bitOffset>8</bitOffset>
            <bitWidth>1</bitWidth>
          </field>
          <field>
            <name>FB9</name>
            <bitOffset>9</bitOffset>
            <bitWidth>1</bitWidth>
          </field>
          <field>
            <name>FB10</name>
            <bitOffset>10</bitOffset>
            <bitWidth>1</bitWidth>
          </field>
          <field>
            <name>FB11</name>
            <bitOffset>11</bitOffset>
            <bitWidth>1</bitWidth>
          </field>
          <field>
            <name>FB12</name>
            <bitOffset>12</bitOffset>
            <bitWidth>1</bitWidth>
          </field>
          <field>
            <name>FB13</name>
            <bitOffset>13</bitOffset>
            <bitWidth>1</bitWidth>
          </field>
          <field>
            <name>FB14</name>
            <bitOffset>14</bitOffset>
            <bitWidth>1</bitWidth>
          </field>
          <field>
            <name>FB15</name>
            <bitOffset>15</bitOffset>
            <bitWidth>1</bitWidth>
          </field>
          <field>
            <name>FB16</name>
            <bitOffset>16</bitOffset>
            <bitWidth>1</bitWidth>
          </field>
          <field>
            <name>FB17</name>
            <bitOffset>17</bitOffset>
            <bitWidth>1</bitWidth>
          </field>
          <field>
            <name>FB18</name>
            <bitOffset>18</bitOffset>
            <bitWidth>1</bitWidth>
          </field>
          <field>
            <name>FB19</name>
            <bitOffset>19</bitOffset>
            <bitWidth>1</bitWidth>
          </field>
          <field>
            <name>FB20</name>
            <bitOffset>20</bitOffset>
            <bitWidth>1</bitWidth>
          </field>
          <field>
            <name>FB21</name>
            <bitOffset>21</bitOffset>
            <bitWidth>1</bitWidth>
          </field>
          <field>
            <name>FB22</name>
            <bitOffset>22</bitOffset>
            <bitWidth>1</bitWidth>
          </field>
          <field>
            <name>FB23</name>
            <bitOffset>23</bitOffset>
            <bitWidth>1</bitWidth>
          </field>
          <field>
            <name>FB24</name>
            <bitOffset>24</bitOffset>
            <bitWidth>1</bitWidth>
          </field>
          <field>
            <name>FB25</name>
            <bitOffset>25</bitOffset>
            <bitWidth>1</bitWidth>
          </field>
          <field>
            <name>FB26</name>
            <bitOffset>26</bitOffset>
            <bitWidth>1</bitWidth>
          </field>
          <field>
            <name>FB27</name>
            <bitOffset>27</bitOffset>
            <bitWidth>1</bitWidth>
          </field>
          <field>
            <name>FB28</name>
            <bitOffset>28</bitOffset>
            <bitWidth>1</bitWidth>
          </field>
          <field>
            <name>FB29</name>
            <bitOffset>29</bitOffset>
            <bitWidth>1</bitWidth>
          </field>
          <field>
            <name>FB30</name>
            <bitOffset>30</bitOffset>
            <bitWidth>1</bitWidth>
          </field>
          <field>
            <name>FB31</name>
            <bitOffset>31</bitOffset>
            <bitWidth>1</bitWidth>
          </field>
        </fields>
      </register>
      <register>
        <name>sFilterRegister.7.FR2</name>
        <addressOffset>0x27c</addressOffset>
        <size>0x20</size>
        <fields>
          <field>
            <name>FB0</name>
            <bitOffset>0</bitOffset>
            <bitWidth>1</bitWidth>
          </field>
          <field>
            <name>FB1</name>
            <bitOffset>1</bitOffset>
            <bitWidth>1</bitWidth>
          </field>
          <field>
            <name>FB2</name>
            <bitOffset>2</bitOffset>
            <bitWidth>1</bitWidth>
          </field>
          <field>
            <name>FB3</name>
            <bitOffset>3</bitOffset>
            <bitWidth>1</bitWidth>
          </field>
          <field>
            <name>FB4</name>
            <bitOffset>4</bitOffset>
            <bitWidth>1</bitWidth>
          </field>
          <field>
            <name>FB5</name>
            <bitOffset>5</bitOffset>
            <bitWidth>1</bitWidth>
          </field>
          <field>
            <name>FB6</name>
            <bitOffset>6</bitOffset>
            <bitWidth>1</bitWidth>
          </field>
          <field>
            <name>FB7</name>
            <bitOffset>7</bitOffset>
            <bitWidth>1</bitWidth>
          </field>
          <field>
            <name>FB8</name>
            <bitOffset>8</bitOffset>
            <bitWidth>1</bitWidth>
          </field>
          <field>
            <name>FB9</name>
            <bitOffset>9</bitOffset>
            <bitWidth>1</bitWidth>
          </field>
          <field>
            <name>FB10</name>
            <bitOffset>10</bitOffset>
            <bitWidth>1</bitWidth>
          </field>
          <field>
            <name>FB11</name>
            <bitOffset>11</bitOffset>
            <bitWidth>1</bitWidth>
          </field>
          <field>
            <name>FB12</name>
            <bitOffset>12</bitOffset>
            <bitWidth>1</bitWidth>
          </field>
          <field>
            <name>FB13</name>
            <bitOffset>13</bitOffset>
            <bitWidth>1</bitWidth>
          </field>
          <field>
            <name>FB14</name>
            <bitOffset>14</bitOffset>
            <bitWidth>1</bitWidth>
          </field>
          <field>
            <name>FB15</name>
            <bitOffset>15</bitOffset>
            <bitWidth>1</bitWidth>
          </field>
          <field>
            <name>FB16</name>
            <bitOffset>16</bitOffset>
            <bitWidth>1</bitWidth>
          </field>
          <field>
            <name>FB17</name>
            <bitOffset>17</bitOffset>
            <bitWidth>1</bitWidth>
          </field>
          <field>
            <name>FB18</name>
            <bitOffset>18</bitOffset>
            <bitWidth>1</bitWidth>
          </field>
          <field>
            <name>FB19</name>
            <bitOffset>19</bitOffset>
            <bitWidth>1</bitWidth>
          </field>
          <field>
            <name>FB20</name>
            <bitOffset>20</bitOffset>
            <bitWidth>1</bitWidth>
          </field>
          <field>
            <name>FB21</name>
            <bitOffset>21</bitOffset>
            <bitWidth>1</bitWidth>
          </field>
          <field>
            <name>FB22</name>
            <bitOffset>22</bitOffset>
            <bitWidth>1</bitWidth>
          </field>
          <field>
            <name>FB23</name>
            <bitOffset>23</bitOffset>
            <bitWidth>1</bitWidth>
          </field>
          <field>
            <name>FB24</name>
            <bitOffset>24</bitOffset>
            <bitWidth>1</bitWidth>
          </field>
          <field>
            <name>FB25</name>
            <bitOffset>25</bitOffset>
            <bitWidth>1</bitWidth>
          </field>
          <field>
            <name>FB26</name>
            <bitOffset>26</bitOffset>
            <bitWidth>1</bitWidth>
          </field>
          <field>
            <name>FB27</name>
            <bitOffset>27</bitOffset>
            <bitWidth>1</bitWidth>
          </field>
          <field>
            <name>FB28</name>
            <bitOffset>28</bitOffset>
            <bitWidth>1</bitWidth>
          </field>
          <field>
            <name>FB29</name>
            <bitOffset>29</bitOffset>
            <bitWidth>1</bitWidth>
          </field>
          <field>
            <name>FB30</name>
            <bitOffset>30</bitOffset>
            <bitWidth>1</bitWidth>
          </field>
          <field>
            <name>FB31</name>
            <bitOffset>31</bitOffset>
            <bitWidth>1</bitWidth>
          </field>
        </fields>
      </register>
      <register>
        <name>sFilterRegister.8.FR1</name>
        <addressOffset>0x280</addressOffset>
        <size>0x20</size>
        <fields>
          <field>
            <name>FB0</name>
            <bitOffset>0</bitOffset>
            <bitWidth>1</bitWidth>
          </field>
          <field>
            <name>FB1</name>
            <bitOffset>1</bitOffset>
            <bitWidth>1</bitWidth>
          </field>
          <field>
            <name>FB2</name>
            <bitOffset>2</bitOffset>
            <bitWidth>1</bitWidth>
          </field>
          <field>
            <name>FB3</name>
            <bitOffset>3</bitOffset>
            <bitWidth>1</bitWidth>
          </field>
          <field>
            <name>FB4</name>
            <bitOffset>4</bitOffset>
            <bitWidth>1</bitWidth>
          </field>
          <field>
            <name>FB5</name>
            <bitOffset>5</bitOffset>
            <bitWidth>1</bitWidth>
          </field>
          <field>
            <name>FB6</name>
            <bitOffset>6</bitOffset>
            <bitWidth>1</bitWidth>
          </field>
          <field>
            <name>FB7</name>
            <bitOffset>7</bitOffset>
            <bitWidth>1</bitWidth>
          </field>
          <field>
            <name>FB8</name>
            <bitOffset>8</bitOffset>
            <bitWidth>1</bitWidth>
          </field>
          <field>
            <name>FB9</name>
            <bitOffset>9</bitOffset>
            <bitWidth>1</bitWidth>
          </field>
          <field>
            <name>FB10</name>
            <bitOffset>10</bitOffset>
            <bitWidth>1</bitWidth>
          </field>
          <field>
            <name>FB11</name>
            <bitOffset>11</bitOffset>
            <bitWidth>1</bitWidth>
          </field>
          <field>
            <name>FB12</name>
            <bitOffset>12</bitOffset>
            <bitWidth>1</bitWidth>
          </field>
          <field>
            <name>FB13</name>
            <bitOffset>13</bitOffset>
            <bitWidth>1</bitWidth>
          </field>
          <field>
            <name>FB14</name>
            <bitOffset>14</bitOffset>
            <bitWidth>1</bitWidth>
          </field>
          <field>
            <name>FB15</name>
            <bitOffset>15</bitOffset>
            <bitWidth>1</bitWidth>
          </field>
          <field>
            <name>FB16</name>
            <bitOffset>16</bitOffset>
            <bitWidth>1</bitWidth>
          </field>
          <field>
            <name>FB17</name>
            <bitOffset>17</bitOffset>
            <bitWidth>1</bitWidth>
          </field>
          <field>
            <name>FB18</name>
            <bitOffset>18</bitOffset>
            <bitWidth>1</bitWidth>
          </field>
          <field>
            <name>FB19</name>
            <bitOffset>19</bitOffset>
            <bitWidth>1</bitWidth>
          </field>
          <field>
            <name>FB20</name>
            <bitOffset>20</bitOffset>
            <bitWidth>1</bitWidth>
          </field>
          <field>
            <name>FB21</name>
            <bitOffset>21</bitOffset>
            <bitWidth>1</bitWidth>
          </field>
          <field>
            <name>FB22</name>
            <bitOffset>22</bitOffset>
            <bitWidth>1</bitWidth>
          </field>
          <field>
            <name>FB23</name>
            <bitOffset>23</bitOffset>
            <bitWidth>1</bitWidth>
          </field>
          <field>
            <name>FB24</name>
            <bitOffset>24</bitOffset>
            <bitWidth>1</bitWidth>
          </field>
          <field>
            <name>FB25</name>
            <bitOffset>25</bitOffset>
            <bitWidth>1</bitWidth>
          </field>
          <field>
            <name>FB26</name>
            <bitOffset>26</bitOffset>
            <bitWidth>1</bitWidth>
          </field>
          <field>
            <name>FB27</name>
            <bitOffset>27</bitOffset>
            <bitWidth>1</bitWidth>
          </field>
          <field>
            <name>FB28</name>
            <bitOffset>28</bitOffset>
            <bitWidth>1</bitWidth>
          </field>
          <field>
            <name>FB29</name>
            <bitOffset>29</bitOffset>
            <bitWidth>1</bitWidth>
          </field>
          <field>
            <name>FB30</name>
            <bitOffset>30</bitOffset>
            <bitWidth>1</bitWidth>
          </field>
          <field>
            <name>FB31</name>
            <bitOffset>31</bitOffset>
            <bitWidth>1</bitWidth>
          </field>
        </fields>
      </register>
      <register>
        <name>sFilterRegister.8.FR2</name>
        <addressOffset>0x284</addressOffset>
        <size>0x20</size>
        <fields>
          <field>
            <name>FB0</name>
            <bitOffset>0</bitOffset>
            <bitWidth>1</bitWidth>
          </field>
          <field>
            <name>FB1</name>
            <bitOffset>1</bitOffset>
            <bitWidth>1</bitWidth>
          </field>
          <field>
            <name>FB2</name>
            <bitOffset>2</bitOffset>
            <bitWidth>1</bitWidth>
          </field>
          <field>
            <name>FB3</name>
            <bitOffset>3</bitOffset>
            <bitWidth>1</bitWidth>
          </field>
          <field>
            <name>FB4</name>
            <bitOffset>4</bitOffset>
            <bitWidth>1</bitWidth>
          </field>
          <field>
            <name>FB5</name>
            <bitOffset>5</bitOffset>
            <bitWidth>1</bitWidth>
          </field>
          <field>
            <name>FB6</name>
            <bitOffset>6</bitOffset>
            <bitWidth>1</bitWidth>
          </field>
          <field>
            <name>FB7</name>
            <bitOffset>7</bitOffset>
            <bitWidth>1</bitWidth>
          </field>
          <field>
            <name>FB8</name>
            <bitOffset>8</bitOffset>
            <bitWidth>1</bitWidth>
          </field>
          <field>
            <name>FB9</name>
            <bitOffset>9</bitOffset>
            <bitWidth>1</bitWidth>
          </field>
          <field>
            <name>FB10</name>
            <bitOffset>10</bitOffset>
            <bitWidth>1</bitWidth>
          </field>
          <field>
            <name>FB11</name>
            <bitOffset>11</bitOffset>
            <bitWidth>1</bitWidth>
          </field>
          <field>
            <name>FB12</name>
            <bitOffset>12</bitOffset>
            <bitWidth>1</bitWidth>
          </field>
          <field>
            <name>FB13</name>
            <bitOffset>13</bitOffset>
            <bitWidth>1</bitWidth>
          </field>
          <field>
            <name>FB14</name>
            <bitOffset>14</bitOffset>
            <bitWidth>1</bitWidth>
          </field>
          <field>
            <name>FB15</name>
            <bitOffset>15</bitOffset>
            <bitWidth>1</bitWidth>
          </field>
          <field>
            <name>FB16</name>
            <bitOffset>16</bitOffset>
            <bitWidth>1</bitWidth>
          </field>
          <field>
            <name>FB17</name>
            <bitOffset>17</bitOffset>
            <bitWidth>1</bitWidth>
          </field>
          <field>
            <name>FB18</name>
            <bitOffset>18</bitOffset>
            <bitWidth>1</bitWidth>
          </field>
          <field>
            <name>FB19</name>
            <bitOffset>19</bitOffset>
            <bitWidth>1</bitWidth>
          </field>
          <field>
            <name>FB20</name>
            <bitOffset>20</bitOffset>
            <bitWidth>1</bitWidth>
          </field>
          <field>
            <name>FB21</name>
            <bitOffset>21</bitOffset>
            <bitWidth>1</bitWidth>
          </field>
          <field>
            <name>FB22</name>
            <bitOffset>22</bitOffset>
            <bitWidth>1</bitWidth>
          </field>
          <field>
            <name>FB23</name>
            <bitOffset>23</bitOffset>
            <bitWidth>1</bitWidth>
          </field>
          <field>
            <name>FB24</name>
            <bitOffset>24</bitOffset>
            <bitWidth>1</bitWidth>
          </field>
          <field>
            <name>FB25</name>
            <bitOffset>25</bitOffset>
            <bitWidth>1</bitWidth>
          </field>
          <field>
            <name>FB26</name>
            <bitOffset>26</bitOffset>
            <bitWidth>1</bitWidth>
          </field>
          <field>
            <name>FB27</name>
            <bitOffset>27</bitOffset>
            <bitWidth>1</bitWidth>
          </field>
          <field>
            <name>FB28</name>
            <bitOffset>28</bitOffset>
            <bitWidth>1</bitWidth>
          </field>
          <field>
            <name>FB29</name>
            <bitOffset>29</bitOffset>
            <bitWidth>1</bitWidth>
          </field>
          <field>
            <name>FB30</name>
            <bitOffset>30</bitOffset>
            <bitWidth>1</bitWidth>
          </field>
          <field>
            <name>FB31</name>
            <bitOffset>31</bitOffset>
            <bitWidth>1</bitWidth>
          </field>
        </fields>
      </register>
      <register>
        <name>sFilterRegister.9.FR1</name>
        <addressOffset>0x288</addressOffset>
        <size>0x20</size>
        <fields>
          <field>
            <name>FB0</name>
            <bitOffset>0</bitOffset>
            <bitWidth>1</bitWidth>
          </field>
          <field>
            <name>FB1</name>
            <bitOffset>1</bitOffset>
            <bitWidth>1</bitWidth>
          </field>
          <field>
            <name>FB2</name>
            <bitOffset>2</bitOffset>
            <bitWidth>1</bitWidth>
          </field>
          <field>
            <name>FB3</name>
            <bitOffset>3</bitOffset>
            <bitWidth>1</bitWidth>
          </field>
          <field>
            <name>FB4</name>
            <bitOffset>4</bitOffset>
            <bitWidth>1</bitWidth>
          </field>
          <field>
            <name>FB5</name>
            <bitOffset>5</bitOffset>
            <bitWidth>1</bitWidth>
          </field>
          <field>
            <name>FB6</name>
            <bitOffset>6</bitOffset>
            <bitWidth>1</bitWidth>
          </field>
          <field>
            <name>FB7</name>
            <bitOffset>7</bitOffset>
            <bitWidth>1</bitWidth>
          </field>
          <field>
            <name>FB8</name>
            <bitOffset>8</bitOffset>
            <bitWidth>1</bitWidth>
          </field>
          <field>
            <name>FB9</name>
            <bitOffset>9</bitOffset>
            <bitWidth>1</bitWidth>
          </field>
          <field>
            <name>FB10</name>
            <bitOffset>10</bitOffset>
            <bitWidth>1</bitWidth>
          </field>
          <field>
            <name>FB11</name>
            <bitOffset>11</bitOffset>
            <bitWidth>1</bitWidth>
          </field>
          <field>
            <name>FB12</name>
            <bitOffset>12</bitOffset>
            <bitWidth>1</bitWidth>
          </field>
          <field>
            <name>FB13</name>
            <bitOffset>13</bitOffset>
            <bitWidth>1</bitWidth>
          </field>
          <field>
            <name>FB14</name>
            <bitOffset>14</bitOffset>
            <bitWidth>1</bitWidth>
          </field>
          <field>
            <name>FB15</name>
            <bitOffset>15</bitOffset>
            <bitWidth>1</bitWidth>
          </field>
          <field>
            <name>FB16</name>
            <bitOffset>16</bitOffset>
            <bitWidth>1</bitWidth>
          </field>
          <field>
            <name>FB17</name>
            <bitOffset>17</bitOffset>
            <bitWidth>1</bitWidth>
          </field>
          <field>
            <name>FB18</name>
            <bitOffset>18</bitOffset>
            <bitWidth>1</bitWidth>
          </field>
          <field>
            <name>FB19</name>
            <bitOffset>19</bitOffset>
            <bitWidth>1</bitWidth>
          </field>
          <field>
            <name>FB20</name>
            <bitOffset>20</bitOffset>
            <bitWidth>1</bitWidth>
          </field>
          <field>
            <name>FB21</name>
            <bitOffset>21</bitOffset>
            <bitWidth>1</bitWidth>
          </field>
          <field>
            <name>FB22</name>
            <bitOffset>22</bitOffset>
            <bitWidth>1</bitWidth>
          </field>
          <field>
            <name>FB23</name>
            <bitOffset>23</bitOffset>
            <bitWidth>1</bitWidth>
          </field>
          <field>
            <name>FB24</name>
            <bitOffset>24</bitOffset>
            <bitWidth>1</bitWidth>
          </field>
          <field>
            <name>FB25</name>
            <bitOffset>25</bitOffset>
            <bitWidth>1</bitWidth>
          </field>
          <field>
            <name>FB26</name>
            <bitOffset>26</bitOffset>
            <bitWidth>1</bitWidth>
          </field>
          <field>
            <name>FB27</name>
            <bitOffset>27</bitOffset>
            <bitWidth>1</bitWidth>
          </field>
          <field>
            <name>FB28</name>
            <bitOffset>28</bitOffset>
            <bitWidth>1</bitWidth>
          </field>
          <field>
            <name>FB29</name>
            <bitOffset>29</bitOffset>
            <bitWidth>1</bitWidth>
          </field>
          <field>
            <name>FB30</name>
            <bitOffset>30</bitOffset>
            <bitWidth>1</bitWidth>
          </field>
          <field>
            <name>FB31</name>
            <bitOffset>31</bitOffset>
            <bitWidth>1</bitWidth>
          </field>
        </fields>
      </register>
      <register>
        <name>sFilterRegister.9.FR2</name>
        <addressOffset>0x28c</addressOffset>
        <size>0x20</size>
        <fields>
          <field>
            <name>FB0</name>
            <bitOffset>0</bitOffset>
            <bitWidth>1</bitWidth>
          </field>
          <field>
            <name>FB1</name>
            <bitOffset>1</bitOffset>
            <bitWidth>1</bitWidth>
          </field>
          <field>
            <name>FB2</name>
            <bitOffset>2</bitOffset>
            <bitWidth>1</bitWidth>
          </field>
          <field>
            <name>FB3</name>
            <bitOffset>3</bitOffset>
            <bitWidth>1</bitWidth>
          </field>
          <field>
            <name>FB4</name>
            <bitOffset>4</bitOffset>
            <bitWidth>1</bitWidth>
          </field>
          <field>
            <name>FB5</name>
            <bitOffset>5</bitOffset>
            <bitWidth>1</bitWidth>
          </field>
          <field>
            <name>FB6</name>
            <bitOffset>6</bitOffset>
            <bitWidth>1</bitWidth>
          </field>
          <field>
            <name>FB7</name>
            <bitOffset>7</bitOffset>
            <bitWidth>1</bitWidth>
          </field>
          <field>
            <name>FB8</name>
            <bitOffset>8</bitOffset>
            <bitWidth>1</bitWidth>
          </field>
          <field>
            <name>FB9</name>
            <bitOffset>9</bitOffset>
            <bitWidth>1</bitWidth>
          </field>
          <field>
            <name>FB10</name>
            <bitOffset>10</bitOffset>
            <bitWidth>1</bitWidth>
          </field>
          <field>
            <name>FB11</name>
            <bitOffset>11</bitOffset>
            <bitWidth>1</bitWidth>
          </field>
          <field>
            <name>FB12</name>
            <bitOffset>12</bitOffset>
            <bitWidth>1</bitWidth>
          </field>
          <field>
            <name>FB13</name>
            <bitOffset>13</bitOffset>
            <bitWidth>1</bitWidth>
          </field>
          <field>
            <name>FB14</name>
            <bitOffset>14</bitOffset>
            <bitWidth>1</bitWidth>
          </field>
          <field>
            <name>FB15</name>
            <bitOffset>15</bitOffset>
            <bitWidth>1</bitWidth>
          </field>
          <field>
            <name>FB16</name>
            <bitOffset>16</bitOffset>
            <bitWidth>1</bitWidth>
          </field>
          <field>
            <name>FB17</name>
            <bitOffset>17</bitOffset>
            <bitWidth>1</bitWidth>
          </field>
          <field>
            <name>FB18</name>
            <bitOffset>18</bitOffset>
            <bitWidth>1</bitWidth>
          </field>
          <field>
            <name>FB19</name>
            <bitOffset>19</bitOffset>
            <bitWidth>1</bitWidth>
          </field>
          <field>
            <name>FB20</name>
            <bitOffset>20</bitOffset>
            <bitWidth>1</bitWidth>
          </field>
          <field>
            <name>FB21</name>
            <bitOffset>21</bitOffset>
            <bitWidth>1</bitWidth>
          </field>
          <field>
            <name>FB22</name>
            <bitOffset>22</bitOffset>
            <bitWidth>1</bitWidth>
          </field>
          <field>
            <name>FB23</name>
            <bitOffset>23</bitOffset>
            <bitWidth>1</bitWidth>
          </field>
          <field>
            <name>FB24</name>
            <bitOffset>24</bitOffset>
            <bitWidth>1</bitWidth>
          </field>
          <field>
            <name>FB25</name>
            <bitOffset>25</bitOffset>
            <bitWidth>1</bitWidth>
          </field>
          <field>
            <name>FB26</name>
            <bitOffset>26</bitOffset>
            <bitWidth>1</bitWidth>
          </field>
          <field>
            <name>FB27</name>
            <bitOffset>27</bitOffset>
            <bitWidth>1</bitWidth>
          </field>
          <field>
            <name>FB28</name>
            <bitOffset>28</bitOffset>
            <bitWidth>1</bitWidth>
          </field>
          <field>
            <name>FB29</name>
            <bitOffset>29</bitOffset>
            <bitWidth>1</bitWidth>
          </field>
          <field>
            <name>FB30</name>
            <bitOffset>30</bitOffset>
            <bitWidth>1</bitWidth>
          </field>
          <field>
            <name>FB31</name>
            <bitOffset>31</bitOffset>
            <bitWidth>1</bitWidth>
          </field>
        </fields>
      </register>
      <register>
        <name>sFilterRegister.10.FR1</name>
        <addressOffset>0x290</addressOffset>
        <size>0x20</size>
        <fields>
          <field>
            <name>FB0</name>
            <bitOffset>0</bitOffset>
            <bitWidth>1</bitWidth>
          </field>
          <field>
            <name>FB1</name>
            <bitOffset>1</bitOffset>
            <bitWidth>1</bitWidth>
          </field>
          <field>
            <name>FB2</name>
            <bitOffset>2</bitOffset>
            <bitWidth>1</bitWidth>
          </field>
          <field>
            <name>FB3</name>
            <bitOffset>3</bitOffset>
            <bitWidth>1</bitWidth>
          </field>
          <field>
            <name>FB4</name>
            <bitOffset>4</bitOffset>
            <bitWidth>1</bitWidth>
          </field>
          <field>
            <name>FB5</name>
            <bitOffset>5</bitOffset>
            <bitWidth>1</bitWidth>
          </field>
          <field>
            <name>FB6</name>
            <bitOffset>6</bitOffset>
            <bitWidth>1</bitWidth>
          </field>
          <field>
            <name>FB7</name>
            <bitOffset>7</bitOffset>
            <bitWidth>1</bitWidth>
          </field>
          <field>
            <name>FB8</name>
            <bitOffset>8</bitOffset>
            <bitWidth>1</bitWidth>
          </field>
          <field>
            <name>FB9</name>
            <bitOffset>9</bitOffset>
            <bitWidth>1</bitWidth>
          </field>
          <field>
            <name>FB10</name>
            <bitOffset>10</bitOffset>
            <bitWidth>1</bitWidth>
          </field>
          <field>
            <name>FB11</name>
            <bitOffset>11</bitOffset>
            <bitWidth>1</bitWidth>
          </field>
          <field>
            <name>FB12</name>
            <bitOffset>12</bitOffset>
            <bitWidth>1</bitWidth>
          </field>
          <field>
            <name>FB13</name>
            <bitOffset>13</bitOffset>
            <bitWidth>1</bitWidth>
          </field>
          <field>
            <name>FB14</name>
            <bitOffset>14</bitOffset>
            <bitWidth>1</bitWidth>
          </field>
          <field>
            <name>FB15</name>
            <bitOffset>15</bitOffset>
            <bitWidth>1</bitWidth>
          </field>
          <field>
            <name>FB16</name>
            <bitOffset>16</bitOffset>
            <bitWidth>1</bitWidth>
          </field>
          <field>
            <name>FB17</name>
            <bitOffset>17</bitOffset>
            <bitWidth>1</bitWidth>
          </field>
          <field>
            <name>FB18</name>
            <bitOffset>18</bitOffset>
            <bitWidth>1</bitWidth>
          </field>
          <field>
            <name>FB19</name>
            <bitOffset>19</bitOffset>
            <bitWidth>1</bitWidth>
          </field>
          <field>
            <name>FB20</name>
            <bitOffset>20</bitOffset>
            <bitWidth>1</bitWidth>
          </field>
          <field>
            <name>FB21</name>
            <bitOffset>21</bitOffset>
            <bitWidth>1</bitWidth>
          </field>
          <field>
            <name>FB22</name>
            <bitOffset>22</bitOffset>
            <bitWidth>1</bitWidth>
          </field>
          <field>
            <name>FB23</name>
            <bitOffset>23</bitOffset>
            <bitWidth>1</bitWidth>
          </field>
          <field>
            <name>FB24</name>
            <bitOffset>24</bitOffset>
            <bitWidth>1</bitWidth>
          </field>
          <field>
            <name>FB25</name>
            <bitOffset>25</bitOffset>
            <bitWidth>1</bitWidth>
          </field>
          <field>
            <name>FB26</name>
            <bitOffset>26</bitOffset>
            <bitWidth>1</bitWidth>
          </field>
          <field>
            <name>FB27</name>
            <bitOffset>27</bitOffset>
            <bitWidth>1</bitWidth>
          </field>
          <field>
            <name>FB28</name>
            <bitOffset>28</bitOffset>
            <bitWidth>1</bitWidth>
          </field>
          <field>
            <name>FB29</name>
            <bitOffset>29</bitOffset>
            <bitWidth>1</bitWidth>
          </field>
          <field>
            <name>FB30</name>
            <bitOffset>30</bitOffset>
            <bitWidth>1</bitWidth>
          </field>
          <field>
            <name>FB31</name>
            <bitOffset>31</bitOffset>
            <bitWidth>1</bitWidth>
          </field>
        </fields>
      </register>
      <register>
        <name>sFilterRegister.10.FR2</name>
        <addressOffset>0x294</addressOffset>
        <size>0x20</size>
        <fields>
          <field>
            <name>FB0</name>
            <bitOffset>0</bitOffset>
            <bitWidth>1</bitWidth>
          </field>
          <field>
            <name>FB1</name>
            <bitOffset>1</bitOffset>
            <bitWidth>1</bitWidth>
          </field>
          <field>
            <name>FB2</name>
            <bitOffset>2</bitOffset>
            <bitWidth>1</bitWidth>
          </field>
          <field>
            <name>FB3</name>
            <bitOffset>3</bitOffset>
            <bitWidth>1</bitWidth>
          </field>
          <field>
            <name>FB4</name>
            <bitOffset>4</bitOffset>
            <bitWidth>1</bitWidth>
          </field>
          <field>
            <name>FB5</name>
            <bitOffset>5</bitOffset>
            <bitWidth>1</bitWidth>
          </field>
          <field>
            <name>FB6</name>
            <bitOffset>6</bitOffset>
            <bitWidth>1</bitWidth>
          </field>
          <field>
            <name>FB7</name>
            <bitOffset>7</bitOffset>
            <bitWidth>1</bitWidth>
          </field>
          <field>
            <name>FB8</name>
            <bitOffset>8</bitOffset>
            <bitWidth>1</bitWidth>
          </field>
          <field>
            <name>FB9</name>
            <bitOffset>9</bitOffset>
            <bitWidth>1</bitWidth>
          </field>
          <field>
            <name>FB10</name>
            <bitOffset>10</bitOffset>
            <bitWidth>1</bitWidth>
          </field>
          <field>
            <name>FB11</name>
            <bitOffset>11</bitOffset>
            <bitWidth>1</bitWidth>
          </field>
          <field>
            <name>FB12</name>
            <bitOffset>12</bitOffset>
            <bitWidth>1</bitWidth>
          </field>
          <field>
            <name>FB13</name>
            <bitOffset>13</bitOffset>
            <bitWidth>1</bitWidth>
          </field>
          <field>
            <name>FB14</name>
            <bitOffset>14</bitOffset>
            <bitWidth>1</bitWidth>
          </field>
          <field>
            <name>FB15</name>
            <bitOffset>15</bitOffset>
            <bitWidth>1</bitWidth>
          </field>
          <field>
            <name>FB16</name>
            <bitOffset>16</bitOffset>
            <bitWidth>1</bitWidth>
          </field>
          <field>
            <name>FB17</name>
            <bitOffset>17</bitOffset>
            <bitWidth>1</bitWidth>
          </field>
          <field>
            <name>FB18</name>
            <bitOffset>18</bitOffset>
            <bitWidth>1</bitWidth>
          </field>
          <field>
            <name>FB19</name>
            <bitOffset>19</bitOffset>
            <bitWidth>1</bitWidth>
          </field>
          <field>
            <name>FB20</name>
            <bitOffset>20</bitOffset>
            <bitWidth>1</bitWidth>
          </field>
          <field>
            <name>FB21</name>
            <bitOffset>21</bitOffset>
            <bitWidth>1</bitWidth>
          </field>
          <field>
            <name>FB22</name>
            <bitOffset>22</bitOffset>
            <bitWidth>1</bitWidth>
          </field>
          <field>
            <name>FB23</name>
            <bitOffset>23</bitOffset>
            <bitWidth>1</bitWidth>
          </field>
          <field>
            <name>FB24</name>
            <bitOffset>24</bitOffset>
            <bitWidth>1</bitWidth>
          </field>
          <field>
            <name>FB25</name>
            <bitOffset>25</bitOffset>
            <bitWidth>1</bitWidth>
          </field>
          <field>
            <name>FB26</name>
            <bitOffset>26</bitOffset>
            <bitWidth>1</bitWidth>
          </field>
          <field>
            <name>FB27</name>
            <bitOffset>27</bitOffset>
            <bitWidth>1</bitWidth>
          </field>
          <field>
            <name>FB28</name>
            <bitOffset>28</bitOffset>
            <bitWidth>1</bitWidth>
          </field>
          <field>
            <name>FB29</name>
            <bitOffset>29</bitOffset>
            <bitWidth>1</bitWidth>
          </field>
          <field>
            <name>FB30</name>
            <bitOffset>30</bitOffset>
            <bitWidth>1</bitWidth>
          </field>
          <field>
            <name>FB31</name>
            <bitOffset>31</bitOffset>
            <bitWidth>1</bitWidth>
          </field>
        </fields>
      </register>
      <register>
        <name>sFilterRegister.11.FR1</name>
        <addressOffset>0x298</addressOffset>
        <size>0x20</size>
        <fields>
          <field>
            <name>FB0</name>
            <bitOffset>0</bitOffset>
            <bitWidth>1</bitWidth>
          </field>
          <field>
            <name>FB1</name>
            <bitOffset>1</bitOffset>
            <bitWidth>1</bitWidth>
          </field>
          <field>
            <name>FB2</name>
            <bitOffset>2</bitOffset>
            <bitWidth>1</bitWidth>
          </field>
          <field>
            <name>FB3</name>
            <bitOffset>3</bitOffset>
            <bitWidth>1</bitWidth>
          </field>
          <field>
            <name>FB4</name>
            <bitOffset>4</bitOffset>
            <bitWidth>1</bitWidth>
          </field>
          <field>
            <name>FB5</name>
            <bitOffset>5</bitOffset>
            <bitWidth>1</bitWidth>
          </field>
          <field>
            <name>FB6</name>
            <bitOffset>6</bitOffset>
            <bitWidth>1</bitWidth>
          </field>
          <field>
            <name>FB7</name>
            <bitOffset>7</bitOffset>
            <bitWidth>1</bitWidth>
          </field>
          <field>
            <name>FB8</name>
            <bitOffset>8</bitOffset>
            <bitWidth>1</bitWidth>
          </field>
          <field>
            <name>FB9</name>
            <bitOffset>9</bitOffset>
            <bitWidth>1</bitWidth>
          </field>
          <field>
            <name>FB10</name>
            <bitOffset>10</bitOffset>
            <bitWidth>1</bitWidth>
          </field>
          <field>
            <name>FB11</name>
            <bitOffset>11</bitOffset>
            <bitWidth>1</bitWidth>
          </field>
          <field>
            <name>FB12</name>
            <bitOffset>12</bitOffset>
            <bitWidth>1</bitWidth>
          </field>
          <field>
            <name>FB13</name>
            <bitOffset>13</bitOffset>
            <bitWidth>1</bitWidth>
          </field>
          <field>
            <name>FB14</name>
            <bitOffset>14</bitOffset>
            <bitWidth>1</bitWidth>
          </field>
          <field>
            <name>FB15</name>
            <bitOffset>15</bitOffset>
            <bitWidth>1</bitWidth>
          </field>
          <field>
            <name>FB16</name>
            <bitOffset>16</bitOffset>
            <bitWidth>1</bitWidth>
          </field>
          <field>
            <name>FB17</name>
            <bitOffset>17</bitOffset>
            <bitWidth>1</bitWidth>
          </field>
          <field>
            <name>FB18</name>
            <bitOffset>18</bitOffset>
            <bitWidth>1</bitWidth>
          </field>
          <field>
            <name>FB19</name>
            <bitOffset>19</bitOffset>
            <bitWidth>1</bitWidth>
          </field>
          <field>
            <name>FB20</name>
            <bitOffset>20</bitOffset>
            <bitWidth>1</bitWidth>
          </field>
          <field>
            <name>FB21</name>
            <bitOffset>21</bitOffset>
            <bitWidth>1</bitWidth>
          </field>
          <field>
            <name>FB22</name>
            <bitOffset>22</bitOffset>
            <bitWidth>1</bitWidth>
          </field>
          <field>
            <name>FB23</name>
            <bitOffset>23</bitOffset>
            <bitWidth>1</bitWidth>
          </field>
          <field>
            <name>FB24</name>
            <bitOffset>24</bitOffset>
            <bitWidth>1</bitWidth>
          </field>
          <field>
            <name>FB25</name>
            <bitOffset>25</bitOffset>
            <bitWidth>1</bitWidth>
          </field>
          <field>
            <name>FB26</name>
            <bitOffset>26</bitOffset>
            <bitWidth>1</bitWidth>
          </field>
          <field>
            <name>FB27</name>
            <bitOffset>27</bitOffset>
            <bitWidth>1</bitWidth>
          </field>
          <field>
            <name>FB28</name>
            <bitOffset>28</bitOffset>
            <bitWidth>1</bitWidth>
          </field>
          <field>
            <name>FB29</name>
            <bitOffset>29</bitOffset>
            <bitWidth>1</bitWidth>
          </field>
          <field>
            <name>FB30</name>
            <bitOffset>30</bitOffset>
            <bitWidth>1</bitWidth>
          </field>
          <field>
            <name>FB31</name>
            <bitOffset>31</bitOffset>
            <bitWidth>1</bitWidth>
          </field>
        </fields>
      </register>
      <register>
        <name>sFilterRegister.11.FR2</name>
        <addressOffset>0x29c</addressOffset>
        <size>0x20</size>
        <fields>
          <field>
            <name>FB0</name>
            <bitOffset>0</bitOffset>
            <bitWidth>1</bitWidth>
          </field>
          <field>
            <name>FB1</name>
            <bitOffset>1</bitOffset>
            <bitWidth>1</bitWidth>
          </field>
          <field>
            <name>FB2</name>
            <bitOffset>2</bitOffset>
            <bitWidth>1</bitWidth>
          </field>
          <field>
            <name>FB3</name>
            <bitOffset>3</bitOffset>
            <bitWidth>1</bitWidth>
          </field>
          <field>
            <name>FB4</name>
            <bitOffset>4</bitOffset>
            <bitWidth>1</bitWidth>
          </field>
          <field>
            <name>FB5</name>
            <bitOffset>5</bitOffset>
            <bitWidth>1</bitWidth>
          </field>
          <field>
            <name>FB6</name>
            <bitOffset>6</bitOffset>
            <bitWidth>1</bitWidth>
          </field>
          <field>
            <name>FB7</name>
            <bitOffset>7</bitOffset>
            <bitWidth>1</bitWidth>
          </field>
          <field>
            <name>FB8</name>
            <bitOffset>8</bitOffset>
            <bitWidth>1</bitWidth>
          </field>
          <field>
            <name>FB9</name>
            <bitOffset>9</bitOffset>
            <bitWidth>1</bitWidth>
          </field>
          <field>
            <name>FB10</name>
            <bitOffset>10</bitOffset>
            <bitWidth>1</bitWidth>
          </field>
          <field>
            <name>FB11</name>
            <bitOffset>11</bitOffset>
            <bitWidth>1</bitWidth>
          </field>
          <field>
            <name>FB12</name>
            <bitOffset>12</bitOffset>
            <bitWidth>1</bitWidth>
          </field>
          <field>
            <name>FB13</name>
            <bitOffset>13</bitOffset>
            <bitWidth>1</bitWidth>
          </field>
          <field>
            <name>FB14</name>
            <bitOffset>14</bitOffset>
            <bitWidth>1</bitWidth>
          </field>
          <field>
            <name>FB15</name>
            <bitOffset>15</bitOffset>
            <bitWidth>1</bitWidth>
          </field>
          <field>
            <name>FB16</name>
            <bitOffset>16</bitOffset>
            <bitWidth>1</bitWidth>
          </field>
          <field>
            <name>FB17</name>
            <bitOffset>17</bitOffset>
            <bitWidth>1</bitWidth>
          </field>
          <field>
            <name>FB18</name>
            <bitOffset>18</bitOffset>
            <bitWidth>1</bitWidth>
          </field>
          <field>
            <name>FB19</name>
            <bitOffset>19</bitOffset>
            <bitWidth>1</bitWidth>
          </field>
          <field>
            <name>FB20</name>
            <bitOffset>20</bitOffset>
            <bitWidth>1</bitWidth>
          </field>
          <field>
            <name>FB21</name>
            <bitOffset>21</bitOffset>
            <bitWidth>1</bitWidth>
          </field>
          <field>
            <name>FB22</name>
            <bitOffset>22</bitOffset>
            <bitWidth>1</bitWidth>
          </field>
          <field>
            <name>FB23</name>
            <bitOffset>23</bitOffset>
            <bitWidth>1</bitWidth>
          </field>
          <field>
            <name>FB24</name>
            <bitOffset>24</bitOffset>
            <bitWidth>1</bitWidth>
          </field>
          <field>
            <name>FB25</name>
            <bitOffset>25</bitOffset>
            <bitWidth>1</bitWidth>
          </field>
          <field>
            <name>FB26</name>
            <bitOffset>26</bitOffset>
            <bitWidth>1</bitWidth>
          </field>
          <field>
            <name>FB27</name>
            <bitOffset>27</bitOffset>
            <bitWidth>1</bitWidth>
          </field>
          <field>
            <name>FB28</name>
            <bitOffset>28</bitOffset>
            <bitWidth>1</bitWidth>
          </field>
          <field>
            <name>FB29</name>
            <bitOffset>29</bitOffset>
            <bitWidth>1</bitWidth>
          </field>
          <field>
            <name>FB30</name>
            <bitOffset>30</bitOffset>
            <bitWidth>1</bitWidth>
          </field>
          <field>
            <name>FB31</name>
            <bitOffset>31</bitOffset>
            <bitWidth>1</bitWidth>
          </field>
        </fields>
      </register>
      <register>
        <name>sFilterRegister.12.FR1</name>
        <addressOffset>0x2a0</addressOffset>
        <size>0x20</size>
        <fields>
          <field>
            <name>FB0</name>
            <bitOffset>0</bitOffset>
            <bitWidth>1</bitWidth>
          </field>
          <field>
            <name>FB1</name>
            <bitOffset>1</bitOffset>
            <bitWidth>1</bitWidth>
          </field>
          <field>
            <name>FB2</name>
            <bitOffset>2</bitOffset>
            <bitWidth>1</bitWidth>
          </field>
          <field>
            <name>FB3</name>
            <bitOffset>3</bitOffset>
            <bitWidth>1</bitWidth>
          </field>
          <field>
            <name>FB4</name>
            <bitOffset>4</bitOffset>
            <bitWidth>1</bitWidth>
          </field>
          <field>
            <name>FB5</name>
            <bitOffset>5</bitOffset>
            <bitWidth>1</bitWidth>
          </field>
          <field>
            <name>FB6</name>
            <bitOffset>6</bitOffset>
            <bitWidth>1</bitWidth>
          </field>
          <field>
            <name>FB7</name>
            <bitOffset>7</bitOffset>
            <bitWidth>1</bitWidth>
          </field>
          <field>
            <name>FB8</name>
            <bitOffset>8</bitOffset>
            <bitWidth>1</bitWidth>
          </field>
          <field>
            <name>FB9</name>
            <bitOffset>9</bitOffset>
            <bitWidth>1</bitWidth>
          </field>
          <field>
            <name>FB10</name>
            <bitOffset>10</bitOffset>
            <bitWidth>1</bitWidth>
          </field>
          <field>
            <name>FB11</name>
            <bitOffset>11</bitOffset>
            <bitWidth>1</bitWidth>
          </field>
          <field>
            <name>FB12</name>
            <bitOffset>12</bitOffset>
            <bitWidth>1</bitWidth>
          </field>
          <field>
            <name>FB13</name>
            <bitOffset>13</bitOffset>
            <bitWidth>1</bitWidth>
          </field>
          <field>
            <name>FB14</name>
            <bitOffset>14</bitOffset>
            <bitWidth>1</bitWidth>
          </field>
          <field>
            <name>FB15</name>
            <bitOffset>15</bitOffset>
            <bitWidth>1</bitWidth>
          </field>
          <field>
            <name>FB16</name>
            <bitOffset>16</bitOffset>
            <bitWidth>1</bitWidth>
          </field>
          <field>
            <name>FB17</name>
            <bitOffset>17</bitOffset>
            <bitWidth>1</bitWidth>
          </field>
          <field>
            <name>FB18</name>
            <bitOffset>18</bitOffset>
            <bitWidth>1</bitWidth>
          </field>
          <field>
            <name>FB19</name>
            <bitOffset>19</bitOffset>
            <bitWidth>1</bitWidth>
          </field>
          <field>
            <name>FB20</name>
            <bitOffset>20</bitOffset>
            <bitWidth>1</bitWidth>
          </field>
          <field>
            <name>FB21</name>
            <bitOffset>21</bitOffset>
            <bitWidth>1</bitWidth>
          </field>
          <field>
            <name>FB22</name>
            <bitOffset>22</bitOffset>
            <bitWidth>1</bitWidth>
          </field>
          <field>
            <name>FB23</name>
            <bitOffset>23</bitOffset>
            <bitWidth>1</bitWidth>
          </field>
          <field>
            <name>FB24</name>
            <bitOffset>24</bitOffset>
            <bitWidth>1</bitWidth>
          </field>
          <field>
            <name>FB25</name>
            <bitOffset>25</bitOffset>
            <bitWidth>1</bitWidth>
          </field>
          <field>
            <name>FB26</name>
            <bitOffset>26</bitOffset>
            <bitWidth>1</bitWidth>
          </field>
          <field>
            <name>FB27</name>
            <bitOffset>27</bitOffset>
            <bitWidth>1</bitWidth>
          </field>
          <field>
            <name>FB28</name>
            <bitOffset>28</bitOffset>
            <bitWidth>1</bitWidth>
          </field>
          <field>
            <name>FB29</name>
            <bitOffset>29</bitOffset>
            <bitWidth>1</bitWidth>
          </field>
          <field>
            <name>FB30</name>
            <bitOffset>30</bitOffset>
            <bitWidth>1</bitWidth>
          </field>
          <field>
            <name>FB31</name>
            <bitOffset>31</bitOffset>
            <bitWidth>1</bitWidth>
          </field>
        </fields>
      </register>
      <register>
        <name>sFilterRegister.12.FR2</name>
        <addressOffset>0x2a4</addressOffset>
        <size>0x20</size>
        <fields>
          <field>
            <name>FB0</name>
            <bitOffset>0</bitOffset>
            <bitWidth>1</bitWidth>
          </field>
          <field>
            <name>FB1</name>
            <bitOffset>1</bitOffset>
            <bitWidth>1</bitWidth>
          </field>
          <field>
            <name>FB2</name>
            <bitOffset>2</bitOffset>
            <bitWidth>1</bitWidth>
          </field>
          <field>
            <name>FB3</name>
            <bitOffset>3</bitOffset>
            <bitWidth>1</bitWidth>
          </field>
          <field>
            <name>FB4</name>
            <bitOffset>4</bitOffset>
            <bitWidth>1</bitWidth>
          </field>
          <field>
            <name>FB5</name>
            <bitOffset>5</bitOffset>
            <bitWidth>1</bitWidth>
          </field>
          <field>
            <name>FB6</name>
            <bitOffset>6</bitOffset>
            <bitWidth>1</bitWidth>
          </field>
          <field>
            <name>FB7</name>
            <bitOffset>7</bitOffset>
            <bitWidth>1</bitWidth>
          </field>
          <field>
            <name>FB8</name>
            <bitOffset>8</bitOffset>
            <bitWidth>1</bitWidth>
          </field>
          <field>
            <name>FB9</name>
            <bitOffset>9</bitOffset>
            <bitWidth>1</bitWidth>
          </field>
          <field>
            <name>FB10</name>
            <bitOffset>10</bitOffset>
            <bitWidth>1</bitWidth>
          </field>
          <field>
            <name>FB11</name>
            <bitOffset>11</bitOffset>
            <bitWidth>1</bitWidth>
          </field>
          <field>
            <name>FB12</name>
            <bitOffset>12</bitOffset>
            <bitWidth>1</bitWidth>
          </field>
          <field>
            <name>FB13</name>
            <bitOffset>13</bitOffset>
            <bitWidth>1</bitWidth>
          </field>
          <field>
            <name>FB14</name>
            <bitOffset>14</bitOffset>
            <bitWidth>1</bitWidth>
          </field>
          <field>
            <name>FB15</name>
            <bitOffset>15</bitOffset>
            <bitWidth>1</bitWidth>
          </field>
          <field>
            <name>FB16</name>
            <bitOffset>16</bitOffset>
            <bitWidth>1</bitWidth>
          </field>
          <field>
            <name>FB17</name>
            <bitOffset>17</bitOffset>
            <bitWidth>1</bitWidth>
          </field>
          <field>
            <name>FB18</name>
            <bitOffset>18</bitOffset>
            <bitWidth>1</bitWidth>
          </field>
          <field>
            <name>FB19</name>
            <bitOffset>19</bitOffset>
            <bitWidth>1</bitWidth>
          </field>
          <field>
            <name>FB20</name>
            <bitOffset>20</bitOffset>
            <bitWidth>1</bitWidth>
          </field>
          <field>
            <name>FB21</name>
            <bitOffset>21</bitOffset>
            <bitWidth>1</bitWidth>
          </field>
          <field>
            <name>FB22</name>
            <bitOffset>22</bitOffset>
            <bitWidth>1</bitWidth>
          </field>
          <field>
            <name>FB23</name>
            <bitOffset>23</bitOffset>
            <bitWidth>1</bitWidth>
          </field>
          <field>
            <name>FB24</name>
            <bitOffset>24</bitOffset>
            <bitWidth>1</bitWidth>
          </field>
          <field>
            <name>FB25</name>
            <bitOffset>25</bitOffset>
            <bitWidth>1</bitWidth>
          </field>
          <field>
            <name>FB26</name>
            <bitOffset>26</bitOffset>
            <bitWidth>1</bitWidth>
          </field>
          <field>
            <name>FB27</name>
            <bitOffset>27</bitOffset>
            <bitWidth>1</bitWidth>
          </field>
          <field>
            <name>FB28</name>
            <bitOffset>28</bitOffset>
            <bitWidth>1</bitWidth>
          </field>
          <field>
            <name>FB29</name>
            <bitOffset>29</bitOffset>
            <bitWidth>1</bitWidth>
          </field>
          <field>
            <name>FB30</name>
            <bitOffset>30</bitOffset>
            <bitWidth>1</bitWidth>
          </field>
          <field>
            <name>FB31</name>
            <bitOffset>31</bitOffset>
            <bitWidth>1</bitWidth>
          </field>
        </fields>
      </register>
      <register>
        <name>sFilterRegister.13.FR1</name>
        <addressOffset>0x2a8</addressOffset>
        <size>0x20</size>
        <fields>
          <field>
            <name>FB0</name>
            <bitOffset>0</bitOffset>
            <bitWidth>1</bitWidth>
          </field>
          <field>
            <name>FB1</name>
            <bitOffset>1</bitOffset>
            <bitWidth>1</bitWidth>
          </field>
          <field>
            <name>FB2</name>
            <bitOffset>2</bitOffset>
            <bitWidth>1</bitWidth>
          </field>
          <field>
            <name>FB3</name>
            <bitOffset>3</bitOffset>
            <bitWidth>1</bitWidth>
          </field>
          <field>
            <name>FB4</name>
            <bitOffset>4</bitOffset>
            <bitWidth>1</bitWidth>
          </field>
          <field>
            <name>FB5</name>
            <bitOffset>5</bitOffset>
            <bitWidth>1</bitWidth>
          </field>
          <field>
            <name>FB6</name>
            <bitOffset>6</bitOffset>
            <bitWidth>1</bitWidth>
          </field>
          <field>
            <name>FB7</name>
            <bitOffset>7</bitOffset>
            <bitWidth>1</bitWidth>
          </field>
          <field>
            <name>FB8</name>
            <bitOffset>8</bitOffset>
            <bitWidth>1</bitWidth>
          </field>
          <field>
            <name>FB9</name>
            <bitOffset>9</bitOffset>
            <bitWidth>1</bitWidth>
          </field>
          <field>
            <name>FB10</name>
            <bitOffset>10</bitOffset>
            <bitWidth>1</bitWidth>
          </field>
          <field>
            <name>FB11</name>
            <bitOffset>11</bitOffset>
            <bitWidth>1</bitWidth>
          </field>
          <field>
            <name>FB12</name>
            <bitOffset>12</bitOffset>
            <bitWidth>1</bitWidth>
          </field>
          <field>
            <name>FB13</name>
            <bitOffset>13</bitOffset>
            <bitWidth>1</bitWidth>
          </field>
          <field>
            <name>FB14</name>
            <bitOffset>14</bitOffset>
            <bitWidth>1</bitWidth>
          </field>
          <field>
            <name>FB15</name>
            <bitOffset>15</bitOffset>
            <bitWidth>1</bitWidth>
          </field>
          <field>
            <name>FB16</name>
            <bitOffset>16</bitOffset>
            <bitWidth>1</bitWidth>
          </field>
          <field>
            <name>FB17</name>
            <bitOffset>17</bitOffset>
            <bitWidth>1</bitWidth>
          </field>
          <field>
            <name>FB18</name>
            <bitOffset>18</bitOffset>
            <bitWidth>1</bitWidth>
          </field>
          <field>
            <name>FB19</name>
            <bitOffset>19</bitOffset>
            <bitWidth>1</bitWidth>
          </field>
          <field>
            <name>FB20</name>
            <bitOffset>20</bitOffset>
            <bitWidth>1</bitWidth>
          </field>
          <field>
            <name>FB21</name>
            <bitOffset>21</bitOffset>
            <bitWidth>1</bitWidth>
          </field>
          <field>
            <name>FB22</name>
            <bitOffset>22</bitOffset>
            <bitWidth>1</bitWidth>
          </field>
          <field>
            <name>FB23</name>
            <bitOffset>23</bitOffset>
            <bitWidth>1</bitWidth>
          </field>
          <field>
            <name>FB24</name>
            <bitOffset>24</bitOffset>
            <bitWidth>1</bitWidth>
          </field>
          <field>
            <name>FB25</name>
            <bitOffset>25</bitOffset>
            <bitWidth>1</bitWidth>
          </field>
          <field>
            <name>FB26</name>
            <bitOffset>26</bitOffset>
            <bitWidth>1</bitWidth>
          </field>
          <field>
            <name>FB27</name>
            <bitOffset>27</bitOffset>
            <bitWidth>1</bitWidth>
          </field>
          <field>
            <name>FB28</name>
            <bitOffset>28</bitOffset>
            <bitWidth>1</bitWidth>
          </field>
          <field>
            <name>FB29</name>
            <bitOffset>29</bitOffset>
            <bitWidth>1</bitWidth>
          </field>
          <field>
            <name>FB30</name>
            <bitOffset>30</bitOffset>
            <bitWidth>1</bitWidth>
          </field>
          <field>
            <name>FB31</name>
            <bitOffset>31</bitOffset>
            <bitWidth>1</bitWidth>
          </field>
        </fields>
      </register>
      <register>
        <name>sFilterRegister.13.FR2</name>
        <addressOffset>0x2ac</addressOffset>
        <size>0x20</size>
        <fields>
          <field>
            <name>FB0</name>
            <bitOffset>0</bitOffset>
            <bitWidth>1</bitWidth>
          </field>
          <field>
            <name>FB1</name>
            <bitOffset>1</bitOffset>
            <bitWidth>1</bitWidth>
          </field>
          <field>
            <name>FB2</name>
            <bitOffset>2</bitOffset>
            <bitWidth>1</bitWidth>
          </field>
          <field>
            <name>FB3</name>
            <bitOffset>3</bitOffset>
            <bitWidth>1</bitWidth>
          </field>
          <field>
            <name>FB4</name>
            <bitOffset>4</bitOffset>
            <bitWidth>1</bitWidth>
          </field>
          <field>
            <name>FB5</name>
            <bitOffset>5</bitOffset>
            <bitWidth>1</bitWidth>
          </field>
          <field>
            <name>FB6</name>
            <bitOffset>6</bitOffset>
            <bitWidth>1</bitWidth>
          </field>
          <field>
            <name>FB7</name>
            <bitOffset>7</bitOffset>
            <bitWidth>1</bitWidth>
          </field>
          <field>
            <name>FB8</name>
            <bitOffset>8</bitOffset>
            <bitWidth>1</bitWidth>
          </field>
          <field>
            <name>FB9</name>
            <bitOffset>9</bitOffset>
            <bitWidth>1</bitWidth>
          </field>
          <field>
            <name>FB10</name>
            <bitOffset>10</bitOffset>
            <bitWidth>1</bitWidth>
          </field>
          <field>
            <name>FB11</name>
            <bitOffset>11</bitOffset>
            <bitWidth>1</bitWidth>
          </field>
          <field>
            <name>FB12</name>
            <bitOffset>12</bitOffset>
            <bitWidth>1</bitWidth>
          </field>
          <field>
            <name>FB13</name>
            <bitOffset>13</bitOffset>
            <bitWidth>1</bitWidth>
          </field>
          <field>
            <name>FB14</name>
            <bitOffset>14</bitOffset>
            <bitWidth>1</bitWidth>
          </field>
          <field>
            <name>FB15</name>
            <bitOffset>15</bitOffset>
            <bitWidth>1</bitWidth>
          </field>
          <field>
            <name>FB16</name>
            <bitOffset>16</bitOffset>
            <bitWidth>1</bitWidth>
          </field>
          <field>
            <name>FB17</name>
            <bitOffset>17</bitOffset>
            <bitWidth>1</bitWidth>
          </field>
          <field>
            <name>FB18</name>
            <bitOffset>18</bitOffset>
            <bitWidth>1</bitWidth>
          </field>
          <field>
            <name>FB19</name>
            <bitOffset>19</bitOffset>
            <bitWidth>1</bitWidth>
          </field>
          <field>
            <name>FB20</name>
            <bitOffset>20</bitOffset>
            <bitWidth>1</bitWidth>
          </field>
          <field>
            <name>FB21</name>
            <bitOffset>21</bitOffset>
            <bitWidth>1</bitWidth>
          </field>
          <field>
            <name>FB22</name>
            <bitOffset>22</bitOffset>
            <bitWidth>1</bitWidth>
          </field>
          <field>
            <name>FB23</name>
            <bitOffset>23</bitOffset>
            <bitWidth>1</bitWidth>
          </field>
          <field>
            <name>FB24</name>
            <bitOffset>24</bitOffset>
            <bitWidth>1</bitWidth>
          </field>
          <field>
            <name>FB25</name>
            <bitOffset>25</bitOffset>
            <bitWidth>1</bitWidth>
          </field>
          <field>
            <name>FB26</name>
            <bitOffset>26</bitOffset>
            <bitWidth>1</bitWidth>
          </field>
          <field>
            <name>FB27</name>
            <bitOffset>27</bitOffset>
            <bitWidth>1</bitWidth>
          </field>
          <field>
            <name>FB28</name>
            <bitOffset>28</bitOffset>
            <bitWidth>1</bitWidth>
          </field>
          <field>
            <name>FB29</name>
            <bitOffset>29</bitOffset>
            <bitWidth>1</bitWidth>
          </field>
          <field>
            <name>FB30</name>
            <bitOffset>30</bitOffset>
            <bitWidth>1</bitWidth>
          </field>
          <field>
            <name>FB31</name>
            <bitOffset>31</bitOffset>
            <bitWidth>1</bitWidth>
          </field>
        </fields>
      </register>
    </peripheral>
    <peripheral>
      <name>BKP</name>
      <baseAddress>0x40006c00</baseAddress>
      <register>
        <name>DR1</name>
        <addressOffset>0x4</addressOffset>
        <size>0x20</size>
        <fields>
          <field>
            <name>D</name>
            <bitOffset>0</bitOffset>
            <bitWidth>16</bitWidth>
          </field>
        </fields>
      </register>
      <register>
        <name>DR2</name>
        <addressOffset>0x8</addressOffset>
        <size>0x20</size>
        <fields>
          <field>
            <name>D</name>
            <bitOffset>0</bitOffset>
            <bitWidth>16</bitWidth>
          </field>
        </fields>
      </register>
      <register>
        <name>DR3</name>
        <addressOffset>0xc</addressOffset>
        <size>0x20</size>
        <fields>
          <field>
            <name>D</name>
            <bitOffset>0</bitOffset>
            <bitWidth>16</bitWidth>
          </field>
        </fields>
      </register>
      <register>
        <name>DR4</name>
        <addressOffset>0x10</addressOffset>
        <size>0x20</size>
        <fields>
          <field>
            <name>D</name>
            <bitOffset>0</bitOffset>
            <bitWidth>16</bitWidth>
          </field>
        </fields>
      </register>
      <register>
        <name>DR5</name>
        <addressOffset>0x14</addressOffset>
        <size>0x20</size>
        <fields>
          <field>
            <name>D</name>
            <bitOffset>0</bitOffset>
            <bitWidth>16</bitWidth>
          </field>
        </fields>
      </register>
      <register>
        <name>DR6</name>
        <addressOffset>0x18</addressOffset>
        <size>0x20</size>
        <fields>
          <field>
            <name>D</name>
            <bitOffset>0</bitOffset>
            <bitWidth>16</bitWidth>
          </field>
        </fields>
      </register>
      <register>
        <name>DR7</name>
        <addressOffset>0x1c</addressOffset>
        <size>0x20</size>
        <fields>
          <field>
            <name>D</name>
            <bitOffset>0</bitOffset>
            <bitWidth>16</bitWidth>
          </field>
        </fields>
      </register>
      <register>
        <name>DR8</name>
        <addressOffset>0x20</addressOffset>
        <size>0x20</size>
        <fields>
          <field>
            <name>D</name>
            <bitOffset>0</bitOffset>
            <bitWidth>16</bitWidth>
          </field>
        </fields>
      </register>
      <register>
        <name>DR9</name>
        <addressOffset>0x24</addressOffset>
        <size>0x20</size>
        <fields>
          <field>
            <name>D</name>
            <bitOffset>0</bitOffset>
            <bitWidth>16</bitWidth>
          </field>
        </fields>
      </register>
      <register>
        <name>DR10</name>
        <addressOffset>0x28</addressOffset>
        <size>0x20</size>
        <fields>
          <field>
            <name>D</name>
            <bitOffset>0</bitOffset>
            <bitWidth>16</bitWidth>
          </field>
        </fields>
      </register>
      <register>
        <name>RTCCR</name>
        <addressOffset>0x2c</addressOffset>
        <size>0x20</size>
        <fields>
          <field>
            <name>CAL</name>
            <bitOffset>0</bitOffset>
            <bitWidth>7</bitWidth>
          </field>
          <field>
            <name>CCO</name>
            <bitOffset>7</bitOffset>
            <bitWidth>1</bitWidth>
          </field>
          <field>
            <name>ASOE</name>
            <bitOffset>8</bitOffset>
            <bitWidth>1</bitWidth>
          </field>
          <field>
            <name>ASOS</name>
            <bitOffset>9</bitOffset>
            <bitWidth>1</bitWidth>
          </field>
        </fields>
      </register>
      <register>
        <name>CR</name>
        <addressOffset>0x30</addressOffset>
        <size>0x20</size>
        <fields>
          <field>
            <name>TPE</name>
            <bitOffset>0</bitOffset>
            <bitWidth>1</bitWidth>
          </field>
          <field>
            <name>TPAL</name>
            <bitOffset>1</bitOffset>
            <bitWidth>1</bitWidth>
          </field>
        </fields>
      </register>
      <register>
        <name>CSR</name>
        <addressOffset>0x34</addressOffset>
        <size>0x20</size>
        <fields>
          <field>
            <name>CTE</name>
            <bitOffset>0</bitOffset>
            <bitWidth>1</bitWidth>
          </field>
          <field>
            <name>CTI</name>
            <bitOffset>1</bitOffset>
            <bitWidth>1</bitWidth>
          </field>
          <field>
            <name>TPIE</name>
            <bitOffset>2</bitOffset>
            <bitWidth>1</bitWidth>
          </field>
          <field>
            <name>TEF</name>
            <bitOffset>8</bitOffset>
            <bitWidth>1</bitWidth>
          </field>
          <field>
            <name>TIF</name>
            <bitOffset>9</bitOffset>
            <bitWidth>1</bitWidth>
          </field>
        </fields>
      </register>
    </peripheral>
    <peripheral>
      <name>PWR</name>
      <baseAddress>0x40007000</baseAddress>
      <register>
        <name>CR</name>
        <addressOffset>0x0</addressOffset>
        <size>0x20</size>
        <fields>
          <field>
            <name>LPDS</name>
            <bitOffset>0</bitOffset>
            <bitWidth>1</bitWidth>
          </field>
          <field>
            <name>PDDS</name>
            <bitOffset>1</bitOffset>
            <bitWidth>1</bitWidth>
          </field>
          <field>
            <name>CWUF</name>
            <bitOffset>2</bitOffset>
            <bitWidth>1</bitWidth>
          </field>
          <field>
            <name>CSBF</name>
            <bitOffset>3</bitOffset>
            <bitWidth>1</bitWidth>
          </field>
          <field>
            <name>PVDE</name>
            <bitOffset>4</bitOffset>
            <bitWidth>1</bitWidth>
          </field>
          <field>
            <name>PLS</name>
            <bitOffset>5</bitOffset>
            <bitWidth>3</bitWidth>
          </field>
          <field>
            <name>DBP</name>
            <bitOffset>8</bitOffset>
            <bitWidth>1</bitWidth>
          </field>
        </fields>
      </register>
      <register>
        <name>CSR</name>
        <addressOffset>0x4</addressOffset>
        <size>0x20</size>
        <fields>
          <field>
            <name>WUF</name>
            <bitOffset>0</bitOffset>
            <bitWidth>1</bitWidth>
          </field>
          <field>
            <name>SBF</name>
            <bitOffset>1</bitOffset>
            <bitWidth>1</bitWidth>
          </field>
          <field>
            <name>PVDO</name>
            <bitOffset>2</bitOffset>
            <bitWidth>1</bitWidth>
          </field>
          <field>
            <name>EWUP</name>
            <bitOffset>8</bitOffset>
            <bitWidth>1</bitWidth>
          </field>
        </fields>
      </register>
    </peripheral>
    <peripheral>
      <name>AFIO</name>
      <baseAddress>0x40010000</baseAddress>
      <register>
        <name>EVCR</name>
        <addressOffset>0x0</addressOffset>
        <size>0x20</size>
        <fields>
          <field>
            <name>PIN_PX9</name>
            <bitOffset>0</bitOffset>
            <bitWidth>4</bitWidth>
          </field>
          <field>
            <name>PIN_PX6</name>
            <bitOffset>1</bitOffset>
            <bitWidth>2</bitWidth>
          </field>
          <field>
            <name>PIN_PX4</name>
            <bitOffset>2</bitOffset>
            <bitWidth>1</bitWidth>
          </field>
          <field>
            <name>PIN_PX8</name>
            <bitOffset>3</bitOffset>
            <bitWidth>1</bitWidth>
          </field>
          <field>
            <name>PORT_PD</name>
            <bitOffset>4</bitOffset>
            <bitWidth>2</bitWidth>
          </field>
          <field>
            <name>PORT_PC</name>
            <bitOffset>5</bitOffset>
            <bitWidth>1</bitWidth>
          </field>
          <field>
            <name>PORT_PE</name>
            <bitOffset>6</bitOffset>
            <bitWidth>1</bitWidth>
          </field>
          <field>
            <name>EVOE</name>
            <bitOffset>7</bitOffset>
            <bitWidth>1</bitWidth>
          </field>
        </fields>
      </register>
      <register>
        <name>MAPR</name>
        <addressOffset>0x4</addressOffset>
        <size>0x20</size>
        <fields>
          <field>
            <name>SPI1_REMAP</name>
            <bitOffset>0</bitOffset>
            <bitWidth>1</bitWidth>
          </field>
          <field>
            <name>I2C1_REMAP</name>
            <bitOffset>1</bitOffset>
            <bitWidth>1</bitWidth>
          </field>
          <field>
            <name>USART1_REMAP</name>
            <bitOffset>2</bitOffset>
            <bitWidth>1</bitWidth>
          </field>
          <field>
            <name>USART2_REMAP</name>
            <bitOffset>3</bitOffset>
            <bitWidth>1</bitWidth>
          </field>
          <field>
            <name>TIM1_REMAP_PARTIALREMAP</name>
            <bitOffset>6</bitOffset>
            <bitWidth>1</bitWidth>
          </field>
          <field>
            <name>TIM2_REMAP_PARTIALREMAP1</name>
            <bitOffset>8</bitOffset>
            <bitWidth>1</bitWidth>
          </field>
          <field>
            <name>TIM2_REMAP_PARTIALREMAP2</name>
            <bitOffset>9</bitOffset>
            <bitWidth>1</bitWidth>
          </field>
          <field>
            <name>TIM3_REMAP_FULLREMAP</name>
            <bitOffset>10</bitOffset>
            <bitWidth>2</bitWidth>
          </field>
          <field>
            <name>TIM3_REMAP_PARTIALREMAP</name>
            <bitOffset>11</bitOffset>
            <bitWidth>1</bitWidth>
          </field>
          <field>
            <name>CAN_REMAP_REMAP3</name>
            <bitOffset>13</bitOffset>
            <bitWidth>2</bitWidth>
          </field>
          <field>
            <name>CAN_REMAP_REMAP2</name>
            <bitOffset>14</bitOffset>
            <bitWidth>1</bitWidth>
          </field>
          <field>
            <name>PD01_REMAP</name>
            <bitOffset>15</bitOffset>
            <bitWidth>1</bitWidth>
          </field>
          <field>
            <name>SWJ_CFG_NOJNTRST</name>
            <bitOffset>24</bitOffset>
            <bitWidth>1</bitWidth>
          </field>
          <field>
            <name>SWJ_CFG_JTAGDISABLE</name>
            <bitOffset>25</bitOffset>
            <bitWidth>1</bitWidth>
          </field>
          <field>
            <name>SWJ_CFG_DISABLE</name>
            <bitOffset>26</bitOffset>
            <bitWidth>1</bitWidth>
          </field>
        </fields>
      </register>
      <register>
        <name>EXTICR.0</name>
        <addressOffset>0x8</addressOffset>
        <size>0x20</size>
        <fields>
          <field>
            <name>EXTI0_PF</name>
            <bitOffset>0</bitOffset>
            <bitWidth>3</bitWidth>
          </field>
          <field>
            <name>EXTI0_PG</name>
            <bitOffset>1</bitOffset>
            <bitWidth>2</bitWidth>
          </field>
          <field>
            <name>EXTI0_PE</name>
            <bitOffset>2</bitOffset>
            <bitWidth>1</bitWidth>
          </field>
          <field>
            <name>EXTI1_PF</name>
            <bitOffset>4</bitOffset>
            <bitWidth>3</bitWidth>
          </field>
          <field>
            <name>EXTI1_PG</name>
            <bitOffset>5</bitOffset>
            <bitWidth>2</bitWidth>
          </field>
          <field>
            <name>EXTI1_PE</name>
            <bitOffset>6</bitOffset>
            <bitWidth>1</bitWidth>
          </field>
          <field>
            <name>EXTI2_PF</name>
            <bitOffset>8</bitOffset>
            <bitWidth>3</bitWidth>
          </field>
          <field>
            <name>EXTI2_PG</name>
            <bitOffset>9</bitOffset>
            <bitWidth>2</bitWidth>
          </field>
          <field>
            <name>EXTI2_PE</name>
            <bitOffset>10</bitOffset>
            <bitWidth>1</bitWidth>
          </field>
          <field>
            <name>EXTI3_PF</name>
            <bitOffset>12</bitOffset>
            <bitWidth>3</bitWidth>
          </field>
          <field>
            <name>EXTI3_PG</name>
            <bitOffset>13</bitOffset>
            <bitWidth>2</bitWidth>
          </field>
          <field>
            <name>EXTI3_PE</name>
            <bitOffset>14</bitOffset>
            <bitWidth>1</bitWidth>
          </field>
        </fields>
      </register>
      <register>
        <name>EXTICR.1</name>
        <addressOffset>0xc</addressOffset>
        <size>0x20</size>
        <fields>
          <field>
            <name>EXTI4_PF</name>
            <bitOffset>0</bitOffset>
            <bitWidth>3</bitWidth>
          </field>
          <field>
            <name>EXTI4_PG</name>
            <bitOffset>1</bitOffset>
            <bitWidth>2</bitWidth>
          </field>
          <field>
            <name>EXTI4_PE</name>
            <bitOffset>2</bitOffset>
            <bitWidth>1</bitWidth>
          </field>
          <field>
            <name>EXTI5_PF</name>
            <bitOffset>4</bitOffset>
            <bitWidth>3</bitWidth>
          </field>
          <field>
            <name>EXTI5_PG</name>
            <bitOffset>5</bitOffset>
            <bitWidth>2</bitWidth>
          </field>
          <field>
            <name>EXTI5_PE</name>
            <bitOffset>6</bitOffset>
            <bitWidth>1</bitWidth>
          </field>
          <field>
            <name>EXTI6_PF</name>
            <bitOffset>8</bitOffset>
            <bitWidth>3</bitWidth>
          </field>
          <field>
            <name>EXTI6_PG</name>
            <bitOffset>9</bitOffset>
            <bitWidth>2</bitWidth>
          </field>
          <field>
            <name>EXTI6_PE</name>
            <bitOffset>10</bitOffset>
            <bitWidth>1</bitWidth>
          </field>
          <field>
            <name>EXTI7_PF</name>
            <bitOffset>12</bitOffset>
            <bitWidth>3</bitWidth>
          </field>
          <field>
            <name>EXTI7_PG</name>
            <bitOffset>13</bitOffset>
            <bitWidth>2</bitWidth>
          </field>
          <field>
            <name>EXTI7_PE</name>
            <bitOffset>14</bitOffset>
            <bitWidth>1</bitWidth>
          </field>
        </fields>
      </register>
      <register>
        <name>EXTICR.2</name>
        <addressOffset>0x10</addressOffset>
        <size>0x20</size>
        <fields>
          <field>
            <name>EXTI8_PF</name>
            <bitOffset>0</bitOffset>
            <bitWidth>3</bitWidth>
          </field>
          <field>
            <name>EXTI8_PG</name>
            <bitOffset>1</bitOffset>
            <bitWidth>2</bitWidth>
          </field>
          <field>
            <name>EXTI8_PE</name>
            <bitOffset>2</bitOffset>
            <bitWidth>1</bitWidth>
          </field>
          <field>
            <name>EXTI9_PF</name>
            <bitOffset>4</bitOffset>
            <bitWidth>3</bitWidth>
          </field>
          <field>
            <name>EXTI9_PG</name>
            <bitOffset>5</bitOffset>
            <bitWidth>2</bitWidth>
          </field>
          <field>
            <name>EXTI9_PE</name>
            <bitOffset>6</bitOffset>
            <bitWidth>1</bitWidth>
          </field>
          <field>
            <name>EXTI10_PF</name>
            <bitOffset>8</bitOffset>
            <bitWidth>3</bitWidth>
          </field>
          <field>
            <name>EXTI10_PG</name>
            <bitOffset>9</bitOffset>
            <bitWidth>2</bitWidth>
          </field>
          <field>
            <name>EXTI10_PE</name>
            <bitOffset>10</bitOffset>
            <bitWidth>1</bitWidth>
          </field>
          <field>
            <name>EXTI11_PF</name>
            <bitOffset>12</bitOffset>
            <bitWidth>3</bitWidth>
          </field>
          <field>
            <name>EXTI11_PG</name>
            <bitOffset>13</bitOffset>
            <bitWidth>2</bitWidth>
          </field>
          <field>
            <name>EXTI11_PE</name>
            <bitOffset>14</bitOffset>
            <bitWidth>1</bitWidth>
          </field>
        </fields>
      </register>
      <register>
        <name>EXTICR.3</name>
        <addressOffset>0x14</addressOffset>
        <size>0x20</size>
        <fields>
          <field>
            <name>EXTI12_PF</name>
            <bitOffset>0</bitOffset>
            <bitWidth>3</bitWidth>
          </field>
          <field>
            <name>EXTI12_PG</name>
            <bitOffset>1</bitOffset>
            <bitWidth>2</bitWidth>
          </field>
          <field>
            <name>EXTI12_PE</name>
            <bitOffset>2</bitOffset>
            <bitWidth>1</bitWidth>
          </field>
          <field>
            <name>EXTI13_PF</name>
            <bitOffset>4</bitOffset>
            <bitWidth>3</bitWidth>
          </field>
          <field>
            <name>EXTI13_PG</name>
            <bitOffset>5</bitOffset>
            <bitWidth>2</bitWidth>
          </field>
          <field>
            <name>EXTI13_PE</name>
            <bitOffset>6</bitOffset>
            <bitWidth>1</bitWidth>
          </field>
          <field>
            <name>EXTI14_PF</name>
            <bitOffset>8</bitOffset>
            <bitWidth>3</bitWidth>
          </field>
          <field>
            <name>EXTI14_PG</name>
            <bitOffset>9</bitOffset>
            <bitWidth>2</bitWidth>
          </field>
          <field>
            <name>EXTI14_PE</name>
            <bitOffset>10</bitOffset>
            <bitWidth>1</bitWidth>
          </field>
          <field>
            <name>EXTI15_PF</name>
            <bitOffset>12</bitOffset>
            <bitWidth>3</bitWidth>
          </field>
          <field>
            <name>EXTI15_PG</name>
            <bitOffset>13</bitOffset>
            <bitWidth>2</bitWidth>
          </field>
          <field>
            <name>EXTI15_PE</name>
            <bitOffset>14</bitOffset>
            <bitWidth>1</bitWidth>
          </field>
        </fields>
      </register>
      <register>
        <name>MAPR2</name>
        <addressOffset>0x1c</addressOffset>
        <size>0x20</size>
      </register>
    </peripheral>
    <peripheral>
      <name>EXTI</name>
      <baseAddress>0x40010400</baseAddress>
      <register>
        <name>IMR</name>
        <addressOffset>0x0</addressOffset>
        <size>0x20</size>
        <fields>
          <field>
            <name>MR0</name>
            <bitOffset>0</bitOffset>
            <bitWidth>1</bitWidth>
          </field>
          <field>
            <name>MR1</name>
            <bitOffset>1</bitOffset>
            <bitWidth>1</bitWidth>
          </field>
          <field>
            <name>MR2</name>
            <bitOffset>2</bitOffset>
            <bitWidth>1</bitWidth>
          </field>
          <field>
            <name>MR3</name>
            <bitOffset>3</bitOffset>
            <bitWidth>1</bitWidth>
          </field>
          <field>
            <name>MR4</name>
            <bitOffset>4</bitOffset>
            <bitWidth>1</bitWidth>
          </field>
          <field>
            <name>MR5</name>
            <bitOffset>5</bitOffset>
            <bitWidth>1</bitWidth>
          </field>
          <field>
            <name>MR6</name>
            <bitOffset>6</bitOffset>
            <bitWidth>1</bitWidth>
          </field>
          <field>
            <name>MR7</name>
            <bitOffset>7</bitOffset>
            <bitWidth>1</bitWidth>
          </field>
          <field>
            <name>MR8</name>
            <bitOffset>8</bitOffset>
            <bitWidth>1</bitWidth>
          </field>
          <field>
            <name>MR9</name>
            <bitOffset>9</bitOffset>
            <bitWidth>1</bitWidth>
          </field>
          <field>
            <name>MR10</name>
            <bitOffset>10</bitOffset>
            <bitWidth>1</bitWidth>
          </field>
          <field>
            <name>MR11</name>
            <bitOffset>11</bitOffset>
            <bitWidth>1</bitWidth>
          </field>
          <field>
            <name>MR12</name>
            <bitOffset>12</bitOffset>
            <bitWidth>1</bitWidth>
          </field>
          <field>
            <name>MR13</name>
            <bitOffset>13</bitOffset>
            <bitWidth>1</bitWidth>
          </field>
          <field>
            <name>MR14</name>
            <bitOffset>14</bitOffset>
            <bitWidth>1</bitWidth>
          </field>
          <field>
            <name>MR15</name>
            <bitOffset>15</bitOffset>
            <bitWidth>1</bitWidth>
          </field>
          <field>
            <name>MR16</name>
            <bitOffset>16</bitOffset>
            <bitWidth>1</bitWidth>
          </field>
          <field>
            <name>MR17</name>
            <bitOffset>17</bitOffset>
            <bitWidth>1</bitWidth>
          </field>
          <field>
            <name>MR18</name>
            <bitOffset>18</bitOffset>
            <bitWidth>1</bitWidth>
          </field>
        </fields>
      </register>
      <register>
        <name>EMR</name>
        <addressOffset>0x4</addressOffset>
        <size>0x20</size>
        <fields>
          <field>
            <name>MR0</name>
            <bitOffset>0</bitOffset>
            <bitWidth>1</bitWidth>
          </field>
          <field>
            <name>MR1</name>
            <bitOffset>1</bitOffset>
            <bitWidth>1</bitWidth>
          </field>
          <field>
            <name>MR2</name>
            <bitOffset>2</bitOffset>
            <bitWidth>1</bitWidth>
          </field>
          <field>
            <name>MR3</name>
            <bitOffset>3</bitOffset>
            <bitWidth>1</bitWidth>
          </field>
          <field>
            <name>MR4</name>
            <bitOffset>4</bitOffset>
            <bitWidth>1</bitWidth>
          </field>
          <field>
            <name>MR5</name>
            <bitOffset>5</bitOffset>
            <bitWidth>1</bitWidth>
          </field>
          <field>
            <name>MR6</name>
            <bitOffset>6</bitOffset>
            <bitWidth>1</bitWidth>
          </field>
          <field>
            <name>MR7</name>
            <bitOffset>7</bitOffset>
            <bitWidth>1</bitWidth>
          </field>
          <field>
            <name>MR8</name>
            <bitOffset>8</bitOffset>
            <bitWidth>1</bitWidth>
          </field>
          <field>
            <name>MR9</name>
            <bitOffset>9</bitOffset>
            <bitWidth>1</bitWidth>
          </field>
          <field>
            <name>MR10</name>
            <bitOffset>10</bitOffset>
            <bitWidth>1</bitWidth>
          </field>
          <field>
            <name>MR11</name>
            <bitOffset>11</bitOffset>
            <bitWidth>1</bitWidth>
          </field>
          <field>
            <name>MR12</name>
            <bitOffset>12</bitOffset>
            <bitWidth>1</bitWidth>
          </field>
          <field>
            <name>MR13</name>
            <bitOffset>13</bitOffset>
            <bitWidth>1</bitWidth>
          </field>
          <field>
            <name>MR14</name>
            <bitOffset>14</bitOffset>
            <bitWidth>1</bitWidth>
          </field>
          <field>
            <name>MR15</name>
            <bitOffset>15</bitOffset>
            <bitWidth>1</bitWidth>
          </field>
          <field>
            <name>MR16</name>
            <bitOffset>16</bitOffset>
            <bitWidth>1</bitWidth>
          </field>
          <field>
            <name>MR17</name>
            <bitOffset>17</bitOffset>
            <bitWidth>1</bitWidth>
          </field>
          <field>
            <name>MR18</name>
            <bitOffset>18</bitOffset>
            <bitWidth>1</bitWidth>
          </field>
        </fields>
      </register>
      <register>
        <name>RTSR</name>
        <addressOffset>0x8</addressOffset>
        <size>0x20</size>
        <fields>
          <field>
            <name>TR0</name>
            <bitOffset>0</bitOffset>
            <bitWidth>1</bitWidth>
          </field>
          <field>
            <name>TR1</name>
            <bitOffset>1</bitOffset>
            <bitWidth>1</bitWidth>
          </field>
          <field>
            <name>TR2</name>
            <bitOffset>2</bitOffset>
            <bitWidth>1</bitWidth>
          </field>
          <field>
            <name>TR3</name>
            <bitOffset>3</bitOffset>
            <bitWidth>1</bitWidth>
          </field>
          <field>
            <name>TR4</name>
            <bitOffset>4</bitOffset>
            <bitWidth>1</bitWidth>
          </field>
          <field>
            <name>TR5</name>
            <bitOffset>5</bitOffset>
            <bitWidth>1</bitWidth>
          </field>
          <field>
            <name>TR6</name>
            <bitOffset>6</bitOffset>
            <bitWidth>1</bitWidth>
          </field>
          <field>
            <name>TR7</name>
            <bitOffset>7</bitOffset>
            <bitWidth>1</bitWidth>
          </field>
          <field>
            <name>TR8</name>
            <bitOffset>8</bitOffset>
            <bitWidth>1</bitWidth>
          </field>
          <field>
            <name>TR9</name>
            <bitOffset>9</bitOffset>
            <bitWidth>1</bitWidth>
          </field>
          <field>
            <name>TR10</name>
            <bitOffset>10</bitOffset>
            <bitWidth>1</bitWidth>
          </field>
          <field>
            <name>TR11</name>
            <bitOffset>11</bitOffset>
            <bitWidth>1</bitWidth>
          </field>
          <field>
            <name>TR12</name>
            <bitOffset>12</bitOffset>
            <bitWidth>1</bitWidth>
          </field>
          <field>
            <name>TR13</name>
            <bitOffset>13</bitOffset>
            <bitWidth>1</bitWidth>
          </field>
          <field>
            <name>TR14</name>
            <bitOffset>14</bitOffset>
            <bitWidth>1</bitWidth>
          </field>
          <field>
            <name>TR15</name>
            <bitOffset>15</bitOffset>
            <bitWidth>1</bitWidth>
          </field>
          <field>
            <name>TR16</name>
            <bitOffset>16</bitOffset>
            <bitWidth>1</bitWidth>
          </field>
          <field>
            <name>TR17</name>
            <bitOffset>17</bitOffset>
            <bitWidth>1</bitWidth>
          </field>
          <field>
            <name>TR18</name>
            <bitOffset>18</bitOffset>
            <bitWidth>1</bitWidth>
          </field>
        </fields>
      </register>
      <register>
        <name>FTSR</name>
        <addressOffset>0xc</addressOffset>
        <size>0x20</size>
        <fields>
          <field>
            <name>TR0</name>
            <bitOffset>0</bitOffset>
            <bitWidth>1</bitWidth>
          </field>
          <field>
            <name>TR1</name>
            <bitOffset>1</bitOffset>
            <bitWidth>1</bitWidth>
          </field>
          <field>
            <name>TR2</name>
            <bitOffset>2</bitOffset>
            <bitWidth>1</bitWidth>
          </field>
          <field>
            <name>TR3</name>
            <bitOffset>3</bitOffset>
            <bitWidth>1</bitWidth>
          </field>
          <field>
            <name>TR4</name>
            <bitOffset>4</bitOffset>
            <bitWidth>1</bitWidth>
          </field>
          <field>
            <name>TR5</name>
            <bitOffset>5</bitOffset>
            <bitWidth>1</bitWidth>
          </field>
          <field>
            <name>TR6</name>
            <bitOffset>6</bitOffset>
            <bitWidth>1</bitWidth>
          </field>
          <field>
            <name>TR7</name>
            <bitOffset>7</bitOffset>
            <bitWidth>1</bitWidth>
          </field>
          <field>
            <name>TR8</name>
            <bitOffset>8</bitOffset>
            <bitWidth>1</bitWidth>
          </field>
          <field>
            <name>TR9</name>
            <bitOffset>9</bitOffset>
            <bitWidth>1</bitWidth>
          </field>
          <field>
            <name>TR10</name>
            <bitOffset>10</bitOffset>
            <bitWidth>1</bitWidth>
          </field>
          <field>
            <name>TR11</name>
            <bitOffset>11</bitOffset>
            <bitWidth>1</bitWidth>
          </field>
          <field>
            <name>TR12</name>
            <bitOffset>12</bitOffset>
            <bitWidth>1</bitWidth>
          </field>
          <field>
            <name>TR13</name>
            <bitOffset>13</bitOffset>
            <bitWidth>1</bitWidth>
          </field>
          <field>
            <name>TR14</name>
            <bitOffset>14</bitOffset>
            <bitWidth>1</bitWidth>
          </field>
          <field>
            <name>TR15</name>
            <bitOffset>15</bitOffset>
            <bitWidth>1</bitWidth>
          </field>
          <field>
            <name>TR16</name>
            <bitOffset>16</bitOffset>
            <bitWidth>1</bitWidth>
          </field>
          <field>
            <name>TR17</name>
            <bitOffset>17</bitOffset>
            <bitWidth>1</bitWidth>
          </field>
          <field>
            <name>TR18</name>
            <bitOffset>18</bitOffset>
            <bitWidth>1</bitWidth>
          </field>
        </fields>
      </register>
      <register>
        <name>SWIER</name>
        <addressOffset>0x10</addressOffset>
        <size>0x20</size>
        <fields>
          <field>
            <name>SWIER0</name>
            <bitOffset>0</bitOffset>
            <bitWidth>1</bitWidth>
          </field>
          <field>
            <name>SWIER1</name>
            <bitOffset>1</bitOffset>
            <bitWidth>1</bitWidth>
          </field>
          <field>
            <name>SWIER2</name>
            <bitOffset>2</bitOffset>
            <bitWidth>1</bitWidth>
          </field>
          <field>
            <name>SWIER3</name>
            <bitOffset>3</bitOffset>
            <bitWidth>1</bitWidth>
          </field>
          <field>
            <name>SWIER4</name>
            <bitOffset>4</bitOffset>
            <bitWidth>1</bitWidth>
          </field>
          <field>
            <name>SWIER5</name>
            <bitOffset>5</bitOffset>
            <bitWidth>1</bitWidth>
          </field>
          <field>
            <name>SWIER6</name>
            <bitOffset>6</bitOffset>
            <bitWidth>1</bitWidth>
          </field>
          <field>
            <name>SWIER7</name>
            <bitOffset>7</bitOffset>
            <bitWidth>1</bitWidth>
          </field>
          <field>
            <name>SWIER8</name>
            <bitOffset>8</bitOffset>
            <bitWidth>1</bitWidth>
          </field>
          <field>
            <name>SWIER9</name>
            <bitOffset>9</bitOffset>
            <bitWidth>1</bitWidth>
          </field>
          <field>
            <name>SWIER10</name>
            <bitOffset>10</bitOffset>
            <bitWidth>1</bitWidth>
          </field>
          <field>
            <name>SWIER11</name>
            <bitOffset>11</bitOffset>
            <bitWidth>1</bitWidth>
          </field>
          <field>
            <name>SWIER12</name>
            <bitOffset>12</bitOffset>
            <bitWidth>1</bitWidth>
          </field>
          <field>
            <name>SWIER13</name>
            <bitOffset>13</bitOffset>
            <bitWidth>1</bitWidth>
          </field>
          <field>
            <name>SWIER14</name>
            <bitOffset>14</bitOffset>
            <bitWidth>1</bitWidth>
          </field>
          <field>
            <name>SWIER15</name>
            <bitOffset>15</bitOffset>
            <bitWidth>1</bitWidth>
          </field>
          <field>
            <name>SWIER16</name>
            <bitOffset>16</bitOffset>
            <bitWidth>1</bitWidth>
          </field>
          <field>
            <name>SWIER17</name>
            <bitOffset>17</bitOffset>
            <bitWidth>1</bitWidth>
          </field>
          <field>
            <name>SWIER18</name>
            <bitOffset>18</bitOffset>
            <bitWidth>1</bitWidth>
          </field>
        </fields>
      </register>
      <register>
        <name>PR</name>
        <addressOffset>0x14</addressOffset>
        <size>0x20</size>
        <fields>
          <field>
            <name>PR0</name>
            <bitOffset>0</bitOffset>
            <bitWidth>1</bitWidth>
          </field>
          <field>
            <name>PR1</name>
            <bitOffset>1</bitOffset>
            <bitWidth>1</bitWidth>
          </field>
          <field>
            <name>PR2</name>
            <bitOffset>2</bitOffset>
            <bitWidth>1</bitWidth>
          </field>
          <field>
            <name>PR3</name>
            <bitOffset>3</bitOffset>
            <bitWidth>1</bitWidth>
          </field>
          <field>
            <name>PR4</name>
            <bitOffset>4</bitOffset>
            <bitWidth>1</bitWidth>
          </field>
          <field>
            <name>PR5</name>
            <bitOffset>5</bitOffset>
            <bitWidth>1</bitWidth>
          </field>
          <field>
            <name>PR6</name>
            <bitOffset>6</bitOffset>
            <bitWidth>1</bitWidth>
          </field>
          <field>
            <name>PR7</name>
            <bitOffset>7</bitOffset>
            <bitWidth>1</bitWidth>
          </field>
          <field>
            <name>PR8</name>
            <bitOffset>8</bitOffset>
            <bitWidth>1</bitWidth>
          </field>
          <field>
            <name>PR9</name>
            <bitOffset>9</bitOffset>
            <bitWidth>1</bitWidth>
          </field>
          <field>
            <name>PR10</name>
            <bitOffset>10</bitOffset>
            <bitWidth>1</bitWidth>
          </field>
          <field>
            <name>PR11</name>
            <bitOffset>11</bitOffset>
            <bitWidth>1</bitWidth>
          </field>
          <field>
            <name>PR12</name>
            <bitOffset>12</bitOffset>
            <bitWidth>1</bitWidth>
          </field>
          <field>
            <name>PR13</name>
            <bitOffset>13</bitOffset>
            <bitWidth>1</bitWidth>
          </field>
          <field>
            <name>PR14</name>
            <bitOffset>14</bitOffset>
            <bitWidth>1</bitWidth>
          </field>
          <field>
            <name>PR15</name>
            <bitOffset>15</bitOffset>
            <bitWidth>1</bitWidth>
          </field>
          <field>
            <name>PR16</name>
            <bitOffset>16</bitOffset>
            <bitWidth>1</bitWidth>
          </field>
          <field>
            <name>PR17</name>
            <bitOffset>17</bitOffset>
            <bitWidth>1</bitWidth>
          </field>
          <field>
            <name>PR18</name>
            <bitOffset>18</bitOffset>
            <bitWidth>1</bitWidth>
          </field>
        </fields>
      </register>
    </peripheral>
    <peripheral>
      <name>GPIOA</name>
      <baseAddress>0x40010800</baseAddress>
      <register>
        <name>CRL</name>
        <addressOffset>0x0</addressOffset>
        <size>0x20</size>
        <fields>
          <field>
            <name>MODE0</name>
            <bitOffset>0</bitOffset>
            <bitWidth>2</bitWidth>
          </field>
          <field>
            <name>CNF0</name>
            <bitOffset>2</bitOffset>
            <bitWidth>2</bitWidth>
          </field>
          <field>
            <name>MODE1</name>
            <bitOffset>4</bitOffset>
            <bitWidth>2</bitWidth>
          </field>
          <field>
            <name>CNF1</name>
            <bitOffset>6</bitOffset>
            <bitWidth>2</bitWidth>
          </field>
          <field>
            <name>MODE2</name>
            <bitOffset>8</bitOffset>
            <bitWidth>2</bitWidth>
          </field>
          <field>
            <name>CNF2</name>
            <bitOffset>10</bitOffset>
            <bitWidth>2</bitWidth>
          </field>
          <field>
            <name>MODE3</name>
            <bitOffset>12</bitOffset>
            <bitWidth>2</bitWidth>
          </field>
          <field>
            <name>CNF3</name>
            <bitOffset>14</bitOffset>
            <bitWidth>2</bitWidth>
          </field>
          <field>
            <name>MODE4</name>
            <bitOffset>16</bitOffset>
            <bitWidth>2</bitWidth>
          </field>
          <field>
            <name>CNF4</name>
            <bitOffset>18</bitOffset>
            <bitWidth>2</bitWidth>
          </field>
          <field>
            <name>MODE5</name>
            <bitOffset>20</bitOffset>
            <bitWidth>2</bitWidth>
          </field>
          <field>
            <name>CNF5</name>
            <bitOffset>22</bitOffset>
            <bitWidth>2</bitWidth>
          </field>
          <field>
            <name>MODE6</name>
            <bitOffset>24</bitOffset>
            <bitWidth>2</bitWidth>
          </field>
          <field>
            <name>CNF6</name>
            <bitOffset>26</bitOffset>
            <bitWidth>2</bitWidth>
          </field>
          <field>
            <name>MODE7</name>
            <bitOffset>28</bitOffset>
            <bitWidth>2</bitWidth>
          </field>
          <field>
            <name>CNF7</name>
            <bitOffset>30</bitOffset>
            <bitWidth>2</bitWidth>
          </field>
        </fields>
      </register>
      <register>
        <name>CRH</name>
        <addressOffset>0x4</addressOffset>
        <size>0x20</size>
        <fields>
          <field>
            <name>MODE8</name>
            <bitOffset>0</bitOffset>
            <bitWidth>2</bitWidth>
          </field>
          <field>
            <name>CNF8</name>
            <bitOffset>2</bitOffset>
            <bitWidth>2</bitWidth>
          </field>
          <field>
            <name>MODE9</name>
            <bitOffset>4</bitOffset>
            <bitWidth>2</bitWidth>
          </field>
          <field>
            <name>CNF9</name>
            <bitOffset>6</bitOffset>
            <bitWidth>2</bitWidth>
          </field>
          <field>
            <name>MODE10</name>
            <bitOffset>8</bitOffset>
            <bitWidth>2</bitWidth>
          </field>
          <field>
            <name>CNF10</name>
            <bitOffset>10</bitOffset>
            <bitWidth>2</bitWidth>
          </field>
          <field>
            <name>MODE11</name>
            <bitOffset>12</bitOffset>
            <bitWidth>2</bitWidth>
          </field>
          <field>
            <name>CNF11</name>
            <bitOffset>14</bitOffset>
            <bitWidth>2</bitWidth>
          </field>
          <field>
            <name>MODE12</name>
            <bitOffset>16</bitOffset>
            <bitWidth>2</bitWidth>
          </field>
          <field>
            <name>CNF12</name>
            <bitOffset>18</bitOffset>
            <bitWidth>2</bitWidth>
          </field>
          <field>
            <name>MODE13</name>
            <bitOffset>20</bitOffset>
            <bitWidth>2</bitWidth>
          </field>
          <field>
            <name>CNF13</name>
            <bitOffset>22</bitOffset>
            <bitWidth>2</bitWidth>
          </field>
          <field>
            <name>MODE14</name>
            <bitOffset>24</bitOffset>
            <bitWidth>2</bitWidth>
          </field>
          <field>
            <name>CNF14</name>
            <bitOffset>26</bitOffset>
            <bitWidth>2</bitWidth>
          </field>
          <field>
            <name>MODE15</name>
            <bitOffset>28</bitOffset>
            <bitWidth>2</bitWidth>
          </field>
          <field>
            <name>CNF15</name>
            <bitOffset>30</bitOffset>
            <bitWidth>2</bitWidth>
          </field>
        </fields>
      </register>
      <register>
        <name>IDR</name>
        <addressOffset>0x8</addressOffset>
        <size>0x20</size>
        <fields>
          <field>
            <name>IDR0</name>
            <bitOffset>0</bitOffset>
            <bitWidth>1</bitWidth>
          </field>
          <field>
            <name>IDR1</name>
            <bitOffset>1</bitOffset>
            <bitWidth>1</bitWidth>
          </field>
          <field>
            <name>IDR2</name>
            <bitOffset>2</bitOffset>
            <bitWidth>1</bitWidth>
          </field>
          <field>
            <name>IDR3</name>
            <bitOffset>3</bitOffset>
            <bitWidth>1</bitWidth>
          </field>
          <field>
            <name>IDR4</name>
            <bitOffset>4</bitOffset>
            <bitWidth>1</bitWidth>
          </field>
          <field>
            <name>IDR5</name>
            <bitOffset>5</bitOffset>
            <bitWidth>1</bitWidth>
          </field>
          <field>
            <name>IDR6</name>
            <bitOffset>6</bitOffset>
            <bitWidth>1</bitWidth>
          </field>
          <field>
            <name>IDR7</name>
            <bitOffset>7</bitOffset>
            <bitWidth>1</bitWidth>
          </field>
          <field>
            <name>IDR8</name>
            <bitOffset>8</bitOffset>
            <bitWidth>1</bitWidth>
          </field>
          <field>
            <name>IDR9</name>
            <bitOffset>9</bitOffset>
            <bitWidth>1</bitWidth>
          </field>
          <field>
            <name>IDR10</name>
            <bitOffset>10</bitOffset>
            <bitWidth>1</bitWidth>
          </field>
          <field>
            <name>IDR11</name>
            <bitOffset>11</bitOffset>
            <bitWidth>1</bitWidth>
          </field>
          <field>
            <name>IDR12</name>
            <bitOffset>12</bitOffset>
            <bitWidth>1</bitWidth>
          </field>
          <field>
            <name>IDR13</name>
            <bitOffset>13</bitOffset>
            <bitWidth>1</bitWidth>
          </field>
          <field>
            <name>IDR14</name>
            <bitOffset>14</bitOffset>
            <bitWidth>1</bitWidth>
          </field>
          <field>
            <name>IDR15</name>
            <bitOffset>15</bitOffset>
            <bitWidth>1</bitWidth>
          </field>
        </fields>
      </register>
      <register>
        <name>ODR</name>
        <addressOffset>0xc</addressOffset>
        <size>0x20</size>
        <fields>
          <field>
            <name>ODR0</name>
            <bitOffset>0</bitOffset>
            <bitWidth>1</bitWidth>
          </field>
          <field>
            <name>ODR1</name>
            <bitOffset>1</bitOffset>
            <bitWidth>1</bitWidth>
          </field>
          <field>
            <name>ODR2</name>
            <bitOffset>2</bitOffset>
            <bitWidth>1</bitWidth>
          </field>
          <field>
            <name>ODR3</name>
            <bitOffset>3</bitOffset>
            <bitWidth>1</bitWidth>
          </field>
          <field>
            <name>ODR4</name>
            <bitOffset>4</bitOffset>
            <bitWidth>1</bitWidth>
          </field>
          <field>
            <name>ODR5</name>
            <bitOffset>5</bitOffset>
            <bitWidth>1</bitWidth>
          </field>
          <field>
            <name>ODR6</name>
            <bitOffset>6</bitOffset>
            <bitWidth>1</bitWidth>
          </field>
          <field>
            <name>ODR7</name>
            <bitOffset>7</bitOffset>
            <bitWidth>1</bitWidth>
          </field>
          <field>
            <name>ODR8</name>
            <bitOffset>8</bitOffset>
            <bitWidth>1</bitWidth>
          </field>
          <field>
            <name>ODR9</name>
            <bitOffset>9</bitOffset>
            <bitWidth>1</bitWidth>
          </field>
          <field>
            <name>ODR10</name>
            <bitOffset>10</bitOffset>
            <bitWidth>1</bitWidth>
          </field>
          <field>
            <name>ODR11</name>
            <bitOffset>11</bitOffset>
            <bitWidth>1</bitWidth>
          </field>
          <field>
            <name>ODR12</name>
            <bitOffset>12</bitOffset>
            <bitWidth>1</bitWidth>
          </field>
          <field>
            <name>ODR13</name>
            <bitOffset>13</bitOffset>
            <bitWidth>1</bitWidth>
          </field>
          <field>
            <name>ODR14</name>
            <bitOffset>14</bitOffset>
            <bitWidth>1</bitWidth>
          </field>
          <field>
            <name>ODR15</name>
            <bitOffset>15</bitOffset>
            <bitWidth>1</bitWidth>
          </field>
        </fields>
      </register>
      <register>
        <name>BSRR</name>
        <addressOffset>0x10</addressOffset>
        <size>0x20</size>
        <fields>
          <field>
            <name>BS0</name>
            <bitOffset>0</bitOffset>
            <bitWidth>1</bitWidth>
          </field>
          <field>
            <name>BS1</name>
            <bitOffset>1</bitOffset>
            <bitWidth>1</bitWidth>
          </field>
          <field>
            <name>BS2</name>
            <bitOffset>2</bitOffset>
            <bitWidth>1</bitWidth>
          </field>
          <field>
            <name>BS3</name>
            <bitOffset>3</bitOffset>
            <bitWidth>1</bitWidth>
          </field>
          <field>
            <name>BS4</name>
            <bitOffset>4</bitOffset>
            <bitWidth>1</bitWidth>
          </field>
          <field>
            <name>BS5</name>
            <bitOffset>5</bitOffset>
            <bitWidth>1</bitWidth>
          </field>
          <field>
            <name>BS6</name>
            <bitOffset>6</bitOffset>
            <bitWidth>1</bitWidth>
          </field>
          <field>
            <name>BS7</name>
            <bitOffset>7</bitOffset>
            <bitWidth>1</bitWidth>
          </field>
          <field>
            <name>BS8</name>
            <bitOffset>8</bitOffset>
            <bitWidth>1</bitWidth>
          </field>
          <field>
            <name>BS9</name>
            <bitOffset>9</bitOffset>
            <bitWidth>1</bitWidth>
          </field>
          <field>
            <name>BS10</name>
            <bitOffset>10</bitOffset>
            <bitWidth>1</bitWidth>
          </field>
          <field>
            <name>BS11</name>
            <bitOffset>11</bitOffset>
            <bitWidth>1</bitWidth>
          </field>
          <field>
            <name>BS12</name>
            <bitOffset>12</bitOffset>
            <bitWidth>1</bitWidth>
          </field>
          <field>
            <name>BS13</name>
            <bitOffset>13</bitOffset>
            <bitWidth>1</bitWidth>
          </field>
          <field>
            <name>BS14</name>
            <bitOffset>14</bitOffset>
            <bitWidth>1</bitWidth>
          </field>
          <field>
            <name>BS15</name>
            <bitOffset>15</bitOffset>
            <bitWidth>1</bitWidth>
          </field>
          <field>
            <name>BR0</name>
            <bitOffset>16</bitOffset>
            <bitWidth>1</bitWidth>
          </field>
          <field>
            <name>BR1</name>
            <bitOffset>17</bitOffset>
            <bitWidth>1</bitWidth>
          </field>
          <field>
            <name>BR2</name>
            <bitOffset>18</bitOffset>
            <bitWidth>1</bitWidth>
          </field>
          <field>
            <name>BR3</name>
            <bitOffset>19</bitOffset>
            <bitWidth>1</bitWidth>
          </field>
          <field>
            <name>BR4</name>
            <bitOffset>20</bitOffset>
            <bitWidth>1</bitWidth>
          </field>
          <field>
            <name>BR5</name>
            <bitOffset>21</bitOffset>
            <bitWidth>1</bitWidth>
          </field>
          <field>
            <name>BR6</name>
            <bitOffset>22</bitOffset>
            <bitWidth>1</bitWidth>
          </field>
          <field>
            <name>BR7</name>
            <bitOffset>23</bitOffset>
            <bitWidth>1</bitWidth>
          </field>
          <field>
            <name>BR8</name>
            <bitOffset>24</bitOffset>
            <bitWidth>1</bitWidth>
          </field>
          <field>
            <name>BR9</name>
            <bitOffset>25</bitOffset>
            <bitWidth>1</bitWidth>
          </field>
          <field>
            <name>BR10</name>
            <bitOffset>26</bitOffset>
            <bitWidth>1</bitWidth>
          </field>
          <field>
            <name>BR11</name>
            <bitOffset>27</bitOffset>
            <bitWidth>1</bitWidth>
          </field>
          <field>
            <name>BR12</name>
            <bitOffset>28</bitOffset>
            <bitWidth>1</bitWidth>
          </field>
          <field>
            <name>BR13</name>
            <bitOffset>29</bitOffset>
            <bitWidth>1</bitWidth>
          </field>
          <field>
            <name>BR14</name>
            <bitOffset>30</bitOffset>
            <bitWidth>1</bitWidth>
          </field>
          <field>
            <name>BR15</name>
            <bitOffset>31</bitOffset>
            <bitWidth>1</bitWidth>
          </field>
        </fields>
      </register>
      <register>
        <name>BRR</name>
        <addressOffset>0x14</addressOffset>
        <size>0x20</size>
        <fields>
          <field>
            <name>BR0</name>
            <bitOffset>0</bitOffset>
            <bitWidth>1</bitWidth>
          </field>
          <field>
            <name>BR1</name>
            <bitOffset>1</bitOffset>
            <bitWidth>1</bitWidth>
          </field>
          <field>
            <name>BR2</name>
            <bitOffset>2</bitOffset>
            <bitWidth>1</bitWidth>
          </field>
          <field>
            <name>BR3</name>
            <bitOffset>3</bitOffset>
            <bitWidth>1</bitWidth>
          </field>
          <field>
            <name>BR4</name>
            <bitOffset>4</bitOffset>
            <bitWidth>1</bitWidth>
          </field>
          <field>
            <name>BR5</name>
            <bitOffset>5</bitOffset>
            <bitWidth>1</bitWidth>
          </field>
          <field>
            <name>BR6</name>
            <bitOffset>6</bitOffset>
            <bitWidth>1</bitWidth>
          </field>
          <field>
            <name>BR7</name>
            <bitOffset>7</bitOffset>
            <bitWidth>1</bitWidth>
          </field>
          <field>
            <name>BR8</name>
            <bitOffset>8</bitOffset>
            <bitWidth>1</bitWidth>
          </field>
          <field>
            <name>BR9</name>
            <bitOffset>9</bitOffset>
            <bitWidth>1</bitWidth>
          </field>
          <field>
            <name>BR10</name>
            <bitOffset>10</bitOffset>
            <bitWidth>1</bitWidth>
          </field>
          <field>
            <name>BR11</name>
            <bitOffset>11</bitOffset>
            <bitWidth>1</bitWidth>
          </field>
          <field>
            <name>BR12</name>
            <bitOffset>12</bitOffset>
            <bitWidth>1</bitWidth>
          </field>
          <field>
            <name>BR13</name>
            <bitOffset>13</bitOffset>
            <bitWidth>1</bitWidth>
          </field>
          <field>
            <name>BR14</name>
            <bitOffset>14</bitOffset>
            <bitWidth>1</bitWidth>
          </field>
          <field>
            <name>BR15</name>
            <bitOffset>15</bitOffset>
            <bitWidth>1</bitWidth>
          </field>
        </fields>
      </register>
      <register>
        <name>LCKR</name>
        <addressOffset>0x18</addressOffset>
        <size>0x20</size>
        <fields>
          <field>
            <name>LCK0</name>
            <bitOffset>0</bitOffset>
            <bitWidth>1</bitWidth>
          </field>
          <field>
            <name>LCK1</name>
            <bitOffset>1</bitOffset>
            <bitWidth>1</bitWidth>
          </field>
          <field>
            <name>LCK2</name>
            <bitOffset>2</bitOffset>
            <bitWidth>1</bitWidth>
          </field>
          <field>
            <name>LCK3</name>
            <bitOffset>3</bitOffset>
            <bitWidth>1</bitWidth>
          </field>
          <field>
            <name>LCK4</name>
            <bitOffset>4</bitOffset>
            <bitWidth>1</bitWidth>
          </field>
          <field>
            <name>LCK5</name>
            <bitOffset>5</bitOffset>
            <bitWidth>1</bitWidth>
          </field>
          <field>
            <name>LCK6</name>
            <bitOffset>6</bitOffset>
            <bitWidth>1</bitWidth>
          </field>
          <field>
            <name>LCK7</name>
            <bitOffset>7</bitOffset>
            <bitWidth>1</bitWidth>
          </field>
          <field>
            <name>LCK8</name>
            <bitOffset>8</bitOffset>
            <bitWidth>1</bitWidth>
          </field>
          <field>
            <name>LCK9</name>
            <bitOffset>9</bitOffset>
            <bitWidth>1</bitWidth>
          </field>
          <field>
            <name>LCK10</name>
            <bitOffset>10</bitOffset>
            <bitWidth>1</bitWidth>
          </field>
          <field>
            <name>LCK11</name>
            <bitOffset>11</bitOffset>
            <bitWidth>1</bitWidth>
          </field>
          <field>
            <name>LCK12</name>
            <bitOffset>12</bitOffset>
            <bitWidth>1</bitWidth>
          </field>
          <field>
            <name>LCK13</name>
            <bitOffset>13</bitOffset>
            <bitWidth>1</bitWidth>
          </field>
          <field>
            <name>LCK14</name>
            <bitOffset>14</bitOffset>
            <bitWidth>1</bitWidth>
          </field>
          <field>
            <name>LCK15</name>
            <bitOffset>15</bitOffset>
            <bitWidth>1</bitWidth>
          </field>
          <field>
            <name>LCKK</name>
            <bitOffset>16</bitOffset>
            <bitWidth>1</bitWidth>
          </field>
        </fields>
      </register>
    </peripheral>
    <peripheral>
      <name>GPIOB</name>
      <baseAddress>0x40010c00</baseAddress>
      <register>
        <name>CRL</name>
        <addressOffset>0x0</addressOffset>
        <size>0x20</size>
        <fields>
          <field>
            <name>MODE0</name>
            <bitOffset>0</bitOffset>
            <bitWidth>2</bitWidth>
          </field>
          <field>
            <name>CNF0</name>
            <bitOffset>2</bitOffset>
            <bitWidth>2</bitWidth>
          </field>
          <field>
            <name>MODE1</name>
            <bitOffset>4</bitOffset>
            <bitWidth>2</bitWidth>
          </field>
          <field>
            <name>CNF1</name>
            <bitOffset>6</bitOffset>
            <bitWidth>2</bitWidth>
          </field>
          <field>
            <name>MODE2</name>
            <bitOffset>8</bitOffset>
            <bitWidth>2</bitWidth>
          </field>
          <field>
            <name>CNF2</name>
            <bitOffset>10</bitOffset>
            <bitWidth>2</bitWidth>
          </field>
          <field>
            <name>MODE3</name>
            <bitOffset>12</bitOffset>
            <bitWidth>2</bitWidth>
          </field>
          <field>
            <name>CNF3</name>
            <bitOffset>14</bitOffset>
            <bitWidth>2</bitWidth>
          </field>
          <field>
            <name>MODE4</name>
            <bitOffset>16</bitOffset>
            <bitWidth>2</bitWidth>
          </field>
          <field>
            <name>CNF4</name>
            <bitOffset>18</bitOffset>
            <bitWidth>2</bitWidth>
          </field>
          <field>
            <name>MODE5</name>
            <bitOffset>20</bitOffset>
            <bitWidth>2</bitWidth>
          </field>
          <field>
            <name>CNF5</name>
            <bitOffset>22</bitOffset>
            <bitWidth>2</bitWidth>
          </field>
          <field>
            <name>MODE6</name>
            <bitOffset>24</bitOffset>
            <bitWidth>2</bitWidth>
          </field>
          <field>
            <name>CNF6</name>
            <bitOffset>26</bitOffset>
            <bitWidth>2</bitWidth>
          </field>
          <field>
            <name>MODE7</name>
            <bitOffset>28</bitOffset>
            <bitWidth>2</bitWidth>
          </field>
          <field>
            <name>CNF7</name>
            <bitOffset>30</bitOffset>
            <bitWidth>2</bitWidth>
          </field>
        </fields>
      </register>
      <register>
        <name>CRH</name>
        <addressOffset>0x4</addressOffset>
        <size>0x20</size>
        <fields>
          <field>
            <name>MODE8</name>
            <bitOffset>0</bitOffset>
            <bitWidth>2</bitWidth>
          </field>
          <field>
            <name>CNF8</name>
            <bitOffset>2</bitOffset>
            <bitWidth>2</bitWidth>
          </field>
          <field>
            <name>MODE9</name>
            <bitOffset>4</bitOffset>
            <bitWidth>2</bitWidth>
          </field>
          <field>
            <name>CNF9</name>
            <bitOffset>6</bitOffset>
            <bitWidth>2</bitWidth>
          </field>
          <field>
            <name>MODE10</name>
            <bitOffset>8</bitOffset>
            <bitWidth>2</bitWidth>
          </field>
          <field>
            <name>CNF10</name>
            <bitOffset>10</bitOffset>
            <bitWidth>2</bitWidth>
          </field>
          <field>
            <name>MODE11</name>
            <bitOffset>12</bitOffset>
            <bitWidth>2</bitWidth>
          </field>
          <field>
            <name>CNF11</name>
            <bitOffset>14</bitOffset>
            <bitWidth>2</bitWidth>
          </field>
          <field>
            <name>MODE12</name>
            <bitOffset>16</bitOffset>
            <bitWidth>2</bitWidth>
          </field>
          <field>
            <name>CNF12</name>
            <bitOffset>18</bitOffset>
            <bitWidth>2</bitWidth>
          </field>
          <field>
            <name>MODE13</name>
            <bitOffset>20</bitOffset>
            <bitWidth>2</bitWidth>
          </field>
          <field>
            <name>CNF13</name>
            <bitOffset>22</bitOffset>
            <bitWidth>2</bitWidth>
          </field>
          <field>
            <name>MODE14</name>
            <bitOffset>24</bitOffset>
            <bitWidth>2</bitWidth>
          </field>
          <field>
            <name>CNF14</name>
            <bitOffset>26</bitOffset>
            <bitWidth>2</bitWidth>
          </field>
          <field>
            <name>MODE15</name>
            <bitOffset>28</bitOffset>
            <bitWidth>2</bitWidth>
          </field>
          <field>
            <name>CNF15</name>
            <bitOffset>30</bitOffset>
            <bitWidth>2</bitWidth>
          </field>
        </fields>
      </register>
      <register>
        <name>IDR</name>
        <addressOffset>0x8</addressOffset>
        <size>0x20</size>
        <fields>
          <field>
            <name>IDR0</name>
            <bitOffset>0</bitOffset>
            <bitWidth>1</bitWidth>
          </field>
          <field>
            <name>IDR1</name>
            <bitOffset>1</bitOffset>
            <bitWidth>1</bitWidth>
          </field>
          <field>
            <name>IDR2</name>
            <bitOffset>2</bitOffset>
            <bitWidth>1</bitWidth>
          </field>
          <field>
            <name>IDR3</name>
            <bitOffset>3</bitOffset>
            <bitWidth>1</bitWidth>
          </field>
          <field>
            <name>IDR4</name>
            <bitOffset>4</bitOffset>
            <bitWidth>1</bitWidth>
          </field>
          <field>
            <name>IDR5</name>
            <bitOffset>5</bitOffset>
            <bitWidth>1</bitWidth>
          </field>
          <field>
            <name>IDR6</name>
            <bitOffset>6</bitOffset>
            <bitWidth>1</bitWidth>
          </field>
          <field>
            <name>IDR7</name>
            <bitOffset>7</bitOffset>
            <bitWidth>1</bitWidth>
          </field>
          <field>
            <name>IDR8</name>
            <bitOffset>8</bitOffset>
            <bitWidth>1</bitWidth>
          </field>
          <field>
            <name>IDR9</name>
            <bitOffset>9</bitOffset>
            <bitWidth>1</bitWidth>
          </field>
          <field>
            <name>IDR10</name>
            <bitOffset>10</bitOffset>
            <bitWidth>1</bitWidth>
          </field>
          <field>
            <name>IDR11</name>
            <bitOffset>11</bitOffset>
            <bitWidth>1</bitWidth>
          </field>
          <field>
            <name>IDR12</name>
            <bitOffset>12</bitOffset>
            <bitWidth>1</bitWidth>
          </field>
          <field>
            <name>IDR13</name>
            <bitOffset>13</bitOffset>
            <bitWidth>1</bitWidth>
          </field>
          <field>
            <name>IDR14</name>
            <bitOffset>14</bitOffset>
            <bitWidth>1</bitWidth>
          </field>
          <field>
            <name>IDR15</name>
            <bitOffset>15</bitOffset>
            <bitWidth>1</bitWidth>
          </field>
        </fields>
      </register>
      <register>
        <name>ODR</name>
        <addressOffset>0xc</addressOffset>
        <size>0x20</size>
        <fields>
          <field>
            <name>ODR0</name>
            <bitOffset>0</bitOffset>
            <bitWidth>1</bitWidth>
          </field>
          <field>
            <name>ODR1</name>
            <bitOffset>1</bitOffset>
            <bitWidth>1</bitWidth>
          </field>
          <field>
            <name>ODR2</name>
            <bitOffset>2</bitOffset>
            <bitWidth>1</bitWidth>
          </field>
          <field>
            <name>ODR3</name>
            <bitOffset>3</bitOffset>
            <bitWidth>1</bitWidth>
          </field>
          <field>
            <name>ODR4</name>
            <bitOffset>4</bitOffset>
            <bitWidth>1</bitWidth>
          </field>
          <field>
            <name>ODR5</name>
            <bitOffset>5</bitOffset>
            <bitWidth>1</bitWidth>
          </field>
          <field>
            <name>ODR6</name>
            <bitOffset>6</bitOffset>
            <bitWidth>1</bitWidth>
          </field>
          <field>
            <name>ODR7</name>
            <bitOffset>7</bitOffset>
            <bitWidth>1</bitWidth>
          </field>
          <field>
            <name>ODR8</name>
            <bitOffset>8</bitOffset>
            <bitWidth>1</bitWidth>
          </field>
          <field>
            <name>ODR9</name>
            <bitOffset>9</bitOffset>
            <bitWidth>1</bitWidth>
          </field>
          <field>
            <name>ODR10</name>
            <bitOffset>10</bitOffset>
            <bitWidth>1</bitWidth>
          </field>
          <field>
            <name>ODR11</name>
            <bitOffset>11</bitOffset>
            <bitWidth>1</bitWidth>
          </field>
          <field>
            <name>ODR12</name>
            <bitOffset>12</bitOffset>
            <bitWidth>1</bitWidth>
          </field>
          <field>
            <name>ODR13</name>
            <bitOffset>13</bitOffset>
            <bitWidth>1</bitWidth>
          </field>
          <field>
            <name>ODR14</name>
            <bitOffset>14</bitOffset>
            <bitWidth>1</bitWidth>
          </field>
          <field>
            <name>ODR15</name>
            <bitOffset>15</bitOffset>
            <bitWidth>1</bitWidth>
          </field>
        </fields>
      </register>
      <register>
        <name>BSRR</name>
        <addressOffset>0x10</addressOffset>
        <size>0x20</size>
        <fields>
          <field>
            <name>BS0</name>
            <bitOffset>0</bitOffset>
            <bitWidth>1</bitWidth>
          </field>
          <field>
            <name>BS1</name>
            <bitOffset>1</bitOffset>
            <bitWidth>1</bitWidth>
          </field>
          <field>
            <name>BS2</name>
            <bitOffset>2</bitOffset>
            <bitWidth>1</bitWidth>
          </field>
          <field>
            <name>BS3</name>
            <bitOffset>3</bitOffset>
            <bitWidth>1</bitWidth>
          </field>
          <field>
            <name>BS4</name>
            <bitOffset>4</bitOffset>
            <bitWidth>1</bitWidth>
          </field>
          <field>
            <name>BS5</name>
            <bitOffset>5</bitOffset>
            <bitWidth>1</bitWidth>
          </field>
          <field>
            <name>BS6</name>
            <bitOffset>6</bitOffset>
            <bitWidth>1</bitWidth>
          </field>
          <field>
            <name>BS7</name>
            <bitOffset>7</bitOffset>
            <bitWidth>1</bitWidth>
          </field>
          <field>
            <name>BS8</name>
            <bitOffset>8</bitOffset>
            <bitWidth>1</bitWidth>
          </field>
          <field>
            <name>BS9</name>
            <bitOffset>9</bitOffset>
            <bitWidth>1</bitWidth>
          </field>
          <field>
            <name>BS10</name>
            <bitOffset>10</bitOffset>
            <bitWidth>1</bitWidth>
          </field>
          <field>
            <name>BS11</name>
            <bitOffset>11</bitOffset>
            <bitWidth>1</bitWidth>
          </field>
          <field>
            <name>BS12</name>
            <bitOffset>12</bitOffset>
            <bitWidth>1</bitWidth>
          </field>
          <field>
            <name>BS13</name>
            <bitOffset>13</bitOffset>
            <bitWidth>1</bitWidth>
          </field>
          <field>
            <name>BS14</name>
            <bitOffset>14</bitOffset>
            <bitWidth>1</bitWidth>
          </field>
          <field>
            <name>BS15</name>
            <bitOffset>15</bitOffset>
            <bitWidth>1</bitWidth>
          </field>
          <field>
            <name>BR0</name>
            <bitOffset>16</bitOffset>
            <bitWidth>1</bitWidth>
          </field>
          <field>
            <name>BR1</name>
            <bitOffset>17</bitOffset>
            <bitWidth>1</bitWidth>
          </field>
          <field>
            <name>BR2</name>
            <bitOffset>18</bitOffset>
            <bitWidth>1</bitWidth>
          </field>
          <field>
            <name>BR3</name>
            <bitOffset>19</bitOffset>
            <bitWidth>1</bitWidth>
          </field>
          <field>
            <name>BR4</name>
            <bitOffset>20</bitOffset>
            <bitWidth>1</bitWidth>
          </field>
          <field>
            <name>BR5</name>
            <bitOffset>21</bitOffset>
            <bitWidth>1</bitWidth>
          </field>
          <field>
            <name>BR6</name>
            <bitOffset>22</bitOffset>
            <bitWidth>1</bitWidth>
          </field>
          <field>
            <name>BR7</name>
            <bitOffset>23</bitOffset>
            <bitWidth>1</bitWidth>
          </field>
          <field>
            <name>BR8</name>
            <bitOffset>24</bitOffset>
            <bitWidth>1</bitWidth>
          </field>
          <field>
            <name>BR9</name>
            <bitOffset>25</bitOffset>
            <bitWidth>1</bitWidth>
          </field>
          <field>
            <name>BR10</name>
            <bitOffset>26</bitOffset>
            <bitWidth>1</bitWidth>
          </field>
          <field>
            <name>BR11</name>
            <bitOffset>27</bitOffset>
            <bitWidth>1</bitWidth>
          </field>
          <field>
            <name>BR12</name>
            <bitOffset>28</bitOffset>
            <bitWidth>1</bitWidth>
          </field>
          <field>
            <name>BR13</name>
            <bitOffset>29</bitOffset>
            <bitWidth>1</bitWidth>
          </field>
          <field>
            <name>BR14</name>
            <bitOffset>30</bitOffset>
            <bitWidth>1</bitWidth>
          </field>
          <field>
            <name>BR15</name>
            <bitOffset>31</bitOffset>
            <bitWidth>1</bitWidth>
          </field>
        </fields>
      </register>
      <register>
        <name>BRR</name>
        <addressOffset>0x14</addressOffset>
        <size>0x20</size>
        <fields>
          <field>
            <name>BR0</name>
            <bitOffset>0</bitOffset>
            <bitWidth>1</bitWidth>
          </field>
          <field>
            <name>BR1</name>
            <bitOffset>1</bitOffset>
            <bitWidth>1</bitWidth>
          </field>
          <field>
            <name>BR2</name>
            <bitOffset>2</bitOffset>
            <bitWidth>1</bitWidth>
          </field>
          <field>
            <name>BR3</name>
            <bitOffset>3</bitOffset>
            <bitWidth>1</bitWidth>
          </field>
          <field>
            <name>BR4</name>
            <bitOffset>4</bitOffset>
            <bitWidth>1</bitWidth>
          </field>
          <field>
            <name>BR5</name>
            <bitOffset>5</bitOffset>
            <bitWidth>1</bitWidth>
          </field>
          <field>
            <name>BR6</name>
            <bitOffset>6</bitOffset>
            <bitWidth>1</bitWidth>
          </field>
          <field>
            <name>BR7</name>
            <bitOffset>7</bitOffset>
            <bitWidth>1</bitWidth>
          </field>
          <field>
            <name>BR8</name>
            <bitOffset>8</bitOffset>
            <bitWidth>1</bitWidth>
          </field>
          <field>
            <name>BR9</name>
            <bitOffset>9</bitOffset>
            <bitWidth>1</bitWidth>
          </field>
          <field>
            <name>BR10</name>
            <bitOffset>10</bitOffset>
            <bitWidth>1</bitWidth>
          </field>
          <field>
            <name>BR11</name>
            <bitOffset>11</bitOffset>
            <bitWidth>1</bitWidth>
          </field>
          <field>
            <name>BR12</name>
            <bitOffset>12</bitOffset>
            <bitWidth>1</bitWidth>
          </field>
          <field>
            <name>BR13</name>
            <bitOffset>13</bitOffset>
            <bitWidth>1</bitWidth>
          </field>
          <field>
            <name>BR14</name>
            <bitOffset>14</bitOffset>
            <bitWidth>1</bitWidth>
          </field>
          <field>
            <name>BR15</name>
            <bitOffset>15</bitOffset>
            <bitWidth>1</bitWidth>
          </field>
        </fields>
      </register>
      <register>
        <name>LCKR</name>
        <addressOffset>0x18</addressOffset>
        <size>0x20</size>
        <fields>
          <field>
            <name>LCK0</name>
            <bitOffset>0</bitOffset>
            <bitWidth>1</bitWidth>
          </field>
          <field>
            <name>LCK1</name>
            <bitOffset>1</bitOffset>
            <bitWidth>1</bitWidth>
          </field>
          <field>
            <name>LCK2</name>
            <bitOffset>2</bitOffset>
            <bitWidth>1</bitWidth>
          </field>
          <field>
            <name>LCK3</name>
            <bitOffset>3</bitOffset>
            <bitWidth>1</bitWidth>
          </field>
          <field>
            <name>LCK4</name>
            <bitOffset>4</bitOffset>
            <bitWidth>1</bitWidth>
          </field>
          <field>
            <name>LCK5</name>
            <bitOffset>5</bitOffset>
            <bitWidth>1</bitWidth>
          </field>
          <field>
            <name>LCK6</name>
            <bitOffset>6</bitOffset>
            <bitWidth>1</bitWidth>
          </field>
          <field>
            <name>LCK7</name>
            <bitOffset>7</bitOffset>
            <bitWidth>1</bitWidth>
          </field>
          <field>
            <name>LCK8</name>
            <bitOffset>8</bitOffset>
            <bitWidth>1</bitWidth>
          </field>
          <field>
            <name>LCK9</name>
            <bitOffset>9</bitOffset>
            <bitWidth>1</bitWidth>
          </field>
          <field>
            <name>LCK10</name>
            <bitOffset>10</bitOffset>
            <bitWidth>1</bitWidth>
          </field>
          <field>
            <name>LCK11</name>
            <bitOffset>11</bitOffset>
            <bitWidth>1</bitWidth>
          </field>
          <field>
            <name>LCK12</name>
            <bitOffset>12</bitOffset>
            <bitWidth>1</bitWidth>
          </field>
          <field>
            <name>LCK13</name>
            <bitOffset>13</bitOffset>
            <bitWidth>1</bitWidth>
          </field>
          <field>
            <name>LCK14</name>
            <bitOffset>14</bitOffset>
            <bitWidth>1</bitWidth>
          </field>
          <field>
            <name>LCK15</name>
            <bitOffset>15</bitOffset>
            <bitWidth>1</bitWidth>
          </field>
          <field>
            <name>LCKK</name>
            <bitOffset>16</bitOffset>
            <bitWidth>1</bitWidth>
          </field>
        </fields>
      </register>
    </peripheral>
    <peripheral>
      <name>GPIOC</name>
      <baseAddress>0x40011000</baseAddress>
      <register>
        <name>CRL</name>
        <addressOffset>0x0</addressOffset>
        <size>0x20</size>
        <fields>
          <field>
            <name>MODE0</name>
            <bitOffset>0</bitOffset>
            <bitWidth>2</bitWidth>
          </field>
          <field>
            <name>CNF0</name>
            <bitOffset>2</bitOffset>
            <bitWidth>2</bitWidth>
          </field>
          <field>
            <name>MODE1</name>
            <bitOffset>4</bitOffset>
            <bitWidth>2</bitWidth>
          </field>
          <field>
            <name>CNF1</name>
            <bitOffset>6</bitOffset>
            <bitWidth>2</bitWidth>
          </field>
          <field>
            <name>MODE2</name>
            <bitOffset>8</bitOffset>
            <bitWidth>2</bitWidth>
          </field>
          <field>
            <name>CNF2</name>
            <bitOffset>10</bitOffset>
            <bitWidth>2</bitWidth>
          </field>
          <field>
            <name>MODE3</name>
            <bitOffset>12</bitOffset>
            <bitWidth>2</bitWidth>
          </field>
          <field>
            <name>CNF3</name>
            <bitOffset>14</bitOffset>
            <bitWidth>2</bitWidth>
          </field>
          <field>
            <name>MODE4</name>
            <bitOffset>16</bitOffset>
            <bitWidth>2</bitWidth>
          </field>
          <field>
            <name>CNF4</name>
            <bitOffset>18</bitOffset>
            <bitWidth>2</bitWidth>
          </field>
          <field>
            <name>MODE5</name>
            <bitOffset>20</bitOffset>
            <bitWidth>2</bitWidth>
          </field>
          <field>
            <name>CNF5</name>
            <bitOffset>22</bitOffset>
            <bitWidth>2</bitWidth>
          </field>
          <field>
            <name>MODE6</name>
            <bitOffset>24</bitOffset>
            <bitWidth>2</bitWidth>
          </field>
          <field>
            <name>CNF6</name>
            <bitOffset>26</bitOffset>
            <bitWidth>2</bitWidth>
          </field>
          <field>
            <name>MODE7</name>
            <bitOffset>28</bitOffset>
            <bitWidth>2</bitWidth>
          </field>
          <field>
            <name>CNF7</name>
            <bitOffset>30</bitOffset>
            <bitWidth>2</bitWidth>
          </field>
        </fields>
      </register>
      <register>
        <name>CRH</name>
        <addressOffset>0x4</addressOffset>
        <size>0x20</size>
        <fields>
          <field>
            <name>MODE8</name>
            <bitOffset>0</bitOffset>
            <bitWidth>2</bitWidth>
          </field>
          <field>
            <name>CNF8</name>
            <bitOffset>2</bitOffset>
            <bitWidth>2</bitWidth>
          </field>
          <field>
            <name>MODE9</name>
            <bitOffset>4</bitOffset>
            <bitWidth>2</bitWidth>
          </field>
          <field>
            <name>CNF9</name>
            <bitOffset>6</bitOffset>
            <bitWidth>2</bitWidth>
          </field>
          <field>
            <name>MODE10</name>
            <bitOffset>8</bitOffset>
            <bitWidth>2</bitWidth>
          </field>
          <field>
            <name>CNF10</name>
            <bitOffset>10</bitOffset>
            <bitWidth>2</bitWidth>
          </field>
          <field>
            <name>MODE11</name>
            <bitOffset>12</bitOffset>
            <bitWidth>2</bitWidth>
          </field>
          <field>
            <name>CNF11</name>
            <bitOffset>14</bitOffset>
            <bitWidth>2</bitWidth>
          </field>
          <field>
            <name>MODE12</name>
            <bitOffset>16</bitOffset>
            <bitWidth>2</bitWidth>
          </field>
          <field>
            <name>CNF12</name>
            <bitOffset>18</bitOffset>
            <bitWidth>2</bitWidth>
          </field>
          <field>
            <name>MODE13</name>
            <bitOffset>20</bitOffset>
            <bitWidth>2</bitWidth>
          </field>
          <field>
            <name>CNF13</name>
            <bitOffset>22</bitOffset>
            <bitWidth>2</bitWidth>
          </field>
          <field>
            <name>MODE14</name>
            <bitOffset>24</bitOffset>
            <bitWidth>2</bitWidth>
          </field>
          <field>
            <name>CNF14</name>
            <bitOffset>26</bitOffset>
            <bitWidth>2</bitWidth>
          </field>
          <field>
            <name>MODE15</name>
            <bitOffset>28</bitOffset>
            <bitWidth>2</bitWidth>
          </field>
          <field>
            <name>CNF15</name>
            <bitOffset>30</bitOffset>
            <bitWidth>2</bitWidth>
          </field>
        </fields>
      </register>
      <register>
        <name>IDR</name>
        <addressOffset>0x8</addressOffset>
        <size>0x20</size>
        <fields>
          <field>
            <name>IDR0</name>
            <bitOffset>0</bitOffset>
            <bitWidth>1</bitWidth>
          </field>
          <field>
            <name>IDR1</name>
            <bitOffset>1</bitOffset>
            <bitWidth>1</bitWidth>
          </field>
          <field>
            <name>IDR2</name>
            <bitOffset>2</bitOffset>
            <bitWidth>1</bitWidth>
          </field>
          <field>
            <name>IDR3</name>
            <bitOffset>3</bitOffset>
            <bitWidth>1</bitWidth>
          </field>
          <field>
            <name>IDR4</name>
            <bitOffset>4</bitOffset>
            <bitWidth>1</bitWidth>
          </field>
          <field>
            <name>IDR5</name>
            <bitOffset>5</bitOffset>
            <bitWidth>1</bitWidth>
          </field>
          <field>
            <name>IDR6</name>
            <bitOffset>6</bitOffset>
            <bitWidth>1</bitWidth>
          </field>
          <field>
            <name>IDR7</name>
            <bitOffset>7</bitOffset>
            <bitWidth>1</bitWidth>
          </field>
          <field>
            <name>IDR8</name>
            <bitOffset>8</bitOffset>
            <bitWidth>1</bitWidth>
          </field>
          <field>
            <name>IDR9</name>
            <bitOffset>9</bitOffset>
            <bitWidth>1</bitWidth>
          </field>
          <field>
            <name>IDR10</name>
            <bitOffset>10</bitOffset>
            <bitWidth>1</bitWidth>
          </field>
          <field>
            <name>IDR11</name>
            <bitOffset>11</bitOffset>
            <bitWidth>1</bitWidth>
          </field>
          <field>
            <name>IDR12</name>
            <bitOffset>12</bitOffset>
            <bitWidth>1</bitWidth>
          </field>
          <field>
            <name>IDR13</name>
            <bitOffset>13</bitOffset>
            <bitWidth>1</bitWidth>
          </field>
          <field>
            <name>IDR14</name>
            <bitOffset>14</bitOffset>
            <bitWidth>1</bitWidth>
          </field>
          <field>
            <name>IDR15</name>
            <bitOffset>15</bitOffset>
            <bitWidth>1</bitWidth>
          </field>
        </fields>
      </register>
      <register>
        <name>ODR</name>
        <addressOffset>0xc</addressOffset>
        <size>0x20</size>
        <fields>
          <field>
            <name>ODR0</name>
            <bitOffset>0</bitOffset>
            <bitWidth>1</bitWidth>
          </field>
          <field>
            <name>ODR1</name>
            <bitOffset>1</bitOffset>
            <bitWidth>1</bitWidth>
          </field>
          <field>
            <name>ODR2</name>
            <bitOffset>2</bitOffset>
            <bitWidth>1</bitWidth>
          </field>
          <field>
            <name>ODR3</name>
            <bitOffset>3</bitOffset>
            <bitWidth>1</bitWidth>
          </field>
          <field>
            <name>ODR4</name>
            <bitOffset>4</bitOffset>
            <bitWidth>1</bitWidth>
          </field>
          <field>
            <name>ODR5</name>
            <bitOffset>5</bitOffset>
            <bitWidth>1</bitWidth>
          </field>
          <field>
            <name>ODR6</name>
            <bitOffset>6</bitOffset>
            <bitWidth>1</bitWidth>
          </field>
          <field>
            <name>ODR7</name>
            <bitOffset>7</bitOffset>
            <bitWidth>1</bitWidth>
          </field>
          <field>
            <name>ODR8</name>
            <bitOffset>8</bitOffset>
            <bitWidth>1</bitWidth>
          </field>
          <field>
            <name>ODR9</name>
            <bitOffset>9</bitOffset>
            <bitWidth>1</bitWidth>
          </field>
          <field>
            <name>ODR10</name>
            <bitOffset>10</bitOffset>
            <bitWidth>1</bitWidth>
          </field>
          <field>
            <name>ODR11</name>
            <bitOffset>11</bitOffset>
            <bitWidth>1</bitWidth>
          </field>
          <field>
            <name>ODR12</name>
            <bitOffset>12</bitOffset>
            <bitWidth>1</bitWidth>
          </field>
          <field>
            <name>ODR13</name>
            <bitOffset>13</bitOffset>
            <bitWidth>1</bitWidth>
          </field>
          <field>
            <name>ODR14</name>
            <bitOffset>14</bitOffset>
            <bitWidth>1</bitWidth>
          </field>
          <field>
            <name>ODR15</name>
            <bitOffset>15</bitOffset>
            <bitWidth>1</bitWidth>
          </field>
        </fields>
      </register>
      <register>
        <name>BSRR</name>
        <addressOffset>0x10</addressOffset>
        <size>0x20</size>
        <fields>
          <field>
            <name>BS0</name>
            <bitOffset>0</bitOffset>
            <bitWidth>1</bitWidth>
          </field>
          <field>
            <name>BS1</name>
            <bitOffset>1</bitOffset>
            <bitWidth>1</bitWidth>
          </field>
          <field>
            <name>BS2</name>
            <bitOffset>2</bitOffset>
            <bitWidth>1</bitWidth>
          </field>
          <field>
            <name>BS3</name>
            <bitOffset>3</bitOffset>
            <bitWidth>1</bitWidth>
          </field>
          <field>
            <name>BS4</name>
            <bitOffset>4</bitOffset>
            <bitWidth>1</bitWidth>
          </field>
          <field>
            <name>BS5</name>
            <bitOffset>5</bitOffset>
            <bitWidth>1</bitWidth>
          </field>
          <field>
            <name>BS6</name>
            <bitOffset>6</bitOffset>
            <bitWidth>1</bitWidth>
          </field>
          <field>
            <name>BS7</name>
            <bitOffset>7</bitOffset>
            <bitWidth>1</bitWidth>
          </field>
          <field>
            <name>BS8</name>
            <bitOffset>8</bitOffset>
            <bitWidth>1</bitWidth>
          </field>
          <field>
            <name>BS9</name>
            <bitOffset>9</bitOffset>
            <bitWidth>1</bitWidth>
          </field>
          <field>
            <name>BS10</name>
            <bitOffset>10</bitOffset>
            <bitWidth>1</bitWidth>
          </field>
          <field>
            <name>BS11</name>
            <bitOffset>11</bitOffset>
            <bitWidth>1</bitWidth>
          </field>
          <field>
            <name>BS12</name>
            <bitOffset>12</bitOffset>
            <bitWidth>1</bitWidth>
          </field>
          <field>
            <name>BS13</name>
            <bitOffset>13</bitOffset>
            <bitWidth>1</bitWidth>
          </field>
          <field>
            <name>BS14</name>
            <bitOffset>14</bitOffset>
            <bitWidth>1</bitWidth>
          </field>
          <field>
            <name>BS15</name>
            <bitOffset>15</bitOffset>
            <bitWidth>1</bitWidth>
          </field>
          <field>
            <name>BR0</name>
            <bitOffset>16</bitOffset>
            <bitWidth>1</bitWidth>
          </field>
          <field>
            <name>BR1</name>
            <bitOffset>17</bitOffset>
            <bitWidth>1</bitWidth>
          </field>
          <field>
            <name>BR2</name>
            <bitOffset>18</bitOffset>
            <bitWidth>1</bitWidth>
          </field>
          <field>
            <name>BR3</name>
            <bitOffset>19</bitOffset>
            <bitWidth>1</bitWidth>
          </field>
          <field>
            <name>BR4</name>
            <bitOffset>20</bitOffset>
            <bitWidth>1</bitWidth>
          </field>
          <field>
            <name>BR5</name>
            <bitOffset>21</bitOffset>
            <bitWidth>1</bitWidth>
          </field>
          <field>
            <name>BR6</name>
            <bitOffset>22</bitOffset>
            <bitWidth>1</bitWidth>
          </field>
          <field>
            <name>BR7</name>
            <bitOffset>23</bitOffset>
            <bitWidth>1</bitWidth>
          </field>
          <field>
            <name>BR8</name>
            <bitOffset>24</bitOffset>
            <bitWidth>1</bitWidth>
          </field>
          <field>
            <name>BR9</name>
            <bitOffset>25</bitOffset>
            <bitWidth>1</bitWidth>
          </field>
          <field>
            <name>BR10</name>
            <bitOffset>26</bitOffset>
            <bitWidth>1</bitWidth>
          </field>
          <field>
            <name>BR11</name>
            <bitOffset>27</bitOffset>
            <bitWidth>1</bitWidth>
          </field>
          <field>
            <name>BR12</name>
            <bitOffset>28</bitOffset>
            <bitWidth>1</bitWidth>
          </field>
          <field>
            <name>BR13</name>
            <bitOffset>29</bitOffset>
            <bitWidth>1</bitWidth>
          </field>
          <field>
            <name>BR14</name>
            <bitOffset>30</bitOffset>
            <bitWidth>1</bitWidth>
          </field>
          <field>
            <name>BR15</name>
            <bitOffset>31</bitOffset>
            <bitWidth>1</bitWidth>
          </field>
        </fields>
      </register>
      <register>
        <name>BRR</name>
        <addressOffset>0x14</addressOffset>
        <size>0x20</size>
        <fields>
          <field>
            <name>BR0</name>
            <bitOffset>0</bitOffset>
            <bitWidth>1</bitWidth>
          </field>
          <field>
            <name>BR1</name>
            <bitOffset>1</bitOffset>
            <bitWidth>1</bitWidth>
          </field>
          <field>
            <name>BR2</name>
            <bitOffset>2</bitOffset>
            <bitWidth>1</bitWidth>
          </field>
          <field>
            <name>BR3</name>
            <bitOffset>3</bitOffset>
            <bitWidth>1</bitWidth>
          </field>
          <field>
            <name>BR4</name>
            <bitOffset>4</bitOffset>
            <bitWidth>1</bitWidth>
          </field>
          <field>
            <name>BR5</name>
            <bitOffset>5</bitOffset>
            <bitWidth>1</bitWidth>
          </field>
          <field>
            <name>BR6</name>
            <bitOffset>6</bitOffset>
            <bitWidth>1</bitWidth>
          </field>
          <field>
            <name>BR7</name>
            <bitOffset>7</bitOffset>
            <bitWidth>1</bitWidth>
          </field>
          <field>
            <name>BR8</name>
            <bitOffset>8</bitOffset>
            <bitWidth>1</bitWidth>
          </field>
          <field>
            <name>BR9</name>
            <bitOffset>9</bitOffset>
            <bitWidth>1</bitWidth>
          </field>
          <field>
            <name>BR10</name>
            <bitOffset>10</bitOffset>
            <bitWidth>1</bitWidth>
          </field>
          <field>
            <name>BR11</name>
            <bitOffset>11</bitOffset>
            <bitWidth>1</bitWidth>
          </field>
          <field>
            <name>BR12</name>
            <bitOffset>12</bitOffset>
            <bitWidth>1</bitWidth>
          </field>
          <field>
            <name>BR13</name>
            <bitOffset>13</bitOffset>
            <bitWidth>1</bitWidth>
          </field>
          <field>
            <name>BR14</name>
            <bitOffset>14</bitOffset>
            <bitWidth>1</bitWidth>
          </field>
          <field>
            <name>BR15</name>
            <bitOffset>15</bitOffset>
            <bitWidth>1</bitWidth>
          </field>
        </fields>
      </register>
      <register>
        <name>LCKR</name>
        <addressOffset>0x18</addressOffset>
        <size>0x20</size>
        <fields>
          <field>
            <name>LCK0</name>
            <bitOffset>0</bitOffset>
            <bitWidth>1</bitWidth>
          </field>
          <field>
            <name>LCK1</name>
            <bitOffset>1</bitOffset>
            <bitWidth>1</bitWidth>
          </field>
          <field>
            <name>LCK2</name>
            <bitOffset>2</bitOffset>
            <bitWidth>1</bitWidth>
          </field>
          <field>
            <name>LCK3</name>
            <bitOffset>3</bitOffset>
            <bitWidth>1</bitWidth>
          </field>
          <field>
            <name>LCK4</name>
            <bitOffset>4</bitOffset>
            <bitWidth>1</bitWidth>
          </field>
          <field>
            <name>LCK5</name>
            <bitOffset>5</bitOffset>
            <bitWidth>1</bitWidth>
          </field>
          <field>
            <name>LCK6</name>
            <bitOffset>6</bitOffset>
            <bitWidth>1</bitWidth>
          </field>
          <field>
            <name>LCK7</name>
            <bitOffset>7</bitOffset>
            <bitWidth>1</bitWidth>
          </field>
          <field>
            <name>LCK8</name>
            <bitOffset>8</bitOffset>
            <bitWidth>1</bitWidth>
          </field>
          <field>
            <name>LCK9</name>
            <bitOffset>9</bitOffset>
            <bitWidth>1</bitWidth>
          </field>
          <field>
            <name>LCK10</name>
            <bitOffset>10</bitOffset>
            <bitWidth>1</bitWidth>
          </field>
          <field>
            <name>LCK11</name>
            <bitOffset>11</bitOffset>
            <bitWidth>1</bitWidth>
          </field>
          <field>
            <name>LCK12</name>
            <bitOffset>12</bitOffset>
            <bitWidth>1</bitWidth>
          </field>
          <field>
            <name>LCK13</name>
            <bitOffset>13</bitOffset>
            <bitWidth>1</bitWidth>
          </field>
          <field>
            <name>LCK14</name>
            <bitOffset>14</bitOffset>
            <bitWidth>1</bitWidth>
          </field>
          <field>
            <name>LCK15</name>
            <bitOffset>15</bitOffset>
            <bitWidth>1</bitWidth>
          </field>
          <field>
            <name>LCKK</name>
            <bitOffset>16</bitOffset>
            <bitWidth>1</bitWidth>
          </field>
        </fields>
      </register>
    </peripheral>
    <peripheral>
      <name>GPIOD</name>
      <baseAddress>0x40011400</baseAddress>
      <register>
        <name>CRL</name>
        <addressOffset>0x0</addressOffset>
        <size>0x20</size>
        <fields>
          <field>
            <name>MODE0</name>
            <bitOffset>0</bitOffset>
            <bitWidth>2</bitWidth>
          </field>
          <field>
            <name>CNF0</name>
            <bitOffset>2</bitOffset>
            <bitWidth>2</bitWidth>
          </field>
          <field>
            <name>MODE1</name>
            <bitOffset>4</bitOffset>
            <bitWidth>2</bitWidth>
          </field>
          <field>
            <name>CNF1</name>
            <bitOffset>6</bitOffset>
            <bitWidth>2</bitWidth>
          </field>
          <field>
            <name>MODE2</name>
            <bitOffset>8</bitOffset>
            <bitWidth>2</bitWidth>
          </field>
          <field>
            <name>CNF2</name>
            <bitOffset>10</bitOffset>
            <bitWidth>2</bitWidth>
          </field>
          <field>
            <name>MODE3</name>
            <bitOffset>12</bitOffset>
            <bitWidth>2</bitWidth>
          </field>
          <field>
            <name>CNF3</name>
            <bitOffset>14</bitOffset>
            <bitWidth>2</bitWidth>
          </field>
          <field>
            <name>MODE4</name>
            <bitOffset>16</bitOffset>
            <bitWidth>2</bitWidth>
          </field>
          <field>
            <name>CNF4</name>
            <bitOffset>18</bitOffset>
            <bitWidth>2</bitWidth>
          </field>
          <field>
            <name>MODE5</name>
            <bitOffset>20</bitOffset>
            <bitWidth>2</bitWidth>
          </field>
          <field>
            <name>CNF5</name>
            <bitOffset>22</bitOffset>
            <bitWidth>2</bitWidth>
          </field>
          <field>
            <name>MODE6</name>
            <bitOffset>24</bitOffset>
            <bitWidth>2</bitWidth>
          </field>
          <field>
            <name>CNF6</name>
            <bitOffset>26</bitOffset>
            <bitWidth>2</bitWidth>
          </field>
          <field>
            <name>MODE7</name>
            <bitOffset>28</bitOffset>
            <bitWidth>2</bitWidth>
          </field>
          <field>
            <name>CNF7</name>
            <bitOffset>30</bitOffset>
            <bitWidth>2</bitWidth>
          </field>
        </fields>
      </register>
      <register>
        <name>CRH</name>
        <addressOffset>0x4</addressOffset>
        <size>0x20</size>
        <fields>
          <field>
            <name>MODE8</name>
            <bitOffset>0</bitOffset>
            <bitWidth>2</bitWidth>
          </field>
          <field>
            <name>CNF8</name>
            <bitOffset>2</bitOffset>
            <bitWidth>2</bitWidth>
          </field>
          <field>
            <name>MODE9</name>
            <bitOffset>4</bitOffset>
            <bitWidth>2</bitWidth>
          </field>
          <field>
            <name>CNF9</name>
            <bitOffset>6</bitOffset>
            <bitWidth>2</bitWidth>
          </field>
          <field>
            <name>MODE10</name>
            <bitOffset>8</bitOffset>
            <bitWidth>2</bitWidth>
          </field>
          <field>
            <name>CNF10</name>
            <bitOffset>10</bitOffset>
            <bitWidth>2</bitWidth>
          </field>
          <field>
            <name>MODE11</name>
            <bitOffset>12</bitOffset>
            <bitWidth>2</bitWidth>
          </field>
          <field>
            <name>CNF11</name>
            <bitOffset>14</bitOffset>
            <bitWidth>2</bitWidth>
          </field>
          <field>
            <name>MODE12</name>
            <bitOffset>16</bitOffset>
            <bitWidth>2</bitWidth>
          </field>
          <field>
            <name>CNF12</name>
            <bitOffset>18</bitOffset>
            <bitWidth>2</bitWidth>
          </field>
          <field>
            <name>MODE13</name>
            <bitOffset>20</bitOffset>
            <bitWidth>2</bitWidth>
          </field>
          <field>
            <name>CNF13</name>
            <bitOffset>22</bitOffset>
            <bitWidth>2</bitWidth>
          </field>
          <field>
            <name>MODE14</name>
            <bitOffset>24</bitOffset>
            <bitWidth>2</bitWidth>
          </field>
          <field>
            <name>CNF14</name>
            <bitOffset>26</bitOffset>
            <bitWidth>2</bitWidth>
          </field>
          <field>
            <name>MODE15</name>
            <bitOffset>28</bitOffset>
            <bitWidth>2</bitWidth>
          </field>
          <field>
            <name>CNF15</name>
            <bitOffset>30</bitOffset>
            <bitWidth>2</bitWidth>
          </field>
        </fields>
      </register>
      <register>
        <name>IDR</name>
        <addressOffset>0x8</addressOffset>
        <size>0x20</size>
        <fields>
          <field>
            <name>IDR0</name>
            <bitOffset>0</bitOffset>
            <bitWidth>1</bitWidth>
          </field>
          <field>
            <name>IDR1</name>
            <bitOffset>1</bitOffset>
            <bitWidth>1</bitWidth>
          </field>
          <field>
            <name>IDR2</name>
            <bitOffset>2</bitOffset>
            <bitWidth>1</bitWidth>
          </field>
          <field>
            <name>IDR3</name>
            <bitOffset>3</bitOffset>
            <bitWidth>1</bitWidth>
          </field>
          <field>
            <name>IDR4</name>
            <bitOffset>4</bitOffset>
            <bitWidth>1</bitWidth>
          </field>
          <field>
            <name>IDR5</name>
            <bitOffset>5</bitOffset>
            <bitWidth>1</bitWidth>
          </field>
          <field>
            <name>IDR6</name>
            <bitOffset>6</bitOffset>
            <bitWidth>1</bitWidth>
          </field>
          <field>
            <name>IDR7</name>
            <bitOffset>7</bitOffset>
            <bitWidth>1</bitWidth>
          </field>
          <field>
            <name>IDR8</name>
            <bitOffset>8</bitOffset>
            <bitWidth>1</bitWidth>
          </field>
          <field>
            <name>IDR9</name>
            <bitOffset>9</bitOffset>
            <bitWidth>1</bitWidth>
          </field>
          <field>
            <name>IDR10</name>
            <bitOffset>10</bitOffset>
            <bitWidth>1</bitWidth>
          </field>
          <field>
            <name>IDR11</name>
            <bitOffset>11</bitOffset>
            <bitWidth>1</bitWidth>
          </field>
          <field>
            <name>IDR12</name>
            <bitOffset>12</bitOffset>
            <bitWidth>1</bitWidth>
          </field>
          <field>
            <name>IDR13</name>
            <bitOffset>13</bitOffset>
            <bitWidth>1</bitWidth>
          </field>
          <field>
            <name>IDR14</name>
            <bitOffset>14</bitOffset>
            <bitWidth>1</bitWidth>
          </field>
          <field>
            <name>IDR15</name>
            <bitOffset>15</bitOffset>
            <bitWidth>1</bitWidth>
          </field>
        </fields>
      </register>
      <register>
        <name>ODR</name>
        <addressOffset>0xc</addressOffset>
        <size>0x20</size>
        <fields>
          <field>
            <name>ODR0</name>
            <bitOffset>0</bitOffset>
            <bitWidth>1</bitWidth>
          </field>
          <field>
            <name>ODR1</name>
            <bitOffset>1</bitOffset>
            <bitWidth>1</bitWidth>
          </field>
          <field>
            <name>ODR2</name>
            <bitOffset>2</bitOffset>
            <bitWidth>1</bitWidth>
          </field>
          <field>
            <name>ODR3</name>
            <bitOffset>3</bitOffset>
            <bitWidth>1</bitWidth>
          </field>
          <field>
            <name>ODR4</name>
            <bitOffset>4</bitOffset>
            <bitWidth>1</bitWidth>
          </field>
          <field>
            <name>ODR5</name>
            <bitOffset>5</bitOffset>
            <bitWidth>1</bitWidth>
          </field>
          <field>
            <name>ODR6</name>
            <bitOffset>6</bitOffset>
            <bitWidth>1</bitWidth>
          </field>
          <field>
            <name>ODR7</name>
            <bitOffset>7</bitOffset>
            <bitWidth>1</bitWidth>
          </field>
          <field>
            <name>ODR8</name>
            <bitOffset>8</bitOffset>
            <bitWidth>1</bitWidth>
          </field>
          <field>
            <name>ODR9</name>
            <bitOffset>9</bitOffset>
            <bitWidth>1</bitWidth>
          </field>
          <field>
            <name>ODR10</name>
            <bitOffset>10</bitOffset>
            <bitWidth>1</bitWidth>
          </field>
          <field>
            <name>ODR11</name>
            <bitOffset>11</bitOffset>
            <bitWidth>1</bitWidth>
          </field>
          <field>
            <name>ODR12</name>
            <bitOffset>12</bitOffset>
            <bitWidth>1</bitWidth>
          </field>
          <field>
            <name>ODR13</name>
            <bitOffset>13</bitOffset>
            <bitWidth>1</bitWidth>
          </field>
          <field>
            <name>ODR14</name>
            <bitOffset>14</bitOffset>
            <bitWidth>1</bitWidth>
          </field>
          <field>
            <name>ODR15</name>
            <bitOffset>15</bitOffset>
            <bitWidth>1</bitWidth>
          </field>
        </fields>
      </register>
      <register>
        <name>BSRR</name>
        <addressOffset>0x10</addressOffset>
        <size>0x20</size>
        <fields>
          <field>
            <name>BS0</name>
            <bitOffset>0</bitOffset>
            <bitWidth>1</bitWidth>
          </field>
          <field>
            <name>BS1</name>
            <bitOffset>1</bitOffset>
            <bitWidth>1</bitWidth>
          </field>
          <field>
            <name>BS2</name>
            <bitOffset>2</bitOffset>
            <bitWidth>1</bitWidth>
          </field>
          <field>
            <name>BS3</name>
            <bitOffset>3</bitOffset>
            <bitWidth>1</bitWidth>
          </field>
          <field>
            <name>BS4</name>
            <bitOffset>4</bitOffset>
            <bitWidth>1</bitWidth>
          </field>
          <field>
            <name>BS5</name>
            <bitOffset>5</bitOffset>
            <bitWidth>1</bitWidth>
          </field>
          <field>
            <name>BS6</name>
            <bitOffset>6</bitOffset>
            <bitWidth>1</bitWidth>
          </field>
          <field>
            <name>BS7</name>
            <bitOffset>7</bitOffset>
            <bitWidth>1</bitWidth>
          </field>
          <field>
            <name>BS8</name>
            <bitOffset>8</bitOffset>
            <bitWidth>1</bitWidth>
          </field>
          <field>
            <name>BS9</name>
            <bitOffset>9</bitOffset>
            <bitWidth>1</bitWidth>
          </field>
          <field>
            <name>BS10</name>
            <bitOffset>10</bitOffset>
            <bitWidth>1</bitWidth>
          </field>
          <field>
            <name>BS11</name>
            <bitOffset>11</bitOffset>
            <bitWidth>1</bitWidth>
          </field>
          <field>
            <name>BS12</name>
            <bitOffset>12</bitOffset>
            <bitWidth>1</bitWidth>
          </field>
          <field>
            <name>BS13</name>
            <bitOffset>13</bitOffset>
            <bitWidth>1</bitWidth>
          </field>
          <field>
            <name>BS14</name>
            <bitOffset>14</bitOffset>
            <bitWidth>1</bitWidth>
          </field>
          <field>
            <name>BS15</name>
            <bitOffset>15</bitOffset>
            <bitWidth>1</bitWidth>
          </field>
          <field>
            <name>BR0</name>
            <bitOffset>16</bitOffset>
            <bitWidth>1</bitWidth>
          </field>
          <field>
            <name>BR1</name>
            <bitOffset>17</bitOffset>
            <bitWidth>1</bitWidth>
          </field>
          <field>
            <name>BR2</name>
            <bitOffset>18</bitOffset>
            <bitWidth>1</bitWidth>
          </field>
          <field>
            <name>BR3</name>
            <bitOffset>19</bitOffset>
            <bitWidth>1</bitWidth>
          </field>
          <field>
            <name>BR4</name>
            <bitOffset>20</bitOffset>
            <bitWidth>1</bitWidth>
          </field>
          <field>
            <name>BR5</name>
            <bitOffset>21</bitOffset>
            <bitWidth>1</bitWidth>
          </field>
          <field>
            <name>BR6</name>
            <bitOffset>22</bitOffset>
            <bitWidth>1</bitWidth>
          </field>
          <field>
            <name>BR7</name>
            <bitOffset>23</bitOffset>
            <bitWidth>1</bitWidth>
          </field>
          <field>
            <name>BR8</name>
            <bitOffset>24</bitOffset>
            <bitWidth>1</bitWidth>
          </field>
          <field>
            <name>BR9</name>
            <bitOffset>25</bitOffset>
            <bitWidth>1</bitWidth>
          </field>
          <field>
            <name>BR10</name>
            <bitOffset>26</bitOffset>
            <bitWidth>1</bitWidth>
          </field>
          <field>
            <name>BR11</name>
            <bitOffset>27</bitOffset>
            <bitWidth>1</bitWidth>
          </field>
          <field>
            <name>BR12</name>
            <bitOffset>28</bitOffset>
            <bitWidth>1</bitWidth>
          </field>
          <field>
            <name>BR13</name>
            <bitOffset>29</bitOffset>
            <bitWidth>1</bitWidth>
          </field>
          <field>
            <name>BR14</name>
            <bitOffset>30</bitOffset>
            <bitWidth>1</bitWidth>
          </field>
          <field>
            <name>BR15</name>
            <bitOffset>31</bitOffset>
            <bitWidth>1</bitWidth>
          </field>
        </fields>
      </register>
      <register>
        <name>BRR</name>
        <addressOffset>0x14</addressOffset>
        <size>0x20</size>
        <fields>
          <field>
            <name>BR0</name>
            <bitOffset>0</bitOffset>
            <bitWidth>1</bitWidth>
          </field>
          <field>
            <name>BR1</name>
            <bitOffset>1</bitOffset>
            <bitWidth>1</bitWidth>
          </field>
          <field>
            <name>BR2</name>
            <bitOffset>2</bitOffset>
            <bitWidth>1</bitWidth>
          </field>
          <field>
            <name>BR3</name>
            <bitOffset>3</bitOffset>
            <bitWidth>1</bitWidth>
          </field>
          <field>
            <name>BR4</name>
            <bitOffset>4</bitOffset>
            <bitWidth>1</bitWidth>
          </field>
          <field>
            <name>BR5</name>
            <bitOffset>5</bitOffset>
            <bitWidth>1</bitWidth>
          </field>
          <field>
            <name>BR6</name>
            <bitOffset>6</bitOffset>
            <bitWidth>1</bitWidth>
          </field>
          <field>
            <name>BR7</name>
            <bitOffset>7</bitOffset>
            <bitWidth>1</bitWidth>
          </field>
          <field>
            <name>BR8</name>
            <bitOffset>8</bitOffset>
            <bitWidth>1</bitWidth>
          </field>
          <field>
            <name>BR9</name>
            <bitOffset>9</bitOffset>
            <bitWidth>1</bitWidth>
          </field>
          <field>
            <name>BR10</name>
            <bitOffset>10</bitOffset>
            <bitWidth>1</bitWidth>
          </field>
          <field>
            <name>BR11</name>
            <bitOffset>11</bitOffset>
            <bitWidth>1</bitWidth>
          </field>
          <field>
            <name>BR12</name>
            <bitOffset>12</bitOffset>
            <bitWidth>1</bitWidth>
          </field>
          <field>
            <name>BR13</name>
            <bitOffset>13</bitOffset>
            <bitWidth>1</bitWidth>
          </field>
          <field>
            <name>BR14</name>
            <bitOffset>14</bitOffset>
            <bitWidth>1</bitWidth>
          </field>
          <field>
            <name>BR15</name>
            <bitOffset>15</bitOffset>
            <bitWidth>1</bitWidth>
          </field>
        </fields>
      </register>
      <register>
        <name>LCKR</name>
        <addressOffset>0x18</addressOffset>
        <size>0x20</size>
        <fields>
          <field>
            <name>LCK0</name>
            <bitOffset>0</bitOffset>
            <bitWidth>1</bitWidth>
          </field>
          <field>
            <name>LCK1</name>
            <bitOffset>1</bitOffset>
            <bitWidth>1</bitWidth>
          </field>
          <field>
            <name>LCK2</name>
            <bitOffset>2</bitOffset>
            <bitWidth>1</bitWidth>
          </field>
          <field>
            <name>LCK3</name>
            <bitOffset>3</bitOffset>
            <bitWidth>1</bitWidth>
          </field>
          <field>
            <name>LCK4</name>
            <bitOffset>4</bitOffset>
            <bitWidth>1</bitWidth>
          </field>
          <field>
            <name>LCK5</name>
            <bitOffset>5</bitOffset>
            <bitWidth>1</bitWidth>
          </field>
          <field>
            <name>LCK6</name>
            <bitOffset>6</bitOffset>
            <bitWidth>1</bitWidth>
          </field>
          <field>
            <name>LCK7</name>
            <bitOffset>7</bitOffset>
            <bitWidth>1</bitWidth>
          </field>
          <field>
            <name>LCK8</name>
            <bitOffset>8</bitOffset>
            <bitWidth>1</bitWidth>
          </field>
          <field>
            <name>LCK9</name>
            <bitOffset>9</bitOffset>
            <bitWidth>1</bitWidth>
          </field>
          <field>
            <name>LCK10</name>
            <bitOffset>10</bitOffset>
            <bitWidth>1</bitWidth>
          </field>
          <field>
            <name>LCK11</name>
            <bitOffset>11</bitOffset>
            <bitWidth>1</bitWidth>
          </field>
          <field>
            <name>LCK12</name>
            <bitOffset>12</bitOffset>
            <bitWidth>1</bitWidth>
          </field>
          <field>
            <name>LCK13</name>
            <bitOffset>13</bitOffset>
            <bitWidth>1</bitWidth>
          </field>
          <field>
            <name>LCK14</name>
            <bitOffset>14</bitOffset>
            <bitWidth>1</bitWidth>
          </field>
          <field>
            <name>LCK15</name>
            <bitOffset>15</bitOffset>
            <bitWidth>1</bitWidth>
          </field>
          <field>
            <name>LCKK</name>
            <bitOffset>16</bitOffset>
            <bitWidth>1</bitWidth>
          </field>
        </fields>
      </register>
    </peripheral>
    <peripheral>
      <name>ADC1</name>
      <baseAddress>0x40012400</baseAddress>
      <register>
        <name>SR</name>
        <addressOffset>0x0</addressOffset>
        <size>0x20</size>
        <fields>
          <field>
            <name>AWD</name>
            <bitOffset>0</bitOffset>
            <bitWidth>1</bitWidth>
          </field>
          <field>
            <name>EOS</name>
            <bitOffset>1</bitOffset>
            <bitWidth>1</bitWidth>
          </field>
          <field>
            <name>JEOS</name>
            <bitOffset>2</bitOffset>
            <bitWidth>1</bitWidth>
          </field>
          <field>
            <name>JSTRT</name>
            <bitOffset>3</bitOffset>
            <bitWidth>1</bitWidth>
          </field>
          <field>
            <name>STRT</name>
            <bitOffset>4</bitOffset>
            <bitWidth>1</bitWidth>
          </field>
        </fields>
      </register>
      <register>
        <name>CR1</name>
        <addressOffset>0x4</addressOffset>
        <size>0x20</size>
        <fields>
          <field>
            <name>AWDCH</name>
            <bitOffset>0</bitOffset>
            <bitWidth>5</bitWidth>
          </field>
          <field>
            <name>EOSIE</name>
            <bitOffset>5</bitOffset>
            <bitWidth>1</bitWidth>
          </field>
          <field>
            <name>AWDIE</name>
            <bitOffset>6</bitOffset>
            <bitWidth>1</bitWidth>
          </field>
          <field>
            <name>JEOSIE</name>
            <bitOffset>7</bitOffset>
            <bitWidth>1</bitWidth>
          </field>
          <field>
            <name>SCAN</name>
            <bitOffset>8</bitOffset>
            <bitWidth>1</bitWidth>
          </field>
          <field>
            <name>AWDSGL</name>
            <bitOffset>9</bitOffset>
            <bitWidth>1</bitWidth>
          </field>
          <field>
            <name>JAUTO</name>
            <bitOffset>10</bitOffset>
            <bitWidth>1</bitWidth>
          </field>
          <field>
            <name>DISCEN</name>
            <bitOffset>11</bitOffset>
            <bitWidth>1</bitWidth>
          </field>
          <field>
            <name>JDISCEN</name>
            <bitOffset>12</bitOffset>
            <bitWidth>1</bitWidth>
          </field>
          <field>
            <name>DISCNUM</name>
            <bitOffset>13</bitOffset>
            <bitWidth>3</bitWidth>
          </field>
          <field>
            <name>DUALMOD</name>
            <bitOffset>16</bitOffset>
            <bitWidth>4</bitWidth>
          </field>
          <field>
            <name>JAWDEN</name>
            <bitOffset>22</bitOffset>
            <bitWidth>1</bitWidth>
          </field>
          <field>
            <name>AWDEN</name>
            <bitOffset>23</bitOffset>
            <bitWidth>1</bitWidth>
          </field>
        </fields>
      </register>
      <register>
        <name>CR2</name>
        <addressOffset>0x8</addressOffset>
        <size>0x20</size>
        <fields>
          <field>
            <name>ADON</name>
            <bitOffset>0</bitOffset>
            <bitWidth>1</bitWidth>
          </field>
          <field>
            <name>CONT</name>
            <bitOffset>1</bitOffset>
            <bitWidth>1</bitWidth>
          </field>
          <field>
            <name>CAL</name>
            <bitOffset>2</bitOffset>
            <bitWidth>1</bitWidth>
          </field>
          <field>
            <name>RSTCAL</name>
            <bitOffset>3</bitOffset>
            <bitWidth>1</bitWidth>
          </field>
          <field>
            <name>DMA</name>
            <bitOffset>8</bitOffset>
            <bitWidth>1</bitWidth>
          </field>
          <field>
            <name>ALIGN</name>
            <bitOffset>11</bitOffset>
            <bitWidth>1</bitWidth>
          </field>
          <field>
            <name>JEXTSEL</name>
            <bitOffset>12</bitOffset>
            <bitWidth>3</bitWidth>
          </field>
          <field>
            <name>JEXTTRIG</name>
            <bitOffset>15</bitOffset>
            <bitWidth>1</bitWidth>
          </field>
          <field>
            <name>EXTSEL</name>
            <bitOffset>17</bitOffset>
            <bitWidth>3</bitWidth>
          </field>
          <field>
            <name>EXTTRIG</name>
            <bitOffset>20</bitOffset>
            <bitWidth>1</bitWidth>
          </field>
          <field>
            <name>JSWSTART</name>
            <bitOffset>21</bitOffset>
            <bitWidth>1</bitWidth>
          </field>
          <field>
            <name>SWSTART</name>
            <bitOffset>22</bitOffset>
            <bitWidth>1</bitWidth>
          </field>
          <field>
            <name>TSVREFE</name>
            <bitOffset>23</bitOffset>
            <bitWidth>1</bitWidth>
          </field>
        </fields>
      </register>
      <register>
        <name>SMPR1</name>
        <addressOffset>0xc</addressOffset>
        <size>0x20</size>
        <fields>
          <field>
            <name>SMP10</name>
            <bitOffset>0</bitOffset>
            <bitWidth>3</bitWidth>
          </field>
          <field>
            <name>SMP11</name>
            <bitOffset>3</bitOffset>
            <bitWidth>3</bitWidth>
          </field>
          <field>
            <name>SMP12</name>
            <bitOffset>6</bitOffset>
            <bitWidth>3</bitWidth>
          </field>
          <field>
            <name>SMP13</name>
            <bitOffset>9</bitOffset>
            <bitWidth>3</bitWidth>
          </field>
          <field>
            <name>SMP14</name>
            <bitOffset>12</bitOffset>
            <bitWidth>3</bitWidth>
          </field>
          <field>
            <name>SMP15</name>
            <bitOffset>15</bitOffset>
            <bitWidth>3</bitWidth>
          </field>
          <field>
            <name>SMP16</name>
            <bitOffset>18</bitOffset>
            <bitWidth>3</bitWidth>
          </field>
          <field>
            <name>SMP17</name>
            <bitOffset>21</bitOffset>
            <bitWidth>3</bitWidth>
          </field>
        </fields>
      </register>
      <register>
        <name>SMPR2</name>
        <addressOffset>0x10</addressOffset>
        <size>0x20</size>
        <fields>
          <field>
            <name>SMP0</name>
            <bitOffset>0</bitOffset>
            <bitWidth>3</bitWidth>
          </field>
          <field>
            <name>SMP1</name>
            <bitOffset>3</bitOffset>
            <bitWidth>3</bitWidth>
          </field>
          <field>
            <name>SMP2</name>
            <bitOffset>6</bitOffset>
            <bitWidth>3</bitWidth>
          </field>
          <field>
            <name>SMP3</name>
            <bitOffset>9</bitOffset>
            <bitWidth>3</bitWidth>
          </field>
          <field>
            <name>SMP4</name>
            <bitOffset>12</bitOffset>
            <bitWidth>3</bitWidth>
          </field>
          <field>
            <name>SMP5</name>
            <bitOffset>15</bitOffset>
            <bitWidth>3</bitWidth>
          </field>
          <field>
            <name>SMP6</name>
            <bitOffset>18</bitOffset>
            <bitWidth>3</bitWidth>
          </field>
          <field>
            <name>SMP7</name>
            <bitOffset>21</bitOffset>
            <bitWidth>3</bitWidth>
          </field>
          <field>
            <name>SMP8</name>
            <bitOffset>24</bitOffset>
            <bitWidth>3</bitWidth>
          </field>
          <field>
            <name>SMP9</name>
            <bitOffset>27</bitOffset>
            <bitWidth>3</bitWidth>
          </field>
        </fields>
      </register>
      <register>
        <name>JOFR1</name>
        <addressOffset>0x14</addressOffset>
        <size>0x20</size>
        <fields>
          <field>
            <name>JOFFSET1</name>
            <bitOffset>0</bitOffset>
            <bitWidth>12</bitWidth>
          </field>
        </fields>
      </register>
      <register>
        <name>JOFR2</name>
        <addressOffset>0x18</addressOffset>
        <size>0x20</size>
        <fields>
          <field>
            <name>JOFFSET2</name>
            <bitOffset>0</bitOffset>
            <bitWidth>12</bitWidth>
          </field>
        </fields>
      </register>
      <register>
        <name>JOFR3</name>
        <addressOffset>0x1c</addressOffset>
        <size>0x20</size>
        <fields>
          <field>
            <name>JOFFSET3</name>
            <bitOffset>0</bitOffset>
            <bitWidth>12</bitWidth>
          </field>
        </fields>
      </register>
      <register>
        <name>JOFR4</name>
        <addressOffset>0x20</addressOffset>
        <size>0x20</size>
        <fields>
          <field>
            <name>JOFFSET4</name>
            <bitOffset>0</bitOffset>
            <bitWidth>12</bitWidth>
          </field>
        </fields>
      </register>
      <register>
        <name>HTR</name>
        <addressOffset>0x24</addressOffset>
        <size>0x20</size>
        <fields>
          <field>
            <name>HT</name>
            <bitOffset>0</bitOffset>
            <bitWidth>12</bitWidth>
          </field>
        </fields>
      </register>
      <register>
        <name>LTR</name>
        <addressOffset>0x28</addressOffset>
        <size>0x20</size>
        <fields>
          <field>
            <name>LT</name>
            <bitOffset>0</bitOffset>
            <bitWidth>12</bitWidth>
          </field>
        </fields>
      </register>
      <register>
        <name>SQR1</name>
        <addressOffset>0x2c</addressOffset>
        <size>0x20</size>
        <fields>
          <field>
            <name>SQ13</name>
            <bitOffset>0</bitOffset>
            <bitWidth>5</bitWidth>
          </field>
          <field>
            <name>SQ14</name>
            <bitOffset>5</bitOffset>
            <bitWidth>5</bitWidth>
          </field>
          <field>
            <name>SQ15</name>
            <bitOffset>10</bitOffset>
            <bitWidth>5</bitWidth>
          </field>
          <field>
            <name>SQ16</name>
            <bitOffset>15</bitOffset>
            <bitWidth>5</bitWidth>
          </field>
          <field>
            <name>L</name>
            <bitOffset>20</bitOffset>
            <bitWidth>4</bitWidth>
          </field>
        </fields>
      </register>
      <register>
        <name>SQR2</name>
        <addressOffset>0x30</addressOffset>
        <size>0x20</size>
        <fields>
          <field>
            <name>SQ7</name>
            <bitOffset>0</bitOffset>
            <bitWidth>5</bitWidth>
          </field>
          <field>
            <name>SQ8</name>
            <bitOffset>5</bitOffset>
            <bitWidth>5</bitWidth>
          </field>
          <field>
            <name>SQ9</name>
            <bitOffset>10</bitOffset>
            <bitWidth>5</bitWidth>
          </field>
          <field>
            <name>SQ10</name>
            <bitOffset>15</bitOffset>
            <bitWidth>5</bitWidth>
          </field>
          <field>
            <name>SQ11</name>
            <bitOffset>20</bitOffset>
            <bitWidth>5</bitWidth>
          </field>
          <field>
            <name>SQ12</name>
            <bitOffset>25</bitOffset>
            <bitWidth>5</bitWidth>
          </field>
        </fields>
      </register>
      <register>
        <name>SQR3</name>
        <addressOffset>0x34</addressOffset>
        <size>0x20</size>
        <fields>
          <field>
            <name>SQ1</name>
            <bitOffset>0</bitOffset>
            <bitWidth>5</bitWidth>
          </field>
          <field>
            <name>SQ2</name>
            <bitOffset>5</bitOffset>
            <bitWidth>5</bitWidth>
          </field>
          <field>
            <name>SQ3</name>
            <bitOffset>10</bitOffset>
            <bitWidth>5</bitWidth>
          </field>
          <field>
            <name>SQ4</name>
            <bitOffset>15</bitOffset>
            <bitWidth>5</bitWidth>
          </field>
          <field>
            <name>SQ5</name>
            <bitOffset>20</bitOffset>
            <bitWidth>5</bitWidth>
          </field>
          <field>
            <name>SQ6</name>
            <bitOffset>25</bitOffset>
            <bitWidth>5</bitWidth>
          </field>
        </fields>
      </register>
      <register>
        <name>JSQR</name>
        <addressOffset>0x38</addressOffset>
        <size>0x20</size>
        <fields>
          <field>
            <name>JSQ1</name>
            <bitOffset>0</bitOffset>
            <bitWidth>5</bitWidth>
          </field>
          <field>
            <name>JSQ2</name>
            <bitOffset>5</bitOffset>
            <bitWidth>5</bitWidth>
          </field>
          <field>
            <name>JSQ3</name>
            <bitOffset>10</bitOffset>
            <bitWidth>5</bitWidth>
          </field>
          <field>
            <name>JSQ4</name>
            <bitOffset>15</bitOffset>
            <bitWidth>5</bitWidth>
          </field>
          <field>
            <name>JL</name>
            <bitOffset>20</bitOffset>
            <bitWidth>2</bitWidth>
          </field>
        </fields>
      </register>
      <register>
        <name>JDR1</name>
        <addressOffset>0x3c</addressOffset>
        <size>0x20</size>
        <fields>
          <field>
            <name>JDATA</name>
            <bitOffset>0</bitOffset>
            <bitWidth>16</bitWidth>
          </field>
        </fields>
      </register>
      <register>
        <name>JDR2</name>
        <addressOffset>0x40</addressOffset>
        <size>0x20</size>
        <fields>
          <field>
            <name>JDATA</name>
            <bitOffset>0</bitOffset>
            <bitWidth>16</bitWidth>
          </field>
        </fields>
      </register>
      <register>
        <name>JDR3</name>
        <addressOffset>0x44</addressOffset>
        <size>0x20</size>
        <fields>
          <field>
            <name>JDATA</name>
            <bitOffset>0</bitOffset>
            <bitWidth>16</bitWidth>
          </field>
        </fields>
      </register>
      <register>
        <name>JDR4</name>
        <addressOffset>0x48</addressOffset>
        <size>0x20</size>
        <fields>
          <field>
            <name>JDATA</name>
            <bitOffset>0</bitOffset>
            <bitWidth>16</bitWidth>
          </field>
        </fields>
      </register>
      <register>
        <name>DR</name>
        <addressOffset>0x4c</addressOffset>
        <size>0x20</size>
        <fields>
          <field>
            <name>DATA</name>
            <bitOffset>0</bitOffset>
            <bitWidth>16</bitWidth>
          </field>
          <field>
            <name>ADC2DATA</name>
            <bitOffset>16</bitOffset>
            <bitWidth>16</bitWidth>
          </field>
        </fields>
      </register>
    </peripheral>
    <peripheral>
      <name>ADC12_COMMON</name>
      <baseAddress>0x40012400</baseAddress>
      <register>
        <name>SR</name>
        <addressOffset>0x0</addressOffset>
        <size>0x20</size>
        <fields>
          <field>
            <name>AWD</name>
            <bitOffset>0</bitOffset>
            <bitWidth>1</bitWidth>
          </field>
          <field>
            <name>EOS</name>
            <bitOffset>1</bitOffset>
            <bitWidth>1</bitWidth>
          </field>
          <field>
            <name>JEOS</name>
            <bitOffset>2</bitOffset>
            <bitWidth>1</bitWidth>
          </field>
          <field>
            <name>JSTRT</name>
            <bitOffset>3</bitOffset>
            <bitWidth>1</bitWidth>
          </field>
          <field>
            <name>STRT</name>
            <bitOffset>4</bitOffset>
            <bitWidth>1</bitWidth>
          </field>
        </fields>
      </register>
      <register>
        <name>CR1</name>
        <addressOffset>0x4</addressOffset>
        <size>0x20</size>
        <fields>
          <field>
            <name>AWDCH</name>
            <bitOffset>0</bitOffset>
            <bitWidth>5</bitWidth>
          </field>
          <field>
            <name>EOSIE</name>
            <bitOffset>5</bitOffset>
            <bitWidth>1</bitWidth>
          </field>
          <field>
            <name>AWDIE</name>
            <bitOffset>6</bitOffset>
            <bitWidth>1</bitWidth>
          </field>
          <field>
            <name>JEOSIE</name>
            <bitOffset>7</bitOffset>
            <bitWidth>1</bitWidth>
          </field>
          <field>
            <name>SCAN</name>
            <bitOffset>8</bitOffset>
            <bitWidth>1</bitWidth>
          </field>
          <field>
            <name>AWDSGL</name>
            <bitOffset>9</bitOffset>
            <bitWidth>1</bitWidth>
          </field>
          <field>
            <name>JAUTO</name>
            <bitOffset>10</bitOffset>
            <bitWidth>1</bitWidth>
          </field>
          <field>
            <name>DISCEN</name>
            <bitOffset>11</bitOffset>
            <bitWidth>1</bitWidth>
          </field>
          <field>
            <name>JDISCEN</name>
            <bitOffset>12</bitOffset>
            <bitWidth>1</bitWidth>
          </field>
          <field>
            <name>DISCNUM</name>
            <bitOffset>13</bitOffset>
            <bitWidth>3</bitWidth>
          </field>
          <field>
            <name>DUALMOD</name>
            <bitOffset>16</bitOffset>
            <bitWidth>4</bitWidth>
          </field>
          <field>
            <name>JAWDEN</name>
            <bitOffset>22</bitOffset>
            <bitWidth>1</bitWidth>
          </field>
          <field>
            <name>AWDEN</name>
            <bitOffset>23</bitOffset>
            <bitWidth>1</bitWidth>
          </field>
        </fields>
      </register>
      <register>
        <name>CR2</name>
        <addressOffset>0x8</addressOffset>
        <size>0x20</size>
        <fields>
          <field>
            <name>ADON</name>
            <bitOffset>0</bitOffset>
            <bitWidth>1</bitWidth>
          </field>
          <field>
            <name>CONT</name>
            <bitOffset>1</bitOffset>
            <bitWidth>1</bitWidth>
          </field>
          <field>
            <name>CAL</name>
            <bitOffset>2</bitOffset>
            <bitWidth>1</bitWidth>
          </field>
          <field>
            <name>RSTCAL</name>
            <bitOffset>3</bitOffset>
            <bitWidth>1</bitWidth>
          </field>
          <field>
            <name>DMA</name>
            <bitOffset>8</bitOffset>
            <bitWidth>1</bitWidth>
          </field>
          <field>
            <name>ALIGN</name>
            <bitOffset>11</bitOffset>
            <bitWidth>1</bitWidth>
          </field>
          <field>
            <name>JEXTSEL</name>
            <bitOffset>12</bitOffset>
            <bitWidth>3</bitWidth>
          </field>
          <field>
            <name>JEXTTRIG</name>
            <bitOffset>15</bitOffset>
            <bitWidth>1</bitWidth>
          </field>
          <field>
            <name>EXTSEL</name>
            <bitOffset>17</bitOffset>
            <bitWidth>3</bitWidth>
          </field>
          <field>
            <name>EXTTRIG</name>
            <bitOffset>20</bitOffset>
            <bitWidth>1</bitWidth>
          </field>
          <field>
            <name>JSWSTART</name>
            <bitOffset>21</bitOffset>
            <bitWidth>1</bitWidth>
          </field>
          <field>
            <name>SWSTART</name>
            <bitOffset>22</bitOffset>
            <bitWidth>1</bitWidth>
          </field>
          <field>
            <name>TSVREFE</name>
            <bitOffset>23</bitOffset>
            <bitWidth>1</bitWidth>
          </field>
        </fields>
      </register>
      <register>
        <name>DR</name>
        <addressOffset>0x4c</addressOffset>
        <size>0x20</size>
        <fields>
          <field>
            <name>DATA</name>
            <bitOffset>0</bitOffset>
            <bitWidth>16</bitWidth>
          </field>
          <field>
            <name>ADC2DATA</name>
            <bitOffset>16</bitOffset>
            <bitWidth>16</bitWidth>
          </field>
        </fields>
      </register>
    </peripheral>
    <peripheral>
      <name>ADC2</name>
      <baseAddress>0x40012800</baseAddress>
      <register>
        <name>SR</name>
        <addressOffset>0x0</addressOffset>
        <size>0x20</size>
        <fields>
          <field>
            <name>AWD</name>
            <bitOffset>0</bitOffset>
            <bitWidth>1</bitWidth>
          </field>
          <field>
            <name>EOS</name>
            <bitOffset>1</bitOffset>
            <bitWidth>1</bitWidth>
          </field>
          <field>
            <name>JEOS</name>
            <bitOffset>2</bitOffset>
            <bitWidth>1</bitWidth>
          </field>
          <field>
            <name>JSTRT</name>
            <bitOffset>3</bitOffset>
            <bitWidth>1</bitWidth>
          </field>
          <field>
            <name>STRT</name>
            <bitOffset>4</bitOffset>
            <bitWidth>1</bitWidth>
          </field>
        </fields>
      </register>
      <register>
        <name>CR1</name>
        <addressOffset>0x4</addressOffset>
        <size>0x20</size>
        <fields>
          <field>
            <name>AWDCH</name>
            <bitOffset>0</bitOffset>
            <bitWidth>5</bitWidth>
          </field>
          <field>
            <name>EOSIE</name>
            <bitOffset>5</bitOffset>
            <bitWidth>1</bitWidth>
          </field>
          <field>
            <name>AWDIE</name>
            <bitOffset>6</bitOffset>
            <bitWidth>1</bitWidth>
          </field>
          <field>
            <name>JEOSIE</name>
            <bitOffset>7</bitOffset>
            <bitWidth>1</bitWidth>
          </field>
          <field>
            <name>SCAN</name>
            <bitOffset>8</bitOffset>
            <bitWidth>1</bitWidth>
          </field>
          <field>
            <name>AWDSGL</name>
            <bitOffset>9</bitOffset>
            <bitWidth>1</bitWidth>
          </field>
          <field>
            <name>JAUTO</name>
            <bitOffset>10</bitOffset>
            <bitWidth>1</bitWidth>
          </field>
          <field>
            <name>DISCEN</name>
            <bitOffset>11</bitOffset>
            <bitWidth>1</bitWidth>
          </field>
          <field>
            <name>JDISCEN</name>
            <bitOffset>12</bitOffset>
            <bitWidth>1</bitWidth>
          </field>
          <field>
            <name>DISCNUM</name>
            <bitOffset>13</bitOffset>
            <bitWidth>3</bitWidth>
          </field>
          <field>
            <name>DUALMOD</name>
            <bitOffset>16</bitOffset>
            <bitWidth>4</bitWidth>
          </field>
          <field>
            <name>JAWDEN</name>
            <bitOffset>22</bitOffset>
            <bitWidth>1</bitWidth>
          </field>
          <field>
            <name>AWDEN</name>
            <bitOffset>23</bitOffset>
            <bitWidth>1</bitWidth>
          </field>
        </fields>
      </register>
      <register>
        <name>CR2</name>
        <addressOffset>0x8</addressOffset>
        <size>0x20</size>
        <fields>
          <field>
            <name>ADON</name>
            <bitOffset>0</bitOffset>
            <bitWidth>1</bitWidth>
          </field>
          <field>
            <name>CONT</name>
            <bitOffset>1</bitOffset>
            <bitWidth>1</bitWidth>
          </field>
          <field>
            <name>CAL</name>
            <bitOffset>2</bitOffset>
            <bitWidth>1</bitWidth>
          </field>
          <field>
            <name>RSTCAL</name>
            <bitOffset>3</bitOffset>
            <bitWidth>1</bitWidth>
          </field>
          <field>
            <name>DMA</name>
            <bitOffset>8</bitOffset>
            <bitWidth>1</bitWidth>
          </field>
          <field>
            <name>ALIGN</name>
            <bitOffset>11</bitOffset>
            <bitWidth>1</bitWidth>
          </field>
          <field>
            <name>JEXTSEL</name>
            <bitOffset>12</bitOffset>
            <bitWidth>3</bitWidth>
          </field>
          <field>
            <name>JEXTTRIG</name>
            <bitOffset>15</bitOffset>
            <bitWidth>1</bitWidth>
          </field>
          <field>
            <name>EXTSEL</name>
            <bitOffset>17</bitOffset>
            <bitWidth>3</bitWidth>
          </field>
          <field>
            <name>EXTTRIG</name>
            <bitOffset>20</bitOffset>
            <bitWidth>1</bitWidth>
          </field>
          <field>
            <name>JSWSTART</name>
            <bitOffset>21</bitOffset>
            <bitWidth>1</bitWidth>
          </field>
          <field>
            <name>SWSTART</name>
            <bitOffset>22</bitOffset>
            <bitWidth>1</bitWidth>
          </field>
          <field>
            <name>TSVREFE</name>
            <bitOffset>23</bitOffset>
            <bitWidth>1</bitWidth>
          </field>
        </fields>
      </register>
      <register>
        <name>SMPR1</name>
        <addressOffset>0xc</addressOffset>
        <size>0x20</size>
        <fields>
          <field>
            <name>SMP10</name>
            <bitOffset>0</bitOffset>
            <bitWidth>3</bitWidth>
          </field>
          <field>
            <name>SMP11</name>
            <bitOffset>3</bitOffset>
            <bitWidth>3</bitWidth>
          </field>
          <field>
            <name>SMP12</name>
            <bitOffset>6</bitOffset>
            <bitWidth>3</bitWidth>
          </field>
          <field>
            <name>SMP13</name>
            <bitOffset>9</bitOffset>
            <bitWidth>3</bitWidth>
          </field>
          <field>
            <name>SMP14</name>
            <bitOffset>12</bitOffset>
            <bitWidth>3</bitWidth>
          </field>
          <field>
            <name>SMP15</name>
            <bitOffset>15</bitOffset>
            <bitWidth>3</bitWidth>
          </field>
          <field>
            <name>SMP16</name>
            <bitOffset>18</bitOffset>
            <bitWidth>3</bitWidth>
          </field>
          <field>
            <name>SMP17</name>
            <bitOffset>21</bitOffset>
            <bitWidth>3</bitWidth>
          </field>
        </fields>
      </register>
      <register>
        <name>SMPR2</name>
        <addressOffset>0x10</addressOffset>
        <size>0x20</size>
        <fields>
          <field>
            <name>SMP0</name>
            <bitOffset>0</bitOffset>
            <bitWidth>3</bitWidth>
          </field>
          <field>
            <name>SMP1</name>
            <bitOffset>3</bitOffset>
            <bitWidth>3</bitWidth>
          </field>
          <field>
            <name>SMP2</name>
            <bitOffset>6</bitOffset>
            <bitWidth>3</bitWidth>
          </field>
          <field>
            <name>SMP3</name>
            <bitOffset>9</bitOffset>
            <bitWidth>3</bitWidth>
          </field>
          <field>
            <name>SMP4</name>
            <bitOffset>12</bitOffset>
            <bitWidth>3</bitWidth>
          </field>
          <field>
            <name>SMP5</name>
            <bitOffset>15</bitOffset>
            <bitWidth>3</bitWidth>
          </field>
          <field>
            <name>SMP6</name>
            <bitOffset>18</bitOffset>
            <bitWidth>3</bitWidth>
          </field>
          <field>
            <name>SMP7</name>
            <bitOffset>21</bitOffset>
            <bitWidth>3</bitWidth>
          </field>
          <field>
            <name>SMP8</name>
            <bitOffset>24</bitOffset>
            <bitWidth>3</bitWidth>
          </field>
          <field>
            <name>SMP9</name>
            <bitOffset>27</bitOffset>
            <bitWidth>3</bitWidth>
          </field>
        </fields>
      </register>
      <register>
        <name>JOFR1</name>
        <addressOffset>0x14</addressOffset>
        <size>0x20</size>
        <fields>
          <field>
            <name>JOFFSET1</name>
            <bitOffset>0</bitOffset>
            <bitWidth>12</bitWidth>
          </field>
        </fields>
      </register>
      <register>
        <name>JOFR2</name>
        <addressOffset>0x18</addressOffset>
        <size>0x20</size>
        <fields>
          <field>
            <name>JOFFSET2</name>
            <bitOffset>0</bitOffset>
            <bitWidth>12</bitWidth>
          </field>
        </fields>
      </register>
      <register>
        <name>JOFR3</name>
        <addressOffset>0x1c</addressOffset>
        <size>0x20</size>
        <fields>
          <field>
            <name>JOFFSET3</name>
            <bitOffset>0</bitOffset>
            <bitWidth>12</bitWidth>
          </field>
        </fields>
      </register>
      <register>
        <name>JOFR4</name>
        <addressOffset>0x20</addressOffset>
        <size>0x20</size>
        <fields>
          <field>
            <name>JOFFSET4</name>
            <bitOffset>0</bitOffset>
            <bitWidth>12</bitWidth>
          </field>
        </fields>
      </register>
      <register>
        <name>HTR</name>
        <addressOffset>0x24</addressOffset>
        <size>0x20</size>
        <fields>
          <field>
            <name>HT</name>
            <bitOffset>0</bitOffset>
            <bitWidth>12</bitWidth>
          </field>
        </fields>
      </register>
      <register>
        <name>LTR</name>
        <addressOffset>0x28</addressOffset>
        <size>0x20</size>
        <fields>
          <field>
            <name>LT</name>
            <bitOffset>0</bitOffset>
            <bitWidth>12</bitWidth>
          </field>
        </fields>
      </register>
      <register>
        <name>SQR1</name>
        <addressOffset>0x2c</addressOffset>
        <size>0x20</size>
        <fields>
          <field>
            <name>SQ13</name>
            <bitOffset>0</bitOffset>
            <bitWidth>5</bitWidth>
          </field>
          <field>
            <name>SQ14</name>
            <bitOffset>5</bitOffset>
            <bitWidth>5</bitWidth>
          </field>
          <field>
            <name>SQ15</name>
            <bitOffset>10</bitOffset>
            <bitWidth>5</bitWidth>
          </field>
          <field>
            <name>SQ16</name>
            <bitOffset>15</bitOffset>
            <bitWidth>5</bitWidth>
          </field>
          <field>
            <name>L</name>
            <bitOffset>20</bitOffset>
            <bitWidth>4</bitWidth>
          </field>
        </fields>
      </register>
      <register>
        <name>SQR2</name>
        <addressOffset>0x30</addressOffset>
        <size>0x20</size>
        <fields>
          <field>
            <name>SQ7</name>
            <bitOffset>0</bitOffset>
            <bitWidth>5</bitWidth>
          </field>
          <field>
            <name>SQ8</name>
            <bitOffset>5</bitOffset>
            <bitWidth>5</bitWidth>
          </field>
          <field>
            <name>SQ9</name>
            <bitOffset>10</bitOffset>
            <bitWidth>5</bitWidth>
          </field>
          <field>
            <name>SQ10</name>
            <bitOffset>15</bitOffset>
            <bitWidth>5</bitWidth>
          </field>
          <field>
            <name>SQ11</name>
            <bitOffset>20</bitOffset>
            <bitWidth>5</bitWidth>
          </field>
          <field>
            <name>SQ12</name>
            <bitOffset>25</bitOffset>
            <bitWidth>5</bitWidth>
          </field>
        </fields>
      </register>
      <register>
        <name>SQR3</name>
        <addressOffset>0x34</addressOffset>
        <size>0x20</size>
        <fields>
          <field>
            <name>SQ1</name>
            <bitOffset>0</bitOffset>
            <bitWidth>5</bitWidth>
          </field>
          <field>
            <name>SQ2</name>
            <bitOffset>5</bitOffset>
            <bitWidth>5</bitWidth>
          </field>
          <field>
            <name>SQ3</name>
            <bitOffset>10</bitOffset>
            <bitWidth>5</bitWidth>
          </field>
          <field>
            <name>SQ4</name>
            <bitOffset>15</bitOffset>
            <bitWidth>5</bitWidth>
          </field>
          <field>
            <name>SQ5</name>
            <bitOffset>20</bitOffset>
            <bitWidth>5</bitWidth>
          </field>
          <field>
            <name>SQ6</name>
            <bitOffset>25</bitOffset>
            <bitWidth>5</bitWidth>
          </field>
        </fields>
      </register>
      <register>
        <name>JSQR</name>
        <addressOffset>0x38</addressOffset>
        <size>0x20</size>
        <fields>
          <field>
            <name>JSQ1</name>
            <bitOffset>0</bitOffset>
            <bitWidth>5</bitWidth>
          </field>
          <field>
            <name>JSQ2</name>
            <bitOffset>5</bitOffset>
            <bitWidth>5</bitWidth>
          </field>
          <field>
            <name>JSQ3</name>
            <bitOffset>10</bitOffset>
            <bitWidth>5</bitWidth>
          </field>
          <field>
            <name>JSQ4</name>
            <bitOffset>15</bitOffset>
            <bitWidth>5</bitWidth>
          </field>
          <field>
            <name>JL</name>
            <bitOffset>20</bitOffset>
            <bitWidth>2</bitWidth>
          </field>
        </fields>
      </register>
      <register>
        <name>JDR1</name>
        <addressOffset>0x3c</addressOffset>
        <size>0x20</size>
        <fields>
          <field>
            <name>JDATA</name>
            <bitOffset>0</bitOffset>
            <bitWidth>16</bitWidth>
          </field>
        </fields>
      </register>
      <register>
        <name>JDR2</name>
        <addressOffset>0x40</addressOffset>
        <size>0x20</size>
        <fields>
          <field>
            <name>JDATA</name>
            <bitOffset>0</bitOffset>
            <bitWidth>16</bitWidth>
          </field>
        </fields>
      </register>
      <register>
        <name>JDR3</name>
        <addressOffset>0x44</addressOffset>
        <size>0x20</size>
        <fields>
          <field>
            <name>JDATA</name>
            <bitOffset>0</bitOffset>
            <bitWidth>16</bitWidth>
          </field>
        </fields>
      </register>
      <register>
        <name>JDR4</name>
        <addressOffset>0x48</addressOffset>
        <size>0x20</size>
        <fields>
          <field>
            <name>JDATA</name>
            <bitOffset>0</bitOffset>
            <bitWidth>16</bitWidth>
          </field>
        </fields>
      </register>
      <register>
        <name>DR</name>
        <addressOffset>0x4c</addressOffset>
        <size>0x20</size>
        <fields>
          <field>
            <name>DATA</name>
            <bitOffset>0</bitOffset>
            <bitWidth>16</bitWidth>
          </field>
          <field>
            <name>ADC2DATA</name>
            <bitOffset>16</bitOffset>
            <bitWidth>16</bitWidth>
          </field>
        </fields>
      </register>
    </peripheral>
    <peripheral>
      <name>TIM1</name>
      <baseAddress>0x40012c00</baseAddress>
      <register>
        <name>CR1</name>
        <addressOffset>0x0</addressOffset>
        <size>0x20</size>
        <fields>
          <field>
            <name>CEN</name>
            <bitOffset>0</bitOffset>
            <bitWidth>1</bitWidth>
          </field>
          <field>
            <name>UDIS</name>
            <bitOffset>1</bitOffset>
            <bitWidth>1</bitWidth>
          </field>
          <field>
            <name>URS</name>
            <bitOffset>2</bitOffset>
            <bitWidth>1</bitWidth>
          </field>
          <field>
            <name>OPM</name>
            <bitOffset>3</bitOffset>
            <bitWidth>1</bitWidth>
          </field>
          <field>
            <name>DIR</name>
            <bitOffset>4</bitOffset>
            <bitWidth>1</bitWidth>
          </field>
          <field>
            <name>CMS</name>
            <bitOffset>5</bitOffset>
            <bitWidth>2</bitWidth>
          </field>
          <field>
            <name>ARPE</name>
            <bitOffset>7</bitOffset>
            <bitWidth>1</bitWidth>
          </field>
          <field>
            <name>CKD</name>
            <bitOffset>8</bitOffset>
            <bitWidth>2</bitWidth>
          </field>
        </fields>
      </register>
      <register>
        <name>CR2</name>
        <addressOffset>0x4</addressOffset>
        <size>0x20</size>
        <fields>
          <field>
            <name>CCPC</name>
            <bitOffset>0</bitOffset>
            <bitWidth>1</bitWidth>
          </field>
          <field>
            <name>CCUS</name>
            <bitOffset>2</bitOffset>
            <bitWidth>1</bitWidth>
          </field>
          <field>
            <name>CCDS</name>
            <bitOffset>3</bitOffset>
            <bitWidth>1</bitWidth>
          </field>
          <field>
            <name>MMS</name>
            <bitOffset>4</bitOffset>
            <bitWidth>3</bitWidth>
          </field>
          <field>
            <name>TI1S</name>
            <bitOffset>7</bitOffset>
            <bitWidth>1</bitWidth>
          </field>
          <field>
            <name>OIS1</name>
            <bitOffset>8</bitOffset>
            <bitWidth>1</bitWidth>
          </field>
          <field>
            <name>OIS1N</name>
            <bitOffset>9</bitOffset>
            <bitWidth>1</bitWidth>
          </field>
          <field>
            <name>OIS2</name>
            <bitOffset>10</bitOffset>
            <bitWidth>1</bitWidth>
          </field>
          <field>
            <name>OIS2N</name>
            <bitOffset>11</bitOffset>
            <bitWidth>1</bitWidth>
          </field>
          <field>
            <name>OIS3</name>
            <bitOffset>12</bitOffset>
            <bitWidth>1</bitWidth>
          </field>
          <field>
            <name>OIS3N</name>
            <bitOffset>13</bitOffset>
            <bitWidth>1</bitWidth>
          </field>
          <field>
            <name>OIS4</name>
            <bitOffset>14</bitOffset>
            <bitWidth>1</bitWidth>
          </field>
        </fields>
      </register>
      <register>
        <name>SMCR</name>
        <addressOffset>0x8</addressOffset>
        <size>0x20</size>
        <fields>
          <field>
            <name>SMS</name>
            <bitOffset>0</bitOffset>
            <bitWidth>3</bitWidth>
          </field>
          <field>
            <name>TS</name>
            <bitOffset>4</bitOffset>
            <bitWidth>3</bitWidth>
          </field>
          <field>
            <name>MSM</name>
            <bitOffset>7</bitOffset>
            <bitWidth>1</bitWidth>
          </field>
          <field>
            <name>ETF</name>
            <bitOffset>8</bitOffset>
            <bitWidth>4</bitWidth>
          </field>
          <field>
            <name>ETPS</name>
            <bitOffset>12</bitOffset>
            <bitWidth>2</bitWidth>
          </field>
          <field>
            <name>ECE</name>
            <bitOffset>14</bitOffset>
            <bitWidth>1</bitWidth>
          </field>
          <field>
            <name>ETP</name>
            <bitOffset>15</bitOffset>
            <bitWidth>1</bitWidth>
          </field>
        </fields>
      </register>
      <register>
        <name>DIER</name>
        <addressOffset>0xc</addressOffset>
        <size>0x20</size>
        <fields>
          <field>
            <name>UIE</name>
            <bitOffset>0</bitOffset>
            <bitWidth>1</bitWidth>
          </field>
          <field>
            <name>CC1IE</name>
            <bitOffset>1</bitOffset>
            <bitWidth>1</bitWidth>
          </field>
          <field>
            <name>CC2IE</name>
            <bitOffset>2</bitOffset>
            <bitWidth>1</bitWidth>
          </field>
          <field>
            <name>CC3IE</name>
            <bitOffset>3</bitOffset>
            <bitWidth>1</bitWidth>
          </field>
          <field>
            <name>CC4IE</name>
            <bitOffset>4</bitOffset>
            <bitWidth>1</bitWidth>
          </field>
          <field>
            <name>COMIE</name>
            <bitOffset>5</bitOffset>
            <bitWidth>1</bitWidth>
          </field>
          <field>
            <name>TIE</name>
            <bitOffset>6</bitOffset>
            <bitWidth>1</bitWidth>
          </field>
          <field>
            <name>BIE</name>
            <bitOffset>7</bitOffset>
            <bitWidth>1</bitWidth>
          </field>
          <field>
            <name>UDE</name>
            <bitOffset>8</bitOffset>
            <bitWidth>1</bitWidth>
          </field>
          <field>
            <name>CC1DE</name>
            <bitOffset>9</bitOffset>
            <bitWidth>1</bitWidth>
          </field>
          <field>
            <name>CC2DE</name>
            <bitOffset>10</bitOffset>
            <bitWidth>1</bitWidth>
          </field>
          <field>
            <name>CC3DE</name>
            <bitOffset>11</bitOffset>
            <bitWidth>1</bitWidth>
          </field>
          <field>
            <name>CC4DE</name>
            <bitOffset>12</bitOffset>
            <bitWidth>1</bitWidth>
          </field>
          <field>
            <name>COMDE</name>
            <bitOffset>13</bitOffset>
            <bitWidth>1</bitWidth>
          </field>
          <field>
            <name>TDE</name>
            <bitOffset>14</bitOffset>
            <bitWidth>1</bitWidth>
          </field>
        </fields>
      </register>
      <register>
        <name>SR</name>
        <addressOffset>0x10</addressOffset>
        <size>0x20</size>
        <fields>
          <field>
            <name>UIF</name>
            <bitOffset>0</bitOffset>
            <bitWidth>1</bitWidth>
          </field>
          <field>
            <name>CC1IF</name>
            <bitOffset>1</bitOffset>
            <bitWidth>1</bitWidth>
          </field>
          <field>
            <name>CC2IF</name>
            <bitOffset>2</bitOffset>
            <bitWidth>1</bitWidth>
          </field>
          <field>
            <name>CC3IF</name>
            <bitOffset>3</bitOffset>
            <bitWidth>1</bitWidth>
          </field>
          <field>
            <name>CC4IF</name>
            <bitOffset>4</bitOffset>
            <bitWidth>1</bitWidth>
          </field>
          <field>
            <name>COMIF</name>
            <bitOffset>5</bitOffset>
            <bitWidth>1</bitWidth>
          </field>
          <field>
            <name>TIF</name>
            <bitOffset>6</bitOffset>
            <bitWidth>1</bitWidth>
          </field>
          <field>
            <name>BIF</name>
            <bitOffset>7</bitOffset>
            <bitWidth>1</bitWidth>
          </field>
          <field>
            <name>CC1OF</name>
            <bitOffset>9</bitOffset>
            <bitWidth>1</bitWidth>
          </field>
          <field>
            <name>CC2OF</name>
            <bitOffset>10</bitOffset>
            <bitWidth>1</bitWidth>
          </field>
          <field>
            <name>CC3OF</name>
            <bitOffset>11</bitOffset>
            <bitWidth>1</bitWidth>
          </field>
          <field>
            <name>CC4OF</name>
            <bitOffset>12</bitOffset>
            <bitWidth>1</bitWidth>
          </field>
        </fields>
      </register>
      <register>
        <name>EGR</name>
        <addressOffset>0x14</addressOffset>
        <size>0x20</size>
        <fields>
          <field>
            <name>UG</name>
            <bitOffset>0</bitOffset>
            <bitWidth>1</bitWidth>
          </field>
          <field>
            <name>CC1G</name>
            <bitOffset>1</bitOffset>
            <bitWidth>1</bitWidth>
          </field>
          <field>
            <name>CC2G</name>
            <bitOffset>2</bitOffset>
            <bitWidth>1</bitWidth>
          </field>
          <field>
            <name>CC3G</name>
            <bitOffset>3</bitOffset>
            <bitWidth>1</bitWidth>
          </field>
          <field>
            <name>CC4G</name>
            <bitOffset>4</bitOffset>
            <bitWidth>1</bitWidth>
          </field>
          <field>
            <name>COMG</name>
            <bitOffset>5</bitOffset>
            <bitWidth>1</bitWidth>
          </field>
          <field>
            <name>TG</name>
            <bitOffset>6</bitOffset>
            <bitWidth>1</bitWidth>
          </field>
          <field>
            <name>BG</name>
            <bitOffset>7</bitOffset>
            <bitWidth>1</bitWidth>
          </field>
        </fields>
      </register>
      <register>
        <name>CCMR1</name>
        <addressOffset>0x18</addressOffset>
        <size>0x20</size>
        <fields>
          <field>
            <name>CC1S</name>
            <bitOffset>0</bitOffset>
            <bitWidth>2</bitWidth>
          </field>
          <field>
            <name>OC1FE</name>
            <bitOffset>2</bitOffset>
            <bitWidth>1</bitWidth>
          </field>
          <field>
            <name>OC1PE</name>
            <bitOffset>3</bitOffset>
            <bitWidth>1</bitWidth>
          </field>
          <field>
            <name>OC1M</name>
            <bitOffset>4</bitOffset>
            <bitWidth>3</bitWidth>
          </field>
          <field>
            <name>OC1CE</name>
            <bitOffset>7</bitOffset>
            <bitWidth>1</bitWidth>
          </field>
          <field>
            <name>CC2S</name>
            <bitOffset>8</bitOffset>
            <bitWidth>2</bitWidth>
          </field>
          <field>
            <name>OC2FE</name>
            <bitOffset>10</bitOffset>
            <bitWidth>1</bitWidth>
          </field>
          <field>
            <name>OC2PE</name>
            <bitOffset>11</bitOffset>
            <bitWidth>1</bitWidth>
          </field>
          <field>
            <name>OC2M</name>
            <bitOffset>12</bitOffset>
            <bitWidth>3</bitWidth>
          </field>
          <field>
            <name>OC2CE</name>
            <bitOffset>15</bitOffset>
            <bitWidth>1</bitWidth>
          </field>
        </fields>
      </register>
      <register>
        <name>CCMR2</name>
        <addressOffset>0x1c</addressOffset>
        <size>0x20</size>
        <fields>
          <field>
            <name>CC3S</name>
            <bitOffset>0</bitOffset>
            <bitWidth>2</bitWidth>
          </field>
          <field>
            <name>OC3FE</name>
            <bitOffset>2</bitOffset>
            <bitWidth>1</bitWidth>
          </field>
          <field>
            <name>OC3PE</name>
            <bitOffset>3</bitOffset>
            <bitWidth>1</bitWidth>
          </field>
          <field>
            <name>OC3M</name>
            <bitOffset>4</bitOffset>
            <bitWidth>3</bitWidth>
          </field>
          <field>
            <name>OC3CE</name>
            <bitOffset>7</bitOffset>
            <bitWidth>1</bitWidth>
          </field>
          <field>
            <name>CC4S</name>
            <bitOffset>8</bitOffset>
            <bitWidth>2</bitWidth>
          </field>
          <field>
            <name>OC4FE</name>
            <bitOffset>10</bitOffset>
            <bitWidth>1</bitWidth>
          </field>
          <field>
            <name>OC4PE</name>
            <bitOffset>11</bitOffset>
            <bitWidth>1</bitWidth>
          </field>
          <field>
            <name>OC4M</name>
            <bitOffset>12</bitOffset>
            <bitWidth>3</bitWidth>
          </field>
          <field>
            <name>OC4CE</name>
            <bitOffset>15</bitOffset>
            <bitWidth>1</bitWidth>
          </field>
        </fields>
      </register>
      <register>
        <name>CCER</name>
        <addressOffset>0x20</addressOffset>
        <size>0x20</size>
        <fields>
          <field>
            <name>CC1E</name>
            <bitOffset>0</bitOffset>
            <bitWidth>1</bitWidth>
          </field>
          <field>
            <name>CC1P</name>
            <bitOffset>1</bitOffset>
            <bitWidth>1</bitWidth>
          </field>
          <field>
            <name>CC1NE</name>
            <bitOffset>2</bitOffset>
            <bitWidth>1</bitWidth>
          </field>
          <field>
            <name>CC1NP</name>
            <bitOffset>3</bitOffset>
            <bitWidth>1</bitWidth>
          </field>
          <field>
            <name>CC2E</name>
            <bitOffset>4</bitOffset>
            <bitWidth>1</bitWidth>
          </field>
          <field>
            <name>CC2P</name>
            <bitOffset>5</bitOffset>
            <bitWidth>1</bitWidth>
          </field>
          <field>
            <name>CC2NE</name>
            <bitOffset>6</bitOffset>
            <bitWidth>1</bitWidth>
          </field>
          <field>
            <name>CC2NP</name>
            <bitOffset>7</bitOffset>
            <bitWidth>1</bitWidth>
          </field>
          <field>
            <name>CC3E</name>
            <bitOffset>8</bitOffset>
            <bitWidth>1</bitWidth>
          </field>
          <field>
            <name>CC3P</name>
            <bitOffset>9</bitOffset>
            <bitWidth>1</bitWidth>
          </field>
          <field>
            <name>CC3NE</name>
            <bitOffset>10</bitOffset>
            <bitWidth>1</bitWidth>
          </field>
          <field>
            <name>CC3NP</name>
            <bitOffset>11</bitOffset>
            <bitWidth>1</bitWidth>
          </field>
          <field>
            <name>CC4E</name>
            <bitOffset>12</bitOffset>
            <bitWidth>1</bitWidth>
          </field>
          <field>
            <name>CC4P</name>
            <bitOffset>13</bitOffset>
            <bitWidth>1</bitWidth>
          </field>
        </fields>
      </register>
      <register>
        <name>CNT</name>
        <addressOffset>0x24</addressOffset>
        <size>0x20</size>
        <fields>
          <field>
            <name>CNT</name>
            <bitOffset>0</bitOffset>
            <bitWidth>32</bitWidth>
          </field>
        </fields>
      </register>
      <register>
        <name>PSC</name>
        <addressOffset>0x28</addressOffset>
        <size>0x20</size>
        <fields>
          <field>
            <name>PSC</name>
            <bitOffset>0</bitOffset>
            <bitWidth>16</bitWidth>
          </field>
        </fields>
      </register>
      <register>
        <name>ARR</name>
        <addressOffset>0x2c</addressOffset>
        <size>0x20</size>
        <fields>
          <field>
            <name>ARR</name>
            <bitOffset>0</bitOffset>
            <bitWidth>32</bitWidth>
          </field>
        </fields>
      </register>
      <register>
        <name>RCR</name>
        <addressOffset>0x30</addressOffset>
        <size>0x20</size>
        <fields>
          <field>
            <name>REP</name>
            <bitOffset>0</bitOffset>
            <bitWidth>8</bitWidth>
          </field>
        </fields>
      </register>
      <register>
        <name>CCR1</name>
        <addressOffset>0x34</addressOffset>
        <size>0x20</size>
        <fields>
          <field>
            <name>CCR1</name>
            <bitOffset>0</bitOffset>
            <bitWidth>16</bitWidth>
          </field>
        </fields>
      </register>
      <register>
        <name>CCR2</name>
        <addressOffset>0x38</addressOffset>
        <size>0x20</size>
        <fields>
          <field>
            <name>CCR2</name>
            <bitOffset>0</bitOffset>
            <bitWidth>16</bitWidth>
          </field>
        </fields>
      </register>
      <register>
        <name>CCR3</name>
        <addressOffset>0x3c</addressOffset>
        <size>0x20</size>
        <fields>
          <field>
            <name>CCR3</name>
            <bitOffset>0</bitOffset>
            <bitWidth>16</bitWidth>
          </field>
        </fields>
      </register>
      <register>
        <name>CCR4</name>
        <addressOffset>0x40</addressOffset>
        <size>0x20</size>
        <fields>
          <field>
            <name>CCR4</name>
            <bitOffset>0</bitOffset>
            <bitWidth>16</bitWidth>
          </field>
        </fields>
      </register>
      <register>
        <name>BDTR</name>
        <addressOffset>0x44</addressOffset>
        <size>0x20</size>
        <fields>
          <field>
            <name>DTG</name>
            <bitOffset>0</bitOffset>
            <bitWidth>8</bitWidth>
          </field>
          <field>
            <name>LOCK</name>
            <bitOffset>8</bitOffset>
            <bitWidth>2</bitWidth>
          </field>
          <field>
            <name>OSSI</name>
            <bitOffset>10</bitOffset>
            <bitWidth>1</bitWidth>
          </field>
          <field>
            <name>OSSR</name>
            <bitOffset>11</bitOffset>
            <bitWidth>1</bitWidth>
          </field>
          <field>
            <name>BKE</name>
            <bitOffset>12</bitOffset>
            <bitWidth>1</bitWidth>
          </field>
          <field>
            <name>BKP</name>
            <bitOffset>13</bitOffset>
            <bitWidth>1</bitWidth>
          </field>
          <field>
            <name>AOE</name>
            <bitOffset>14</bitOffset>
            <bitWidth>1</bitWidth>
          </field>
          <field>
            <name>MOE</name>
            <bitOffset>15</bitOffset>
            <bitWidth>1</bitWidth>
          </field>
        </fields>
      </register>
      <register>
        <name>DCR</name>
        <addressOffset>0x48</addressOffset>
        <size>0x20</size>
        <fields>
          <field>
            <name>DBA</name>
            <bitOffset>0</bitOffset>
            <bitWidth>5</bitWidth>
          </field>
          <field>
            <name>DBL</name>
            <bitOffset>8</bitOffset>
            <bitWidth>5</bitWidth>
          </field>
        </fields>
      </register>
      <register>
        <name>DMAR</name>
        <addressOffset>0x4c</addressOffset>
        <size>0x20</size>
        <fields>
          <field>
            <name>DMAB</name>
            <bitOffset>0</bitOffset>
            <bitWidth>16</bitWidth>
          </field>
        </fields>
      </register>
      <register>
        <name>OR</name>
        <addressOffset>0x50</addressOffset>
        <size>0x20</size>
      </register>
    </peripheral>
    <peripheral>
      <name>SPI1</name>
      <baseAddress>0x40013000</baseAddress>
      <register>
        <name>CR1</name>
        <addressOffset>0x0</addressOffset>
        <size>0x20</size>
        <fields>
          <field>
            <name>CPHA</name>
            <bitOffset>0</bitOffset>
            <bitWidth>1</bitWidth>
          </field>
          <field>
            <name>CPOL</name>
            <bitOffset>1</bitOffset>
            <bitWidth>1</bitWidth>
          </field>
          <field>
            <name>MSTR</name>
            <bitOffset>2</bitOffset>
            <bitWidth>1</bitWidth>
          </field>
          <field>
            <name>BR</name>
            <bitOffset>3</bitOffset>
            <bitWidth>3</bitWidth>
          </field>
          <field>
            <name>SPE</name>
            <bitOffset>6</bitOffset>
            <bitWidth>1</bitWidth>
          </field>
          <field>
            <name>LSBFIRST</name>
            <bitOffset>7</bitOffset>
            <bitWidth>1</bitWidth>
          </field>
          <field>
            <name>SSI</name>
            <bitOffset>8</bitOffset>
            <bitWidth>1</bitWidth>
          </field>
          <field>
            <name>SSM</name>
            <bitOffset>9</bitOffset>
            <bitWidth>1</bitWidth>
          </field>
          <field>
            <name>RXONLY</name>
            <bitOffset>10</bitOffset>
            <bitWidth>1</bitWidth>
          </field>
          <field>
            <name>DFF</name>
            <bitOffset>11</bitOffset>
            <bitWidth>1</bitWidth>
          </field>
          <field>
            <name>CRCNEXT</name>
            <bitOffset>12</bitOffset>
            <bitWidth>1</bitWidth>
          </field>
          <field>
            <name>CRCEN</name>
            <bitOffset>13</bitOffset>
            <bitWidth>1</bitWidth>
          </field>
          <field>
            <name>BIDIOE</name>
            <bitOffset>14</bitOffset>
            <bitWidth>1</bitWidth>
          </field>
          <field>
            <name>BIDIMODE</name>
            <bitOffset>15</bitOffset>
            <bitWidth>1</bitWidth>
          </field>
        </fields>
      </register>
      <register>
        <name>CR2</name>
        <addressOffset>0x4</addressOffset>
        <size>0x20</size>
        <fields>
          <field>
            <name>RXDMAEN</name>
            <bitOffset>0</bitOffset>
            <bitWidth>1</bitWidth>
          </field>
          <field>
            <name>TXDMAEN</name>
            <bitOffset>1</bitOffset>
            <bitWidth>1</bitWidth>
          </field>
          <field>
            <name>SSOE</name>
            <bitOffset>2</bitOffset>
            <bitWidth>1</bitWidth>
          </field>
          <field>
            <name>ERRIE</name>
            <bitOffset>5</bitOffset>
            <bitWidth>1</bitWidth>
          </field>
          <field>
            <name>RXNEIE</name>
            <bitOffset>6</bitOffset>
            <bitWidth>1</bitWidth>
          </field>
          <field>
            <name>TXEIE</name>
            <bitOffset>7</bitOffset>
            <bitWidth>1</bitWidth>
          </field>
        </fields>
      </register>
      <register>
        <name>SR</name>
        <addressOffset>0x8</addressOffset>
        <size>0x20</size>
        <fields>
          <field>
            <name>RXNE</name>
            <bitOffset>0</bitOffset>
            <bitWidth>1</bitWidth>
          </field>
          <field>
            <name>TXE</name>
            <bitOffset>1</bitOffset>
            <bitWidth>1</bitWidth>
          </field>
          <field>
            <name>CHSIDE</name>
            <bitOffset>2</bitOffset>
            <bitWidth>1</bitWidth>
          </field>
          <field>
            <name>UDR</name>
            <bitOffset>3</bitOffset>
            <bitWidth>1</bitWidth>
          </field>
          <field>
            <name>CRCERR</name>
            <bitOffset>4</bitOffset>
            <bitWidth>1</bitWidth>
          </field>
          <field>
            <name>MODF</name>
            <bitOffset>5</bitOffset>
            <bitWidth>1</bitWidth>
          </field>
          <field>
            <name>OVR</name>
            <bitOffset>6</bitOffset>
            <bitWidth>1</bitWidth>
          </field>
          <field>
            <name>BSY</name>
            <bitOffset>7</bitOffset>
            <bitWidth>1</bitWidth>
          </field>
        </fields>
      </register>
      <register>
        <name>DR</name>
        <addressOffset>0xc</addressOffset>
        <size>0x20</size>
        <fields>
          <field>
            <name>DR</name>
            <bitOffset>0</bitOffset>
            <bitWidth>16</bitWidth>
          </field>
        </fields>
      </register>
      <register>
        <name>CRCPR</name>
        <addressOffset>0x10</addressOffset>
        <size>0x20</size>
        <fields>
          <field>
            <name>CRCPOLY</name>
            <bitOffset>0</bitOffset>
            <bitWidth>16</bitWidth>
          </field>
        </fields>
      </register>
      <register>
        <name>RXCRCR</name>
        <addressOffset>0x14</addressOffset>
        <size>0x20</size>
        <fields>
          <field>
            <name>RXCRC</name>
            <bitOffset>0</bitOffset>
            <bitWidth>16</bitWidth>
          </field>
        </fields>
      </register>
      <register>
        <name>TXCRCR</name>
        <addressOffset>0x18</addressOffset>
        <size>0x20</size>
        <fields>
          <field>
            <name>TXCRC</name>
            <bitOffset>0</bitOffset>
            <bitWidth>16</bitWidth>
          </field>
        </fields>
      </register>
      <register>
        <name>I2SCFGR</name>
        <addressOffset>0x1c</addressOffset>
        <size>0x20</size>
        <fields>
          <field>
            <name>I2SMOD</name>
            <bitOffset>11</bitOffset>
            <bitWidth>1</bitWidth>
          </field>
        </fields>
      </register>
    </peripheral>
    <peripheral>
      <name>USART1</name>
      <baseAddress>0x40013800</baseAddress>
      <register>
        <name>SR</name>
        <addressOffset>0x0</addressOffset>
        <size>0x20</size>
        <fields>
          <field>
            <name>PE</name>
            <bitOffset>0</bitOffset>
            <bitWidth>1</bitWidth>
          </field>
          <field>
            <name>FE</name>
            <bitOffset>1</bitOffset>
            <bitWidth>1</bitWidth>
          </field>
          <field>
            <name>NE</name>
            <bitOffset>2</bitOffset>
            <bitWidth>1</bitWidth>
          </field>
          <field>
            <name>ORE</name>
            <bitOffset>3</bitOffset>
            <bitWidth>1</bitWidth>
          </field>
          <field>
            <name>IDLE</name>
            <bitOffset>4</bitOffset>
            <bitWidth>1</bitWidth>
          </field>
          <field>
            <name>RXNE</name>
            <bitOffset>5</bitOffset>
            <bitWidth>1</bitWidth>
          </field>
          <field>
            <name>TC</name>
            <bitOffset>6</bitOffset>
            <bitWidth>1</bitWidth>
          </field>
          <field>
            <name>TXE</name>
            <bitOffset>7</bitOffset>
            <bitWidth>1</bitWidth>
          </field>
          <field>
            <name>LBD</name>
            <bitOffset>8</bitOffset>
            <bitWidth>1</bitWidth>
          </field>
          <field>
            <name>CTS</name>
            <bitOffset>9</bitOffset>
            <bitWidth>1</bitWidth>
          </field>
        </fields>
      </register>
      <register>
        <name>DR</name>
        <addressOffset>0x4</addressOffset>
        <size>0x20</size>
        <fields>
          <field>
            <name>DR</name>
            <bitOffset>0</bitOffset>
            <bitWidth>9</bitWidth>
          </field>
        </fields>
      </register>
      <register>
        <name>BRR</name>
        <addressOffset>0x8</addressOffset>
        <size>0x20</size>
        <fields>
          <field>
            <name>DIV_Fraction</name>
            <bitOffset>0</bitOffset>
            <bitWidth>4</bitWidth>
          </field>
          <field>
            <name>DIV_Mantissa</name>
            <bitOffset>4</bitOffset>
            <bitWidth>12</bitWidth>
          </field>
        </fields>
      </register>
      <register>
        <name>CR1</name>
        <addressOffset>0xc</addressOffset>
        <size>0x20</size>
        <fields>
          <field>
            <name>SBK</name>
            <bitOffset>0</bitOffset>
            <bitWidth>1</bitWidth>
          </field>
          <field>
            <name>RWU</name>
            <bitOffset>1</bitOffset>
            <bitWidth>1</bitWidth>
          </field>
          <field>
            <name>RE</name>
            <bitOffset>2</bitOffset>
            <bitWidth>1</bitWidth>
          </field>
          <field>
            <name>TE</name>
            <bitOffset>3</bitOffset>
            <bitWidth>1</bitWidth>
          </field>
          <field>
            <name>IDLEIE</name>
            <bitOffset>4</bitOffset>
            <bitWidth>1</bitWidth>
          </field>
          <field>
            <name>RXNEIE</name>
            <bitOffset>5</bitOffset>
            <bitWidth>1</bitWidth>
          </field>
          <field>
            <name>TCIE</name>
            <bitOffset>6</bitOffset>
            <bitWidth>1</bitWidth>
          </field>
          <field>
            <name>TXEIE</name>
            <bitOffset>7</bitOffset>
            <bitWidth>1</bitWidth>
          </field>
          <field>
            <name>PEIE</name>
            <bitOffset>8</bitOffset>
            <bitWidth>1</bitWidth>
          </field>
          <field>
            <name>PS</name>
            <bitOffset>9</bitOffset>
            <bitWidth>1</bitWidth>
          </field>
          <field>
            <name>PCE</name>
            <bitOffset>10</bitOffset>
            <bitWidth>1</bitWidth>
          </field>
          <field>
            <name>WAKE</name>
            <bitOffset>11</bitOffset>
            <bitWidth>1</bitWidth>
          </field>
          <field>
            <name>M</name>
            <bitOffset>12</bitOffset>
            <bitWidth>1</bitWidth>
          </field>
          <field>
            <name>UE</name>
            <bitOffset>13</bitOffset>
            <bitWidth>1</bitWidth>
          </field>
        </fields>
      </register>
      <register>
        <name>CR2</name>
        <addressOffset>0x10</addressOffset>
        <size>0x20</size>
        <fields>
          <field>
            <name>ADD</name>
            <bitOffset>0</bitOffset>
            <bitWidth>4</bitWidth>
          </field>
          <field>
            <name>LBDL</name>
            <bitOffset>5</bitOffset>
            <bitWidth>1</bitWidth>
          </field>
          <field>
            <name>LBDIE</name>
            <bitOffset>6</bitOffset>
            <bitWidth>1</bitWidth>
          </field>
          <field>
            <name>LBCL</name>
            <bitOffset>8</bitOffset>
            <bitWidth>1</bitWidth>
          </field>
          <field>
            <name>CPHA</name>
            <bitOffset>9</bitOffset>
            <bitWidth>1</bitWidth>
          </field>
          <field>
            <name>CPOL</name>
            <bitOffset>10</bitOffset>
            <bitWidth>1</bitWidth>
          </field>
          <field>
            <name>CLKEN</name>
            <bitOffset>11</bitOffset>
            <bitWidth>1</bitWidth>
          </field>
          <field>
            <name>STOP</name>
            <bitOffset>12</bitOffset>
            <bitWidth>2</bitWidth>
          </field>
          <field>
            <name>LINEN</name>
            <bitOffset>14</bitOffset>
            <bitWidth>1</bitWidth>
          </field>
        </fields>
      </register>
      <register>
        <name>CR3</name>
        <addressOffset>0x14</addressOffset>
        <size>0x20</size>
        <fields>
          <field>
            <name>EIE</name>
            <bitOffset>0</bitOffset>
            <bitWidth>1</bitWidth>
          </field>
          <field>
            <name>IREN</name>
            <bitOffset>1</bitOffset>
            <bitWidth>1</bitWidth>
          </field>
          <field>
            <name>IRLP</name>
            <bitOffset>2</bitOffset>
            <bitWidth>1</bitWidth>
          </field>
          <field>
            <name>HDSEL</name>
            <bitOffset>3</bitOffset>
            <bitWidth>1</bitWidth>
          </field>
          <field>
            <name>NACK</name>
            <bitOffset>4</bitOffset>
            <bitWidth>1</bitWidth>
          </field>
          <field>
            <name>SCEN</name>
            <bitOffset>5</bitOffset>
            <bitWidth>1</bitWidth>
          </field>
          <field>
            <name>DMAR</name>
            <bitOffset>6</bitOffset>
            <bitWidth>1</bitWidth>
          </field>
          <field>
            <name>DMAT</name>
            <bitOffset>7</bitOffset>
            <bitWidth>1</bitWidth>
          </field>
          <field>
            <name>RTSE</name>
            <bitOffset>8</bitOffset>
            <bitWidth>1</bitWidth>
          </field>
          <field>
            <name>CTSE</name>
            <bitOffset>9</bitOffset>
            <bitWidth>1</bitWidth>
          </field>
          <field>
            <name>CTSIE</name>
            <bitOffset>10</bitOffset>
            <bitWidth>1</bitWidth>
          </field>
        </fields>
      </register>
      <register>
        <name>GTPR</name>
        <addressOffset>0x18</addressOffset>
        <size>0x20</size>
        <fields>
          <field>
            <name>PSC</name>
            <bitOffset>0</bitOffset>
            <bitWidth>8</bitWidth>
          </field>
          <field>
            <name>GT</name>
            <bitOffset>8</bitOffset>
            <bitWidth>8</bitWidth>
          </field>
        </fields>
      </register>
    </peripheral>
    <peripheral>
      <name>DMA1</name>
      <baseAddress>0x40020000</baseAddress>
      <register>
        <name>ISR</name>
        <addressOffset>0x0</addressOffset>
        <size>0x20</size>
        <fields>
          <field>
            <name>GIF1</name>
            <bitOffset>0</bitOffset>
            <bitWidth>1</bitWidth>
          </field>
          <field>
            <name>TCIF1</name>
            <bitOffset>1</bitOffset>
            <bitWidth>1</bitWidth>
          </field>
          <field>
            <name>HTIF1</name>
            <bitOffset>2</bitOffset>
            <bitWidth>1</bitWidth>
          </field>
          <field>
            <name>TEIF1</name>
            <bitOffset>3</bitOffset>
            <bitWidth>1</bitWidth>
          </field>
          <field>
            <name>GIF2</name>
            <bitOffset>4</bitOffset>
            <bitWidth>1</bitWidth>
          </field>
          <field>
            <name>TCIF2</name>
            <bitOffset>5</bitOffset>
            <bitWidth>1</bitWidth>
          </field>
          <field>
            <name>HTIF2</name>
            <bitOffset>6</bitOffset>
            <bitWidth>1</bitWidth>
          </field>
          <field>
            <name>TEIF2</name>
            <bitOffset>7</bitOffset>
            <bitWidth>1</bitWidth>
          </field>
          <field>
            <name>GIF3</name>
            <bitOffset>8</bitOffset>
            <bitWidth>1</bitWidth>
          </field>
          <field>
            <name>TCIF3</name>
            <bitOffset>9</bitOffset>
            <bitWidth>1</bitWidth>
          </field>
          <field>
            <name>HTIF3</name>
            <bitOffset>10</bitOffset>
            <bitWidth>1</bitWidth>
          </field>
          <field>
            <name>TEIF3</name>
            <bitOffset>11</bitOffset>
            <bitWidth>1</bitWidth>
          </field>
          <field>
            <name>GIF4</name>
            <bitOffset>12</bitOffset>
            <bitWidth>1</bitWidth>
          </field>
          <field>
            <name>TCIF4</name>
            <bitOffset>13</bitOffset>
            <bitWidth>1</bitWidth>
          </field>
          <field>
            <name>HTIF4</name>
            <bitOffset>14</bitOffset>
            <bitWidth>1</bitWidth>
          </field>
          <field>
            <name>TEIF4</name>
            <bitOffset>15</bitOffset>
            <bitWidth>1</bitWidth>
          </field>
          <field>
            <name>GIF5</name>
            <bitOffset>16</bitOffset>
            <bitWidth>1</bitWidth>
          </field>
          <field>
            <name>TCIF5</name>
            <bitOffset>17</bitOffset>
            <bitWidth>1</bitWidth>
          </field>
          <field>
            <name>HTIF5</name>
            <bitOffset>18</bitOffset>
            <bitWidth>1</bitWidth>
          </field>
          <field>
            <name>TEIF5</name>
            <bitOffset>19</bitOffset>
            <bitWidth>1</bitWidth>
          </field>
          <field>
            <name>GIF6</name>
            <bitOffset>20</bitOffset>
            <bitWidth>1</bitWidth>
          </field>
          <field>
            <name>TCIF6</name>
            <bitOffset>21</bitOffset>
            <bitWidth>1</bitWidth>
          </field>
          <field>
            <name>HTIF6</name>
            <bitOffset>22</bitOffset>
            <bitWidth>1</bitWidth>
          </field>
          <field>
            <name>TEIF6</name>
            <bitOffset>23</bitOffset>
            <bitWidth>1</bitWidth>
          </field>
          <field>
            <name>GIF7</name>
            <bitOffset>24</bitOffset>
            <bitWidth>1</bitWidth>
          </field>
          <field>
            <name>TCIF7</name>
            <bitOffset>25</bitOffset>
            <bitWidth>1</bitWidth>
          </field>
          <field>
            <name>HTIF7</name>
            <bitOffset>26</bitOffset>
            <bitWidth>1</bitWidth>
          </field>
          <field>
            <name>TEIF7</name>
            <bitOffset>27</bitOffset>
            <bitWidth>1</bitWidth>
          </field>
        </fields>
      </register>
      <register>
        <name>IFCR</name>
        <addressOffset>0x4</addressOffset>
        <size>0x20</size>
        <fields>
          <field>
            <name>CGIF1</name>
            <bitOffset>0</bitOffset>
            <bitWidth>1</bitWidth>
          </field>
          <field>
            <name>CTCIF1</name>
            <bitOffset>1</bitOffset>
            <bitWidth>1</bitWidth>
          </field>
          <field>
            <name>CHTIF1</name>
            <bitOffset>2</bitOffset>
            <bitWidth>1</bitWidth>
          </field>
          <field>
            <name>CTEIF1</name>
            <bitOffset>3</bitOffset>
            <bitWidth>1</bitWidth>
          </field>
          <field>
            <name>CGIF2</name>
            <bitOffset>4</bitOffset>
            <bitWidth>1</bitWidth>
          </field>
          <field>
            <name>CTCIF2</name>
            <bitOffset>5</bitOffset>
            <bitWidth>1</bitWidth>
          </field>
          <field>
            <name>CHTIF2</name>
            <bitOffset>6</bitOffset>
            <bitWidth>1</bitWidth>
          </field>
          <field>
            <name>CTEIF2</name>
            <bitOffset>7</bitOffset>
            <bitWidth>1</bitWidth>
          </field>
          <field>
            <name>CGIF3</name>
            <bitOffset>8</bitOffset>
            <bitWidth>1</bitWidth>
          </field>
          <field>
            <name>CTCIF3</name>
            <bitOffset>9</bitOffset>
            <bitWidth>1</bitWidth>
          </field>
          <field>
            <name>CHTIF3</name>
            <bitOffset>10</bitOffset>
            <bitWidth>1</bitWidth>
          </field>
          <field>
            <name>CTEIF3</name>
            <bitOffset>11</bitOffset>
            <bitWidth>1</bitWidth>
          </field>
          <field>
            <name>CGIF4</name>
            <bitOffset>12</bitOffset>
            <bitWidth>1</bitWidth>
          </field>
          <field>
            <name>CTCIF4</name>
            <bitOffset>13</bitOffset>
            <bitWidth>1</bitWidth>
          </field>
          <field>
            <name>CHTIF4</name>
            <bitOffset>14</bitOffset>
            <bitWidth>1</bitWidth>
          </field>
          <field>
            <name>CTEIF4</name>
            <bitOffset>15</bitOffset>
            <bitWidth>1</bitWidth>
          </field>
          <field>
            <name>CGIF5</name>
            <bitOffset>16</bitOffset>
            <bitWidth>1</bitWidth>
          </field>
          <field>
            <name>CTCIF5</name>
            <bitOffset>17</bitOffset>
            <bitWidth>1</bitWidth>
          </field>
          <field>
            <name>CHTIF5</name>
            <bitOffset>18</bitOffset>
            <bitWidth>1</bitWidth>
          </field>
          <field>
            <name>CTEIF5</name>
            <bitOffset>19</bitOffset>
            <bitWidth>1</bitWidth>
          </field>
          <field>
            <name>CGIF6</name>
            <bitOffset>20</bitOffset>
            <bitWidth>1</bitWidth>
          </field>
          <field>
            <name>CTCIF6</name>
            <bitOffset>21</bitOffset>
            <bitWidth>1</bitWidth>
          </field>
          <field>
            <name>CHTIF6</name>
            <bitOffset>22</bitOffset>
            <bitWidth>1</bitWidth>
          </field>
          <field>
            <name>CTEIF6</name>
            <bitOffset>23</bitOffset>
            <bitWidth>1</bitWidth>
          </field>
          <field>
            <name>CGIF7</name>
            <bitOffset>24</bitOffset>
            <bitWidth>1</bitWidth>
          </field>
          <field>
            <name>CTCIF7</name>
            <bitOffset>25</bitOffset>
            <bitWidth>1</bitWidth>
          </field>
          <field>
            <name>CHTIF7</name>
            <bitOffset>26</bitOffset>
            <bitWidth>1</bitWidth>
          </field>
          <field>
            <name>CTEIF7</name>
            <bitOffset>27</bitOffset>
            <bitWidth>1</bitWidth>
          </field>
        </fields>
      </register>
      <register>
        <name>CCR1</name>
        <addressOffset>0x8</addressOffset>
        <size>0x20</size>
        <fields>
          <field>
            <name>EN</name>
            <bitOffset>0</bitOffset>
            <bitWidth>1</bitWidth>
          </field>
          <field>
            <name>TCIE</name>
            <bitOffset>1</bitOffset>
            <bitWidth>1</bitWidth>
          </field>
          <field>
            <name>HTIE</name>
            <bitOffset>2</bitOffset>
            <bitWidth>1</bitWidth>
          </field>
          <field>
            <name>TEIE</name>
            <bitOffset>3</bitOffset>
            <bitWidth>1</bitWidth>
          </field>
          <field>
            <name>DIR</name>
            <bitOffset>4</bitOffset>
            <bitWidth>1</bitWidth>
          </field>
          <field>
            <name>CIRC</name>
            <bitOffset>5</bitOffset>
            <bitWidth>1</bitWidth>
          </field>
          <field>
            <name>PINC</name>
            <bitOffset>6</bitOffset>
            <bitWidth>1</bitWidth>
          </field>
          <field>
            <name>MINC</name>
            <bitOffset>7</bitOffset>
            <bitWidth>1</bitWidth>
          </field>
          <field>
            <name>PSIZE</name>
            <bitOffset>8</bitOffset>
            <bitWidth>2</bitWidth>
          </field>
          <field>
            <name>MSIZE</name>
            <bitOffset>10</bitOffset>
            <bitWidth>2</bitWidth>
          </field>
          <field>
            <name>PL</name>
            <bitOffset>12</bitOffset>
            <bitWidth>2</bitWidth>
          </field>
          <field>
            <name>MEM2MEM</name>
            <bitOffset>14</bitOffset>
            <bitWidth>1</bitWidth>
          </field>
        </fields>
      </register>
      <register>
        <name>CNDTR1</name>
        <addressOffset>0xc</addressOffset>
        <size>0x20</size>
        <fields>
          <field>
            <name>NDT</name>
            <bitOffset>0</bitOffset>
            <bitWidth>16</bitWidth>
          </field>
        </fields>
      </register>
      <register>
        <name>CPAR1</name>
        <addressOffset>0x14</addressOffset>
        <size>0x20</size>
        <fields>
          <field>
            <name>PA</name>
            <bitOffset>0</bitOffset>
            <bitWidth>32</bitWidth>
          </field>
        </fields>
      </register>
      <register>
        <name>CCR2</name>
        <addressOffset>0x1c</addressOffset>
        <size>0x20</size>
        <fields>
          <field>
            <name>EN</name>
            <bitOffset>0</bitOffset>
            <bitWidth>1</bitWidth>
          </field>
          <field>
            <name>TCIE</name>
            <bitOffset>1</bitOffset>
            <bitWidth>1</bitWidth>
          </field>
          <field>
            <name>HTIE</name>
            <bitOffset>2</bitOffset>
            <bitWidth>1</bitWidth>
          </field>
          <field>
            <name>TEIE</name>
            <bitOffset>3</bitOffset>
            <bitWidth>1</bitWidth>
          </field>
          <field>
            <name>DIR</name>
            <bitOffset>4</bitOffset>
            <bitWidth>1</bitWidth>
          </field>
          <field>
            <name>CIRC</name>
            <bitOffset>5</bitOffset>
            <bitWidth>1</bitWidth>
          </field>
          <field>
            <name>PINC</name>
            <bitOffset>6</bitOffset>
            <bitWidth>1</bitWidth>
          </field>
          <field>
            <name>MINC</name>
            <bitOffset>7</bitOffset>
            <bitWidth>1</bitWidth>
          </field>
          <field>
            <name>PSIZE</name>
            <bitOffset>8</bitOffset>
            <bitWidth>2</bitWidth>
          </field>
          <field>
            <name>MSIZE</name>
            <bitOffset>10</bitOffset>
            <bitWidth>2</bitWidth>
          </field>
          <field>
            <name>PL</name>
            <bitOffset>12</bitOffset>
            <bitWidth>2</bitWidth>
          </field>
          <field>
            <name>MEM2MEM</name>
            <bitOffset>14</bitOffset>
            <bitWidth>1</bitWidth>
          </field>
        </fields>
      </register>
      <register>
        <name>CMAR1</name>
        <addressOffset>0x20</addressOffset>
        <size>0x20</size>
        <fields>
          <field>
            <name>MA</name>
            <bitOffset>0</bitOffset>
            <bitWidth>32</bitWidth>
          </field>
        </fields>
      </register>
      <register>
        <name>CNDTR2</name>
        <addressOffset>0x20</addressOffset>
        <size>0x20</size>
        <fields>
          <field>
            <name>NDT</name>
            <bitOffset>0</bitOffset>
            <bitWidth>16</bitWidth>
          </field>
        </fields>
      </register>
      <register>
        <name>CPAR2</name>
        <addressOffset>0x28</addressOffset>
        <size>0x20</size>
        <fields>
          <field>
            <name>PA</name>
            <bitOffset>0</bitOffset>
            <bitWidth>32</bitWidth>
          </field>
        </fields>
      </register>
      <register>
        <name>CCR3</name>
        <addressOffset>0x30</addressOffset>
        <size>0x20</size>
        <fields>
          <field>
            <name>EN</name>
            <bitOffset>0</bitOffset>
            <bitWidth>1</bitWidth>
          </field>
          <field>
            <name>TCIE</name>
            <bitOffset>1</bitOffset>
            <bitWidth>1</bitWidth>
          </field>
          <field>
            <name>HTIE</name>
            <bitOffset>2</bitOffset>
            <bitWidth>1</bitWidth>
          </field>
          <field>
            <name>TEIE</name>
            <bitOffset>3</bitOffset>
            <bitWidth>1</bitWidth>
          </field>
          <field>
            <name>DIR</name>
            <bitOffset>4</bitOffset>
            <bitWidth>1</bitWidth>
          </field>
          <field>
            <name>CIRC</name>
            <bitOffset>5</bitOffset>
            <bitWidth>1</bitWidth>
          </field>
          <field>
            <name>PINC</name>
            <bitOffset>6</bitOffset>
            <bitWidth>1</bitWidth>
          </field>
          <field>
            <name>MINC</name>
            <bitOffset>7</bitOffset>
            <bitWidth>1</bitWidth>
          </field>
          <field>
            <name>PSIZE</name>
            <bitOffset>8</bitOffset>
            <bitWidth>2</bitWidth>
          </field>
          <field>
            <name>MSIZE</name>
            <bitOffset>10</bitOffset>
            <bitWidth>2</bitWidth>
          </field>
          <field>
            <name>PL</name>
            <bitOffset>12</bitOffset>
            <bitWidth>2</bitWidth>
          </field>
          <field>
            <name>MEM2MEM</name>
            <bitOffset>14</bitOffset>
            <bitWidth>1</bitWidth>
          </field>
        </fields>
      </register>
      <register>
        <name>CMAR2</name>
        <addressOffset>0x34</addressOffset>
        <size>0x20</size>
        <fields>
          <field>
            <name>MA</name>
            <bitOffset>0</bitOffset>
            <bitWidth>32</bitWidth>
          </field>
        </fields>
      </register>
      <register>
        <name>CNDTR3</name>
        <addressOffset>0x34</addressOffset>
        <size>0x20</size>
        <fields>
          <field>
            <name>NDT</name>
            <bitOffset>0</bitOffset>
            <bitWidth>16</bitWidth>
          </field>
        </fields>
      </register>
      <register>
        <name>CPAR3</name>
        <addressOffset>0x3c</addressOffset>
        <size>0x20</size>
        <fields>
          <field>
            <name>PA</name>
            <bitOffset>0</bitOffset>
            <bitWidth>32</bitWidth>
          </field>
        </fields>
      </register>
      <register>
        <name>CCR4</name>
        <addressOffset>0x44</addressOffset>
        <size>0x20</size>
        <fields>
          <field>
            <name>EN</name>
            <bitOffset>0</bitOffset>
            <bitWidth>1</bitWidth>
          </field>
          <field>
            <name>TCIE</name>
            <bitOffset>1</bitOffset>
            <bitWidth>1</bitWidth>
          </field>
          <field>
            <name>HTIE</name>
            <bitOffset>2</bitOffset>
            <bitWidth>1</bitWidth>
          </field>
          <field>
            <name>TEIE</name>
            <bitOffset>3</bitOffset>
            <bitWidth>1</bitWidth>
          </field>
          <field>
            <name>DIR</name>
            <bitOffset>4</bitOffset>
            <bitWidth>1</bitWidth>
          </field>
          <field>
            <name>CIRC</name>
            <bitOffset>5</bitOffset>
            <bitWidth>1</bitWidth>
          </field>
          <field>
            <name>PINC</name>
            <bitOffset>6</bitOffset>
            <bitWidth>1</bitWidth>
          </field>
          <field>
            <name>MINC</name>
            <bitOffset>7</bitOffset>
            <bitWidth>1</bitWidth>
          </field>
          <field>
            <name>PSIZE</name>
            <bitOffset>8</bitOffset>
            <bitWidth>2</bitWidth>
          </field>
          <field>
            <name>MSIZE</name>
            <bitOffset>10</bitOffset>
            <bitWidth>2</bitWidth>
          </field>
          <field>
            <name>PL</name>
            <bitOffset>12</bitOffset>
            <bitWidth>2</bitWidth>
          </field>
          <field>
            <name>MEM2MEM</name>
            <bitOffset>14</bitOffset>
            <bitWidth>1</bitWidth>
          </field>
        </fields>
      </register>
      <register>
        <name>CMAR3</name>
        <addressOffset>0x48</addressOffset>
        <size>0x20</size>
        <fields>
          <field>
            <name>MA</name>
            <bitOffset>0</bitOffset>
            <bitWidth>32</bitWidth>
          </field>
        </fields>
      </register>
      <register>
        <name>CNDTR4</name>
        <addressOffset>0x48</addressOffset>
        <size>0x20</size>
        <fields>
          <field>
            <name>NDT</name>
            <bitOffset>0</bitOffset>
            <bitWidth>16</bitWidth>
          </field>
        </fields>
      </register>
      <register>
        <name>CPAR4</name>
        <addressOffset>0x50</addressOffset>
        <size>0x20</size>
        <fields>
          <field>
            <name>PA</name>
            <bitOffset>0</bitOffset>
            <bitWidth>32</bitWidth>
          </field>
        </fields>
      </register>
      <register>
        <name>CCR5</name>
        <addressOffset>0x58</addressOffset>
        <size>0x20</size>
        <fields>
          <field>
            <name>EN</name>
            <bitOffset>0</bitOffset>
            <bitWidth>1</bitWidth>
          </field>
          <field>
            <name>TCIE</name>
            <bitOffset>1</bitOffset>
            <bitWidth>1</bitWidth>
          </field>
          <field>
            <name>HTIE</name>
            <bitOffset>2</bitOffset>
            <bitWidth>1</bitWidth>
          </field>
          <field>
            <name>TEIE</name>
            <bitOffset>3</bitOffset>
            <bitWidth>1</bitWidth>
          </field>
          <field>
            <name>DIR</name>
            <bitOffset>4</bitOffset>
            <bitWidth>1</bitWidth>
          </field>
          <field>
            <name>CIRC</name>
            <bitOffset>5</bitOffset>
            <bitWidth>1</bitWidth>
          </field>
          <field>
            <name>PINC</name>
            <bitOffset>6</bitOffset>
            <bitWidth>1</bitWidth>
          </field>
          <field>
            <name>MINC</name>
            <bitOffset>7</bitOffset>
            <bitWidth>1</bitWidth>
          </field>
          <field>
            <name>PSIZE</name>
            <bitOffset>8</bitOffset>
            <bitWidth>2</bitWidth>
          </field>
          <field>
            <name>MSIZE</name>
            <bitOffset>10</bitOffset>
            <bitWidth>2</bitWidth>
          </field>
          <field>
            <name>PL</name>
            <bitOffset>12</bitOffset>
            <bitWidth>2</bitWidth>
          </field>
          <field>
            <name>MEM2MEM</name>
            <bitOffset>14</bitOffset>
            <bitWidth>1</bitWidth>
          </field>
        </fields>
      </register>
      <register>
        <name>CMAR4</name>
        <addressOffset>0x5c</addressOffset>
        <size>0x20</size>
        <fields>
          <field>
            <name>MA</name>
            <bitOffset>0</bitOffset>
            <bitWidth>32</bitWidth>
          </field>
        </fields>
      </register>
      <register>
        <name>CNDTR5</name>
        <addressOffset>0x5c</addressOffset>
        <size>0x20</size>
        <fields>
          <field>
            <name>NDT</name>
            <bitOffset>0</bitOffset>
            <bitWidth>16</bitWidth>
          </field>
        </fields>
      </register>
      <register>
        <name>CPAR5</name>
        <addressOffset>0x64</addressOffset>
        <size>0x20</size>
        <fields>
          <field>
            <name>PA</name>
            <bitOffset>0</bitOffset>
            <bitWidth>32</bitWidth>
          </field>
        </fields>
      </register>
      <register>
        <name>CCR6</name>
        <addressOffset>0x6c</addressOffset>
        <size>0x20</size>
        <fields>
          <field>
            <name>EN</name>
            <bitOffset>0</bitOffset>
            <bitWidth>1</bitWidth>
          </field>
          <field>
            <name>TCIE</name>
            <bitOffset>1</bitOffset>
            <bitWidth>1</bitWidth>
          </field>
          <field>
            <name>HTIE</name>
            <bitOffset>2</bitOffset>
            <bitWidth>1</bitWidth>
          </field>
          <field>
            <name>TEIE</name>
            <bitOffset>3</bitOffset>
            <bitWidth>1</bitWidth>
          </field>
          <field>
            <name>DIR</name>
            <bitOffset>4</bitOffset>
            <bitWidth>1</bitWidth>
          </field>
          <field>
            <name>CIRC</name>
            <bitOffset>5</bitOffset>
            <bitWidth>1</bitWidth>
          </field>
          <field>
            <name>PINC</name>
            <bitOffset>6</bitOffset>
            <bitWidth>1</bitWidth>
          </field>
          <field>
            <name>MINC</name>
            <bitOffset>7</bitOffset>
            <bitWidth>1</bitWidth>
          </field>
          <field>
            <name>PSIZE</name>
            <bitOffset>8</bitOffset>
            <bitWidth>2</bitWidth>
          </field>
          <field>
            <name>MSIZE</name>
            <bitOffset>10</bitOffset>
            <bitWidth>2</bitWidth>
          </field>
          <field>
            <name>PL</name>
            <bitOffset>12</bitOffset>
            <bitWidth>2</bitWidth>
          </field>
          <field>
            <name>MEM2MEM</name>
            <bitOffset>14</bitOffset>
            <bitWidth>1</bitWidth>
          </field>
        </fields>
      </register>
      <register>
        <name>CMAR5</name>
        <addressOffset>0x70</addressOffset>
        <size>0x20</size>
        <fields>
          <field>
            <name>MA</name>
            <bitOffset>0</bitOffset>
            <bitWidth>32</bitWidth>
          </field>
        </fields>
      </register>
      <register>
        <name>CNDTR6</name>
        <addressOffset>0x70</addressOffset>
        <size>0x20</size>
        <fields>
          <field>
            <name>NDT</name>
            <bitOffset>0</bitOffset>
            <bitWidth>16</bitWidth>
          </field>
        </fields>
      </register>
      <register>
        <name>CPAR6</name>
        <addressOffset>0x78</addressOffset>
        <size>0x20</size>
        <fields>
          <field>
            <name>PA</name>
            <bitOffset>0</bitOffset>
            <bitWidth>32</bitWidth>
          </field>
        </fields>
      </register>
      <register>
        <name>CCR7</name>
        <addressOffset>0x80</addressOffset>
        <size>0x20</size>
        <fields>
          <field>
            <name>EN</name>
            <bitOffset>0</bitOffset>
            <bitWidth>1</bitWidth>
          </field>
          <field>
            <name>TCIE</name>
            <bitOffset>1</bitOffset>
            <bitWidth>1</bitWidth>
          </field>
          <field>
            <name>HTIE</name>
            <bitOffset>2</bitOffset>
            <bitWidth>1</bitWidth>
          </field>
          <field>
            <name>TEIE</name>
            <bitOffset>3</bitOffset>
            <bitWidth>1</bitWidth>
          </field>
          <field>
            <name>DIR</name>
            <bitOffset>4</bitOffset>
            <bitWidth>1</bitWidth>
          </field>
          <field>
            <name>CIRC</name>
            <bitOffset>5</bitOffset>
            <bitWidth>1</bitWidth>
          </field>
          <field>
            <name>PINC</name>
            <bitOffset>6</bitOffset>
            <bitWidth>1</bitWidth>
          </field>
          <field>
            <name>MINC</name>
            <bitOffset>7</bitOffset>
            <bitWidth>1</bitWidth>
          </field>
          <field>
            <name>PSIZE</name>
            <bitOffset>8</bitOffset>
            <bitWidth>2</bitWidth>
          </field>
          <field>
            <name>MSIZE</name>
            <bitOffset>10</bitOffset>
            <bitWidth>2</bitWidth>
          </field>
          <field>
            <name>PL</name>
            <bitOffset>12</bitOffset>
            <bitWidth>2</bitWidth>
          </field>
          <field>
            <name>MEM2MEM</name>
            <bitOffset>14</bitOffset>
            <bitWidth>1</bitWidth>
          </field>
        </fields>
      </register>
      <register>
        <name>CMAR6</name>
        <addressOffset>0x84</addressOffset>
        <size>0x20</size>
        <fields>
          <field>
            <name>MA</name>
            <bitOffset>0</bitOffset>
            <bitWidth>32</bitWidth>
          </field>
        </fields>
      </register>
      <register>
        <name>CNDTR7</name>
        <addressOffset>0x84</addressOffset>
        <size>0x20</size>
        <fields>
          <field>
            <name>NDT</name>
            <bitOffset>0</bitOffset>
            <bitWidth>16</bitWidth>
          </field>
        </fields>
      </register>
      <register>
        <name>CPAR7</name>
        <addressOffset>0x8c</addressOffset>
        <size>0x20</size>
        <fields>
          <field>
            <name>PA</name>
            <bitOffset>0</bitOffset>
            <bitWidth>32</bitWidth>
          </field>
        </fields>
      </register>
      <register>
        <name>CMAR7</name>
        <addressOffset>0x98</addressOffset>
        <size>0x20</size>
        <fields>
          <field>
            <name>MA</name>
            <bitOffset>0</bitOffset>
            <bitWidth>32</bitWidth>
          </field>
        </fields>
      </register>
    </peripheral>
    <peripheral>
      <name>RCC</name>
      <baseAddress>0x40021000</baseAddress>
      <register>
        <name>CR</name>
        <addressOffset>0x0</addressOffset>
        <size>0x20</size>
        <fields>
          <field>
            <name>HSION</name>
            <bitOffset>0</bitOffset>
            <bitWidth>1</bitWidth>
          </field>
          <field>
            <name>HSIRDY</name>
            <bitOffset>1</bitOffset>
            <bitWidth>1</bitWidth>
          </field>
          <field>
            <name>HSITRIM</name>
            <bitOffset>3</bitOffset>
            <bitWidth>5</bitWidth>
          </field>
          <field>
            <name>HSICAL</name>
            <bitOffset>8</bitOffset>
            <bitWidth>8</bitWidth>
          </field>
          <field>
            <name>HSEON</name>
            <bitOffset>16</bitOffset>
            <bitWidth>1</bitWidth>
          </field>
          <field>
            <name>HSERDY</name>
            <bitOffset>17</bitOffset>
            <bitWidth>1</bitWidth>
          </field>
          <field>
            <name>HSEBYP</name>
            <bitOffset>18</bitOffset>
            <bitWidth>1</bitWidth>
          </field>
          <field>
            <name>CSSON</name>
            <bitOffset>19</bitOffset>
            <bitWidth>1</bitWidth>
          </field>
          <field>
            <name>PLLON</name>
            <bitOffset>24</bitOffset>
            <bitWidth>1</bitWidth>
          </field>
          <field>
            <name>PLLRDY</name>
            <bitOffset>25</bitOffset>
            <bitWidth>1</bitWidth>
          </field>
        </fields>
      </register>
      <register>
        <name>CFGR</name>
        <addressOffset>0x4</addressOffset>
        <size>0x20</size>
        <fields>
          <field>
            <name>SW</name>
            <bitOffset>0</bitOffset>
            <bitWidth>2</bitWidth>
          </field>
          <field>
            <name>SWS</name>
            <bitOffset>2</bitOffset>
            <bitWidth>2</bitWidth>
          </field>
          <field>
            <name>HPRE</name>
            <bitOffset>4</bitOffset>
            <bitWidth>4</bitWidth>
          </field>
          <field>
            <name>PPRE1</name>
            <bitOffset>8</bitOffset>
            <bitWidth>3</bitWidth>
          </field>
          <field>
            <name>PPRE2</name>
            <bitOffset>11</bitOffset>
            <bitWidth>3</bitWidth>
          </field>
          <field>
            <name>ADCPRE</name>
            <bitOffset>14</bitOffset>
            <bitWidth>2</bitWidth>
          </field>
          <field>
            <name>PLLSRC</name>
            <bitOffset>16</bitOffset>
            <bitWidth>1</bitWidth>
          </field>
          <field>
            <name>PLLXTPRE</name>
            <bitOffset>17</bitOffset>
            <bitWidth>1</bitWidth>
          </field>
          <field>
            <name>PLLMULL9</name>
            <bitOffset>18</bitOffset>
            <bitWidth>3</bitWidth>
          </field>
          <field>
            <name>PLLMULL8</name>
            <bitOffset>19</bitOffset>
            <bitWidth>2</bitWidth>
          </field>
          <field>
            <name>PLLMULL6</name>
            <bitOffset>20</bitOffset>
            <bitWidth>1</bitWidth>
          </field>
          <field>
            <name>PLLMULL10</name>
            <bitOffset>21</bitOffset>
            <bitWidth>1</bitWidth>
          </field>
          <field>
            <name>USBPRE</name>
            <bitOffset>22</bitOffset>
            <bitWidth>1</bitWidth>
          </field>
          <field>
            <name>MCO</name>
            <bitOffset>24</bitOffset>
            <bitWidth>3</bitWidth>
          </field>
        </fields>
      </register>
      <register>
        <name>CIR</name>
        <addressOffset>0x8</addressOffset>
        <size>0x20</size>
        <fields>
          <field>
            <name>LSIRDYF</name>
            <bitOffset>0</bitOffset>
            <bitWidth>1</bitWidth>
          </field>
          <field>
            <name>LSERDYF</name>
            <bitOffset>1</bitOffset>
            <bitWidth>1</bitWidth>
          </field>
          <field>
            <name>HSIRDYF</name>
            <bitOffset>2</bitOffset>
            <bitWidth>1</bitWidth>
          </field>
          <field>
            <name>HSERDYF</name>
            <bitOffset>3</bitOffset>
            <bitWidth>1</bitWidth>
          </field>
          <field>
            <name>PLLRDYF</name>
            <bitOffset>4</bitOffset>
            <bitWidth>1</bitWidth>
          </field>
          <field>
            <name>CSSF</name>
            <bitOffset>7</bitOffset>
            <bitWidth>1</bitWidth>
          </field>
          <field>
            <name>LSIRDYIE</name>
            <bitOffset>8</bitOffset>
            <bitWidth>1</bitWidth>
          </field>
          <field>
            <name>LSERDYIE</name>
            <bitOffset>9</bitOffset>
            <bitWidth>1</bitWidth>
          </field>
          <field>
            <name>HSIRDYIE</name>
            <bitOffset>10</bitOffset>
            <bitWidth>1</bitWidth>
          </field>
          <field>
            <name>HSERDYIE</name>
            <bitOffset>11</bitOffset>
            <bitWidth>1</bitWidth>
          </field>
          <field>
            <name>PLLRDYIE</name>
            <bitOffset>12</bitOffset>
            <bitWidth>1</bitWidth>
          </field>
          <field>
            <name>LSIRDYC</name>
            <bitOffset>16</bitOffset>
            <bitWidth>1</bitWidth>
          </field>
          <field>
            <name>LSERDYC</name>
            <bitOffset>17</bitOffset>
            <bitWidth>1</bitWidth>
          </field>
          <field>
            <name>HSIRDYC</name>
            <bitOffset>18</bitOffset>
            <bitWidth>1</bitWidth>
          </field>
          <field>
            <name>HSERDYC</name>
            <bitOffset>19</bitOffset>
            <bitWidth>1</bitWidth>
          </field>
          <field>
            <name>PLLRDYC</name>
            <bitOffset>20</bitOffset>
            <bitWidth>1</bitWidth>
          </field>
          <field>
            <name>CSSC</name>
            <bitOffset>23</bitOffset>
            <bitWidth>1</bitWidth>
          </field>
        </fields>
      </register>
      <register>
        <name>APB2RSTR</name>
        <addressOffset>0xc</addressOffset>
        <size>0x20</size>
        <fields>
          <field>
            <name>AFIORST</name>
            <bitOffset>0</bitOffset>
            <bitWidth>1</bitWidth>
          </field>
          <field>
            <name>IOPARST</name>
            <bitOffset>2</bitOffset>
            <bitWidth>1</bitWidth>
          </field>
          <field>
            <name>IOPBRST</name>
            <bitOffset>3</bitOffset>
            <bitWidth>1</bitWidth>
          </field>
          <field>
            <name>IOPCRST</name>
            <bitOffset>4</bitOffset>
            <bitWidth>1</bitWidth>
          </field>
          <field>
            <name>IOPDRST</name>
            <bitOffset>5</bitOffset>
            <bitWidth>1</bitWidth>
          </field>
          <field>
            <name>ADC1RST</name>
            <bitOffset>9</bitOffset>
            <bitWidth>1</bitWidth>
          </field>
          <field>
            <name>ADC2RST</name>
            <bitOffset>10</bitOffset>
            <bitWidth>1</bitWidth>
          </field>
          <field>
            <name>TIM1RST</name>
            <bitOffset>11</bitOffset>
            <bitWidth>1</bitWidth>
          </field>
          <field>
            <name>SPI1RST</name>
            <bitOffset>12</bitOffset>
            <bitWidth>1</bitWidth>
          </field>
          <field>
            <name>USART1RST</name>
            <bitOffset>14</bitOffset>
            <bitWidth>1</bitWidth>
          </field>
        </fields>
      </register>
      <register>
        <name>APB1RSTR</name>
        <addressOffset>0x10</addressOffset>
        <size>0x20</size>
        <fields>
          <field>
            <name>TIM2RST</name>
            <bitOffset>0</bitOffset>
            <bitWidth>1</bitWidth>
          </field>
          <field>
            <name>TIM3RST</name>
            <bitOffset>1</bitOffset>
            <bitWidth>1</bitWidth>
          </field>
          <field>
            <name>WWDGRST</name>
            <bitOffset>11</bitOffset>
            <bitWidth>1</bitWidth>
          </field>
          <field>
            <name>USART2RST</name>
            <bitOffset>17</bitOffset>
            <bitWidth>1</bitWidth>
          </field>
          <field>
            <name>I2C1RST</name>
            <bitOffset>21</bitOffset>
            <bitWidth>1</bitWidth>
          </field>
          <field>
            <name>USBRST</name>
            <bitOffset>23</bitOffset>
            <bitWidth>1</bitWidth>
          </field>
          <field>
            <name>CAN1RST</name>
            <bitOffset>25</bitOffset>
            <bitWidth>1</bitWidth>
          </field>
          <field>
            <name>BKPRST</name>
            <bitOffset>27</bitOffset>
            <bitWidth>1</bitWidth>
          </field>
          <field>
            <name>PWRRST</name>
            <bitOffset>28</bitOffset>
            <bitWidth>1</bitWidth>
          </field>
        </fields>
      </register>
      <register>
        <name>AHBENR</name>
        <addressOffset>0x14</addressOffset>
        <size>0x20</size>
        <fields>
          <field>
            <name>DMA1EN</name>
            <bitOffset>0</bitOffset>
            <bitWidth>1</bitWidth>
          </field>
          <field>
            <name>SRAMEN</name>
            <bitOffset>2</bitOffset>
            <bitWidth>1</bitWidth>
          </field>
          <field>
            <name>FLITFEN</name>
            <bitOffset>4</bitOffset>
            <bitWidth>1</bitWidth>
          </field>
          <field>
            <name>CRCEN</name>
            <bitOffset>6</bitOffset>
            <bitWidth>1</bitWidth>
          </field>
        </fields>
      </register>
      <register>
        <name>APB2ENR</name>
        <addressOffset>0x18</addressOffset>
        <size>0x20</size>
        <fields>
          <field>
            <name>AFIOEN</name>
            <bitOffset>0</bitOffset>
            <bitWidth>1</bitWidth>
          </field>
          <field>
            <name>IOPAEN</name>
            <bitOffset>2</bitOffset>
            <bitWidth>1</bitWidth>
          </field>
          <field>
            <name>IOPBEN</name>
            <bitOffset>3</bitOffset>
            <bitWidth>1</bitWidth>
          </field>
          <field>
            <name>IOPCEN</name>
            <bitOffset>4</bitOffset>
            <bitWidth>1</bitWidth>
          </field>
          <field>
            <name>IOPDEN</name>
            <bitOffset>5</bitOffset>
            <bitWidth>1</bitWidth>
          </field>
          <field>
            <name>ADC1EN</name>
            <bitOffset>9</bitOffset>
            <bitWidth>1</bitWidth>
          </field>
          <field>
            <name>ADC2EN</name>
            <bitOffset>10</bitOffset>
            <bitWidth>1</bitWidth>
          </field>
          <field>
            <name>TIM1EN</name>
            <bitOffset>11</bitOffset>
            <bitWidth>1</bitWidth>
          </field>
          <field>
            <name>SPI1EN</name>
            <bitOffset>12</bitOffset>
            <bitWidth>1</bitWidth>
          </field>
          <field>
            <name>USART1EN</name>
            <bitOffset>14</bitOffset>
            <bitWidth>1</bitWidth>
          </field>
        </fields>
      </register>
      <register>
        <name>APB1ENR</name>
        <addressOffset>0x1c</addressOffset>
        <size>0x20</size>
        <fields>
          <field>
            <name>TIM2EN</name>
            <bitOffset>0</bitOffset>
            <bitWidth>1</bitWidth>
          </field>
          <field>
            <name>TIM3EN</name>
            <bitOffset>1</bitOffset>
            <bitWidth>1</bitWidth>
          </field>
          <field>
            <name>WWDGEN</name>
            <bitOffset>11</bitOffset>
            <bitWidth>1</bitWidth>
          </field>
          <field>
            <name>USART2EN</name>
            <bitOffset>17</bitOffset>
            <bitWidth>1</bitWidth>
          </field>
          <field>
            <name>I2C1EN</name>
            <bitOffset>21</bitOffset>
            <bitWidth>1</bitWidth>
          </field>
          <field>
            <name>USBEN</name>
            <bitOffset>23</bitOffset>
            <bitWidth>1</bitWidth>
          </field>
          <field>
            <name>CAN1EN</name>
            <bitOffset>25</bitOffset>
            <bitWidth>1</bitWidth>
          </field>
          <field>
            <name>BKPEN</name>
            <bitOffset>27</bitOffset>
            <bitWidth>1</bitWidth>
          </field>
          <field>
            <name>PWREN</name>
            <bitOffset>28</bitOffset>
            <bitWidth>1</bitWidth>
          </field>
        </fields>
      </register>
      <register>
        <name>BDCR</name>
        <addressOffset>0x20</addressOffset>
        <size>0x20</size>
        <fields>
          <field>
            <name>LSEON</name>
            <bitOffset>0</bitOffset>
            <bitWidth>1</bitWidth>
          </field>
          <field>
            <name>LSERDY</name>
            <bitOffset>1</bitOffset>
            <bitWidth>1</bitWidth>
          </field>
          <field>
            <name>LSEBYP</name>
            <bitOffset>2</bitOffset>
            <bitWidth>1</bitWidth>
          </field>
          <field>
            <name>RTCSEL</name>
            <bitOffset>8</bitOffset>
            <bitWidth>2</bitWidth>
          </field>
          <field>
            <name>RTCEN</name>
            <bitOffset>15</bitOffset>
            <bitWidth>1</bitWidth>
          </field>
          <field>
            <name>BDRST</name>
            <bitOffset>16</bitOffset>
            <bitWidth>1</bitWidth>
          </field>
        </fields>
      </register>
      <register>
        <name>CSR</name>
        <addressOffset>0x24</addressOffset>
        <size>0x20</size>
        <fields>
          <field>
            <name>LSION</name>
            <bitOffset>0</bitOffset>
            <bitWidth>1</bitWidth>
          </field>
          <field>
            <name>LSIRDY</name>
            <bitOffset>1</bitOffset>
            <bitWidth>1</bitWidth>
          </field>
          <field>
            <name>RMVF</name>
            <bitOffset>24</bitOffset>
            <bitWidth>1</bitWidth>
          </field>
          <field>
            <name>PINRSTF</name>
            <bitOffset>26</bitOffset>
            <bitWidth>1</bitWidth>
          </field>
          <field>
            <name>PORRSTF</name>
            <bitOffset>27</bitOffset>
            <bitWidth>1</bitWidth>
          </field>
          <field>
            <name>SFTRSTF</name>
            <bitOffset>28</bitOffset>
            <bitWidth>1</bitWidth>
          </field>
          <field>
            <name>IWDGRSTF</name>
            <bitOffset>29</bitOffset>
            <bitWidth>1</bitWidth>
          </field>
          <field>
            <name>WWDGRSTF</name>
            <bitOffset>30</bitOffset>
            <bitWidth>1</bitWidth>
          </field>
          <field>
            <name>LPWRRSTF</name>
            <bitOffset>31</bitOffset>
            <bitWidth>1</bitWidth>
          </field>
        </fields>
      </register>
    </peripheral>
    <peripheral>
      <name>FLASH</name>
      <baseAddress>0x40022000</baseAddress>
      <register>
        <name>ACR</name>
        <addressOffset>0x0</addressOffset>
        <size>0x20</size>
        <fields>
          <field>
            <name>LATENCY</name>
            <bitOffset>0</bitOffset>
            <bitWidth>3</bitWidth>
          </field>
          <field>
            <name>HLFCYA</name>
            <bitOffset>3</bitOffset>
            <bitWidth>1</bitWidth>
          </field>
          <field>
            <name>PRFTBE</name>
            <bitOffset>4</bitOffset>
            <bitWidth>1</bitWidth>
          </field>
          <field>
            <name>PRFTBS</name>
            <bitOffset>5</bitOffset>
            <bitWidth>1</bitWidth>
          </field>
        </fields>
      </register>
      <register>
        <name>KEYR</name>
        <addressOffset>0x4</addressOffset>
        <size>0x20</size>
        <fields>
          <field>
            <name>FKEYR</name>
            <bitOffset>0</bitOffset>
            <bitWidth>32</bitWidth>
          </field>
        </fields>
      </register>
      <register>
        <name>OPTKEYR</name>
        <addressOffset>0x8</addressOffset>
        <size>0x20</size>
        <fields>
          <field>
            <name>OPTKEYR</name>
            <bitOffset>0</bitOffset>
            <bitWidth>32</bitWidth>
          </field>
        </fields>
      </register>
      <register>
        <name>SR</name>
        <addressOffset>0xc</addressOffset>
        <size>0x20</size>
        <fields>
          <field>
            <name>BSY</name>
            <bitOffset>0</bitOffset>
            <bitWidth>1</bitWidth>
          </field>
          <field>
            <name>PGERR</name>
            <bitOffset>2</bitOffset>
            <bitWidth>1</bitWidth>
          </field>
          <field>
            <name>WRPRTERR</name>
            <bitOffset>4</bitOffset>
            <bitWidth>1</bitWidth>
          </field>
          <field>
            <name>EOP</name>
            <bitOffset>5</bitOffset>
            <bitWidth>1</bitWidth>
          </field>
        </fields>
      </register>
      <register>
        <name>CR</name>
        <addressOffset>0x10</addressOffset>
        <size>0x20</size>
        <fields>
          <field>
            <name>PG</name>
            <bitOffset>0</bitOffset>
            <bitWidth>1</bitWidth>
          </field>
          <field>
            <name>PER</name>
            <bitOffset>1</bitOffset>
            <bitWidth>1</bitWidth>
          </field>
          <field>
            <name>MER</name>
            <bitOffset>2</bitOffset>
            <bitWidth>1</bitWidth>
          </field>
          <field>
            <name>OPTPG</name>
            <bitOffset>4</bitOffset>
            <bitWidth>1</bitWidth>
          </field>
          <field>
            <name>OPTER</name>
            <bitOffset>5</bitOffset>
            <bitWidth>1</bitWidth>
          </field>
          <field>
            <name>STRT</name>
            <bitOffset>6</bitOffset>
            <bitWidth>1</bitWidth>
          </field>
          <field>
            <name>LOCK</name>
            <bitOffset>7</bitOffset>
            <bitWidth>1</bitWidth>
          </field>
          <field>
            <name>OPTWRE</name>
            <bitOffset>9</bitOffset>
            <bitWidth>1</bitWidth>
          </field>
          <field>
            <name>ERRIE</name>
            <bitOffset>10</bitOffset>
            <bitWidth>1</bitWidth>
          </field>
          <field>
            <name>EOPIE</name>
            <bitOffset>12</bitOffset>
            <bitWidth>1</bitWidth>
          </field>
        </fields>
      </register>
      <register>
        <name>AR</name>
        <addressOffset>0x14</addressOffset>
        <size>0x20</size>
        <fields>
          <field>
            <name>FAR</name>
            <bitOffset>0</bitOffset>
            <bitWidth>32</bitWidth>
          </field>
        </fields>
      </register>
      <register>
        <name>OBR</name>
        <addressOffset>0x1c</addressOffset>
        <size>0x20</size>
        <fields>
          <field>
            <name>OPTERR</name>
            <bitOffset>0</bitOffset>
            <bitWidth>1</bitWidth>
          </field>
          <field>
            <name>RDPRT</name>
            <bitOffset>1</bitOffset>
            <bitWidth>1</bitWidth>
          </field>
          <field>
            <name>USER</name>
            <bitOffset>2</bitOffset>
            <bitWidth>3</bitWidth>
          </field>
          <field>
            <name>nRST_STOP</name>
            <bitOffset>3</bitOffset>
            <bitWidth>1</bitWidth>
          </field>
          <field>
            <name>nRST_STDBY</name>
            <bitOffset>4</bitOffset>
            <bitWidth>1</bitWidth>
          </field>
          <field>
            <name>DATA0</name>
            <bitOffset>10</bitOffset>
            <bitWidth>8</bitWidth>
          </field>
          <field>
            <name>DATA1</name>
            <bitOffset>18</bitOffset>
            <bitWidth>8</bitWidth>
          </field>
        </fields>
      </register>
      <register>
        <name>WRPR</name>
        <addressOffset>0x20</addressOffset>
        <size>0x20</size>
        <fields>
          <field>
            <name>WRP</name>
            <bitOffset>0</bitOffset>
            <bitWidth>32</bitWidth>
          </field>
        </fields>
      </register>
    </peripheral>
    <peripheral>
      <name>CRC</name>
      <baseAddress>0x40023000</baseAddress>
      <register>
        <name>DR</name>
        <addressOffset>0x0</addressOffset>
        <size>0x20</size>
        <fields>
          <field>
            <name>DR</name>
            <bitOffset>0</bitOffset>
            <bitWidth>32</bitWidth>
          </field>
        </fields>
      </register>
      <register>
        <name>IDR</name>
        <addressOffset>0x4</addressOffset>
        <size>0x8</size>
        <fields>
          <field>
            <name>IDR</name>
            <bitOffset>0</bitOffset>
            <bitWidth>8</bitWidth>
          </field>
        </fields>
      </register>
      <register>
        <name>CR</name>
        <addressOffset>0x8</addressOffset>
        <size>0x20</size>
        <fields>
          <field>
            <name>RESET</name>
            <bitOffset>0</bitOffset>
            <bitWidth>1</bitWidth>
          </field>
        </fields>
      </register>
    </peripheral>
    <peripheral>
      <name>DBGMCU</name>
      <baseAddress>0xe0042000</baseAddress>
      <register>
        <name>IDCODE</name>
        <addressOffset>0x0</addressOffset>
        <size>0x20</size>
        <fields>
          <field>
            <name>DEV_ID</name>
            <bitOffset>0</bitOffset>
            <bitWidth>12</bitWidth>
          </field>
          <field>
            <name>REV_ID</name>
            <bitOffset>16</bitOffset>
            <bitWidth>16</bitWidth>
          </field>
        </fields>
      </register>
      <register>
        <name>CR</name>
        <addressOffset>0x4</addressOffset>
        <size>0x20</size>
        <fields>
          <field>
            <name>DBG_SLEEP</name>
            <bitOffset>0</bitOffset>
            <bitWidth>1</bitWidth>
          </field>
          <field>
            <name>DBG_STOP</name>
            <bitOffset>1</bitOffset>
            <bitWidth>1</bitWidth>
          </field>
          <field>
            <name>DBG_STANDBY</name>
            <bitOffset>2</bitOffset>
            <bitWidth>1</bitWidth>
          </field>
          <field>
            <name>TRACE_IOEN</name>
            <bitOffset>5</bitOffset>
            <bitWidth>1</bitWidth>
          </field>
          <field>
            <name>TRACE_MODE</name>
            <bitOffset>6</bitOffset>
            <bitWidth>2</bitWidth>
          </field>
          <field>
            <name>DBG_IWDG_STOP</name>
            <bitOffset>8</bitOffset>
            <bitWidth>1</bitWidth>
          </field>
          <field>
            <name>DBG_WWDG_STOP</name>
            <bitOffset>9</bitOffset>
            <bitWidth>1</bitWidth>
          </field>
          <field>
            <name>DBG_TIM1_STOP</name>
            <bitOffset>10</bitOffset>
            <bitWidth>1</bitWidth>
          </field>
          <field>
            <name>DBG_TIM2_STOP</name>
            <bitOffset>11</bitOffset>
            <bitWidth>1</bitWidth>
          </field>
          <field>
            <name>DBG_TIM3_STOP</name>
            <bitOffset>12</bitOffset>
            <bitWidth>1</bitWidth>
          </field>
          <field>
            <name>DBG_CAN1_STOP</name>
            <bitOffset>14</bitOffset>
            <bitWidth>1</bitWidth>
          </field>
          <field>
            <name>DBG_I2C1_SMBUS_TIMEOUT</name>
            <bitOffset>15</bitOffset>
            <bitWidth>1</bitWidth>
          </field>
        </fields>
      </register>
    </peripheral>
  </peripherals>
</device>
